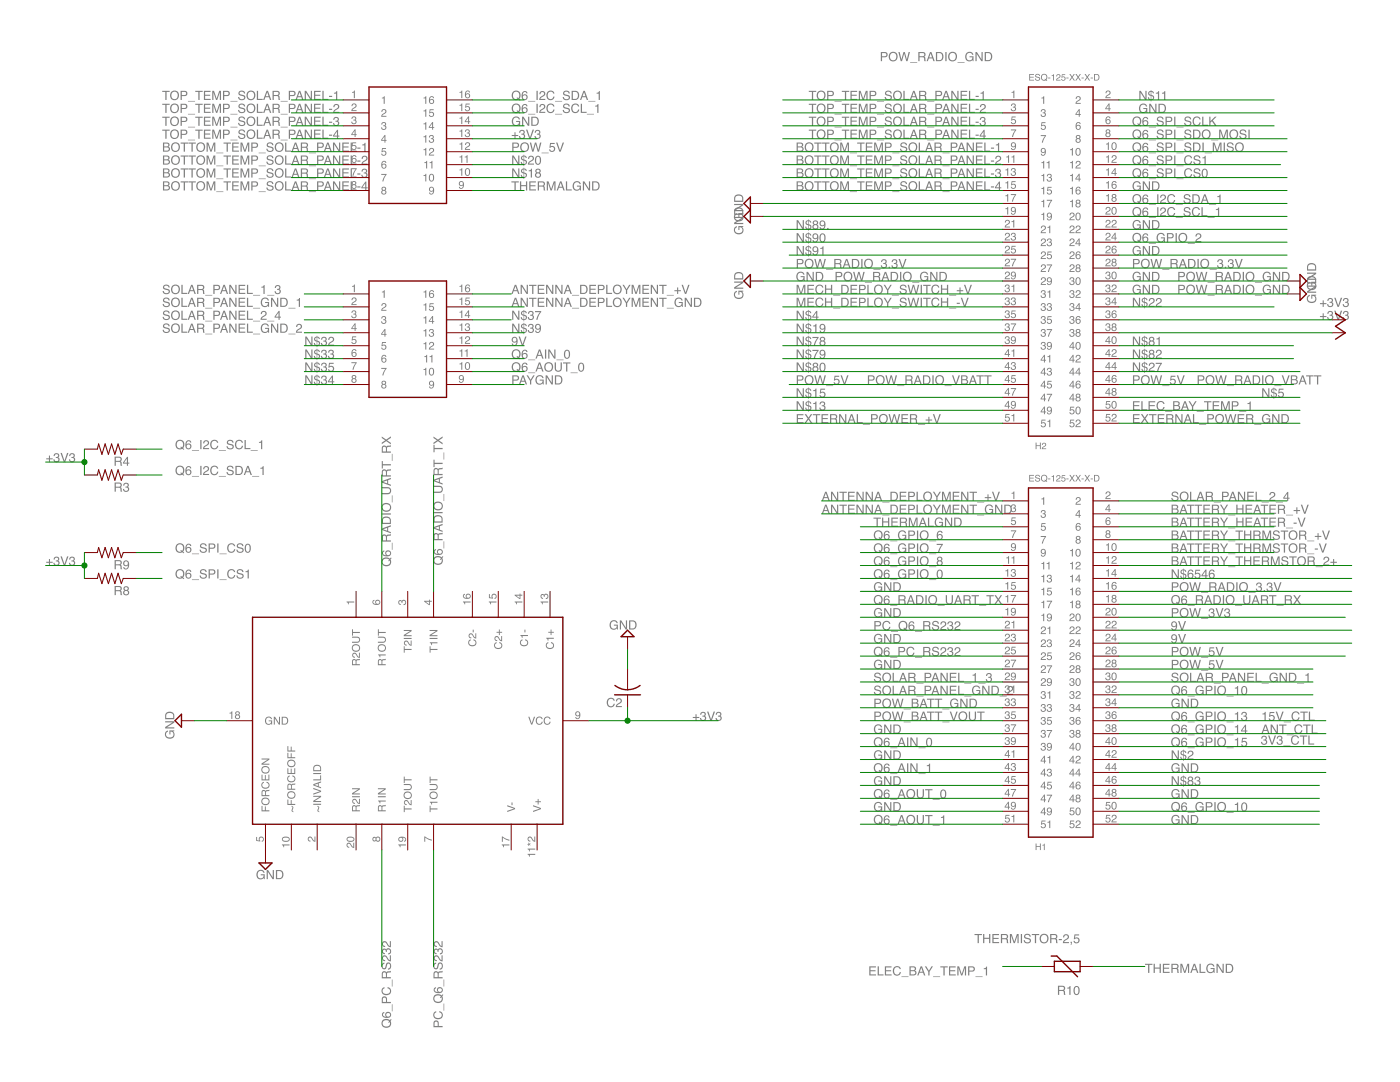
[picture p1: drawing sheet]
<svg xmlns="http://www.w3.org/2000/svg" width="279mm" height="216mm" viewBox="0 0 279 216" stroke-linecap="round" stroke-linejoin="round" font-family="sans-serif">
<g fill="#808080">
<path d="M33.1 145.9l.4-.1v.2a.63 .63 0 0 0-.3 .9 .63 .63 0 0 0 .9 .2 .58 .58 0 0 0 .5-.6 .58 .58 0 0 0-.6-.5v.5h-.2v-.8h1v.2l-.3 .1a.89 .89 0 0 1 .1 1.2 .89 .89 0 0 1-1.2 .1 .88 .88 0 0 1-.3-1.4zM33 143.9h1.8v.3l-1.5 .9h1.5v.3h-1.8v-.3l1.4-1h-1.4zM33.4 142.4l-.2 .2v.7h1.4v-.5a.74 .74 0 0 0-1.2-.4zM33.2 142.2a.99 .99 0 0 1 1.6 .6v.7h-1.8v-1z" fill-rule="evenodd"/>
<path d="M51.4 173.8a.81 .81 0 0 1 1.4 .4h-.2a.63 .63 0 0 0-.9-.3 .63 .63 0 0 0-.3 .8 .58 .58 0 0 0 .7 .6 .58 .58 0 0 0 .5-.6h-.6v-.2h.8v.9h-.1l-.1-.2a.89 .89 0 0 1-1.2 0 .89 .89 0 0 1-.1-1.2zM53.2 173.6h.3l.9 1.5v-1.5h.3v1.8h-.3l-.9-1.4v1.4h-.3zM55.3 173.8v1.4h.5a.71 .71 0 0 0 .5-.7 .71 .71 0 0 0-.6-.7zM55.1 173.6h.7a.92 .92 0 0 1 .8 .9 .92 .92 0 0 1-.8 .9h-.7z" fill-rule="evenodd"/>
<path d="M121.9 124a.81 .81 0 0 1 1.4 .3h-.3a.63 .63 0 0 0-.8-.3 .63 .63 0 0 0-.3 .9 .58 .58 0 0 0 .6 .5 .58 .58 0 0 0 .6-.6h-.6v-.2h.8v1h-.1l-.1-.2a.89 .89 0 0 1-1.2 0 .89 .89 0 0 1-.1-1.2zM123.7 123.8h.3l.9 1.5v-1.5h.2v1.8h-.2l-1-1.5v1.5h-.2zM125.8 124v1.4h.4a.71 .71 0 0 0 .6-.7 .71 .71 0 0 0-.6-.7zM125.5 123.8h.8a.92 .92 0 0 1 .7 .9 .92 .92 0 0 1-.7 .9h-.8z" fill-rule="evenodd"/>
<path d="M205.4 14.8h1v.1h-.8v.4h.7v.2h-.7v.4h.8v.2h-1zM206.7 14.8h.5l.3 .2 .1 .2h-.2a.3 .3 0 0 0-.3-.3 .3 .3 0 0 0-.3 .3 .52 .52 0 0 1 .6 .2 .52 .52 0 0 1 0 .6l-.3 .1a.45 .45 0 0 1-.6-.4h.2a.34 .34 0 0 0 .4 .3 .34 .34 0 0 0 .3-.4 .54 .54 0 0 1-.6-.2 .54 .54 0 0 1-.1-.6zM208 14.8a.69 .69 0 0 1 .9 .2 .69 .69 0 0 1-.1 .9l.2 .2-.1 .1-.2-.2a.69 .69 0 0 1-.9-.2 .69 .69 0 0 1 .2-1zM208.1 15a.53 .53 0 0 0-.2 .7 .53 .53 0 0 0 .7 .2l-.2-.1 .1-.1 .2 .1a.52 .52 0 0 0 .1-.7 .52 .52 0 0 0-.7-.1zM209.2 15.5h.4v.2h-.4zM209.9 15.1l.4-.3v1.3h-.1v-.9h-.3zM210.9 14.9a.44 .44 0 0 1 .7 .2 .44 .44 0 0 1-.4 .6l-.3 .2h.7v.2h-.8l.1-.4a.45 .45 0 0 0 .5-.3 .45 .45 0 0 0-.1-.4h-.2l-.1 .3h-.2zM211.9 14.8h.7v.2h-.6v.3a.44 .44 0 0 1 .6 .2 .44 .44 0 0 1-.3 .6 .44 .44 0 0 1-.5-.3h.1a.28 .28 0 0 0 .5 .1 .28 .28 0 0 0 0-.4 .28 .28 0 0 0-.4 0h-.2zM212.8 15.5h.5v.2h-.5zM213.4 14.8h.2l.4 .5 .3-.5h.2l-.4 .6 .4 .7h-.2l-.3-.6-.4 .6h-.2l.4-.7zM214.6 14.8h.2l.4 .5 .3-.5h.2l-.4 .6 .4 .7h-.2l-.3-.6-.4 .6h-.2l.5-.7zM215.8 15.5h.5v.2h-.5zM216.4 14.8h.3l.3 .5 .3-.5h.2l-.4 .6 .5 .7h-.3l-.3-.6-.4 .6h-.2l.5-.7zM217.7 15.5h.4v.2h-.4zM218.5 14.9v1h.4a.52 .52 0 0 0 .3-.5 .52 .52 0 0 0-.4-.5zM218.3 14.8h.6a.66 .66 0 0 1 .5 .6 .66 .66 0 0 1-.5 .7h-.6z" fill-rule="evenodd"/>
<path d="M205.4 94.8h1v.1h-.8v.4h.7v.2h-.7v.4h.8v.2h-1zM206.7 94.8h.5l.3 .2 .1 .2h-.2a.3 .3 0 0 0-.3-.3 .3 .3 0 0 0-.3 .3 .52 .52 0 0 1 .6 .2 .52 .52 0 0 1 0 .6l-.3 .1a.45 .45 0 0 1-.6-.4h.2a.34 .34 0 0 0 .4 .3 .34 .34 0 0 0 .3-.4 .54 .54 0 0 1-.6-.2 .54 .54 0 0 1-.1-.6zM208 94.8a.69 .69 0 0 1 .9 .2 .69 .69 0 0 1-.1 .9l.2 .2-.1 .1-.2-.2a.69 .69 0 0 1-.9-.2 .69 .69 0 0 1 .2-1zM208.1 95a.53 .53 0 0 0-.2 .7 .53 .53 0 0 0 .7 .2l-.2-.1 .1-.1 .2 .1a.52 .52 0 0 0 .1-.7 .52 .52 0 0 0-.7-.1zM209.2 95.5h.4v.1h-.4zM209.9 95l.4-.2v1.3h-.1v-.9h-.3zM210.9 94.9a.44 .44 0 0 1 .7 .2 .44 .44 0 0 1-.4 .6l-.3 .2h.7v.2h-.8l.1-.4a.45 .45 0 0 0 .5-.3 .45 .45 0 0 0-.1-.4h-.2l-.1 .3h-.2zM211.9 94.8h.7v.2h-.6v.3a.44 .44 0 0 1 .6 .2 .44 .44 0 0 1-.3 .6 .44 .44 0 0 1-.5-.4h.1a.28 .28 0 0 0 .5 .2 .28 .28 0 0 0 0-.5 .28 .28 0 0 0-.4 .1h-.2zM212.8 95.5h.5v.1h-.5zM213.4 94.8h.2l.4 .5 .3-.5h.2l-.4 .6 .4 .7h-.2l-.3-.6-.4 .6h-.2l.4-.7zM214.6 94.8h.2l.4 .5 .3-.5h.2l-.4 .6 .4 .7h-.2l-.3-.6-.4 .6h-.2l.5-.7zM215.8 95.5h.5v.1h-.5zM216.4 94.8h.3l.3 .5 .3-.5h.2l-.4 .6 .5 .7h-.3l-.3-.6-.4 .6h-.2l.5-.7zM217.7 95.5h.4v.1h-.4zM218.5 94.9v1h.4a.52 .52 0 0 0 .3-.5 .52 .52 0 0 0-.4-.5zM218.3 94.8h.6a.66 .66 0 0 1 .5 .6 .66 .66 0 0 1-.5 .7h-.6z" fill-rule="evenodd"/>
<path d="M146.7 42.7l.4-.2v.3a.63 .63 0 0 0-.3 .9 .63 .63 0 0 0 .8 .2 .58 .58 0 0 0 .6-.6 .58 .58 0 0 0-.6-.6v.6h-.2v-.8h.9v.2h-.2a.89 .89 0 0 1 .1 1.3 .89 .89 0 0 1-1.3 .1 .88 .88 0 0 1-.2-1.4zM146.5 40.7h1.8v.3l-1.4 .9h1.4v.2h-1.8v-.3l1.5-.9h-1.5zM146.9 39.2l-.2 .2v.6h1.4v-.4a.74 .74 0 0 0-1.2-.4zM146.8 39a.99 .99 0 0 1 1.5 .6v.7h-1.8v-1z" fill-rule="evenodd"/>
<path d="M146.7 45.3l.4-.2v.3a.63 .63 0 0 0-.3 .8 .63 .63 0 0 0 .8 .3 .58 .58 0 0 0 .6-.6 .58 .58 0 0 0-.6-.6v.6h-.2v-.8h.9v.2h-.2a.89 .89 0 0 1 .1 1.3 .89 .89 0 0 1-1.3 .1 .88 .88 0 0 1-.2-1.4zM146.5 43.3h1.8v.2l-1.4 1h1.4v.2h-1.8v-.3l1.5-.9h-1.5zM146.9 41.8l-.2 .2v.6h1.4v-.4a.74 .74 0 0 0-1.2-.4zM146.8 41.6a.99 .99 0 0 1 1.5 .5v.8h-1.8v-1z" fill-rule="evenodd"/>
<path d="M264 62.5h.2v.6h.5v.2h-.5v.5h-.2v-.5h-.6v-.2h.6zM265.1 62.1a.51 .51 0 0 1 .7 0 .51 .51 0 0 1 0 .8 .59 .59 0 0 1-.1 1 .59 .59 0 0 1-.8-.6h.2a.36 .36 0 0 0 .5 .4 .36 .36 0 0 0 0-.7h-.3l.1-.2a.29 .29 0 0 0 .4-.2 .29 .29 0 0 0-.3-.4l-.3 .2-.1 .2h-.2zM266.3 62h.2l.6 1.5 .5-1.5h.3l-.7 1.8h-.3zM268.2 62.1a.51 .51 0 0 1 .8 0 .51 .51 0 0 1-.1 .8 .59 .59 0 0 1-.1 1 .59 .59 0 0 1-.8-.6h.2a.36 .36 0 0 0 .5 .4 .36 .36 0 0 0 0-.7h-.3l.1-.2a.29 .29 0 0 0 .4-.2 .29 .29 0 0 0-.3-.4l-.3 .2-.1 .2h-.2z" fill-rule="evenodd"/>
<path d="M264 59.9h.2v.6h.5v.2h-.5v.5h-.2v-.5h-.6v-.2h.6zM265.1 59.6a.51 .51 0 0 1 .7-.1 .51 .51 0 0 1 0 .8 .59 .59 0 0 1-.1 1 .59 .59 0 0 1-.8-.6h.2a.36 .36 0 0 0 .5 .4 .36 .36 0 0 0 0-.7h-.3l.1-.2a.29 .29 0 0 0 .4-.2 .29 .29 0 0 0-.3-.3l-.3 .1-.1 .2h-.2zM266.3 59.4h.2l.6 1.6 .5-1.6h.3l-.7 1.8h-.3zM268.2 59.6a.51 .51 0 0 1 .8-.1 .51 .51 0 0 1-.1 .8 .59 .59 0 0 1-.1 1 .59 .59 0 0 1-.8-.6h.2a.36 .36 0 0 0 .5 .4 .36 .36 0 0 0 0-.7h-.3l.1-.2a.29 .29 0 0 0 .4-.2 .29 .29 0 0 0-.3-.3l-.3 .1-.1 .2h-.2z" fill-rule="evenodd"/>
<path d="M146.7 58.2l.4-.2v.3a.63 .63 0 0 0-.3 .8 .63 .63 0 0 0 .8 .3 .58 .58 0 0 0 .6-.6 .58 .58 0 0 0-.6-.6v.6h-.2v-.8h.9v.2h-.2a.89 .89 0 0 1 .1 1.3 .89 .89 0 0 1-1.3 .1 .88 .88 0 0 1-.2-1.4zM146.5 56.2h1.8v.3l-1.4 .9h1.4v.2h-1.8v-.3l1.5-.9h-1.5zM146.9 54.7l-.2 .2v.6h1.4v-.4a.74 .74 0 0 0-1.2-.4zM146.8 54.5a.99 .99 0 0 1 1.5 .5v.8h-1.8v-1z" fill-rule="evenodd"/>
<path d="M261 59l.4-.2v.3a.63 .63 0 0 0-.3 .8 .63 .63 0 0 0 .9 .3 .58 .58 0 0 0 .5-.6 .58 .58 0 0 0-.6-.6v.6h-.2v-.8h1v.2h-.3a.89 .89 0 0 1 .1 1.3 .89 .89 0 0 1-1.2 .1 .88 .88 0 0 1-.3-1.4zM260.8 57h1.9v.3l-1.5 .9h1.5v.2h-1.9v-.3l1.5-.9h-1.5zM261.2 55.5l-.1 .2v.6h1.4v-.4a.74 .74 0 0 0-1.3-.4zM261.1 55.3a.99 .99 0 0 1 1.6 .5v.8h-1.9l.1-1z" fill-rule="evenodd"/>
<path d="M261 56.4l.4-.1v.2a.63 .63 0 0 0-.3 .9 .63 .63 0 0 0 .9 .2 .58 .58 0 0 0 .5-.6 .58 .58 0 0 0-.6-.5v.5h-.2v-.8h1v.2h-.3a.89 .89 0 0 1 .1 1.3 .89 .89 0 0 1-1.2 .1 .88 .88 0 0 1-.3-1.4zM260.8 54.4h1.9v.3l-1.5 .9h1.5v.2h-1.9v-.3l1.5-.9h-1.5zM261.2 52.9l-.1 .2v.6h1.4v-.4a.74 .74 0 0 0-1.3-.4zM261.1 52.7a.99 .99 0 0 1 1.6 .6v.7h-1.9l.1-1z" fill-rule="evenodd"/>
<path d="M194.5 186.4h1.5v.2h-.6v1.6h-.3v-1.6h-.6zM196.2 186.4h.2v.7h1v-.7h.2v1.8h-.2v-.9h-1v.9h-.2zM198 186.4h1.4v.2h-1.1v.5h1v.3h-1v.6h1.1v.2h-1.4zM200 186.6v.6h.6a.31 .31 0 0 0 .3-.3 .31 .31 0 0 0-.3-.3zM199.7 186.4a1.57 1.57 0 0 1 1.4 .1l.1 .5-.3 .3 .2 .2 .2 .7h-.3l-.1-.7-.3-.1h-.6v.8h-.3zM201.5 186.4h.4l.5 1.5 .5-1.5h.4v1.8h-.2v-1.5l-.6 1.5h-.2l-.5-1.5v1.5h-.3zM203.7 186.4h.3v1.8h-.3zM204.5 186.5a.72 .72 0 0 1 1.2 .4h-.2a.42 .42 0 0 0-.5-.4 .42 .42 0 0 0-.4 .5 1.47 1.47 0 0 1 1.2 .7 .74 .74 0 0 1-.8 .5 .74 .74 0 0 1-.7-.6h.2a.48 .48 0 0 0 .5 .4 .48 .48 0 0 0 .5-.4l-.4-.2a.56 .56 0 0 1-.6-.2 .56 .56 0 0 1 0-.7zM205.9 186.4h1.5v.2h-.6v1.6h-.3v-1.6h-.6zM207.5 187.3a.95 .95 0 0 1 1.9 0 .95 .95 0 0 1-1.9 0zM207.9 186.7a.69 .69 0 0 0 0 1.1 .69 .69 0 0 0 1-.2 .68 .68 0 0 0-.1-.9 .68 .68 0 0 0-.9 0zM209.8 186.6v.6h.6a.31 .31 0 0 0 .4-.3 .31 .31 0 0 0-.4-.3zM209.6 186.4a1.57 1.57 0 0 1 1.3 .1l.1 .5-.2 .3 .2 .2 .1 .7h-.3l-.1-.7-.3-.1h-.6v.8h-.2zM211.3 187.4h.6v.2h-.6zM212.4 186.5a.61 .61 0 0 1 .9 .3 .61 .61 0 0 1-.6 .8l-.3 .4h.9v.2h-1.2a1.5 1.5 0 0 1 1-1.1 .36 .36 0 0 0-.4-.5 .36 .36 0 0 0-.3 .4h-.2zM213.7 187.9h.2v.5l-.2 .2 .1-.4h-.1zM214.4 186.4h1v.3h-.8l-.1 .5a.62 .62 0 0 1 .9 .2 .62 .62 0 0 1-.4 .9 .62 .62 0 0 1-.8-.6h.3a.39 .39 0 0 0 .5 .2 .39 .39 0 0 0 .1-.6 .39 .39 0 0 0-.6 .1h-.2z" fill-rule="evenodd"/>
<path d="M175.8 10.4h.8a.53 .53 0 0 1 .5 .5 .53 .53 0 0 1-.5 .5h-.6v.8h-.2zM176 10.6v.6h.5a.32 .32 0 0 0 .4-.3 .32 .32 0 0 0-.4-.3zM177.4 11.3a.94 .94 0 0 1 1.8 0 .94 .94 0 0 1-1.8 0zM177.8 10.7a.69 .69 0 0 0 0 1.1 .69 .69 0 0 0 1-.2 .68 .68 0 0 0-.1-.9 .68 .68 0 0 0-.9 0zM179.3 10.4h.3l.3 1.5 .4-1.5h.3l.4 1.5 .3-1.5h.3l-.5 1.8h-.2l-.5-1.5-.4 1.5h-.2zM181.6 12.4h1.4v.1h-1.4zM183.5 10.6v.6h.6a.31 .31 0 0 0 .4-.3 .31 .31 0 0 0-.4-.3zM183.3 10.4a1.57 1.57 0 0 1 1.3 .1l.1 .5-.2 .3 .2 .2 .1 .7h-.3l-.1-.7-.3-.1h-.6v.8h-.2zM185.7 10.7l-.3 .8h.6zM185.6 10.4h.3l.6 1.8h-.2l-.2-.5h-.7l-.2 .5h-.3zM187 10.6v1.4h.5a.71 .71 0 0 0 .5-.7 .71 .71 0 0 0-.5-.7zM186.8 10.4h.7a.92 .92 0 0 1 .8 .9 .92 .92 0 0 1-.8 .9h-.7zM188.7 10.4h.2v1.8h-.2zM189.2 11.3a.95 .95 0 0 1 1.9 0 .95 .95 0 0 1-1.9 0zM189.6 10.7a.69 .69 0 0 0 0 1.1 .69 .69 0 0 0 1.1-.2 .68 .68 0 0 0-.1-.9 .68 .68 0 0 0-1 0zM191.1 12.4h1.4v.1h-1.4zM192.9 10.6a.81 .81 0 0 1 1.4 .3h-.3a.63 .63 0 0 0-.8-.3 .63 .63 0 0 0-.3 .9 .58 .58 0 0 0 .6 .5 .58 .58 0 0 0 .6-.6h-.6v-.2h.8v1h-.2v-.2a.89 .89 0 0 1-1.3 0 .89 .89 0 0 1-.1-1.2zM194.7 10.4h.3l.9 1.5v-1.5h.2v1.8h-.3l-.9-1.5v1.5h-.2zM196.8 10.6v1.4h.4a.71 .71 0 0 0 .6-.7 .71 .71 0 0 0-.6-.7zM196.5 10.4h.8a.92 .92 0 0 1 .7 .9 .92 .92 0 0 1-.7 .9h-.8z" fill-rule="evenodd"/>
<path d="M251.9 142.4l.7-.4v1.8h-.2v-1.2h-.5zM253.4 142.1h.9v.2h-.7l-.1 .5a.62 .62 0 0 1 .9 .3 .62 .62 0 0 1-.4 .8 .62 .62 0 0 1-.8-.5h.2a.39 .39 0 0 0 .6 .1 .39 .39 0 0 0 .1-.6 .39 .39 0 0 0-.6 .1h-.2zM254.6 142h.3l.5 1.5 .5-1.5h.3l-.7 1.8h-.2zM256.2 144h1.4v.1h-1.4zM258 142.2a.79 .79 0 0 1 .7-.3 .79 .79 0 0 1 .6 .6h-.2a.62 .62 0 0 0-.9-.3 .62 .62 0 0 0-.2 .9 .56 .56 0 0 0 .6 .5 .56 .56 0 0 0 .5-.5h.3a.85 .85 0 0 1-1.1 .7 .85 .85 0 0 1-.5-1.2zM259.5 142h1.5v.2h-.6v1.6h-.3v-1.6h-.6zM261.2 142h.3v1.6h.9v.2h-1.2z" fill-rule="evenodd"/>
<path d="M252.6 144.8l-.3 .8h.5zM252.4 144.6h.3l.7 1.8h-.3l-.2-.6h-.7l-.2 .6h-.3zM253.6 144.6h.3l.9 1.4v-1.4h.2v1.8h-.2l-1-1.5v1.5h-.2zM255.3 144.6h1.4v.2h-.6v1.6h-.2v-1.6h-.6zM256.8 146.6h1.4v.1h-1.4zM258.5 144.8a.79 .79 0 0 1 .8-.3 .79 .79 0 0 1 .6 .6h-.2a.62 .62 0 0 0-.9-.3 .62 .62 0 0 0-.2 .9 .56 .56 0 0 0 .5 .5 .56 .56 0 0 0 .6-.5h.2a.85 .85 0 0 1-1.1 .7 .85 .85 0 0 1-.5-1.2zM260.1 144.6h1.4v.2h-.6v1.6h-.2v-1.6h-.6zM261.8 144.6h.2v1.6h.9v.2h-1.1z" fill-rule="evenodd"/>
<path d="M234 98.2a.72 .72 0 0 1 1.2 .5h-.3a.42 .42 0 0 0-.4-.4 .42 .42 0 0 0-.4 .4 1.47 1.47 0 0 1 1.1 .7 .74 .74 0 0 1-.7 .6 .74 .74 0 0 1-.7-.6h.2a.48 .48 0 0 0 .5 .4 .48 .48 0 0 0 .4-.5l-.3-.1a.56 .56 0 0 1-.7-.3 .56 .56 0 0 1 .1-.7zM235.4 99a.95 .95 0 0 1 1.9 0 .95 .95 0 0 1-1.9 0zM235.9 98.5a.69 .69 0 0 0-.1 1.1 .69 .69 0 0 0 1.1-.2 .68 .68 0 0 0-.1-.9 .68 .68 0 0 0-.9 0zM237.5 98.1h.2v1.6h1v.2h-1.2zM239.6 98.4l-.3 .8h.5zM239.4 98.1h.3l.7 1.8h-.3l-.2-.5h-.7l-.2 .5h-.2zM240.9 98.3v.7h.6a.31 .31 0 0 0 .3-.3 .31 .31 0 0 0-.3-.4zM240.6 98.1a1.57 1.57 0 0 1 1.4 .2l.1 .5-.3 .2 .2 .3 .1 .6h-.3v-.6l-.4-.1h-.5v.7h-.3zM242.2 100.1h1.5v.2h-1.5zM243.9 98.1h.8a.53 .53 0 0 1 .5 .5 .53 .53 0 0 1-.5 .6h-.6v.7h-.2zM244.1 98.3v.7h.5a.32 .32 0 0 0 .4-.4 .32 .32 0 0 0-.4-.3zM246 98.4l-.3 .8h.6zM245.9 98.1h.3l.6 1.8h-.2l-.2-.5h-.7l-.2 .5h-.3zM247.1 98.1h.2l1 1.5v-1.5h.2v1.8h-.3l-.9-1.4v1.4h-.2zM248.9 98.1h1.3v.2h-1v.6h1v.2h-1v.6h1.1v.2h-1.4zM250.6 98.1h.2v1.6h.9v.2h-1.1zM251.8 100.1h1.4v.2h-1.4zM253.5 98.3a.61 .61 0 0 1 1 .3 .61 .61 0 0 1-.6 .8l-.4 .3h1v.2h-1.2a1.5 1.5 0 0 1 .9-1.1 .36 .36 0 0 0-.3-.4 .36 .36 0 0 0-.3 .4h-.3zM254.6 100.1h1.4v.2h-1.4zM256.9 98.5l-.6 .8h.6zM256.9 98.2h.2v1.1h.3v.2h-.3v.4h-.2v-.4h-.8v-.2z" fill-rule="evenodd"/>
<path d="M251.9 146.9a.51 .51 0 0 1 .8 0 .51 .51 0 0 1-.1 .7 .59 .59 0 0 1-.1 1 .59 .59 0 0 1-.8-.6h.2a.36 .36 0 0 0 .5 .4 .36 .36 0 0 0 0-.6h-.3l.1-.2a.29 .29 0 0 0 .4-.2 .29 .29 0 0 0-.3-.4l-.3 .2-.1 .2h-.2zM253.1 146.8h.2l.6 1.5 .5-1.5h.3l-.7 1.8h-.3zM255 146.9a.51 .51 0 0 1 .8 0 .51 .51 0 0 1-.1 .7 .59 .59 0 0 1-.1 1 .59 .59 0 0 1-.8-.6h.2a.36 .36 0 0 0 .5 .4 .36 .36 0 0 0 0-.6h-.2v-.2a.29 .29 0 0 0 .4-.2 .29 .29 0 0 0-.3-.4l-.3 .2-.1 .2h-.2zM256.1 148.8h1.4v.1h-1.4zM257.9 147a.79 .79 0 0 1 .7-.3 .79 .79 0 0 1 .6 .6h-.2a.62 .62 0 0 0-.9-.3 .62 .62 0 0 0-.2 .9 .56 .56 0 0 0 .6 .5 .56 .56 0 0 0 .5-.5h.3a.85 .85 0 0 1-1.1 .7 .85 .85 0 0 1-.5-1.2zM259.4 146.8h1.5v.2h-.6v1.6h-.3v-1.6h-.6zM261.1 146.8h.3v1.6h.9v.2h-1.2z" fill-rule="evenodd"/>
<path d="M166.8 54.3h.8a.53 .53 0 0 1 .5 .5 .53 .53 0 0 1-.5 .5h-.6v.8h-.2zM167 54.5v.6h.5a.32 .32 0 0 0 .4-.3 .32 .32 0 0 0-.4-.3zM168.3 55.2a.95 .95 0 0 1 1.9 0 .95 .95 0 0 1-1.9 0zM168.8 54.6a.69 .69 0 0 0-.1 1.1 .69 .69 0 0 0 1.1-.2 .68 .68 0 0 0-.1-.9 .68 .68 0 0 0-.9 0zM170.3 54.3h.2l.4 1.4 .4-1.4h.2l.5 1.4 .3-1.4h.3l-.5 1.8h-.3l-.4-1.5-.4 1.5h-.3zM172.6 56.3h1.4v.1h-1.4zM174.5 54.5v.6h.6a.31 .31 0 0 0 .3-.3 .31 .31 0 0 0-.3-.3zM174.2 54.3a1.57 1.57 0 0 1 1.4 .1l.1 .5-.3 .3 .2 .2 .2 .7h-.4v-.7l-.4-.1h-.5v.8h-.3zM176.7 54.5l-.3 .8h.6zM176.6 54.3h.3l.6 1.8h-.3l-.1-.6h-.8l-.2 .6h-.2zM178 54.5v1.4h.4a.71 .71 0 0 0 .6-.7 .71 .71 0 0 0-.6-.7zM177.7 54.3h.8a.92 .92 0 0 1 .8 .9 .92 .92 0 0 1-.8 .9h-.8zM179.6 54.3h.3v1.8h-.3zM180.2 55.2a.95 .95 0 0 1 1.9 0 .95 .95 0 0 1-1.9 0zM180.6 54.6a.69 .69 0 0 0 0 1.1 .69 .69 0 0 0 1-.2 .68 .68 0 0 0-.1-.9 .68 .68 0 0 0-.9 0zM182.1 56.3h1.4v.1h-1.4zM183.8 54.5a.81 .81 0 0 1 1.4 .3h-.2a.63 .63 0 0 0-.9-.3 .63 .63 0 0 0-.2 .9 .58 .58 0 0 0 .6 .5 .58 .58 0 0 0 .5-.6h-.5v-.2h.8v1h-.2l-.1-.3a.89 .89 0 0 1-1.2 .1 .89 .89 0 0 1-.1-1.2zM185.6 54.3h.3l1 1.4v-1.4h.2v1.8h-.3l-.9-1.5v1.5h-.3zM187.7 54.5v1.4h.5a.71 .71 0 0 0 .5-.7 .71 .71 0 0 0-.5-.7zM187.5 54.3h.7a.92 .92 0 0 1 .8 .9 .92 .92 0 0 1-.8 .9h-.7z" fill-rule="evenodd"/>
<path d="M173.2 74.9h.8a.53 .53 0 0 1 .6 .5 .53 .53 0 0 1-.6 .5h-.5v.8h-.3zM173.5 75.1v.6h.4a.32 .32 0 0 0 .4-.3 .32 .32 0 0 0-.4-.3zM174.8 75.8a.95 .95 0 0 1 1.9 0 .95 .95 0 0 1-1.9 0zM175.2 75.3a.69 .69 0 0 0 0 1 .69 .69 0 0 0 1-.1 .68 .68 0 0 0-.1-.9 .68 .68 0 0 0-.9 0zM176.7 74.9h.3l.3 1.5 .4-1.5h.3l.4 1.5 .3-1.5h.3l-.5 1.8h-.2l-.4-1.5-.5 1.5h-.2zM179.1 76.9h1.4v.1h-1.4zM180.9 75.1v.6h.6a.31 .31 0 0 0 .4-.3 .31 .31 0 0 0-.4-.3zM180.7 74.9a1.57 1.57 0 0 1 1.3 .2l.1 .4-.2 .3 .2 .2 .1 .7h-.3l-.1-.6-.3-.2h-.6v.8h-.2zM183.2 75.2l-.3 .8h.5zM183 74.9h.3l.7 1.8h-.3l-.2-.5h-.7l-.2 .5h-.3zM184.4 75.1v1.4h.5a.71 .71 0 0 0 .6-.7 .71 .71 0 0 0-.6-.7zM184.2 74.9h.7a.92 .92 0 0 1 .8 .9 .92 .92 0 0 1-.8 .9h-.7zM186.1 74.9h.2v1.8h-.2zM186.6 75.8a.95 .95 0 0 1 1.9 0 .95 .95 0 0 1-1.9 0zM187.1 75.3a.69 .69 0 0 0-.1 1 .69 .69 0 0 0 1.1-.1 .68 .68 0 0 0-.1-.9 .68 .68 0 0 0-.9 0zM188.5 76.9h1.4v.1h-1.4zM190 74.9h.3l.5 1.5 .5-1.5h.3l-.7 1.8h-.2zM192 75.1v.6h.5a.3 .3 0 0 0 .4-.3 .3 .3 0 0 0-.4-.3zM192 75.9v.6l.9-.1 .1-.2-.2-.3zM191.8 74.9h.8a.45 .45 0 0 1 .5 .3 .45 .45 0 0 1-.2 .5 .51 .51 0 0 1 .3 .7 .51 .51 0 0 1-.6 .3h-.8zM194.2 75.2l-.3 .8h.5zM194 74.9h.3l.7 1.8h-.3l-.2-.5h-.7l-.2 .5h-.3zM194.9 74.9h1.4v.2h-.6v1.6h-.2v-1.6h-.6zM196.4 74.9h1.5v.2h-.6v1.6h-.3v-1.6h-.6z" fill-rule="evenodd"/>
<path d="M239 74.9h.8a.53 .53 0 0 1 .6 .5 .53 .53 0 0 1-.6 .5h-.5v.8h-.3zM239.3 75.1v.6h.5a.32 .32 0 0 0 .3-.3 .32 .32 0 0 0-.3-.3zM240.6 75.8a.95 .95 0 0 1 1.9 0 .95 .95 0 0 1-1.9 0zM241 75.3a.69 .69 0 0 0 0 1 .69 .69 0 0 0 1-.1 .68 .68 0 0 0-.1-.9 .68 .68 0 0 0-.9 0zM242.5 74.9h.3l.3 1.5 .4-1.5h.3l.4 1.5 .4-1.5h.2l-.5 1.8h-.2l-.4-1.5-.5 1.5h-.2zM244.9 76.9h1.4v.1h-1.4zM246.7 75.1v.6h.6a.31 .31 0 0 0 .4-.3 .31 .31 0 0 0-.4-.3zM246.5 74.9a1.57 1.57 0 0 1 1.3 .2l.1 .4-.2 .3 .2 .2 .1 .7h-.3l-.1-.6-.3-.2h-.6v.8h-.2zM249 75.2l-.3 .8h.5zM248.8 74.9h.3l.7 1.8h-.3l-.2-.5h-.7l-.2 .5h-.3zM250.3 75.1v1.4h.4a.71 .71 0 0 0 .6-.7 .71 .71 0 0 0-.6-.7zM250 74.9h.7a.92 .92 0 0 1 .8 .9 .92 .92 0 0 1-.8 .9h-.7zM251.9 74.9h.2v1.8h-.2zM252.4 75.8a.95 .95 0 0 1 1.9 0 .95 .95 0 0 1-1.9 0zM252.9 75.3a.69 .69 0 0 0-.1 1 .69 .69 0 0 0 1.1-.1 .68 .68 0 0 0-.1-.9 .68 .68 0 0 0-.9 0zM254.3 76.9h1.4v.1h-1.4zM255.8 74.9h.3l.5 1.5 .5-1.5h.3l-.7 1.8h-.2zM257.9 75.1v.6h.4a.3 .3 0 0 0 .4-.3 .3 .3 0 0 0-.4-.3zM257.9 75.9v.6l.8-.1 .1-.2-.2-.3zM257.6 74.9h.8a.45 .45 0 0 1 .5 .3 .45 .45 0 0 1-.2 .5 .51 .51 0 0 1 .3 .7 .51 .51 0 0 1-.6 .3h-.8zM260 75.2l-.3 .8h.5zM259.8 74.9h.3l.7 1.8h-.3l-.2-.5h-.7l-.2 .5h-.2zM260.7 74.9h1.4v.2h-.6v1.6h-.2v-1.6h-.6zM262.2 74.9h1.5v.2h-.6v1.6h-.3v-1.6h-.6z" fill-rule="evenodd"/>
<path d="M235.1 54.3h.9a.53 .53 0 0 1 .5 .5 .53 .53 0 0 1-.5 .5h-.6v.8h-.3zM235.4 54.5v.6h.5a.32 .32 0 0 0 .4-.3 .32 .32 0 0 0-.4-.3zM236.7 55.2a.95 .95 0 0 1 1.9 0 .95 .95 0 0 1-1.9 0zM237.2 54.6a.69 .69 0 0 0-.1 1.1 .69 .69 0 0 0 1.1-.2 .68 .68 0 0 0-.1-.9 .68 .68 0 0 0-.9 0zM238.6 54.3h.3l.4 1.4 .4-1.4h.2l.4 1.4 .4-1.4h.3l-.5 1.8h-.3l-.4-1.5-.4 1.5h-.3zM241 56.3h1.4v.1h-1.4zM242.9 54.5v.6h.5a.31 .31 0 0 0 .4-.3 .31 .31 0 0 0-.3-.3zM242.6 54.3a1.57 1.57 0 0 1 1.4 .1l.1 .5-.3 .3 .2 .2 .1 .7h-.3v-.7l-.4-.1h-.5v.8h-.3zM245.1 54.5l-.3 .8h.6zM245 54.3h.2l.7 1.8h-.3l-.2-.6h-.7l-.2 .6h-.2zM246.4 54.5v1.4h.4a.71 .71 0 0 0 .6-.7 .71 .71 0 0 0-.6-.7zM246.1 54.3h.8a.92 .92 0 0 1 .7 .9 .92 .92 0 0 1-.7 .9h-.8zM248 54.3h.3v1.8h-.3zM248.6 55.2a.94 .94 0 0 1 1.8 0 .94 .94 0 0 1-1.8 0zM249 54.6a.69 .69 0 0 0 0 1.1 .69 .69 0 0 0 1-.2 .68 .68 0 0 0-.1-.9 .68 .68 0 0 0-.9 0zM250.4 56.3h1.5v.1h-1.5zM252.2 54.5a.81 .81 0 0 1 1.4 .3h-.2a.63 .63 0 0 0-.9-.3 .63 .63 0 0 0-.2 .9 .58 .58 0 0 0 .6 .5 .58 .58 0 0 0 .5-.6h-.6v-.2h.8v1h-.1l-.1-.3a.89 .89 0 0 1-1.2 .1 .89 .89 0 0 1-.1-1.2zM254 54.3h.3l.9 1.4v-1.4h.3v1.8h-.3l-.9-1.5v1.5h-.3zM256.1 54.5v1.4h.5a.71 .71 0 0 0 .5-.7 .71 .71 0 0 0-.5-.7zM255.9 54.3h.7a.92 .92 0 0 1 .8 .9 .92 .92 0 0 1-.8 .9h-.7z" fill-rule="evenodd"/>
<path d="M235.1 56.8h.9a.53 .53 0 0 1 .5 .6 .53 .53 0 0 1-.5 .5h-.6v.8h-.3zM235.4 57v.7h.5a.32 .32 0 0 0 .4-.3 .32 .32 0 0 0-.4-.4zM236.7 57.8a.95 .95 0 0 1 1.9 0 .95 .95 0 0 1-1.9 0zM237.2 57.2a.69 .69 0 0 0-.1 1.1 .69 .69 0 0 0 1.1-.2 .68 .68 0 0 0-.1-.9 .68 .68 0 0 0-.9 0zM238.6 56.8h.3l.4 1.5 .4-1.5h.2l.4 1.5 .4-1.5h.3l-.5 1.9h-.3l-.4-1.6-.4 1.6h-.3zM241 58.8h1.4v.2h-1.4zM242.9 57v.7h.5a.31 .31 0 0 0 .4-.3 .31 .31 0 0 0-.3-.4zM242.6 56.8a1.57 1.57 0 0 1 1.4 .2l.1 .5-.3 .3 .2 .2 .1 .7h-.3v-.7l-.4-.1h-.5v.8h-.3zM245.1 57.1l-.3 .8h.6zM245 56.8h.2l.7 1.9h-.3l-.2-.6h-.7l-.2 .6h-.2zM246.4 57v1.4h.4a.71 .71 0 0 0 .6-.7 .71 .71 0 0 0-.6-.7zM246.1 56.8h.8a.92 .92 0 0 1 .7 .9 .92 .92 0 0 1-.7 1h-.8zM248 56.8h.3v1.9h-.3zM248.6 57.8a.94 .94 0 0 1 1.8 0 .94 .94 0 0 1-1.8 0zM249 57.2a.69 .69 0 0 0 0 1.1 .69 .69 0 0 0 1-.2 .68 .68 0 0 0-.1-.9 .68 .68 0 0 0-.9 0zM250.4 58.8h1.5v.2h-1.5zM252.2 57a.81 .81 0 0 1 1.4 .4h-.2a.63 .63 0 0 0-.9-.3 .63 .63 0 0 0-.2 .9 .58 .58 0 0 0 .6 .5 .58 .58 0 0 0 .5-.6h-.6v-.2h.8v1h-.1l-.1-.3a.89 .89 0 0 1-1.2 .1 .89 .89 0 0 1-.1-1.3zM254 56.8h.3l.9 1.5v-1.5h.3v1.9h-.3l-.9-1.5v1.5h-.3zM256.1 57v1.4h.5a.71 .71 0 0 0 .5-.7 .71 .71 0 0 0-.5-.7zM255.9 56.8h.7a.92 .92 0 0 1 .8 .9 .92 .92 0 0 1-.8 1h-.7z" fill-rule="evenodd"/>
<path d="M85.7 160.8h.2v.5h1.4v.2h-1.4v.5h-.2zM85.8 160h1.5v.2h-1.1v.3h-.1zM85.7 158.7a.81 .81 0 0 1 1.6 0 .81 .81 0 0 1-1.6 0zM85.9 158.7a.6 .6 0 0 0 1.2 0 .6 .6 0 0 0-1.2 0zM85.7 156.4h.9a.62 .62 0 0 1 .7 .6 .62 .62 0 0 1-.7 .7h-.9v-.3h1a.4 .4 0 0 0 .5-.4 .4 .4 0 0 0-.5-.4h-1zM85.7 155h.2v.5h1.4v.2h-1.4v.5h-.2z" fill-rule="evenodd"/>
<path d="M84.7 166.9l1.5 .6v.2l-1.3-.6v.9h-.2z" fill-rule="evenodd"/>
<path d="M80.6 160.8h.2v.5h1.3v.2h-1.3v.5h-.2zM80.8 159.8a.89 .89 0 0 1 1.1 .6l.1 .1v-.9h.1v1.1l-.4-.2a.6 .6 0 0 0-.8-.6l-.1 .4 .4 .2v.1h-.4l-.2-.3zM80.6 158.7a.81 .81 0 0 1 1.6 0 .81 .81 0 0 1-1.6 0zM80.7 158.7a.6 .6 0 0 0 1.2 0 .6 .6 0 0 0-1.2 0zM80.6 156.4h.9a.62 .62 0 0 1 .7 .6 .62 .62 0 0 1-.7 .7h-.9v-.3h.9a.4 .4 0 0 0 .5-.4 .4 .4 0 0 0-.5-.4h-.9zM80.6 155h.2v.5h1.3v.2h-1.3v.5h-.2z" fill-rule="evenodd"/>
<path d="M79.5 168.5h1.5v.2h-1.1v.4h-.1zM79.6 167.1a.84 .84 0 0 1 .9-.1 .84 .84 0 0 1 .5 .7l-.4 .3v-.2a.3 .3 0 0 0 .3-.4 .3 .3 0 0 0-.4-.2l-.2-.1a.51 .51 0 0 1 0 .8 .51 .51 0 0 1-.7-.1 .51 .51 0 0 1 0-.7zM79.7 167.5a.32 .32 0 0 0 .6 0 .32 .32 0 0 0-.6 0z" fill-rule="evenodd"/>
<path d="M75.7 160.9l-.1 .8h.5v-.7zM75.6 160.8l.4-.1 .2 .2 .2-.2 .6-.1v.3h-.6l-.1 .3v.5h.7v.2h-1.6zM75.5 159.7h1.5v.2h-1.1v.4h-.1zM75.4 158.9h1.6v.2h-1.6zM75.4 157.3h1.6v.2l-1.3 .8h1.3v.2h-1.6v-.2l1.3-.8h-1.3z" fill-rule="evenodd"/>
<path d="M74.5 167.5a.26 .26 0 0 0 .5 0 .26 .26 0 0 0-.5 0zM75.1 167.4a.31 .31 0 0 0 .6 0 .31 .31 0 0 0-.6 0zM74.4 167.1l.3-.1 .3 .2a.47 .47 0 0 1 .7-.1 .47 .47 0 0 1 0 .7 .47 .47 0 0 1-.7-.1 .44 .44 0 0 1-.6 .1 .44 .44 0 0 1 0-.7z" fill-rule="evenodd"/>
<path d="M70.6 160.9l-.2 .8h.6l-.1-.7zM70.4 160.8l.4-.1 .3 .2 .1-.2 .6-.1v.3h-.5l-.1 .3v.5h.6v.2h-1.5zM70.4 159.5a.89 .89 0 0 1 1.1 .7h.1v-.8h.2v1l-.5-.1a.6 .6 0 0 0-.8-.6v.4l.3 .1v.2l-.3-.1-.2-.2zM70.3 158.9h1.5v.2h-1.5zM70.3 157.3h1.5v.2l-1.2 .8h1.2v.2h-1.5v-.2l1.2-.8h-1.2z" fill-rule="evenodd"/>
<path d="M69.3 168.3a.89 .89 0 0 1 1.1 .6l.1 .1v-.8h.2v1l-.5-.2a.6 .6 0 0 0-.8-.6v.4l.3 .2v.2l-.3-.1-.2-.3zM69.3 167.1a.93 .93 0 0 1 1.4 .4 .85 .85 0 0 1-.8 .5 .85 .85 0 0 1-.7-.5zM69.4 167.3a.62 .62 0 0 0 .4 .5 .62 .62 0 0 0 .7-.2l.1-.1a.79 .79 0 0 0-1.2-.2z" fill-rule="evenodd"/>
<path d="M85.7 129h.2v.5h1.4v.2h-1.4v.5h-.2zM85.8 128.2h1.5v.2h-1.1v.3h-.1zM85.7 127.3h1.6v.2h-1.6zM85.7 125.7h1.6v.2l-1.3 .8h1.3v.2h-1.6v-.2l1.3-.8h-1.3z" fill-rule="evenodd"/>
<path d="M84.9 120.1l.7 .5v-.5zM84.6 119.9h1v-.2h.2v.2h.4v.2h-.4v.6h-.2l-1-.7z" fill-rule="evenodd"/>
<path d="M80.6 129h.2v.5h1.3v.2h-1.3v.5h-.2zM80.8 127.9a.89 .89 0 0 1 1.1 .7h.1v-.8h.1v1.1l-.4-.2a.6 .6 0 0 0-.8-.6l-.1 .4 .4 .1v.2h-.4l-.2-.3zM80.6 127.3h1.5v.2h-1.5zM80.6 125.7h1.5v.2l-1.2 .8h1.2v.2h-1.5v-.2l1.2-.8h-1.2z" fill-rule="evenodd"/>
<path d="M79.6 119.9l.3-.2 .3 .2a.5 .5 0 0 1 .9 .1 .5 .5 0 0 1-.6 .7v-.2a.31 .31 0 0 0 .4-.4 .31 .31 0 0 0-.6 0v.2h-.2a.25 .25 0 0 0-.2-.4 .25 .25 0 0 0-.2 .3l.1 .3h.2v.2l-.5-.3z" fill-rule="evenodd"/>
<path d="M75.7 131.7l-.1 .8h.5v-.7zM75.6 131.6l.4-.1 .2 .2 .2-.2 .6-.1v.3l-.6 .1-.1 .2v.5h.7v.2h-1.6zM75.5 130.6h1.5v.2h-1.1v.3h-.1zM75.4 129.3a.81 .81 0 0 1 1.6 0 .81 .81 0 0 1-1.6 0zM75.6 129.3a.6 .6 0 0 0 1.2 0 .6 .6 0 0 0-1.2 0zM75.4 127h.9a.62 .62 0 0 1 .7 .7 .62 .62 0 0 1-.7 .6h-.9v-.2h1a.4 .4 0 0 0 .4-.4 .4 .4 0 0 0-.4-.4h-1zM75.4 125.6h.2v.5h1.4v.2h-1.4v.5h-.2z" fill-rule="evenodd"/>
<path d="M74.5 119.8l.2-.1v.2a.32 .32 0 0 0-.2 .4 .32 .32 0 0 0 .4 .2h.2a.52 .52 0 0 1 .1-.8 .52 .52 0 0 1 .8 .4 .52 .52 0 0 1-.6 .6 .7 .7 0 0 1-.8-.1 .7 .7 0 0 1-.1-.8zM75 120.2a.35 .35 0 0 0 .7 0 .35 .35 0 0 0-.7 0z" fill-rule="evenodd"/>
<path d="M70.6 131.7l-.2 .8h.6l-.1-.7zM70.4 131.6l.4-.1 .3 .2 .1-.2 .6-.1v.3l-.5 .1-.2 .2v.5h.7v.2h-1.5zM70.4 130.4a.89 .89 0 0 1 1.1 .6l.1 .1v-.9h.2v1.1l-.5-.2a.6 .6 0 0 0-.8-.6v.4l.3 .2v.2l-.3-.1-.2-.3zM70.2 129.3a.85 .85 0 0 1 1.7 0 .85 .85 0 0 1-1.7 0zM70.4 129.3a.6 .6 0 0 0 1.2 0 .6 .6 0 0 0-1.2 0zM70.3 127h.8a.62 .62 0 0 1 .8 .7 .62 .62 0 0 1-.8 .6h-.8v-.2h.9a.4 .4 0 0 0 .5-.4 .4 .4 0 0 0-.5-.4h-.9zM70.3 125.6h.1v.5h1.4v.2h-1.4v.5h-.1z" fill-rule="evenodd"/>
<path d="M69.2 120h1.5v.2h-1.1v.4h-.1z" fill-rule="evenodd"/>
<path d="M109.1 128.3l.3-.2v.2a.53 .53 0 0 0-.2 .8 .53 .53 0 0 0 .7 .2 .48 .48 0 0 0 .5-.5 .48 .48 0 0 0-.4-.5v-.2a.75 .75 0 0 1 .5 1.1 .75 .75 0 0 1-1.2 .2l-.3-.4zM109 127.3h1.5v.2h-1v.3h-.2zM109.4 126.1h.5v-.5h.2v.5h.4v.2h-.4v.4h-.2v-.4h-.5z" fill-rule="evenodd"/>
<path d="M107.9 120h1.5v.2h-1.1v.4h-.1zM108 118.7l.3-.2 .3 .2a.5 .5 0 0 1 .8 .1 .5 .5 0 0 1-.5 .7v-.2a.31 .31 0 0 0 .4-.4 .31 .31 0 0 0-.6 0v.2h-.2a.25 .25 0 0 0-.2-.4 .25 .25 0 0 0-.3 .3l.2 .3h.2v.2l-.5-.3z" fill-rule="evenodd"/>
<path d="M103.9 127.8l.4-.2v.2a.53 .53 0 0 0-.3 .7 .53 .53 0 0 0 .8 .2 .48 .48 0 0 0 .4-.4 .48 .48 0 0 0-.4-.5v-.2a.75 .75 0 0 1 .5 1 .75 .75 0 0 1-1.1 .3l-.4-.5zM103.9 126.7h1.5v.2h-1.1v.4h-.2zM104.7 125.6h.2v.6h-.2z" fill-rule="evenodd"/>
<path d="M102.7 120h1.5v.2h-1v.4h-.2zM103 118.9l.7 .5v-.5zM102.7 118.7h1v-.3h.2v.3h.3v.2h-.3v.6h-.2l-1-.7z" fill-rule="evenodd"/>
<path d="M98.8 128.3l.3-.2v.2a.53 .53 0 0 0-.2 .8 .53 .53 0 0 0 .7 .2 .48 .48 0 0 0 .5-.5 .48 .48 0 0 0-.5-.5v-.2a.75 .75 0 0 1 .6 1.1 .75 .75 0 0 1-1.2 .2l-.4-.4zM98.8 127a.89 .89 0 0 1 1.1 .7l.1 .1v-.9h.2v1.1l-.5-.2a.6 .6 0 0 0-.8-.6v.4l.3 .1v.2h-.3l-.2-.3zM99.1 126.1h.5v-.5h.1v.5h.5v.2h-.5v.4h-.1v-.4h-.5z" fill-rule="evenodd"/>
<path d="M97.6 120h1.5v.2h-1.1v.4h-.2zM97.6 118.5h.2v.7l.4 .1a.53 .53 0 0 1 .2-.8 .53 .53 0 0 1 .7 .4 .53 .53 0 0 1-.4 .6v-.2a.33 .33 0 0 0 .1-.5 .33 .33 0 0 0-.5 0 .33 .33 0 0 0 .1 .5v.2l-.8-.2z" fill-rule="evenodd"/>
<path d="M93.6 127.8l.4-.2v.2a.53 .53 0 0 0-.3 .7 .53 .53 0 0 0 .8 .2 .48 .48 0 0 0 .4-.4 .48 .48 0 0 0-.4-.5v-.2a.75 .75 0 0 1 .5 1 .75 .75 0 0 1-1.2 .3l-.3-.5zM93.7 126.5a.89 .89 0 0 1 1.1 .7h.1v-.8h.1v1l-.4-.2a.6 .6 0 0 0-.8-.5l-.1 .3 .4 .2v.2l-.4-.1-.2-.2zM94.3 125.6h.2v.6h-.2z" fill-rule="evenodd"/>
<path d="M92.4 120h1.5v.2h-1.1v.4h-.1zM92.5 118.6l.3-.1v.2a.32 .32 0 0 0-.2 .4 .32 .32 0 0 0 .4 .2h.1a.52 .52 0 0 1 .2-.8 .52 .52 0 0 1 .7 .4 .52 .52 0 0 1-.5 .6 .7 .7 0 0 1-.8-.1 .7 .7 0 0 1-.2-.8zM93.1 119a.35 .35 0 0 0 .7 0 .35 .35 0 0 0-.7 0z" fill-rule="evenodd"/>
<path d="M63.3 160.8a.48 .48 0 0 1 .4 .3 .48 .48 0 0 1-.1 .5l.1 .5-.3-.3 .1-.7zM62.5 160.4h1.6v.2h-1.6zM62.5 158.8h1.6v.2l-1.3 .8h1.3v.2h-1.6v-.2l1.3-.8h-1.3zM62.5 157.2l1.6 .6v.2l-1.6 .6v-.3l1.3-.4-1.3-.5zM62.7 156.6l.7 .3v-.5zM62.5 156.5l1.6-.6v.2l-.5 .2v.6l.5 .2v.2l-1.6-.6zM62.5 155.5h1.4v-.8h.2v1h-1.6zM62.5 154.2h1.6v.3h-1.6zM62.9 152.9l-.2 .8h1.2v-.4a.63 .63 0 0 0-1-.4zM62.7 152.8a.85 .85 0 0 1 1.4 .5v.6h-1.6v-.8z" fill-rule="evenodd"/>
<path d="M61.6 167a.89 .89 0 0 1 1.1 .7l.1 .1v-.9h.1v1.1l-.4-.2a.6 .6 0 0 0-.8-.6l-.1 .4 .4 .1v.2h-.4l-.2-.3z" fill-rule="evenodd"/>
<path d="M58.1 160.8a.48 .48 0 0 1 .4 .3 .48 .48 0 0 1-.1 .5l.2 .5-.4-.3 .2-.7zM57.4 159.5h.1v.9h.5v-.8h.2v.8h.7v.2h-1.5zM57.3 158.6a.85 .85 0 0 1 1.7 0 .85 .85 0 0 1-1.7 0zM57.5 158.6a.6 .6 0 0 0 1.2 0 .6 .6 0 0 0-1.2 0zM57.7 156.6l-.2 .8h.6l-.1-.7zM57.5 156.5l.4-.1 .3 .2 .1-.2 .6-.1v.3h-.5l-.2 .3v.5h.7v.2h-1.5zM57.5 154.9l.3-.2v.2a.53 .53 0 0 0-.2 .8 .53 .53 0 0 0 .7 .2 .48 .48 0 0 0 .5-.5 .48 .48 0 0 0-.5-.5v-.2a.75 .75 0 0 1 .6 1.1 .75 .75 0 0 1-1.2 .2l-.4-.4zM57.4 153.3h.1v.9h.5v-.8h.2v.8h.5v-.9h.2v1.1h-1.5zM57.3 152.3a.85 .85 0 0 1 1.7 0 .85 .85 0 0 1-1.7 0zM57.5 152.3a.6 .6 0 0 0 1.2 0 .6 .6 0 0 0-1.2 0zM57.4 150.2h.1v.9h.5v-.8h.2v.8h.7v.2h-1.5zM57.4 148.9h.1v.9h.5v-.8h.2v.8h.7v.2h-1.5z" fill-rule="evenodd"/>
<path d="M56.3 168.5h1.5v.2h-1.1v.4h-.1zM56.4 167.1a.93 .93 0 0 1 1.4 .4 .85 .85 0 0 1-.8 .5 .85 .85 0 0 1-.7-.5zM56.5 167.3a.62 .62 0 0 0 .4 .5 .62 .62 0 0 0 .7-.2l.1-.1a.79 .79 0 0 0-1.2-.2z" fill-rule="evenodd"/>
<path d="M52.2 160.8h.2v.9h.5v-.8h.1v.8h.8v.2h-1.6zM52.2 159.9a.81 .81 0 0 1 1.6 0 .81 .81 0 0 1-1.6 0zM52.3 159.9a.65 .65 0 0 0 1.3 0 .65 .65 0 0 0-1.3 0zM52.5 157.9l-.1 .8h.5v-.8zM52.3 157.7l.4-.1 .3 .2 .2-.1 .6-.1v.2l-.6 .1-.1 .3v.5h.7v.2h-1.6zM52.3 156.2l.4-.2v.2a.53 .53 0 0 0-.3 .8 .53 .53 0 0 0 .8 .2 .48 .48 0 0 0 .4-.5 .48 .48 0 0 0-.4-.5v-.2a.75 .75 0 0 1 .5 1.1 .75 .75 0 0 1-1.1 .2l-.4-.4zM52.2 154.6h.2v.9h.5v-.8h.1v.8h.6v-.9h.2v1.1h-1.6zM52.2 153.6a.81 .81 0 0 1 1.6 0 .81 .81 0 0 1-1.6 0zM52.3 153.6a.65 .65 0 0 0 1.3 0 .65 .65 0 0 0-1.3 0zM52.2 151.4h1.6v.2l-1.3 .8h1.3v.2h-1.6v-.3l1.3-.7h-1.3z" fill-rule="evenodd"/>
<path d="M51.1 167h.2v.7h.4a.53 .53 0 0 1 .3-.7 .53 .53 0 0 1 .7 .3 .53 .53 0 0 1-.5 .7v-.2a.33 .33 0 0 0 .2-.5 .33 .33 0 0 0-.5-.1 .33 .33 0 0 0 .1 .5l-.1 .2-.8-.1z" fill-rule="evenodd"/>
<path d="M106.4 160.7l1.6 .5v.3l-1.6 .5v-.2l1.3-.5-1.3-.4zM106.8 159.9h.5v-.5h.2v.5h.5v.2h-.5v.4h-.2v-.4h-.5z" fill-rule="evenodd"/>
<path d="M105.3 170.4h1.5v.2h-1.1v.3h-.1zM105.3 169.3h1.5v.2h-1.1v.4h-.1zM105.4 168.2l.1-.1 .1 .3 .2-.2 .1 .1-.2 .2 .2 .1-.1 .1-.2-.1-.1 .2h-.1l.1-.3h-.2v-.1h.2zM105.4 167a.89 .89 0 0 1 1.1 .7l.1 .1v-.9h.2v1.1l-.5-.2a.6 .6 0 0 0-.8-.6v.4l.3 .1v.2h-.3l-.2-.3z" fill-rule="evenodd"/>
<path d="M101.2 160.7l1.6 .5v.3l-1.6 .5v-.2l1.4-.5-1.4-.4zM102.1 160.1h.2v.6h-.2z" fill-rule="evenodd"/>
<path d="M100.1 168.5h1.6v.2h-1.1v.4h-.2zM100.2 166.9l1.5 .6v.3l-1.3-.7v.9h-.2z" fill-rule="evenodd"/>
<path d="M53.1 143.2a.69 .69 0 0 1 1.2 .3h-.2a.59 .59 0 0 0-1 .1 .59 .59 0 0 0 .5 .8l.4-.1 .1-.4h-.5v-.1h.7v.8l-.2-.2a.76 .76 0 0 1-1 0 .76 .76 0 0 1-.1-1zM54.6 143h.3l.8 1.3v-1.3h.2v1.6h-.3l-.8-1.3v1.3h-.2zM56.4 143.2v1.2h.4a.61 .61 0 0 0 .5-.6 .61 .61 0 0 0-.5-.6zM56.2 143h.7a.79 .79 0 0 1 .6 .8 .79 .79 0 0 1-.6 .8h-.7z" fill-rule="evenodd"/>
<path d="M45.8 142.2l.6-.3v1.6h-.2v-1.1h-.4zM47.1 142.3a.26 .26 0 0 0 .5 0 .26 .26 0 0 0-.5 0zM47.1 143a.31 .31 0 0 0 .6 0 .31 .31 0 0 0-.6 0zM47.1 142a.44 .44 0 0 1 .6 0 .44 .44 0 0 1 0 .6 .47 .47 0 0 1 .1 .7 .47 .47 0 0 1-.7 0 .47 .47 0 0 1 0-.7l-.2-.3z" fill-rule="evenodd"/>
<path d="M105.4 143h.3l.4 1.4 .5-1.4h.2l-.6 1.6h-.2zM107.1 143.2a.68 .68 0 0 1 .7-.2 .68 .68 0 0 1 .5 .5h-.2a.53 .53 0 0 0-.7-.3 .53 .53 0 0 0-.2 .8 .48 .48 0 0 0 .4 .4 .48 .48 0 0 0 .5-.4h.2a.75 .75 0 0 1-1.1 .5 .75 .75 0 0 1-.2-1.1zM108.7 143.2a.68 .68 0 0 1 .7-.2 .68 .68 0 0 1 .5 .5h-.2a.53 .53 0 0 0-.8-.3 .53 .53 0 0 0-.2 .8 .48 .48 0 0 0 .5 .4 .48 .48 0 0 0 .5-.4h.2a.75 .75 0 0 1-1.1 .5 .75 .75 0 0 1-.2-1.1z" fill-rule="evenodd"/>
<path d="M114.9 142.1a.67 .67 0 0 1 .9 .2 .67 .67 0 0 1-.1 .8 .47 .47 0 0 1-.4 .4 .47 .47 0 0 1-.5-.4h.2a.3 .3 0 0 0 .4 .2 .3 .3 0 0 0 .2-.3v-.2a.49 .49 0 0 1-.7 0 .49 .49 0 0 1 0-.7zM115 142.4a.32 .32 0 0 0 .6 0 .32 .32 0 0 0-.6 0z" fill-rule="evenodd"/>
<path d="M23.1 117.1v.7h.6a.31 .31 0 0 0 .4-.3 .31 .31 0 0 0-.4-.4zM22.9 116.9a1.57 1.57 0 0 1 1.3 .2l.1 .5-.2 .3 .2 .2 .1 .6h-.3l-.1-.6-.3-.1h-.6v.7h-.2zM24.9 117.5a.3 .3 0 0 0 .6 0 .3 .3 0 0 0-.6 0zM24.8 118.3a.36 .36 0 0 0 .7 0 .36 .36 0 0 0-.7 0zM24.8 117.1a.5 .5 0 0 1 .7-.1 .5 .5 0 0 1 0 .8 .55 .55 0 0 1 .1 .8 .55 .55 0 0 1-.8 0 .55 .55 0 0 1 .1-.8l-.3-.3z" fill-rule="evenodd"/>
<path d="M23.1 112v.6h.6a.31 .31 0 0 0 .4-.3 .31 .31 0 0 0-.4-.3zM22.9 111.8a1.57 1.57 0 0 1 1.3 .1l.1 .5-.2 .3 .2 .2 .1 .7h-.3l-.1-.7-.3-.1h-.6v.8h-.2zM24.7 112a.69 .69 0 0 1 .9 0 .69 .69 0 0 1 .2 .8 .6 .6 0 0 1-.5 .8 .6 .6 0 0 1-.7-.4h.2a.35 .35 0 0 0 .4 .2 .35 .35 0 0 0 .3-.4v-.2a.57 .57 0 0 1-.8 0 .57 .57 0 0 1 0-.8zM24.8 112.4a.4 .4 0 0 0 .8 0 .4 .4 0 0 0-.8 0z" fill-rule="evenodd"/>
<path d="M121.3 139.5a.79 .79 0 0 1 .8-.3 .79 .79 0 0 1 .6 .6h-.3a.62 .62 0 0 0-.8-.3 .62 .62 0 0 0-.2 .9 .56 .56 0 0 0 .5 .5 .56 .56 0 0 0 .6-.5h.2a.85 .85 0 0 1-1.1 .7 .85 .85 0 0 1-.5-1.2zM123.1 139.4a.61 .61 0 0 1 1 .3 .61 .61 0 0 1-.6 .8l-.4 .4h1v.2h-1.2a1.5 1.5 0 0 1 .9-1.1 .36 .36 0 0 0-.3-.5 .36 .36 0 0 0-.3 .5h-.3z" fill-rule="evenodd"/>
<path d="M206.7 88.3h.2v.6h.6v-.6h.2v1.3h-.2v-.6h-.6v.6h-.2zM208.1 88.4a.44 .44 0 0 1 .7 .2 .44 .44 0 0 1-.5 .6l-.2 .3h.7v.1h-.9l.2-.4a.45 .45 0 0 0 .4-.2 .45 .45 0 0 0 0-.5h-.3l-.1 .3h-.2z" fill-rule="evenodd"/>
<path d="M207.8 19.5l.6-.3v1.5h-.2v-1.1h-.4z" fill-rule="evenodd"/>
<path d="M201.9 18.4l.5-.3v1.5h-.2v-1.1h-.3z" fill-rule="evenodd"/>
<path d="M214.9 19.3a.53 .53 0 0 1 .8 .2 .53 .53 0 0 1-.6 .7l-.2 .3h.8v.2h-1.1l.2-.5a.6 .6 0 0 0 .6-.8h-.4l-.1 .3h-.2z" fill-rule="evenodd"/>
<path d="M220.8 18.2a.53 .53 0 0 1 .8 .2 .53 .53 0 0 1-.5 .7l-.3 .3h.8v.2h-1l.2-.5a.6 .6 0 0 0 .6-.8h-.4l-.2 .3h-.2z" fill-rule="evenodd"/>
<path d="M207.9 21.9a.44 .44 0 0 1 .6-.1 .44 .44 0 0 1 0 .7 .5 .5 0 0 1-.1 .9 .5 .5 0 0 1-.7-.6h.2a.31 .31 0 0 0 .4 .4 .31 .31 0 0 0 0-.6h-.2v-.2a.25 .25 0 0 0 .4-.2 .25 .25 0 0 0-.3-.3l-.3 .2v.2h-.2z" fill-rule="evenodd"/>
<path d="M201.9 20.7a.44 .44 0 0 1 .7 0 .44 .44 0 0 1-.1 .7 .5 .5 0 0 1-.1 .8 .5 .5 0 0 1-.7-.5h.2a.31 .31 0 0 0 .5 .3 .31 .31 0 0 0 0-.5h-.3l.1-.2a.25 .25 0 0 0 .3-.2 .25 .25 0 0 0-.2-.3l-.3 .1-.1 .2h-.1z" fill-rule="evenodd"/>
<path d="M215.3 22.1l-.5 .7h.5zM215.3 21.8h.2v1h.2v.1h-.2v.4h-.2v-.4h-.7z" fill-rule="evenodd"/>
<path d="M221.2 20.9l-.4 .7h.4zM221.3 20.6h.1v1h.3v.2h-.3v.4h-.2v-.4h-.6z" fill-rule="evenodd"/>
<path d="M207.9 24.4h.8v.2h-.7l-.1 .4a.53 .53 0 0 1 .8 .2 .53 .53 0 0 1-.4 .8 .53 .53 0 0 1-.6-.5h.2a.33 .33 0 0 0 .5 .2 .33 .33 0 0 0 0-.6 .33 .33 0 0 0-.5 .1h-.2z" fill-rule="evenodd"/>
<path d="M201.9 23.2h.8v.2h-.6l-.1 .5a.53 .53 0 0 1 .7 .2 .53 .53 0 0 1-.3 .7 .53 .53 0 0 1-.7-.4h.2a.33 .33 0 0 0 .5 .1 .33 .33 0 0 0 .1-.5 .33 .33 0 0 0-.5 .1h-.2z" fill-rule="evenodd"/>
<path d="M214.8 24.5a.46 .46 0 0 1 .5-.2 .46 .46 0 0 1 .4 .5h-.2a.32 .32 0 0 0-.4-.3 .32 .32 0 0 0-.2 .4l-.1 .2a.52 .52 0 0 1 .9 .2 .52 .52 0 0 1-.4 .7 .52 .52 0 0 1-.6-.6zM214.9 25.4a.33 .33 0 0 0 .6 0 .33 .33 0 0 0-.6 0z" fill-rule="evenodd"/>
<path d="M220.8 23.4a.46 .46 0 0 1 .5-.2 .46 .46 0 0 1 .3 .4h-.2a.32 .32 0 0 0-.4-.2 .32 .32 0 0 0-.2 .4v.2a.52 .52 0 0 1 .8 .1 .52 .52 0 0 1-.4 .8 .52 .52 0 0 1-.6-.6zM220.8 24.3a.35 .35 0 0 0 .7 0 .35 .35 0 0 0-.7 0z" fill-rule="evenodd"/>
<path d="M207.7 27h1.1l-.7 1.5h-.2l.1-.3 .5-1h-.8z" fill-rule="evenodd"/>
<path d="M201.7 25.8h1.1l-.6 1.5h-.2v-.3l.6-1h-.9z" fill-rule="evenodd"/>
<path d="M214.9 27.3a.26 .26 0 0 0 .5 0 .26 .26 0 0 0-.5 0zM214.8 28a.35 .35 0 0 0 .7 0 .35 .35 0 0 0-.7 0zM214.8 27.1a.44 .44 0 0 1 .7-.1 .44 .44 0 0 1-.1 .6 .47 .47 0 0 1 .1 .7 .47 .47 0 0 1-.7 0 .47 .47 0 0 1 .1-.7l-.2-.3z" fill-rule="evenodd"/>
<path d="M220.8 26.2a.3 .3 0 0 0 .6 0 .3 .3 0 0 0-.6 0zM220.8 26.9a.31 .31 0 0 0 .6 0 .31 .31 0 0 0-.6 0zM220.8 25.9a.44 .44 0 0 1 .6-.1 .44 .44 0 0 1 0 .7 .47 .47 0 0 1 .1 .7 .47 .47 0 0 1-.7 0 .47 .47 0 0 1 .1-.7l-.3-.3z" fill-rule="evenodd"/>
<path d="M207.8 29.7a.67 .67 0 0 1 .9 .1 .67 .67 0 0 1-.1 .9 .47 .47 0 0 1-.4 .4 .47 .47 0 0 1-.5-.4h.2a.3 .3 0 0 0 .4 .2 .3 .3 0 0 0 .2-.3v-.3a.49 .49 0 0 1-.7 .1 .49 .49 0 0 1 0-.7zM207.9 30a.32 .32 0 0 0 .6 0 .32 .32 0 0 0-.6 0z" fill-rule="evenodd"/>
<path d="M201.9 28.5a.67 .67 0 0 1 .8 .2 .67 .67 0 0 1 0 .9 .47 .47 0 0 1-.5 .3 .47 .47 0 0 1-.4-.4h.2a.3 .3 0 0 0 .3 .3 .3 .3 0 0 0 .2-.4l.1-.2a.49 .49 0 0 1-.7 .1 .49 .49 0 0 1 0-.8zM201.9 28.9a.35 .35 0 0 0 .7 0 .35 .35 0 0 0-.7 0z" fill-rule="evenodd"/>
<path d="M213.6 29.8l.5-.3v1.5h-.2v-1h-.3zM214.8 29.7a.6 .6 0 0 1 .8 0 .6 .6 0 0 1 .1 .8 .55 .55 0 0 1-.7 .6 .55 .55 0 0 1-.4-.8zM215 29.7a.84 .84 0 0 0 .1 1.2 .72 .72 0 0 0 .1-1.2z" fill-rule="evenodd"/>
<path d="M220.7 28.7l.6-.3v1.5h-.2v-1.1h-.4zM222 28.5a.6 .6 0 0 1 .8 .1 .6 .6 0 0 1 0 .7 .55 .55 0 0 1-.6 .6 .55 .55 0 0 1-.4-.7zM222.2 28.6a.84 .84 0 0 0 .1 1.2 .72 .72 0 0 0 0-1.2z" fill-rule="evenodd"/>
<path d="M207.8 32.4l.6-.3v1.5h-.2v-1.1h-.4zM208.9 32.4l.5-.3v1.5h-.2v-1.1h-.3z" fill-rule="evenodd"/>
<path d="M200.8 31.3l.6-.3v1.5h-.2v-1.1h-.4zM201.9 31.3l.5-.3v1.5h-.2v-1.1h-.3z" fill-rule="evenodd"/>
<path d="M213.6 32.4l.5-.3v1.5h-.2v-1.1h-.3zM214.8 32.2a.53 .53 0 0 1 .9 .2 .53 .53 0 0 1-.6 .7l-.3 .3h.9v.2h-1.1l.2-.5a.6 .6 0 0 0 .6-.8h-.4l-.1 .3h-.2z" fill-rule="evenodd"/>
<path d="M220.7 31.3l.6-.3v1.5h-.2v-1.1h-.4zM222 31.1a.53 .53 0 0 1 .9 .2 .53 .53 0 0 1-.6 .7l-.3 .3h.9v.2h-1.1l.2-.5a.6 .6 0 0 0 .6-.8h-.4l-.2 .3h-.2z" fill-rule="evenodd"/>
<path d="M207.8 35l.6-.3v1.5h-.2v-1.1h-.4zM209.1 34.8a.44 .44 0 0 1 .7-.1 .44 .44 0 0 1-.1 .7 .5 .5 0 0 1-.1 .9 .5 .5 0 0 1-.7-.6h.2a.31 .31 0 0 0 .4 .4 .31 .31 0 0 0 0-.6h-.2l.1-.2a.25 .25 0 0 0 .3-.2 .25 .25 0 0 0-.3-.2l-.2 .1-.1 .2h-.2z" fill-rule="evenodd"/>
<path d="M200.6 33.8l.6-.2v1.5h-.2v-1.1h-.4zM201.9 33.6a.44 .44 0 0 1 .7 0 .44 .44 0 0 1-.1 .7 .5 .5 0 0 1-.1 .8 .5 .5 0 0 1-.7-.5h.2a.31 .31 0 0 0 .4 .3 .31 .31 0 0 0 .1-.5h-.3l.1-.2a.25 .25 0 0 0 .3-.2 .25 .25 0 0 0-.3-.3l-.2 .1-.1 .2h-.2z" fill-rule="evenodd"/>
<path d="M213.6 35l.5-.3v1.5h-.2v-1.1h-.3zM215.3 35l-.5 .7h.5zM215.3 34.7h.2v1h.2v.1h-.2v.4h-.2v-.4h-.7z" fill-rule="evenodd"/>
<path d="M220.7 33.8l.6-.2v1.5h-.2v-1.1h-.4zM222.5 33.8l-.5 .7h.5zM222.5 33.5h.2v1h.2v.2h-.2v.4h-.2v-.4h-.7z" fill-rule="evenodd"/>
<path d="M207.8 37.6l.6-.3v1.5h-.2v-1.1h-.4zM209.1 37.3h.8v.2h-.7v.4a.53 .53 0 0 1 .7 .2 .53 .53 0 0 1-.3 .8 .53 .53 0 0 1-.7-.5h.2a.33 .33 0 0 0 .5 .2 .33 .33 0 0 0 0-.6 .33 .33 0 0 0-.5 .1h-.1z" fill-rule="evenodd"/>
<path d="M200.6 36.4l.6-.3v1.5h-.2v-1h-.4zM201.9 36.1h.8v.2h-.7v.5a.53 .53 0 0 1 .7 .2 .53 .53 0 0 1-.3 .7 .53 .53 0 0 1-.7-.4h.2a.33 .33 0 0 0 .5 .1 .33 .33 0 0 0 .1-.5 .33 .33 0 0 0-.6 .1h-.1z" fill-rule="evenodd"/>
<path d="M213.6 37.6l.5-.3v1.5h-.2v-1.1h-.3zM214.8 37.4a.46 .46 0 0 1 .5-.2 .46 .46 0 0 1 .3 .5h-.1a.32 .32 0 0 0-.4-.3 .32 .32 0 0 0-.2 .4l-.1 .2a.52 .52 0 0 1 .8 .2 .52 .52 0 0 1-.3 .7 .52 .52 0 0 1-.6-.6zM214.9 38.3a.33 .33 0 0 0 .6 0 .33 .33 0 0 0-.6 0z" fill-rule="evenodd"/>
<path d="M220.7 36.4l.6-.3v1.5h-.2v-1h-.4zM222 36.3a.46 .46 0 0 1 .5-.2 .46 .46 0 0 1 .3 .4h-.2a.32 .32 0 0 0-.3-.2 .32 .32 0 0 0-.3 .4v.2a.52 .52 0 0 1 .8 .1 .52 .52 0 0 1-.4 .8 .52 .52 0 0 1-.6-.6zM222 37.2a.35 .35 0 0 0 .7 0 .35 .35 0 0 0-.7 0z" fill-rule="evenodd"/>
<path d="M207.8 40.1l.6-.3v1.6h-.2v-1.1h-.4zM208.9 39.9h1.1l-.7 1.5h-.2l.1-.3 .6-1h-.9z" fill-rule="evenodd"/>
<path d="M200.6 39l.6-.3v1.5h-.2v-1.1h-.4zM201.7 38.7h1.1l-.6 1.5h-.3l.1-.3 .6-1h-.9z" fill-rule="evenodd"/>
<path d="M213.6 40.1l.5-.3v1.6h-.2v-1.1h-.3zM214.9 40.3a.26 .26 0 0 0 .5 0 .26 .26 0 0 0-.5 0zM214.8 40.9a.35 .35 0 0 0 .7 0 .35 .35 0 0 0-.7 0zM214.8 40a.44 .44 0 0 1 .7-.1 .44 .44 0 0 1-.1 .6 .47 .47 0 0 1 .1 .7 .47 .47 0 0 1-.7 0 .47 .47 0 0 1 .1-.7l-.2-.3z" fill-rule="evenodd"/>
<path d="M220.7 39l.6-.3v1.5h-.2v-1.1h-.4zM222.1 39.1a.26 .26 0 0 0 .5 0 .26 .26 0 0 0-.5 0zM222 39.8a.31 .31 0 0 0 .6 0 .31 .31 0 0 0-.6 0zM222 38.8a.44 .44 0 0 1 .7-.1 .44 .44 0 0 1-.1 .7 .47 .47 0 0 1 .1 .7 .47 .47 0 0 1-.7 0 .47 .47 0 0 1 .1-.7l-.2-.3z" fill-rule="evenodd"/>
<path d="M207.8 42.7l.6-.3v1.5h-.2v-1h-.4zM209 42.6a.67 .67 0 0 1 .9 .2 .67 .67 0 0 1 0 .8 .47 .47 0 0 1-.5 .4 .47 .47 0 0 1-.5-.4h.2a.3 .3 0 0 0 .4 .2 .3 .3 0 0 0 .2-.3v-.3a.49 .49 0 0 1-.7 .1 .49 .49 0 0 1 0-.7zM209.1 42.9a.35 .35 0 0 0 .7 0 .35 .35 0 0 0-.7 0z" fill-rule="evenodd"/>
<path d="M200.6 41.6l.6-.3v1.5h-.2v-1.1h-.4zM201.9 41.4a.67 .67 0 0 1 .8 .2 .67 .67 0 0 1 0 .9 .47 .47 0 0 1-.5 .4 .47 .47 0 0 1-.5-.5h.2a.3 .3 0 0 0 .4 .3 .3 .3 0 0 0 .2-.4l.1-.2a.49 .49 0 0 1-.8 .1 .49 .49 0 0 1 .1-.8zM201.9 41.8a.35 .35 0 0 0 .7 0 .35 .35 0 0 0-.7 0z" fill-rule="evenodd"/>
<path d="M213.6 42.5a.53 .53 0 0 1 .9 .3 .53 .53 0 0 1-.6 .6l-.3 .4h.9v.1h-1.1l.2-.4a.6 .6 0 0 0 .6-.8l-.4-.1-.2 .4h-.2zM214.8 42.6a.6 .6 0 0 1 .8 0 .6 .6 0 0 1 .1 .8 .55 .55 0 0 1-.7 .6 .55 .55 0 0 1-.4-.8zM215 42.6a.84 .84 0 0 0 .1 1.2 .72 .72 0 0 0 .1-1.2z" fill-rule="evenodd"/>
<path d="M220.8 41.4a.53 .53 0 0 1 .8 .2 .53 .53 0 0 1-.5 .7l-.3 .3h.8v.2h-1l.2-.5a.6 .6 0 0 0 .6-.8h-.4l-.2 .3h-.2zM222 41.4a.6 .6 0 0 1 .8 .1 .6 .6 0 0 1 0 .7 .55 .55 0 0 1-.6 .6 .55 .55 0 0 1-.4-.7zM222.2 41.5a.84 .84 0 0 0 .1 1.2 .72 .72 0 0 0 0-1.2z" fill-rule="evenodd"/>
<path d="M207.9 45.1a.53 .53 0 0 1 .8 .2 .53 .53 0 0 1-.5 .7l-.3 .3h.8v.2h-1l.2-.5a.6 .6 0 0 0 .6-.7l-.4-.1-.2 .3h-.2zM209 45.3l.6-.3v1.5h-.2v-1.1h-.4z" fill-rule="evenodd"/>
<path d="M200.7 44a.53 .53 0 0 1 .9 .2 .53 .53 0 0 1-.6 .7l-.3 .3h.9v.2h-1.1l.2-.5a.6 .6 0 0 0 .6-.8h-.4l-.2 .3h-.2zM201.9 44.2l.5-.3v1.5h-.2v-1.1h-.3z" fill-rule="evenodd"/>
<path d="M213.6 45.1a.53 .53 0 0 1 .9 .2 .53 .53 0 0 1-.6 .7l-.3 .3h.9v.2h-1.1l.2-.5a.6 .6 0 0 0 .6-.8h-.4l-.2 .3h-.2zM214.8 45.1a.53 .53 0 0 1 .9 .2 .53 .53 0 0 1-.6 .7l-.3 .3h.9v.2h-1.1l.2-.5a.6 .6 0 0 0 .6-.8h-.4l-.1 .3h-.2z" fill-rule="evenodd"/>
<path d="M220.8 44a.53 .53 0 0 1 .8 .2 .53 .53 0 0 1-.5 .7l-.3 .3h.8v.2h-1l.2-.5a.6 .6 0 0 0 .6-.8h-.4l-.2 .3h-.2zM222 44a.53 .53 0 0 1 .9 .2 .53 .53 0 0 1-.6 .7l-.3 .3h.9v.2h-1.1l.2-.5a.6 .6 0 0 0 .6-.8h-.4l-.2 .3h-.2z" fill-rule="evenodd"/>
<path d="M207.9 47.7a.53 .53 0 0 1 .8 .2 .53 .53 0 0 1-.5 .7l-.3 .3h.8v.2h-1l.2-.5a.6 .6 0 0 0 .6-.8h-.4l-.2 .3h-.2zM209.1 47.7a.44 .44 0 0 1 .7-.1 .44 .44 0 0 1-.1 .7 .5 .5 0 0 1-.1 .9 .5 .5 0 0 1-.7-.6h.2a.31 .31 0 0 0 .4 .4 .31 .31 0 0 0 0-.6h-.2l.1-.2a.25 .25 0 0 0 .3-.2 .25 .25 0 0 0-.3-.2l-.2 .1-.1 .2h-.2z" fill-rule="evenodd"/>
<path d="M200.7 46.5a.53 .53 0 0 1 .9 .3 .53 .53 0 0 1-.6 .7l-.3 .3h.9v.2h-1.1l.2-.5a.6 .6 0 0 0 .6-.8h-.4l-.2 .3h-.2zM201.9 46.5a.44 .44 0 0 1 .7 0 .44 .44 0 0 1-.1 .7 .5 .5 0 0 1-.1 .8 .5 .5 0 0 1-.7-.5h.2a.31 .31 0 0 0 .4 .3 .31 .31 0 0 0 .1-.5h-.3l.1-.2a.25 .25 0 0 0 .3-.2 .25 .25 0 0 0-.3-.3l-.2 .1-.1 .2h-.2z" fill-rule="evenodd"/>
<path d="M213.6 47.7a.53 .53 0 0 1 .9 .2 .53 .53 0 0 1-.6 .7l-.3 .3h.9v.2h-1.1l.2-.5a.6 .6 0 0 0 .6-.8h-.4l-.2 .3h-.2zM215.3 47.9l-.5 .7h.5zM215.3 47.6h.2v1h.2v.1h-.2v.4h-.2v-.4h-.7z" fill-rule="evenodd"/>
<path d="M220.8 46.5a.53 .53 0 0 1 .8 .3 .53 .53 0 0 1-.5 .7l-.3 .3h.8v.2h-1l.2-.5a.6 .6 0 0 0 .6-.8h-.4l-.2 .3h-.2zM222.5 46.7l-.5 .7h.5zM222.5 46.4h.2v1h.2v.2h-.2v.4h-.2v-.4h-.7z" fill-rule="evenodd"/>
<path d="M207.9 50.3a.53 .53 0 0 1 .8 .2 .53 .53 0 0 1-.5 .7l-.3 .3h.8v.2h-1l.2-.5a.6 .6 0 0 0 .6-.8h-.4l-.2 .3h-.2zM209.1 50.2h.8v.2h-.7v.4a.53 .53 0 0 1 .7 .2 .53 .53 0 0 1-.3 .8 .53 .53 0 0 1-.7-.5h.2a.33 .33 0 0 0 .5 .2 .33 .33 0 0 0 0-.6 .33 .33 0 0 0-.5 .1h-.1z" fill-rule="evenodd"/>
<path d="M200.7 49.1a.53 .53 0 0 1 .9 .3 .53 .53 0 0 1-.6 .7l-.3 .3h.9v.2h-1.1l.2-.5a.6 .6 0 0 0 .6-.8l-.4-.1-.2 .4h-.2zM201.9 49.1h.8v.1h-.7v.5a.53 .53 0 0 1 .7 .2 .53 .53 0 0 1-.3 .7 .53 .53 0 0 1-.7-.4h.2a.33 .33 0 0 0 .5 .1 .33 .33 0 0 0 .1-.5 .33 .33 0 0 0-.6 .1h-.1z" fill-rule="evenodd"/>
<path d="M213.6 50.3a.53 .53 0 0 1 .9 .2 .53 .53 0 0 1-.6 .7l-.3 .3h.9v.2h-1.1l.2-.5a.6 .6 0 0 0 .6-.8h-.4l-.2 .3h-.2zM214.8 50.3a.46 .46 0 0 1 .5-.2 .46 .46 0 0 1 .3 .5h-.1a.32 .32 0 0 0-.4-.3 .32 .32 0 0 0-.2 .4l-.1 .2a.52 .52 0 0 1 .8 .2 .52 .52 0 0 1-.3 .7 .52 .52 0 0 1-.6-.6zM214.9 51.2a.33 .33 0 0 0 .6 0 .33 .33 0 0 0-.6 0z" fill-rule="evenodd"/>
<path d="M220.8 49.1a.53 .53 0 0 1 .8 .3 .53 .53 0 0 1-.5 .7l-.3 .3h.8v.2h-1l.2-.5a.6 .6 0 0 0 .6-.8l-.4-.1-.2 .4h-.2zM222 49.2a.46 .46 0 0 1 .5-.2 .46 .46 0 0 1 .3 .4h-.2a.32 .32 0 0 0-.3-.2 .32 .32 0 0 0-.3 .4v.2a.52 .52 0 0 1 .8 .1 .52 .52 0 0 1-.4 .8 .52 .52 0 0 1-.6-.6zM222 50.1a.35 .35 0 0 0 .7 0 .35 .35 0 0 0-.7 0z" fill-rule="evenodd"/>
<path d="M207.9 52.8a.53 .53 0 0 1 .8 .3 .53 .53 0 0 1-.5 .7l-.3 .3h.8v.2h-1l.2-.5a.6 .6 0 0 0 .6-.8h-.4l-.2 .3h-.2zM208.9 52.8h1.1l-.7 1.5h-.2l.1-.3 .6-1h-.9z" fill-rule="evenodd"/>
<path d="M200.7 51.7a.53 .53 0 0 1 .9 .3 .53 .53 0 0 1-.6 .6l-.3 .4h.9v.1h-1.1l.2-.4a.6 .6 0 0 0 .6-.8l-.4-.1-.2 .3h-.2zM201.7 51.6h1.1l-.6 1.5h-.3l.1-.3 .6-1h-.9z" fill-rule="evenodd"/>
<path d="M213.6 52.8a.53 .53 0 0 1 .9 .3 .53 .53 0 0 1-.6 .7l-.3 .3h.9v.2h-1.1l.2-.5a.6 .6 0 0 0 .6-.8l-.4-.1-.2 .4h-.2zM214.9 53.2a.26 .26 0 0 0 .5 0 .26 .26 0 0 0-.5 0zM214.8 53.9a.35 .35 0 0 0 .7 0 .35 .35 0 0 0-.7 0zM214.8 52.9a.44 .44 0 0 1 .7-.1 .44 .44 0 0 1-.1 .7 .47 .47 0 0 1 .1 .6 .47 .47 0 0 1-.7 .1 .47 .47 0 0 1 .1-.7l-.2-.3z" fill-rule="evenodd"/>
<path d="M220.8 51.7a.53 .53 0 0 1 .8 .3 .53 .53 0 0 1-.5 .6l-.3 .4h.8v.1h-1l.2-.4a.6 .6 0 0 0 .6-.8l-.4-.1-.2 .3h-.2zM222.1 52a.26 .26 0 0 0 .5 0 .26 .26 0 0 0-.5 0zM222 52.7a.31 .31 0 0 0 .6 0 .31 .31 0 0 0-.6 0zM222 51.7a.44 .44 0 0 1 .7-.1 .44 .44 0 0 1-.1 .7 .47 .47 0 0 1 .1 .7 .47 .47 0 0 1-.7 0 .47 .47 0 0 1 .1-.7l-.2-.3z" fill-rule="evenodd"/>
<path d="M207.9 55.4a.53 .53 0 0 1 .8 .3 .53 .53 0 0 1-.5 .7l-.3 .3h.8v.1h-1l.2-.4a.6 .6 0 0 0 .6-.8l-.4-.1-.2 .4h-.2zM209 55.5a.67 .67 0 0 1 .9 .2 .67 .67 0 0 1 0 .8 .47 .47 0 0 1-.5 .4 .47 .47 0 0 1-.5-.4h.2a.3 .3 0 0 0 .4 .2 .3 .3 0 0 0 .2-.3v-.2a.49 .49 0 0 1-.7 0 .49 .49 0 0 1 0-.7zM209.1 55.8a.35 .35 0 0 0 .7 0 .35 .35 0 0 0-.7 0z" fill-rule="evenodd"/>
<path d="M200.7 54.3a.53 .53 0 0 1 .9 .2 .53 .53 0 0 1-.6 .7l-.3 .3h.9v.2h-1.1l.2-.5a.6 .6 0 0 0 .6-.8h-.4l-.2 .3h-.2zM201.9 54.3a.67 .67 0 0 1 .8 .2 .67 .67 0 0 1 0 .9 .47 .47 0 0 1-.5 .4 .47 .47 0 0 1-.5-.5h.2a.3 .3 0 0 0 .4 .3 .3 .3 0 0 0 .2-.4l.1-.2a.49 .49 0 0 1-.8 .1 .49 .49 0 0 1 .1-.8zM201.9 54.7a.35 .35 0 0 0 .7 0 .35 .35 0 0 0-.7 0z" fill-rule="evenodd"/>
<path d="M213.6 55.4a.44 .44 0 0 1 .7 0 .44 .44 0 0 1-.1 .6 .5 .5 0 0 1-.1 .9 .5 .5 0 0 1-.7-.5h.2a.31 .31 0 0 0 .4 .3 .31 .31 0 0 0 0-.5l-.2-.1 .1-.1a.25 .25 0 0 0 .3-.2 .25 .25 0 0 0-.3-.3l-.2 .1-.1 .2h-.2zM214.8 55.5a.6 .6 0 0 1 .8 0 .6 .6 0 0 1 .1 .8 .55 .55 0 0 1-.7 .6 .55 .55 0 0 1-.4-.8zM215 55.5a.84 .84 0 0 0 .1 1.2 .72 .72 0 0 0 .1-1.2z" fill-rule="evenodd"/>
<path d="M220.8 54.3a.44 .44 0 0 1 .6-.1 .44 .44 0 0 1 0 .7 .5 .5 0 0 1-.1 .9 .5 .5 0 0 1-.7-.6h.2a.31 .31 0 0 0 .4 .4 .31 .31 0 0 0 0-.6h-.2v-.2a.25 .25 0 0 0 .4-.2 .25 .25 0 0 0-.3-.2l-.2 .1-.1 .2h-.2zM222 54.3a.6 .6 0 0 1 .8 .1 .6 .6 0 0 1 0 .7 .55 .55 0 0 1-.6 .6 .55 .55 0 0 1-.4-.7zM222.2 54.4a.84 .84 0 0 0 .1 1.2 .72 .72 0 0 0 0-1.2z" fill-rule="evenodd"/>
<path d="M207.9 58a.44 .44 0 0 1 .6 0 .44 .44 0 0 1 0 .6 .5 .5 0 0 1-.1 .9 .5 .5 0 0 1-.7-.5h.2a.31 .31 0 0 0 .4 .3 .31 .31 0 0 0 0-.6h-.2v-.1a.25 .25 0 0 0 .4-.2 .25 .25 0 0 0-.3-.3l-.3 .1v.2h-.2zM209 58.2l.6-.3v1.5h-.2v-1.1h-.4z" fill-rule="evenodd"/>
<path d="M200.7 56.9a.44 .44 0 0 1 .7-.1 .44 .44 0 0 1-.1 .7 .5 .5 0 0 1-.1 .8 .5 .5 0 0 1-.7-.5h.2a.31 .31 0 0 0 .4 .4 .31 .31 0 0 0 0-.6h-.2l.1-.2a.25 .25 0 0 0 .3-.2 .25 .25 0 0 0-.3-.3l-.2 .2-.1 .2h-.2zM201.9 57.1l.5-.3v1.5h-.2v-1.1h-.3z" fill-rule="evenodd"/>
<path d="M213.6 58a.44 .44 0 0 1 .7 0 .44 .44 0 0 1-.1 .6 .5 .5 0 0 1-.1 .9 .5 .5 0 0 1-.7-.5h.2a.31 .31 0 0 0 .4 .3 .31 .31 0 0 0 0-.6h-.2l.1-.1a.25 .25 0 0 0 .3-.2 .25 .25 0 0 0-.3-.3l-.2 .1-.1 .2h-.2zM214.8 58a.53 .53 0 0 1 .9 .2 .53 .53 0 0 1-.6 .7l-.3 .3h.9v.2h-1.1l.2-.5a.6 .6 0 0 0 .6-.8h-.4l-.1 .3h-.2z" fill-rule="evenodd"/>
<path d="M220.8 56.9a.44 .44 0 0 1 .6-.1 .44 .44 0 0 1 0 .7 .5 .5 0 0 1-.1 .8 .5 .5 0 0 1-.7-.5h.2a.31 .31 0 0 0 .4 .4 .31 .31 0 0 0 0-.6h-.2v-.2a.25 .25 0 0 0 .4-.2 .25 .25 0 0 0-.3-.3l-.2 .2-.1 .2h-.2zM222 56.9a.53 .53 0 0 1 .9 .2 .53 .53 0 0 1-.6 .7l-.3 .3h.9v.2h-1.1l.2-.5a.6 .6 0 0 0 .6-.8h-.4l-.2 .3h-.2z" fill-rule="evenodd"/>
<path d="M207.9 60.6a.44 .44 0 0 1 .6-.1 .44 .44 0 0 1 0 .7 .5 .5 0 0 1-.1 .9 .5 .5 0 0 1-.7-.6h.2a.31 .31 0 0 0 .4 .4 .31 .31 0 0 0 0-.6h-.2v-.2a.25 .25 0 0 0 .4-.2 .25 .25 0 0 0-.3-.2l-.3 .1v.2h-.2zM209.1 60.6a.44 .44 0 0 1 .7-.1 .44 .44 0 0 1-.1 .7 .5 .5 0 0 1-.1 .9 .5 .5 0 0 1-.7-.6h.2a.31 .31 0 0 0 .4 .4 .31 .31 0 0 0 0-.6h-.2l.1-.2a.25 .25 0 0 0 .3-.2 .25 .25 0 0 0-.3-.2l-.2 .1-.1 .2h-.2z" fill-rule="evenodd"/>
<path d="M200.7 59.4a.44 .44 0 0 1 .7 0 .44 .44 0 0 1-.1 .7 .5 .5 0 0 1-.1 .8 .5 .5 0 0 1-.7-.5h.2a.31 .31 0 0 0 .4 .3 .31 .31 0 0 0 0-.5h-.2l.1-.2a.25 .25 0 0 0 .3-.2 .25 .25 0 0 0-.3-.3l-.2 .1-.1 .2h-.2zM201.9 59.4a.44 .44 0 0 1 .7 0 .44 .44 0 0 1-.1 .7 .5 .5 0 0 1-.1 .8 .5 .5 0 0 1-.7-.5h.2a.31 .31 0 0 0 .4 .3 .31 .31 0 0 0 .1-.5h-.3l.1-.2a.25 .25 0 0 0 .3-.2 .25 .25 0 0 0-.3-.3l-.2 .1-.1 .2h-.2z" fill-rule="evenodd"/>
<path d="M213.6 60.6a.44 .44 0 0 1 .7-.1 .44 .44 0 0 1-.1 .7 .5 .5 0 0 1-.1 .9 .5 .5 0 0 1-.7-.6h.2a.31 .31 0 0 0 .4 .4 .31 .31 0 0 0 0-.6h-.2l.1-.2a.25 .25 0 0 0 .3-.2 .25 .25 0 0 0-.3-.2l-.2 .1-.1 .2h-.2zM215.3 60.8l-.5 .7h.5zM215.3 60.5h.2v1h.2v.1h-.2v.4h-.2v-.4h-.7z" fill-rule="evenodd"/>
<path d="M220.8 59.4a.44 .44 0 0 1 .6 0 .44 .44 0 0 1 0 .7 .5 .5 0 0 1-.1 .8 .5 .5 0 0 1-.7-.5h.2a.31 .31 0 0 0 .4 .3 .31 .31 0 0 0 0-.5h-.2v-.2a.25 .25 0 0 0 .4-.2 .25 .25 0 0 0-.3-.3l-.2 .1-.1 .2h-.2zM222.5 59.6l-.5 .7h.5zM222.5 59.3h.2v1h.2v.2h-.2v.4h-.2v-.4h-.7z" fill-rule="evenodd"/>
<path d="M207.9 63.2a.44 .44 0 0 1 .6-.1 .44 .44 0 0 1 0 .7 .5 .5 0 0 1-.1 .8 .5 .5 0 0 1-.7-.5h.2a.31 .31 0 0 0 .4 .3 .31 .31 0 0 0 0-.5h-.2v-.2a.25 .25 0 0 0 .4-.2 .25 .25 0 0 0-.3-.3l-.3 .2v.2h-.2zM209.1 63.1h.8v.2h-.7v.4a.53 .53 0 0 1 .7 .2 .53 .53 0 0 1-.3 .8 .53 .53 0 0 1-.7-.5h.2a.33 .33 0 0 0 .5 .2 .33 .33 0 0 0 0-.6 .33 .33 0 0 0-.5 .1h-.1z" fill-rule="evenodd"/>
<path d="M200.7 62a.44 .44 0 0 1 .7 0 .44 .44 0 0 1-.1 .6 .5 .5 0 0 1-.1 .9 .5 .5 0 0 1-.7-.5h.2a.31 .31 0 0 0 .4 .3 .31 .31 0 0 0 0-.5h-.2l.1-.2a.25 .25 0 0 0 .3-.2 .25 .25 0 0 0-.3-.3l-.2 .1-.1 .2h-.2zM201.9 62h.8v.1h-.7v.5a.53 .53 0 0 1 .7 .2 .53 .53 0 0 1-.3 .7 .53 .53 0 0 1-.7-.4h.2a.33 .33 0 0 0 .5 .1 .33 .33 0 0 0 .1-.5 .33 .33 0 0 0-.6 .1h-.1z" fill-rule="evenodd"/>
<path d="M213.6 63.2a.44 .44 0 0 1 .7-.1 .44 .44 0 0 1-.1 .7 .5 .5 0 0 1-.1 .8 .5 .5 0 0 1-.7-.5h.2a.31 .31 0 0 0 .4 .3 .31 .31 0 0 0 0-.5h-.2l.1-.2a.25 .25 0 0 0 .3-.2 .25 .25 0 0 0-.3-.3l-.2 .2-.1 .2h-.2zM214.8 63.2a.46 .46 0 0 1 .5-.1 .46 .46 0 0 1 .3 .4h-.1a.32 .32 0 0 0-.4-.3 .32 .32 0 0 0-.2 .4l-.1 .2a.52 .52 0 0 1 .8 .2 .52 .52 0 0 1-.3 .7 .52 .52 0 0 1-.6-.6zM214.9 64.1a.33 .33 0 0 0 .6 0 .33 .33 0 0 0-.6 0z" fill-rule="evenodd"/>
<path d="M220.8 62a.44 .44 0 0 1 .6 0 .44 .44 0 0 1 0 .6 .5 .5 0 0 1-.1 .9 .5 .5 0 0 1-.7-.5h.2a.31 .31 0 0 0 .4 .3 .31 .31 0 0 0 0-.5h-.2v-.2a.25 .25 0 0 0 .4-.2 .25 .25 0 0 0-.3-.3l-.2 .1-.1 .2h-.2zM222 62.1a.46 .46 0 0 1 .5-.2 .46 .46 0 0 1 .3 .4h-.2a.32 .32 0 0 0-.3-.2 .32 .32 0 0 0-.3 .4v.2a.52 .52 0 0 1 .8 .1 .52 .52 0 0 1-.4 .8 .52 .52 0 0 1-.6-.6zM222 63a.35 .35 0 0 0 .7 0 .35 .35 0 0 0-.7 0z" fill-rule="evenodd"/>
<path d="M207.9 65.7a.44 .44 0 0 1 .6 0 .44 .44 0 0 1 0 .7 .5 .5 0 0 1-.1 .8 .5 .5 0 0 1-.7-.5h.2a.31 .31 0 0 0 .4 .3 .31 .31 0 0 0 0-.5h-.2v-.2a.25 .25 0 0 0 .4-.2 .25 .25 0 0 0-.3-.3l-.3 .1v.2h-.2zM208.9 65.7h1.1l-.7 1.5h-.2l.1-.3 .6-1h-.9z" fill-rule="evenodd"/>
<path d="M200.7 64.6a.44 .44 0 0 1 .7 0 .44 .44 0 0 1-.1 .6 .5 .5 0 0 1-.1 .9 .5 .5 0 0 1-.7-.5h.2a.31 .31 0 0 0 .4 .3 .31 .31 0 0 0 0-.6h-.2l.1-.1a.25 .25 0 0 0 .3-.2 .25 .25 0 0 0-.3-.3l-.2 .1-.1 .2h-.2zM201.7 64.5h1.1l-.6 1.5h-.3l.1-.3 .6-1h-.9z" fill-rule="evenodd"/>
<path d="M213.6 65.7a.44 .44 0 0 1 .7 0 .44 .44 0 0 1-.1 .7 .5 .5 0 0 1-.1 .8 .5 .5 0 0 1-.7-.5h.2a.31 .31 0 0 0 .4 .3 .31 .31 0 0 0 0-.5h-.2l.1-.2a.25 .25 0 0 0 .3-.2 .25 .25 0 0 0-.3-.3l-.2 .1-.1 .2h-.2zM214.9 66.1a.26 .26 0 0 0 .5 0 .26 .26 0 0 0-.5 0zM214.8 66.8a.35 .35 0 0 0 .7 0 .35 .35 0 0 0-.7 0zM214.8 65.8a.44 .44 0 0 1 .7-.1 .44 .44 0 0 1-.1 .7 .47 .47 0 0 1 .1 .7 .47 .47 0 0 1-.7 0 .47 .47 0 0 1 .1-.7l-.2-.3z" fill-rule="evenodd"/>
<path d="M220.8 64.6a.44 .44 0 0 1 .6 0 .44 .44 0 0 1 0 .6 .5 .5 0 0 1-.1 .9 .5 .5 0 0 1-.7-.5h.2a.31 .31 0 0 0 .4 .3 .31 .31 0 0 0 0-.6h-.2v-.1a.25 .25 0 0 0 .4-.2 .25 .25 0 0 0-.3-.3l-.2 .1-.1 .2h-.2zM222.1 64.9a.26 .26 0 0 0 .5 0 .26 .26 0 0 0-.5 0zM222 65.6a.31 .31 0 0 0 .6 0 .31 .31 0 0 0-.6 0zM222 64.6a.44 .44 0 0 1 .7-.1 .44 .44 0 0 1-.1 .7 .47 .47 0 0 1 .1 .7 .47 .47 0 0 1-.7 0 .47 .47 0 0 1 .1-.7l-.2-.3z" fill-rule="evenodd"/>
<path d="M207.9 68.3a.44 .44 0 0 1 .6 0 .44 .44 0 0 1 0 .6 .5 .5 0 0 1-.1 .9 .5 .5 0 0 1-.7-.5h.2a.31 .31 0 0 0 .4 .3 .31 .31 0 0 0 0-.5l-.2-.1v-.1a.25 .25 0 0 0 .4-.2 .25 .25 0 0 0-.3-.3l-.3 .1v.2h-.2zM209 68.4a.67 .67 0 0 1 .9 .2 .67 .67 0 0 1 0 .8 .47 .47 0 0 1-.5 .4 .47 .47 0 0 1-.5-.4h.2a.3 .3 0 0 0 .4 .2 .3 .3 0 0 0 .2-.3v-.2a.49 .49 0 0 1-.7 0 .49 .49 0 0 1 0-.7zM209.1 68.7a.35 .35 0 0 0 .7 0 .35 .35 0 0 0-.7 0z" fill-rule="evenodd"/>
<path d="M200.7 67.2a.44 .44 0 0 1 .7-.1 .44 .44 0 0 1-.1 .7 .5 .5 0 0 1-.1 .9 .5 .5 0 0 1-.7-.6h.2a.31 .31 0 0 0 .4 .4 .31 .31 0 0 0 0-.6h-.2l.1-.2a.25 .25 0 0 0 .3-.1 .25 .25 0 0 0-.3-.3l-.2 .1-.1 .2h-.2zM201.9 67.2a.67 .67 0 0 1 .8 .2 .67 .67 0 0 1 0 .9 .47 .47 0 0 1-.5 .4 .47 .47 0 0 1-.5-.5h.2a.3 .3 0 0 0 .4 .3 .3 .3 0 0 0 .2-.4l.1-.2a.49 .49 0 0 1-.8 .1 .49 .49 0 0 1 .1-.8zM201.9 67.6a.35 .35 0 0 0 .7 0 .35 .35 0 0 0-.7 0z" fill-rule="evenodd"/>
<path d="M214.1 68.5l-.5 .7h.5zM214.1 68.2h.2v1h.2v.2h-.2v.3h-.2v-.3h-.7zM214.8 68.4a.6 .6 0 0 1 .8 0 .6 .6 0 0 1 .1 .8 .55 .55 0 0 1-.7 .6 .55 .55 0 0 1-.4-.8zM215 68.4a.84 .84 0 0 0 .1 1.2 .72 .72 0 0 0 .1-1.2z" fill-rule="evenodd"/>
<path d="M221.2 67.4l-.4 .7h.4zM221.3 67.1h.1v1h.3v.1h-.3v.4h-.2v-.4h-.6zM222 67.2a.6 .6 0 0 1 .8 .1 .6 .6 0 0 1 0 .7 .55 .55 0 0 1-.6 .7 .55 .55 0 0 1-.4-.8zM222.2 67.3a.84 .84 0 0 0 .1 1.2 .72 .72 0 0 0 0-1.2z" fill-rule="evenodd"/>
<path d="M208.3 71.1l-.4 .7h.4zM208.4 70.8h.1v1h.3v.2h-.3v.3h-.2v-.3h-.6zM209 71.1l.6-.3v1.5h-.2v-1h-.4z" fill-rule="evenodd"/>
<path d="M201.2 70l-.5 .7h.5zM201.2 69.7h.2v1h.2v.1h-.2v.4h-.2v-.4h-.7zM201.9 70l.5-.3v1.5h-.2v-1.1h-.3z" fill-rule="evenodd"/>
<path d="M214.1 71.1l-.5 .7h.5zM214.1 70.8h.2v1h.2v.2h-.2v.3h-.2v-.3h-.7zM214.8 70.9a.53 .53 0 0 1 .9 .2 .53 .53 0 0 1-.6 .7l-.3 .3h.9v.2h-1.1l.2-.5a.6 .6 0 0 0 .6-.7l-.4-.1-.1 .3h-.2z" fill-rule="evenodd"/>
<path d="M221.2 70l-.4 .7h.4zM221.3 69.7h.1v1h.3v.1h-.3v.4h-.2v-.4h-.6zM222 69.8a.53 .53 0 0 1 .9 .2 .53 .53 0 0 1-.6 .7l-.3 .3h.9v.2h-1.1l.2-.5a.6 .6 0 0 0 .6-.8h-.4l-.2 .3h-.2z" fill-rule="evenodd"/>
<path d="M208.3 73.7l-.4 .7h.4zM208.4 73.4h.1v1h.3v.1h-.3v.4h-.2v-.4h-.6zM209.1 73.5a.44 .44 0 0 1 .7-.1 .44 .44 0 0 1-.1 .7 .5 .5 0 0 1-.1 .9 .5 .5 0 0 1-.7-.6h.2a.31 .31 0 0 0 .4 .4 .31 .31 0 0 0 0-.6h-.2l.1-.2a.25 .25 0 0 0 .3-.2 .25 .25 0 0 0-.3-.2l-.2 .1-.1 .2h-.2z" fill-rule="evenodd"/>
<path d="M201.2 72.5l-.5 .7h.5zM201.2 72.2h.2v1h.2v.2h-.2v.4h-.2v-.4h-.7zM201.9 72.3a.44 .44 0 0 1 .7 0 .44 .44 0 0 1-.1 .7 .5 .5 0 0 1-.1 .8 .5 .5 0 0 1-.7-.5h.2a.31 .31 0 0 0 .4 .3 .31 .31 0 0 0 .1-.5h-.3l.1-.2a.25 .25 0 0 0 .3-.2 .25 .25 0 0 0-.3-.3l-.2 .2-.1 .2h-.2z" fill-rule="evenodd"/>
<path d="M214.1 73.7l-.5 .7h.5zM214.1 73.4h.2v1h.2v.1h-.2v.4h-.2v-.4h-.7zM215.3 73.7l-.5 .7h.5zM215.3 73.4h.2v1h.2v.1h-.2v.4h-.2v-.4h-.7z" fill-rule="evenodd"/>
<path d="M221.2 72.5l-.4 .7h.4zM221.3 72.2h.1v1h.3v.2h-.3v.4h-.2v-.4h-.6zM222.5 72.5l-.5 .7h.5zM222.5 72.2h.2v1h.2v.2h-.2v.4h-.2v-.4h-.7z" fill-rule="evenodd"/>
<path d="M208.3 76.3l-.4 .7h.4zM208.4 76h.1v1h.3v.1h-.3v.4h-.2v-.4h-.6zM209.1 76h.8v.2h-.7v.4a.53 .53 0 0 1 .7 .2 .53 .53 0 0 1-.3 .8 .53 .53 0 0 1-.7-.5h.2a.33 .33 0 0 0 .5 .2 .33 .33 0 0 0 0-.6 .33 .33 0 0 0-.5 .1h-.1z" fill-rule="evenodd"/>
<path d="M201.2 75.1l-.5 .7h.5zM201.2 74.8h.2v1h.2v.2h-.2v.4h-.2v-.4h-.7zM201.9 74.9h.8v.1h-.7v.5a.53 .53 0 0 1 .7 .2 .53 .53 0 0 1-.3 .7 .53 .53 0 0 1-.7-.4h.2a.33 .33 0 0 0 .5 .1 .33 .33 0 0 0 .1-.5 .33 .33 0 0 0-.6 .1h-.1z" fill-rule="evenodd"/>
<path d="M214.1 76.3l-.5 .6h.5zM214.1 76h.2v.9h.2v.2h-.2v.4h-.2v-.4h-.7zM214.8 76.1a.46 .46 0 0 1 .5-.1 .46 .46 0 0 1 .3 .4h-.1a.32 .32 0 0 0-.4-.3 .32 .32 0 0 0-.2 .4l-.1 .2a.52 .52 0 0 1 .8 .2 .52 .52 0 0 1-.3 .7 .52 .52 0 0 1-.6-.5zM214.9 77a.33 .33 0 0 0 .6 0 .33 .33 0 0 0-.6 0z" fill-rule="evenodd"/>
<path d="M221.2 75.1l-.4 .7h.4zM221.3 74.8h.1v1h.3v.2h-.3v.4h-.2v-.4h-.6zM222 75a.46 .46 0 0 1 .5-.2 .46 .46 0 0 1 .3 .4h-.2a.32 .32 0 0 0-.3-.2 .32 .32 0 0 0-.3 .4v.2a.52 .52 0 0 1 .8 .1 .52 .52 0 0 1-.4 .8 .52 .52 0 0 1-.6-.6zM222 75.9a.35 .35 0 0 0 .7 0 .35 .35 0 0 0-.7 0z" fill-rule="evenodd"/>
<path d="M208.3 78.8l-.4 .7h.4zM208.4 78.5h.1v1h.3v.2h-.3v.4h-.2v-.4h-.6zM208.9 78.6h1.1l-.7 1.5h-.2l.1-.3 .6-1h-.9z" fill-rule="evenodd"/>
<path d="M201.2 77.7l-.5 .7h.5zM201.2 77.4h.2v1h.2v.2h-.2v.3h-.2v-.3h-.7zM201.7 77.4h1.1l-.6 1.5h-.3l.1-.3 .6-1h-.9z" fill-rule="evenodd"/>
<path d="M214.1 78.8l-.5 .7h.5zM214.1 78.5h.2v1h.2v.2h-.2v.4h-.2v-.4h-.7zM214.9 79a.26 .26 0 0 0 .5 0 .26 .26 0 0 0-.5 0zM214.8 79.7a.35 .35 0 0 0 .7 0 .35 .35 0 0 0-.7 0zM214.8 78.7a.44 .44 0 0 1 .7-.1 .44 .44 0 0 1-.1 .7 .47 .47 0 0 1 .1 .7 .47 .47 0 0 1-.7 0 .47 .47 0 0 1 .1-.7l-.2-.3z" fill-rule="evenodd"/>
<path d="M221.2 77.7l-.4 .7h.4zM221.3 77.4h.1v1h.3v.2h-.3v.3h-.2v-.3h-.6zM222.1 77.8a.26 .26 0 0 0 .5 0 .26 .26 0 0 0-.5 0zM222 78.5a.31 .31 0 0 0 .6 0 .31 .31 0 0 0-.6 0zM222 77.5a.44 .44 0 0 1 .7 0 .44 .44 0 0 1-.1 .6 .47 .47 0 0 1 .1 .7 .47 .47 0 0 1-.7 0 .47 .47 0 0 1 .1-.7l-.2-.3z" fill-rule="evenodd"/>
<path d="M208.3 81.4l-.4 .7h.4zM208.4 81.1h.1v1h.3v.2h-.3v.4h-.2v-.4h-.6zM209 81.3a.67 .67 0 0 1 .9 .2 .67 .67 0 0 1 0 .8 .47 .47 0 0 1-.5 .4 .47 .47 0 0 1-.5-.4h.2a.3 .3 0 0 0 .4 .2 .3 .3 0 0 0 .2-.3v-.2a.49 .49 0 0 1-.7 0 .49 .49 0 0 1 0-.7zM209.1 81.6a.35 .35 0 0 0 .7 0 .35 .35 0 0 0-.7 0z" fill-rule="evenodd"/>
<path d="M201.2 80.3l-.5 .7h.5zM201.2 80h.2v1h.2v.1h-.2v.4h-.2v-.4h-.7zM201.9 80.1a.67 .67 0 0 1 .8 .2 .67 .67 0 0 1 0 .9 .47 .47 0 0 1-.5 .4 .47 .47 0 0 1-.5-.4h.2a.3 .3 0 0 0 .4 .2 .3 .3 0 0 0 .2-.4l.1-.2a.49 .49 0 0 1-.8 .1 .49 .49 0 0 1 .1-.8zM201.9 80.5a.35 .35 0 0 0 .7 0 .35 .35 0 0 0-.7 0z" fill-rule="evenodd"/>
<path d="M213.6 81.2h.8v.1h-.7v.5a.53 .53 0 0 1 .7 .2 .53 .53 0 0 1-.3 .7 .53 .53 0 0 1-.7-.4h.2a.33 .33 0 0 0 .5 .1 .33 .33 0 0 0 .1-.5 .33 .33 0 0 0-.6 .1h-.1zM214.8 81.3a.6 .6 0 0 1 .8 0 .6 .6 0 0 1 .1 .8 .55 .55 0 0 1-.7 .6 .55 .55 0 0 1-.4-.8zM215 81.3a.84 .84 0 0 0 .1 1.2 .72 .72 0 0 0 .1-1.2z" fill-rule="evenodd"/>
<path d="M220.8 80h.8v.2h-.7l-.1 .4a.53 .53 0 0 1 .8 .3 .53 .53 0 0 1-.3 .7 .53 .53 0 0 1-.7-.5h.2a.33 .33 0 0 0 .5 .2 .33 .33 0 0 0 0-.5 .33 .33 0 0 0-.5 0h-.1zM222 80.1a.6 .6 0 0 1 .8 .1 .6 .6 0 0 1 0 .7 .55 .55 0 0 1-.6 .7 .55 .55 0 0 1-.4-.8zM222.2 80.2a.84 .84 0 0 0 .1 1.2 .72 .72 0 0 0 0-1.2z" fill-rule="evenodd"/>
<path d="M207.9 83.7h.8v.2h-.7l-.1 .4a.53 .53 0 0 1 .8 .3 .53 .53 0 0 1-.4 .7 .53 .53 0 0 1-.6-.5h.2a.33 .33 0 0 0 .5 .2 .33 .33 0 0 0 0-.5 .33 .33 0 0 0-.5 .1h-.2zM209 84l.6-.3v1.5h-.2v-1h-.4z" fill-rule="evenodd"/>
<path d="M200.7 82.6h.8v.2h-.7v.4a.53 .53 0 0 1 .7 .3 .53 .53 0 0 1-.3 .7 .53 .53 0 0 1-.7-.5h.2a.33 .33 0 0 0 .5 .2 .33 .33 0 0 0 0-.5 .33 .33 0 0 0-.5 0h-.1zM201.9 82.9l.5-.3v1.5h-.2v-1.1h-.3z" fill-rule="evenodd"/>
<path d="M213.6 83.7h.8v.2h-.7v.4a.53 .53 0 0 1 .7 .3 .53 .53 0 0 1-.3 .7 .53 .53 0 0 1-.7-.5h.2a.33 .33 0 0 0 .5 .2 .33 .33 0 0 0 .1-.5 .33 .33 0 0 0-.6 .1h-.1zM214.8 83.8a.53 .53 0 0 1 .9 .3 .53 .53 0 0 1-.6 .6l-.3 .4h.9v.1h-1.1l.2-.5a.6 .6 0 0 0 .6-.7l-.4-.1-.1 .3h-.2z" fill-rule="evenodd"/>
<path d="M220.8 82.6h.8v.2h-.7l-.1 .4a.53 .53 0 0 1 .8 .3 .53 .53 0 0 1-.3 .7 .53 .53 0 0 1-.7-.5h.2a.33 .33 0 0 0 .5 .2 .33 .33 0 0 0 0-.5 .33 .33 0 0 0-.5 0h-.1zM222 82.7a.53 .53 0 0 1 .9 .2 .53 .53 0 0 1-.6 .7l-.3 .3h.9v.2h-1.1l.2-.5a.6 .6 0 0 0 .6-.8h-.4l-.2 .3h-.2z" fill-rule="evenodd"/>
<path d="M206.7 168.3h.2v.6h.6v-.6h.2v1.3h-.2v-.6h-.6v.6h-.2zM208 168.6l.5-.2v1.2h-.2v-.9h-.3z" fill-rule="evenodd"/>
<path d="M207.8 99.5l.6-.3v1.5h-.2v-1.1h-.4z" fill-rule="evenodd"/>
<path d="M201.9 98.4l.5-.3v1.5h-.2v-1.1h-.3z" fill-rule="evenodd"/>
<path d="M214.9 99.3a.53 .53 0 0 1 .8 .2 .53 .53 0 0 1-.6 .7l-.2 .3h.8v.2h-1.1l.2-.5a.6 .6 0 0 0 .6-.8h-.4l-.1 .3h-.2z" fill-rule="evenodd"/>
<path d="M220.8 98.2a.53 .53 0 0 1 .8 .2 .53 .53 0 0 1-.5 .7l-.3 .3h.8v.2h-1l.2-.5a.6 .6 0 0 0 .6-.8h-.4l-.2 .3h-.2z" fill-rule="evenodd"/>
<path d="M207.9 101.9a.44 .44 0 0 1 .6-.1 .44 .44 0 0 1 0 .7 .5 .5 0 0 1-.1 .8 .5 .5 0 0 1-.7-.5h.2a.31 .31 0 0 0 .4 .4 .31 .31 0 0 0 0-.6h-.2v-.2a.25 .25 0 0 0 .4-.2 .25 .25 0 0 0-.3-.3l-.3 .2v.2h-.2z" fill-rule="evenodd"/>
<path d="M201.9 100.7a.44 .44 0 0 1 .7 0 .44 .44 0 0 1-.1 .7 .5 .5 0 0 1-.1 .8 .5 .5 0 0 1-.7-.5h.2a.31 .31 0 0 0 .5 .3 .31 .31 0 0 0 0-.5h-.3l.1-.2a.25 .25 0 0 0 .3-.2 .25 .25 0 0 0-.2-.3l-.3 .1-.1 .2h-.1z" fill-rule="evenodd"/>
<path d="M215.3 102.1l-.5 .7h.5zM215.3 101.8h.2v1h.2v.1h-.2v.4h-.2v-.4h-.7z" fill-rule="evenodd"/>
<path d="M221.2 100.9l-.4 .7h.4zM221.3 100.6h.1v1h.3v.2h-.3v.4h-.2v-.4h-.6z" fill-rule="evenodd"/>
<path d="M207.9 104.4h.8v.2h-.7l-.1 .4a.53 .53 0 0 1 .8 .2 .53 .53 0 0 1-.4 .8 .53 .53 0 0 1-.6-.5h.2a.33 .33 0 0 0 .5 .2 .33 .33 0 0 0 0-.6 .33 .33 0 0 0-.5 .1h-.2z" fill-rule="evenodd"/>
<path d="M201.9 103.2h.8v.2h-.6l-.1 .5a.53 .53 0 0 1 .7 .2 .53 .53 0 0 1-.3 .7 .53 .53 0 0 1-.7-.4h.2a.33 .33 0 0 0 .5 .1 .33 .33 0 0 0 .1-.5 .33 .33 0 0 0-.5 .1h-.2z" fill-rule="evenodd"/>
<path d="M214.8 104.5a.46 .46 0 0 1 .5-.2 .46 .46 0 0 1 .4 .5h-.2a.32 .32 0 0 0-.4-.3 .32 .32 0 0 0-.2 .4l-.1 .2a.52 .52 0 0 1 .9 .2 .52 .52 0 0 1-.4 .7 .52 .52 0 0 1-.6-.6zM214.9 105.4a.33 .33 0 0 0 .6 0 .33 .33 0 0 0-.6 0z" fill-rule="evenodd"/>
<path d="M220.8 103.4a.46 .46 0 0 1 .5-.2 .46 .46 0 0 1 .3 .4h-.2a.32 .32 0 0 0-.4-.2 .32 .32 0 0 0-.2 .4v.2a.52 .52 0 0 1 .8 .1 .52 .52 0 0 1-.4 .8 .52 .52 0 0 1-.6-.6zM220.8 104.3a.35 .35 0 0 0 .7 0 .35 .35 0 0 0-.7 0z" fill-rule="evenodd"/>
<path d="M207.7 107h1.1l-.7 1.5h-.2l.1-.3 .5-1h-.8z" fill-rule="evenodd"/>
<path d="M201.7 105.8h1.1l-.6 1.5h-.2v-.3l.6-1h-.9z" fill-rule="evenodd"/>
<path d="M214.9 107.3a.26 .26 0 0 0 .5 0 .26 .26 0 0 0-.5 0zM214.8 108a.35 .35 0 0 0 .7 0 .35 .35 0 0 0-.7 0zM214.8 107.1a.44 .44 0 0 1 .7-.1 .44 .44 0 0 1-.1 .6 .47 .47 0 0 1 .1 .7 .47 .47 0 0 1-.7 0 .47 .47 0 0 1 .1-.7l-.2-.3z" fill-rule="evenodd"/>
<path d="M220.8 106.2a.3 .3 0 0 0 .6 0 .3 .3 0 0 0-.6 0zM220.8 106.9a.31 .31 0 0 0 .6 0 .31 .31 0 0 0-.6 0zM220.8 105.9a.44 .44 0 0 1 .6-.1 .44 .44 0 0 1 0 .7 .47 .47 0 0 1 .1 .7 .47 .47 0 0 1-.7 0 .47 .47 0 0 1 .1-.7l-.3-.3z" fill-rule="evenodd"/>
<path d="M207.8 109.7a.67 .67 0 0 1 .9 .1 .67 .67 0 0 1-.1 .9 .47 .47 0 0 1-.4 .4 .47 .47 0 0 1-.5-.4h.2a.3 .3 0 0 0 .4 .2 .3 .3 0 0 0 .2-.3v-.3a.49 .49 0 0 1-.7 .1 .49 .49 0 0 1 0-.7zM207.9 110a.32 .32 0 0 0 .6 0 .32 .32 0 0 0-.6 0z" fill-rule="evenodd"/>
<path d="M201.9 108.5a.67 .67 0 0 1 .8 .2 .67 .67 0 0 1 0 .9 .47 .47 0 0 1-.5 .3 .47 .47 0 0 1-.4-.4h.2a.3 .3 0 0 0 .3 .3 .3 .3 0 0 0 .2-.4l.1-.2a.49 .49 0 0 1-.7 .1 .49 .49 0 0 1 0-.8zM201.9 108.9a.35 .35 0 0 0 .7 0 .35 .35 0 0 0-.7 0z" fill-rule="evenodd"/>
<path d="M213.6 109.8l.5-.3v1.5h-.2v-1h-.3zM214.8 109.7a.6 .6 0 0 1 .8 0 .6 .6 0 0 1 .1 .8 .55 .55 0 0 1-.7 .6 .55 .55 0 0 1-.4-.8zM215 109.7a.84 .84 0 0 0 .1 1.2 .72 .72 0 0 0 .1-1.2z" fill-rule="evenodd"/>
<path d="M220.7 108.7l.6-.3v1.5h-.2v-1.1h-.4zM222 108.5a.6 .6 0 0 1 .8 .1 .6 .6 0 0 1 0 .7 .55 .55 0 0 1-.6 .6 .55 .55 0 0 1-.4-.7zM222.2 108.6a.84 .84 0 0 0 .1 1.2 .72 .72 0 0 0 0-1.2z" fill-rule="evenodd"/>
<path d="M207.8 112.4l.6-.3v1.5h-.2v-1.1h-.4zM208.9 112.4l.5-.3v1.5h-.2v-1.1h-.3z" fill-rule="evenodd"/>
<path d="M200.8 111.3l.6-.3v1.5h-.2v-1.1h-.4zM201.9 111.3l.5-.3v1.5h-.2v-1.1h-.3z" fill-rule="evenodd"/>
<path d="M213.6 112.4l.5-.3v1.5h-.2v-1.1h-.3zM214.8 112.2a.53 .53 0 0 1 .9 .2 .53 .53 0 0 1-.6 .7l-.3 .3h.9v.2h-1.1l.2-.5a.6 .6 0 0 0 .6-.8h-.4l-.1 .3h-.2z" fill-rule="evenodd"/>
<path d="M220.7 111.3l.6-.3v1.5h-.2v-1.1h-.4zM222 111.1a.53 .53 0 0 1 .9 .2 .53 .53 0 0 1-.6 .7l-.3 .3h.9v.2h-1.1l.2-.5a.6 .6 0 0 0 .6-.8h-.4l-.2 .3h-.2z" fill-rule="evenodd"/>
<path d="M207.8 115l.6-.3v1.5h-.2v-1.1h-.4zM209.1 114.8a.44 .44 0 0 1 .7-.1 .44 .44 0 0 1-.1 .7 .5 .5 0 0 1-.1 .9 .5 .5 0 0 1-.7-.6h.2a.31 .31 0 0 0 .4 .4 .31 .31 0 0 0 0-.6h-.2l.1-.2a.25 .25 0 0 0 .3-.2 .25 .25 0 0 0-.3-.3l-.2 .2-.1 .2h-.2z" fill-rule="evenodd"/>
<path d="M200.6 113.8l.6-.3v1.6h-.2v-1.1h-.4zM201.9 113.6a.44 .44 0 0 1 .7 0 .44 .44 0 0 1-.1 .7 .5 .5 0 0 1-.1 .8 .5 .5 0 0 1-.7-.5h.2a.31 .31 0 0 0 .4 .3 .31 .31 0 0 0 .1-.5h-.3l.1-.2a.25 .25 0 0 0 .3-.2 .25 .25 0 0 0-.3-.3l-.2 .1-.1 .2h-.2z" fill-rule="evenodd"/>
<path d="M213.6 115l.5-.3v1.5h-.2v-1.1h-.3zM215.3 115l-.5 .7h.5zM215.3 114.7h.2v1h.2v.1h-.2v.4h-.2v-.4h-.7z" fill-rule="evenodd"/>
<path d="M220.7 113.8l.6-.3v1.6h-.2v-1.1h-.4zM222.5 113.8l-.5 .7h.5zM222.5 113.5h.2v1h.2v.2h-.2v.4h-.2v-.4h-.7z" fill-rule="evenodd"/>
<path d="M207.8 117.6l.6-.3v1.5h-.2v-1.1h-.4zM209.1 117.3h.8v.2h-.7v.4a.53 .53 0 0 1 .7 .2 .53 .53 0 0 1-.3 .8 .53 .53 0 0 1-.7-.5h.2a.33 .33 0 0 0 .5 .2 .33 .33 0 0 0 0-.6 .33 .33 0 0 0-.5 .1h-.1z" fill-rule="evenodd"/>
<path d="M200.6 116.4l.6-.3v1.5h-.2v-1h-.4zM201.9 116.1h.8v.2h-.7v.5a.53 .53 0 0 1 .7 .2 .53 .53 0 0 1-.3 .7 .53 .53 0 0 1-.7-.4h.2a.33 .33 0 0 0 .5 .1 .33 .33 0 0 0 .1-.5 .33 .33 0 0 0-.6 .1h-.1z" fill-rule="evenodd"/>
<path d="M213.6 117.6l.5-.3v1.5h-.2v-1.1h-.3zM214.8 117.4a.46 .46 0 0 1 .5-.2 .46 .46 0 0 1 .3 .5h-.1a.32 .32 0 0 0-.4-.3 .32 .32 0 0 0-.2 .4l-.1 .2a.52 .52 0 0 1 .8 .2 .52 .52 0 0 1-.3 .7 .52 .52 0 0 1-.6-.6zM214.9 118.3a.33 .33 0 0 0 .6 0 .33 .33 0 0 0-.6 0z" fill-rule="evenodd"/>
<path d="M220.7 116.4l.6-.3v1.5h-.2v-1h-.4zM222 116.3a.46 .46 0 0 1 .5-.2 .46 .46 0 0 1 .3 .4h-.2a.32 .32 0 0 0-.3-.2 .32 .32 0 0 0-.3 .4v.2a.52 .52 0 0 1 .8 .1 .52 .52 0 0 1-.4 .8 .52 .52 0 0 1-.6-.6zM222 117.2a.35 .35 0 0 0 .7 0 .35 .35 0 0 0-.7 0z" fill-rule="evenodd"/>
<path d="M207.8 120.1l.6-.3v1.6h-.2v-1.1h-.4zM208.9 119.9h1.1l-.7 1.5h-.2l.1-.3 .6-1h-.9z" fill-rule="evenodd"/>
<path d="M200.6 119l.6-.3v1.5h-.2v-1.1h-.4zM201.7 118.7h1.1l-.6 1.5h-.3l.1-.3 .6-1h-.9z" fill-rule="evenodd"/>
<path d="M213.6 120.1l.5-.3v1.6h-.2v-1.1h-.3zM214.9 120.2a.26 .26 0 0 0 .5 0 .26 .26 0 0 0-.5 0zM214.8 120.9a.35 .35 0 0 0 .7 0 .35 .35 0 0 0-.7 0zM214.8 120a.44 .44 0 0 1 .7-.1 .44 .44 0 0 1-.1 .6 .47 .47 0 0 1 .1 .7 .47 .47 0 0 1-.7 0 .47 .47 0 0 1 .1-.7l-.2-.3z" fill-rule="evenodd"/>
<path d="M220.7 119l.6-.3v1.5h-.2v-1.1h-.4zM222.1 119.1a.26 .26 0 0 0 .5 0 .26 .26 0 0 0-.5 0zM222 119.8a.31 .31 0 0 0 .6 0 .31 .31 0 0 0-.6 0zM222 118.8a.44 .44 0 0 1 .7-.1 .44 .44 0 0 1-.1 .7 .47 .47 0 0 1 .1 .7 .47 .47 0 0 1-.7 0 .47 .47 0 0 1 .1-.7l-.2-.3z" fill-rule="evenodd"/>
<path d="M207.8 122.7l.6-.3v1.5h-.2v-1h-.4zM209 122.6a.67 .67 0 0 1 .9 .1 .67 .67 0 0 1 0 .9 .47 .47 0 0 1-.5 .4 .47 .47 0 0 1-.5-.4h.2a.3 .3 0 0 0 .4 .2 .3 .3 0 0 0 .2-.3v-.3a.49 .49 0 0 1-.7 .1 .49 .49 0 0 1 0-.7zM209.1 122.9a.35 .35 0 0 0 .7 0 .35 .35 0 0 0-.7 0z" fill-rule="evenodd"/>
<path d="M200.6 121.6l.6-.3v1.5h-.2v-1.1h-.4zM201.9 121.4a.67 .67 0 0 1 .8 .2 .67 .67 0 0 1 0 .9 .47 .47 0 0 1-.5 .3 .47 .47 0 0 1-.5-.4h.2a.3 .3 0 0 0 .4 .3 .3 .3 0 0 0 .2-.4l.1-.2a.49 .49 0 0 1-.8 .1 .49 .49 0 0 1 .1-.8zM201.9 121.8a.35 .35 0 0 0 .7 0 .35 .35 0 0 0-.7 0z" fill-rule="evenodd"/>
<path d="M213.6 122.5a.53 .53 0 0 1 .9 .3 .53 .53 0 0 1-.6 .6l-.3 .4h.9v.1h-1.1l.2-.4a.6 .6 0 0 0 .6-.8l-.4-.1-.2 .4h-.2zM214.8 122.6a.6 .6 0 0 1 .8 0 .6 .6 0 0 1 .1 .8 .55 .55 0 0 1-.7 .6 .55 .55 0 0 1-.4-.8zM215 122.6a.84 .84 0 0 0 .1 1.2 .72 .72 0 0 0 .1-1.2z" fill-rule="evenodd"/>
<path d="M220.8 121.4a.53 .53 0 0 1 .8 .2 .53 .53 0 0 1-.5 .7l-.3 .3h.8v.2h-1l.2-.5a.6 .6 0 0 0 .6-.8h-.4l-.2 .3h-.2zM222 121.4a.6 .6 0 0 1 .8 .1 .6 .6 0 0 1 0 .7 .55 .55 0 0 1-.6 .6 .55 .55 0 0 1-.4-.7zM222.2 121.5a.84 .84 0 0 0 .1 1.2 .72 .72 0 0 0 0-1.2z" fill-rule="evenodd"/>
<path d="M207.9 125.1a.53 .53 0 0 1 .8 .2 .53 .53 0 0 1-.5 .7l-.3 .3h.8v.2h-1l.2-.5a.6 .6 0 0 0 .6-.8h-.4l-.2 .3h-.2zM209 125.3l.6-.3v1.5h-.2v-1.1h-.4z" fill-rule="evenodd"/>
<path d="M200.7 124a.53 .53 0 0 1 .9 .2 .53 .53 0 0 1-.6 .7l-.3 .3h.9v.2h-1.1l.2-.5a.6 .6 0 0 0 .6-.8h-.4l-.2 .3h-.2zM201.9 124.2l.5-.3v1.5h-.2v-1.1h-.3z" fill-rule="evenodd"/>
<path d="M213.6 125.1a.53 .53 0 0 1 .9 .2 .53 .53 0 0 1-.6 .7l-.3 .3h.9v.2h-1.1l.2-.5a.6 .6 0 0 0 .6-.8h-.4l-.2 .3h-.2zM214.8 125.1a.53 .53 0 0 1 .9 .2 .53 .53 0 0 1-.6 .7l-.3 .3h.9v.2h-1.1l.2-.5a.6 .6 0 0 0 .6-.8h-.4l-.1 .3h-.2z" fill-rule="evenodd"/>
<path d="M220.8 124a.53 .53 0 0 1 .8 .2 .53 .53 0 0 1-.5 .7l-.3 .3h.8v.2h-1l.2-.5a.6 .6 0 0 0 .6-.8h-.4l-.2 .3h-.2zM222 124a.53 .53 0 0 1 .9 .2 .53 .53 0 0 1-.6 .7l-.3 .3h.9v.2h-1.1l.2-.5a.6 .6 0 0 0 .6-.8h-.4l-.2 .3h-.2z" fill-rule="evenodd"/>
<path d="M207.9 127.7a.53 .53 0 0 1 .8 .2 .53 .53 0 0 1-.5 .7l-.3 .3h.8v.2h-1l.2-.5a.6 .6 0 0 0 .6-.8h-.4l-.2 .3h-.2zM209.1 127.7a.44 .44 0 0 1 .7-.1 .44 .44 0 0 1-.1 .7 .5 .5 0 0 1-.1 .9 .5 .5 0 0 1-.7-.6h.2a.31 .31 0 0 0 .4 .4 .31 .31 0 0 0 0-.6h-.2l.1-.2a.25 .25 0 0 0 .3-.2 .25 .25 0 0 0-.3-.2l-.2 .1-.1 .2h-.2z" fill-rule="evenodd"/>
<path d="M200.7 126.5a.53 .53 0 0 1 .9 .3 .53 .53 0 0 1-.6 .7l-.3 .3h.9v.2h-1.1l.2-.5a.6 .6 0 0 0 .6-.8h-.4l-.2 .3h-.2zM201.9 126.5a.44 .44 0 0 1 .7 0 .44 .44 0 0 1-.1 .7 .5 .5 0 0 1-.1 .8 .5 .5 0 0 1-.7-.5h.2a.31 .31 0 0 0 .4 .3 .31 .31 0 0 0 .1-.5h-.3l.1-.2a.25 .25 0 0 0 .3-.2 .25 .25 0 0 0-.3-.3l-.2 .1-.1 .2h-.2z" fill-rule="evenodd"/>
<path d="M213.6 127.7a.53 .53 0 0 1 .9 .2 .53 .53 0 0 1-.6 .7l-.3 .3h.9v.2h-1.1l.2-.5a.6 .6 0 0 0 .6-.8h-.4l-.2 .3h-.2zM215.3 127.9l-.5 .7h.5zM215.3 127.6h.2v1h.2v.1h-.2v.4h-.2v-.4h-.7z" fill-rule="evenodd"/>
<path d="M220.8 126.5a.53 .53 0 0 1 .8 .3 .53 .53 0 0 1-.5 .7l-.3 .3h.8v.2h-1l.2-.5a.6 .6 0 0 0 .6-.8h-.4l-.2 .3h-.2zM222.5 126.7l-.5 .7h.5zM222.5 126.4h.2v1h.2v.2h-.2v.4h-.2v-.4h-.7z" fill-rule="evenodd"/>
<path d="M207.9 130.3a.53 .53 0 0 1 .8 .2 .53 .53 0 0 1-.5 .7l-.3 .3h.8v.2h-1l.2-.5a.6 .6 0 0 0 .6-.8h-.4l-.2 .3h-.2zM209.1 130.2h.8v.2h-.7v.4a.53 .53 0 0 1 .7 .2 .53 .53 0 0 1-.3 .8 .53 .53 0 0 1-.7-.5h.2a.33 .33 0 0 0 .5 .2 .33 .33 0 0 0 0-.6 .33 .33 0 0 0-.5 .1h-.1z" fill-rule="evenodd"/>
<path d="M200.7 129.1a.53 .53 0 0 1 .9 .3 .53 .53 0 0 1-.6 .7l-.3 .3h.9v.1h-1.1l.2-.4a.6 .6 0 0 0 .6-.8l-.4-.1-.2 .4h-.2zM201.9 129.1h.8v.1h-.7v.5a.53 .53 0 0 1 .7 .2 .53 .53 0 0 1-.3 .7 .53 .53 0 0 1-.7-.4h.2a.33 .33 0 0 0 .5 .1 .33 .33 0 0 0 .1-.5 .33 .33 0 0 0-.6 .1h-.1z" fill-rule="evenodd"/>
<path d="M213.6 130.3a.53 .53 0 0 1 .9 .2 .53 .53 0 0 1-.6 .7l-.3 .3h.9v.2h-1.1l.2-.5a.6 .6 0 0 0 .6-.8h-.4l-.2 .3h-.2zM214.8 130.3a.46 .46 0 0 1 .5-.2 .46 .46 0 0 1 .3 .5h-.1a.32 .32 0 0 0-.4-.3 .32 .32 0 0 0-.2 .4l-.1 .2a.52 .52 0 0 1 .8 .2 .52 .52 0 0 1-.3 .7 .52 .52 0 0 1-.6-.6zM214.9 131.2a.33 .33 0 0 0 .6 0 .33 .33 0 0 0-.6 0z" fill-rule="evenodd"/>
<path d="M220.8 129.1a.53 .53 0 0 1 .8 .3 .53 .53 0 0 1-.5 .7l-.3 .3h.8v.1h-1l.2-.4a.6 .6 0 0 0 .6-.8l-.4-.1-.2 .4h-.2zM222 129.2a.46 .46 0 0 1 .5-.2 .46 .46 0 0 1 .3 .4h-.2a.32 .32 0 0 0-.3-.2 .32 .32 0 0 0-.3 .4v.2a.52 .52 0 0 1 .8 .1 .52 .52 0 0 1-.4 .8 .52 .52 0 0 1-.6-.6zM222 130.1a.35 .35 0 0 0 .7 0 .35 .35 0 0 0-.7 0z" fill-rule="evenodd"/>
<path d="M207.9 132.8a.53 .53 0 0 1 .8 .3 .53 .53 0 0 1-.5 .7l-.3 .3h.8v.2h-1l.2-.5a.6 .6 0 0 0 .6-.8l-.4-.1-.2 .4h-.2zM208.9 132.8h1.1l-.7 1.5h-.2l.1-.3 .6-1h-.9z" fill-rule="evenodd"/>
<path d="M200.7 131.7a.53 .53 0 0 1 .9 .2 .53 .53 0 0 1-.6 .7l-.3 .3h.9v.2h-1.1l.2-.5a.6 .6 0 0 0 .6-.7l-.4-.1-.2 .3h-.2zM201.7 131.6h1.1l-.6 1.5h-.3l.1-.3 .6-1h-.9z" fill-rule="evenodd"/>
<path d="M213.6 132.8a.53 .53 0 0 1 .9 .3 .53 .53 0 0 1-.6 .7l-.3 .3h.9v.2h-1.1l.2-.5a.6 .6 0 0 0 .6-.8l-.4-.1-.2 .4h-.2zM214.9 133.2a.26 .26 0 0 0 .5 0 .26 .26 0 0 0-.5 0zM214.8 133.8a.35 .35 0 0 0 .7 0 .35 .35 0 0 0-.7 0zM214.8 132.9a.44 .44 0 0 1 .7-.1 .44 .44 0 0 1-.1 .6 .47 .47 0 0 1 .1 .7 .47 .47 0 0 1-.7 0 .47 .47 0 0 1 .1-.7l-.2-.3z" fill-rule="evenodd"/>
<path d="M220.8 131.7a.53 .53 0 0 1 .8 .2 .53 .53 0 0 1-.5 .7l-.3 .3h.8v.2h-1l.2-.5a.6 .6 0 0 0 .6-.7l-.4-.1-.2 .3h-.2zM222.1 132a.26 .26 0 0 0 .5 0 .26 .26 0 0 0-.5 0zM222 132.7a.31 .31 0 0 0 .6 0 .31 .31 0 0 0-.6 0zM222 131.7a.44 .44 0 0 1 .7-.1 .44 .44 0 0 1-.1 .7 .47 .47 0 0 1 .1 .7 .47 .47 0 0 1-.7 0 .47 .47 0 0 1 .1-.7l-.2-.3z" fill-rule="evenodd"/>
<path d="M207.9 135.4a.53 .53 0 0 1 .8 .3 .53 .53 0 0 1-.5 .6l-.3 .4h.8v.1h-1l.2-.4a.6 .6 0 0 0 .6-.8l-.4-.1-.2 .4h-.2zM209 135.5a.67 .67 0 0 1 .9 .2 .67 .67 0 0 1 0 .8 .47 .47 0 0 1-.5 .4 .47 .47 0 0 1-.5-.4h.2a.3 .3 0 0 0 .4 .2 .3 .3 0 0 0 .2-.3v-.3a.49 .49 0 0 1-.7 .1 .49 .49 0 0 1 0-.7zM209.1 135.8a.35 .35 0 0 0 .7 0 .35 .35 0 0 0-.7 0z" fill-rule="evenodd"/>
<path d="M200.7 134.3a.53 .53 0 0 1 .9 .2 .53 .53 0 0 1-.6 .7l-.3 .3h.9v.2h-1.1l.2-.5a.6 .6 0 0 0 .6-.8h-.4l-.2 .3h-.2zM201.9 134.3a.67 .67 0 0 1 .8 .2 .67 .67 0 0 1 0 .9 .47 .47 0 0 1-.5 .4 .47 .47 0 0 1-.5-.5h.2a.3 .3 0 0 0 .4 .3 .3 .3 0 0 0 .2-.4l.1-.2a.49 .49 0 0 1-.8 .1 .49 .49 0 0 1 .1-.8zM201.9 134.7a.35 .35 0 0 0 .7 0 .35 .35 0 0 0-.7 0z" fill-rule="evenodd"/>
<path d="M213.6 135.4a.44 .44 0 0 1 .7 0 .44 .44 0 0 1-.1 .6 .5 .5 0 0 1-.1 .9 .5 .5 0 0 1-.7-.5h.2a.31 .31 0 0 0 .4 .3 .31 .31 0 0 0 0-.5l-.2-.1 .1-.1a.25 .25 0 0 0 .3-.2 .25 .25 0 0 0-.3-.3l-.2 .1-.1 .2h-.2zM214.8 135.5a.6 .6 0 0 1 .8 0 .6 .6 0 0 1 .1 .8 .55 .55 0 0 1-.7 .6 .55 .55 0 0 1-.4-.8zM215 135.5a.84 .84 0 0 0 .1 1.2 .72 .72 0 0 0 .1-1.2z" fill-rule="evenodd"/>
<path d="M220.8 134.3a.44 .44 0 0 1 .6-.1 .44 .44 0 0 1 0 .7 .5 .5 0 0 1-.1 .9 .5 .5 0 0 1-.7-.6h.2a.31 .31 0 0 0 .4 .4 .31 .31 0 0 0 0-.6h-.2v-.2a.25 .25 0 0 0 .4-.2 .25 .25 0 0 0-.3-.2l-.2 .1-.1 .2h-.2zM222 134.3a.6 .6 0 0 1 .8 .1 .6 .6 0 0 1 0 .7 .55 .55 0 0 1-.6 .6 .55 .55 0 0 1-.4-.7zM222.2 134.4a.84 .84 0 0 0 .1 1.2 .72 .72 0 0 0 0-1.2z" fill-rule="evenodd"/>
<path d="M207.9 138a.44 .44 0 0 1 .6 0 .44 .44 0 0 1 0 .6 .5 .5 0 0 1-.1 .9 .5 .5 0 0 1-.7-.5h.2a.31 .31 0 0 0 .4 .3 .31 .31 0 0 0 0-.6h-.2v-.1a.25 .25 0 0 0 .4-.2 .25 .25 0 0 0-.3-.3l-.3 .1v.2h-.2zM209 138.2l.6-.3v1.5h-.2v-1.1h-.4z" fill-rule="evenodd"/>
<path d="M200.7 136.9a.44 .44 0 0 1 .7-.1 .44 .44 0 0 1-.1 .7 .5 .5 0 0 1-.1 .8 .5 .5 0 0 1-.7-.5h.2a.31 .31 0 0 0 .4 .3 .31 .31 0 0 0 0-.5h-.2l.1-.2a.25 .25 0 0 0 .3-.2 .25 .25 0 0 0-.3-.3l-.2 .2-.1 .2h-.2zM201.9 137.1l.5-.3v1.5h-.2v-1.1h-.3z" fill-rule="evenodd"/>
<path d="M213.6 138a.44 .44 0 0 1 .7-.1 .44 .44 0 0 1-.1 .7 .5 .5 0 0 1-.1 .9 .5 .5 0 0 1-.7-.5h.2a.31 .31 0 0 0 .4 .3 .31 .31 0 0 0 0-.6h-.2l.1-.1a.25 .25 0 0 0 .3-.2 .25 .25 0 0 0-.3-.3l-.2 .1-.1 .2h-.2zM214.8 138a.53 .53 0 0 1 .9 .2 .53 .53 0 0 1-.6 .7l-.3 .3h.9v.2h-1.1l.2-.5a.6 .6 0 0 0 .6-.8h-.4l-.1 .3h-.2z" fill-rule="evenodd"/>
<path d="M220.8 136.9a.44 .44 0 0 1 .6-.1 .44 .44 0 0 1 0 .7 .5 .5 0 0 1-.1 .8 .5 .5 0 0 1-.7-.5h.2a.31 .31 0 0 0 .4 .3 .31 .31 0 0 0 0-.5h-.2v-.2a.25 .25 0 0 0 .4-.2 .25 .25 0 0 0-.3-.3l-.2 .2-.1 .2h-.2zM222 136.9a.53 .53 0 0 1 .9 .2 .53 .53 0 0 1-.6 .7l-.3 .3h.9v.2h-1.1l.2-.5a.6 .6 0 0 0 .6-.8h-.4l-.2 .3h-.2z" fill-rule="evenodd"/>
<path d="M207.9 140.6a.44 .44 0 0 1 .6-.1 .44 .44 0 0 1 0 .7 .5 .5 0 0 1-.1 .9 .5 .5 0 0 1-.7-.6h.2a.31 .31 0 0 0 .4 .4 .31 .31 0 0 0 0-.6h-.2v-.2a.25 .25 0 0 0 .4-.2 .25 .25 0 0 0-.3-.2l-.3 .1v.2h-.2zM209.1 140.6a.44 .44 0 0 1 .7-.1 .44 .44 0 0 1-.1 .7 .5 .5 0 0 1-.1 .9 .5 .5 0 0 1-.7-.6h.2a.31 .31 0 0 0 .4 .4 .31 .31 0 0 0 0-.6h-.2l.1-.2a.25 .25 0 0 0 .3-.2 .25 .25 0 0 0-.3-.2l-.2 .1-.1 .2h-.2z" fill-rule="evenodd"/>
<path d="M200.7 139.4a.44 .44 0 0 1 .7 0 .44 .44 0 0 1-.1 .7 .5 .5 0 0 1-.1 .8 .5 .5 0 0 1-.7-.5h.2a.31 .31 0 0 0 .4 .3 .31 .31 0 0 0 0-.5h-.2l.1-.2a.25 .25 0 0 0 .3-.2 .25 .25 0 0 0-.3-.3l-.2 .1-.1 .2h-.2zM201.9 139.4a.44 .44 0 0 1 .7 0 .44 .44 0 0 1-.1 .7 .5 .5 0 0 1-.1 .8 .5 .5 0 0 1-.7-.5h.2a.31 .31 0 0 0 .4 .3 .31 .31 0 0 0 .1-.5h-.3l.1-.2a.25 .25 0 0 0 .3-.2 .25 .25 0 0 0-.3-.3l-.2 .1-.1 .2h-.2z" fill-rule="evenodd"/>
<path d="M213.6 140.6a.44 .44 0 0 1 .7-.1 .44 .44 0 0 1-.1 .7 .5 .5 0 0 1-.1 .9 .5 .5 0 0 1-.7-.6h.2a.31 .31 0 0 0 .4 .4 .31 .31 0 0 0 0-.6h-.2l.1-.2a.25 .25 0 0 0 .3-.2 .25 .25 0 0 0-.3-.2l-.2 .1-.1 .2h-.2zM215.3 140.8l-.5 .7h.5zM215.3 140.5h.2v1h.2v.1h-.2v.4h-.2v-.4h-.7z" fill-rule="evenodd"/>
<path d="M220.8 139.4a.44 .44 0 0 1 .6 0 .44 .44 0 0 1 0 .7 .5 .5 0 0 1-.1 .8 .5 .5 0 0 1-.7-.5h.2a.31 .31 0 0 0 .4 .3 .31 .31 0 0 0 0-.5h-.2v-.2a.25 .25 0 0 0 .4-.2 .25 .25 0 0 0-.3-.3l-.2 .1-.1 .2h-.2zM222.5 139.6l-.5 .7h.5zM222.5 139.3h.2v1h.2v.2h-.2v.4h-.2v-.4h-.7z" fill-rule="evenodd"/>
<path d="M207.9 143.2a.44 .44 0 0 1 .6-.1 .44 .44 0 0 1 0 .7 .5 .5 0 0 1-.1 .8 .5 .5 0 0 1-.7-.5h.2a.31 .31 0 0 0 .4 .3 .31 .31 0 0 0 0-.5h-.2v-.2a.25 .25 0 0 0 .4-.2 .25 .25 0 0 0-.3-.3l-.3 .2v.2h-.2zM209.1 143.1h.8v.2h-.7v.4a.53 .53 0 0 1 .7 .2 .53 .53 0 0 1-.3 .8 .53 .53 0 0 1-.7-.5h.2a.33 .33 0 0 0 .5 .2 .33 .33 0 0 0 0-.6 .33 .33 0 0 0-.5 .1h-.1z" fill-rule="evenodd"/>
<path d="M200.7 142a.44 .44 0 0 1 .7 0 .44 .44 0 0 1-.1 .6 .5 .5 0 0 1-.1 .9 .5 .5 0 0 1-.7-.5h.2a.31 .31 0 0 0 .4 .3 .31 .31 0 0 0 0-.5l-.2-.1 .1-.1a.25 .25 0 0 0 .3-.2 .25 .25 0 0 0-.3-.3l-.2 .1-.1 .2h-.2zM201.9 142h.8v.1h-.7v.5a.53 .53 0 0 1 .7 .2 .53 .53 0 0 1-.3 .7 .53 .53 0 0 1-.7-.4h.2a.33 .33 0 0 0 .5 .1 .33 .33 0 0 0 .1-.5 .33 .33 0 0 0-.6 .1h-.1z" fill-rule="evenodd"/>
<path d="M213.6 143.2a.44 .44 0 0 1 .7-.1 .44 .44 0 0 1-.1 .7 .5 .5 0 0 1-.1 .8 .5 .5 0 0 1-.7-.5h.2a.31 .31 0 0 0 .4 .3 .31 .31 0 0 0 0-.5h-.2l.1-.2a.25 .25 0 0 0 .3-.2 .25 .25 0 0 0-.3-.3l-.2 .2-.1 .2h-.2zM214.8 143.2a.46 .46 0 0 1 .5-.2 .46 .46 0 0 1 .3 .5h-.1a.32 .32 0 0 0-.4-.3 .32 .32 0 0 0-.2 .4l-.1 .2a.52 .52 0 0 1 .8 .2 .52 .52 0 0 1-.3 .7 .52 .52 0 0 1-.6-.6zM214.9 144.1a.33 .33 0 0 0 .6 0 .33 .33 0 0 0-.6 0z" fill-rule="evenodd"/>
<path d="M220.8 142a.44 .44 0 0 1 .6 0 .44 .44 0 0 1 0 .6 .5 .5 0 0 1-.1 .9 .5 .5 0 0 1-.7-.5h.2a.31 .31 0 0 0 .4 .3 .31 .31 0 0 0 0-.5l-.2-.1v-.1a.25 .25 0 0 0 .4-.2 .25 .25 0 0 0-.3-.3l-.2 .1-.1 .2h-.2zM222 142.1a.46 .46 0 0 1 .5-.2 .46 .46 0 0 1 .3 .4h-.2a.32 .32 0 0 0-.3-.2 .32 .32 0 0 0-.3 .4v.2a.52 .52 0 0 1 .8 .1 .52 .52 0 0 1-.4 .8 .52 .52 0 0 1-.6-.6zM222 143a.35 .35 0 0 0 .7 0 .35 .35 0 0 0-.7 0z" fill-rule="evenodd"/>
<path d="M207.9 145.7a.44 .44 0 0 1 .6 0 .44 .44 0 0 1 0 .7 .5 .5 0 0 1-.1 .8 .5 .5 0 0 1-.7-.5h.2a.31 .31 0 0 0 .4 .3 .31 .31 0 0 0 0-.5h-.2v-.2a.25 .25 0 0 0 .4-.2 .25 .25 0 0 0-.3-.3l-.3 .1v.2h-.2zM208.9 145.7h1.1l-.7 1.5h-.2l.1-.3 .6-1h-.9z" fill-rule="evenodd"/>
<path d="M200.7 144.6a.44 .44 0 0 1 .7 0 .44 .44 0 0 1-.1 .6 .5 .5 0 0 1-.1 .9 .5 .5 0 0 1-.7-.5h.2a.31 .31 0 0 0 .4 .3 .31 .31 0 0 0 0-.6h-.2l.1-.1a.25 .25 0 0 0 .3-.2 .25 .25 0 0 0-.3-.3l-.2 .1-.1 .2h-.2zM201.7 144.5h1.1l-.6 1.5h-.3l.1-.3 .6-1h-.9z" fill-rule="evenodd"/>
<path d="M213.6 145.7a.44 .44 0 0 1 .7 0 .44 .44 0 0 1-.1 .7 .5 .5 0 0 1-.1 .8 .5 .5 0 0 1-.7-.5h.2a.31 .31 0 0 0 .4 .3 .31 .31 0 0 0 0-.5h-.2l.1-.2a.25 .25 0 0 0 .3-.2 .25 .25 0 0 0-.3-.3l-.2 .1-.1 .2h-.2zM214.9 146.1a.26 .26 0 0 0 .5 0 .26 .26 0 0 0-.5 0zM214.8 146.8a.35 .35 0 0 0 .7 0 .35 .35 0 0 0-.7 0zM214.8 145.8a.44 .44 0 0 1 .7-.1 .44 .44 0 0 1-.1 .7 .47 .47 0 0 1 .1 .6 .47 .47 0 0 1-.7 .1 .47 .47 0 0 1 .1-.7l-.2-.3z" fill-rule="evenodd"/>
<path d="M220.8 144.6a.44 .44 0 0 1 .6 0 .44 .44 0 0 1 0 .6 .5 .5 0 0 1-.1 .9 .5 .5 0 0 1-.7-.5h.2a.31 .31 0 0 0 .4 .3 .31 .31 0 0 0 0-.6h-.2v-.1a.25 .25 0 0 0 .4-.2 .25 .25 0 0 0-.3-.3l-.2 .1-.1 .2h-.2zM222.1 144.9a.26 .26 0 0 0 .5 0 .26 .26 0 0 0-.5 0zM222 145.6a.31 .31 0 0 0 .6 0 .31 .31 0 0 0-.6 0zM222 144.6a.44 .44 0 0 1 .7-.1 .44 .44 0 0 1-.1 .7 .47 .47 0 0 1 .1 .7 .47 .47 0 0 1-.7 0 .47 .47 0 0 1 .1-.7l-.2-.3z" fill-rule="evenodd"/>
<path d="M207.9 148.3a.44 .44 0 0 1 .6 0 .44 .44 0 0 1 0 .6 .5 .5 0 0 1-.1 .9 .5 .5 0 0 1-.7-.5h.2a.31 .31 0 0 0 .4 .3 .31 .31 0 0 0 0-.5l-.2-.1v-.1a.25 .25 0 0 0 .4-.2 .25 .25 0 0 0-.3-.3l-.3 .1v.2h-.2zM209 148.4a.67 .67 0 0 1 .9 .2 .67 .67 0 0 1 0 .8 .47 .47 0 0 1-.5 .4 .47 .47 0 0 1-.5-.4h.2a.3 .3 0 0 0 .4 .2 .3 .3 0 0 0 .2-.3v-.2a.49 .49 0 0 1-.7 0 .49 .49 0 0 1 0-.7zM209.1 148.7a.35 .35 0 0 0 .7 0 .35 .35 0 0 0-.7 0z" fill-rule="evenodd"/>
<path d="M200.7 147.2a.44 .44 0 0 1 .7-.1 .44 .44 0 0 1-.1 .7 .5 .5 0 0 1-.1 .9 .5 .5 0 0 1-.7-.6h.2a.31 .31 0 0 0 .4 .4 .31 .31 0 0 0 0-.6h-.2l.1-.2a.25 .25 0 0 0 .3-.2 .25 .25 0 0 0-.3-.2l-.2 .1-.1 .2h-.2zM201.9 147.2a.67 .67 0 0 1 .8 .2 .67 .67 0 0 1 0 .9 .47 .47 0 0 1-.5 .4 .47 .47 0 0 1-.5-.5h.2a.3 .3 0 0 0 .4 .3 .3 .3 0 0 0 .2-.4l.1-.2a.49 .49 0 0 1-.8 .1 .49 .49 0 0 1 .1-.8zM201.9 147.6a.35 .35 0 0 0 .7 0 .35 .35 0 0 0-.7 0z" fill-rule="evenodd"/>
<path d="M214.1 148.5l-.5 .7h.5zM214.1 148.2h.2v1h.2v.2h-.2v.3h-.2v-.3h-.7zM214.8 148.4a.6 .6 0 0 1 .8 0 .6 .6 0 0 1 .1 .8 .55 .55 0 0 1-.7 .6 .55 .55 0 0 1-.4-.8zM215 148.4a.84 .84 0 0 0 .1 1.2 .72 .72 0 0 0 .1-1.2z" fill-rule="evenodd"/>
<path d="M221.2 147.4l-.4 .7h.4zM221.3 147.1h.1v1h.3v.1h-.3v.4h-.2v-.4h-.6zM222 147.2a.6 .6 0 0 1 .8 .1 .6 .6 0 0 1 0 .7 .55 .55 0 0 1-.6 .6 .55 .55 0 0 1-.4-.7zM222.2 147.3a.84 .84 0 0 0 .1 1.2 .72 .72 0 0 0 0-1.2z" fill-rule="evenodd"/>
<path d="M208.3 151.1l-.4 .7h.4zM208.4 150.8h.1v1h.3v.2h-.3v.3h-.2v-.3h-.6zM209 151.1l.6-.3v1.5h-.2v-1.1h-.4z" fill-rule="evenodd"/>
<path d="M201.2 150l-.5 .7h.5zM201.2 149.7h.2v1h.2v.1h-.2v.4h-.2v-.4h-.7zM201.9 150l.5-.3v1.5h-.2v-1.1h-.3z" fill-rule="evenodd"/>
<path d="M214.1 151.1l-.5 .7h.5zM214.1 150.8h.2v1h.2v.2h-.2v.3h-.2v-.3h-.7zM214.8 150.9a.53 .53 0 0 1 .9 .2 .53 .53 0 0 1-.6 .7l-.3 .3h.9v.2h-1.1l.2-.5a.6 .6 0 0 0 .6-.7l-.4-.1-.1 .3h-.2z" fill-rule="evenodd"/>
<path d="M221.2 150l-.4 .7h.4zM221.3 149.7h.1v1h.3v.1h-.3v.4h-.2v-.4h-.6zM222 149.8a.53 .53 0 0 1 .9 .2 .53 .53 0 0 1-.6 .7l-.3 .3h.9v.2h-1.1l.2-.5a.6 .6 0 0 0 .6-.8h-.4l-.2 .3h-.2z" fill-rule="evenodd"/>
<path d="M208.3 153.7l-.4 .7h.4zM208.4 153.4h.1v1h.3v.1h-.3v.4h-.2v-.4h-.6zM209.1 153.5a.44 .44 0 0 1 .7-.1 .44 .44 0 0 1-.1 .7 .5 .5 0 0 1-.1 .9 .5 .5 0 0 1-.7-.6h.2a.31 .31 0 0 0 .4 .4 .31 .31 0 0 0 0-.6h-.2l.1-.2a.25 .25 0 0 0 .3-.2 .25 .25 0 0 0-.3-.2l-.2 .1-.1 .2h-.2z" fill-rule="evenodd"/>
<path d="M201.2 152.5l-.5 .7h.5zM201.2 152.2h.2v1h.2v.2h-.2v.4h-.2v-.4h-.7zM201.9 152.3a.44 .44 0 0 1 .7 0 .44 .44 0 0 1-.1 .7 .5 .5 0 0 1-.1 .8 .5 .5 0 0 1-.7-.5h.2a.31 .31 0 0 0 .4 .3 .31 .31 0 0 0 .1-.5h-.3l.1-.2a.25 .25 0 0 0 .3-.2 .25 .25 0 0 0-.3-.3l-.2 .2-.1 .2h-.2z" fill-rule="evenodd"/>
<path d="M214.1 153.7l-.5 .7h.5zM214.1 153.4h.2v1h.2v.1h-.2v.4h-.2v-.4h-.7zM215.3 153.7l-.5 .7h.5zM215.3 153.4h.2v1h.2v.1h-.2v.4h-.2v-.4h-.7z" fill-rule="evenodd"/>
<path d="M221.2 152.5l-.4 .7h.4zM221.3 152.2h.1v1h.3v.2h-.3v.4h-.2v-.4h-.6zM222.5 152.5l-.5 .7h.5zM222.5 152.2h.2v1h.2v.2h-.2v.4h-.2v-.4h-.7z" fill-rule="evenodd"/>
<path d="M208.3 156.3l-.4 .7h.4zM208.4 156h.1v1h.3v.1h-.3v.4h-.2v-.4h-.6zM209.1 156h.8v.2h-.7v.4a.53 .53 0 0 1 .7 .2 .53 .53 0 0 1-.3 .8 .53 .53 0 0 1-.7-.5h.2a.33 .33 0 0 0 .5 .2 .33 .33 0 0 0 0-.6 .33 .33 0 0 0-.5 .1h-.1z" fill-rule="evenodd"/>
<path d="M201.2 155.1l-.5 .7h.5zM201.2 154.8h.2v1h.2v.2h-.2v.4h-.2v-.4h-.7zM201.9 154.9h.8v.1h-.7v.5a.53 .53 0 0 1 .7 .2 .53 .53 0 0 1-.3 .7 .53 .53 0 0 1-.7-.4h.2a.33 .33 0 0 0 .5 .1 .33 .33 0 0 0 .1-.5 .33 .33 0 0 0-.6 .1h-.1z" fill-rule="evenodd"/>
<path d="M214.1 156.3l-.5 .6h.5zM214.1 156h.2v.9h.2v.2h-.2v.4h-.2v-.4h-.7zM214.8 156.1a.46 .46 0 0 1 .5-.1 .46 .46 0 0 1 .3 .4h-.1a.32 .32 0 0 0-.4-.3 .32 .32 0 0 0-.2 .4l-.1 .2a.52 .52 0 0 1 .8 .2 .52 .52 0 0 1-.3 .7 .52 .52 0 0 1-.6-.6zM214.9 157a.33 .33 0 0 0 .6 0 .33 .33 0 0 0-.6 0z" fill-rule="evenodd"/>
<path d="M221.2 155.1l-.4 .7h.4zM221.3 154.8h.1v1h.3v.2h-.3v.4h-.2v-.4h-.6zM222 155a.46 .46 0 0 1 .5-.2 .46 .46 0 0 1 .3 .4h-.2a.32 .32 0 0 0-.3-.2 .32 .32 0 0 0-.3 .4v.2a.52 .52 0 0 1 .8 .1 .52 .52 0 0 1-.4 .8 .52 .52 0 0 1-.6-.6zM222 155.9a.35 .35 0 0 0 .7 0 .35 .35 0 0 0-.7 0z" fill-rule="evenodd"/>
<path d="M208.3 158.8l-.4 .7h.4zM208.4 158.5h.1v1h.3v.2h-.3v.4h-.2v-.4h-.6zM208.9 158.6h1.1l-.7 1.5h-.2l.1-.3 .6-1h-.9z" fill-rule="evenodd"/>
<path d="M201.2 157.7l-.5 .7h.5zM201.2 157.4h.2v1h.2v.2h-.2v.3h-.2v-.3h-.7zM201.7 157.4h1.1l-.6 1.5h-.3l.1-.3 .6-1h-.9z" fill-rule="evenodd"/>
<path d="M214.1 158.8l-.5 .7h.5zM214.1 158.5h.2v1h.2v.2h-.2v.4h-.2v-.4h-.7zM214.9 159a.26 .26 0 0 0 .5 0 .26 .26 0 0 0-.5 0zM214.8 159.7a.35 .35 0 0 0 .7 0 .35 .35 0 0 0-.7 0zM214.8 158.7a.44 .44 0 0 1 .7-.1 .44 .44 0 0 1-.1 .7 .47 .47 0 0 1 .1 .7 .47 .47 0 0 1-.7 0 .47 .47 0 0 1 .1-.7l-.2-.3z" fill-rule="evenodd"/>
<path d="M221.2 157.7l-.4 .7h.4zM221.3 157.4h.1v1h.3v.2h-.3v.3h-.2v-.3h-.6zM222.1 157.8a.26 .26 0 0 0 .5 0 .26 .26 0 0 0-.5 0zM222 158.5a.31 .31 0 0 0 .6 0 .31 .31 0 0 0-.6 0zM222 157.5a.44 .44 0 0 1 .7-.1 .44 .44 0 0 1-.1 .7 .47 .47 0 0 1 .1 .7 .47 .47 0 0 1-.7 0 .47 .47 0 0 1 .1-.7l-.2-.3z" fill-rule="evenodd"/>
<path d="M208.3 161.4l-.4 .7h.4zM208.4 161.1h.1v1h.3v.2h-.3v.4h-.2v-.4h-.6zM209 161.3a.67 .67 0 0 1 .9 .2 .67 .67 0 0 1 0 .8 .47 .47 0 0 1-.5 .4 .47 .47 0 0 1-.5-.4h.2a.3 .3 0 0 0 .4 .2 .3 .3 0 0 0 .2-.3v-.2a.49 .49 0 0 1-.7 0 .49 .49 0 0 1 0-.7zM209.1 161.6a.35 .35 0 0 0 .7 0 .35 .35 0 0 0-.7 0z" fill-rule="evenodd"/>
<path d="M201.2 160.3l-.5 .7h.5zM201.2 160h.2v1h.2v.1h-.2v.4h-.2v-.4h-.7zM201.9 160.1a.67 .67 0 0 1 .8 .2 .67 .67 0 0 1 0 .9 .47 .47 0 0 1-.5 .4 .47 .47 0 0 1-.5-.5h.2a.3 .3 0 0 0 .4 .3 .3 .3 0 0 0 .2-.4l.1-.2a.49 .49 0 0 1-.8 .1 .49 .49 0 0 1 .1-.8zM201.9 160.5a.35 .35 0 0 0 .7 0 .35 .35 0 0 0-.7 0z" fill-rule="evenodd"/>
<path d="M213.6 161.1h.8v.2h-.7v.5a.53 .53 0 0 1 .7 .2 .53 .53 0 0 1-.3 .7 .53 .53 0 0 1-.7-.4h.2a.33 .33 0 0 0 .5 .1 .33 .33 0 0 0 .1-.5 .33 .33 0 0 0-.6 .1h-.1zM214.8 161.3a.6 .6 0 0 1 .8 0 .6 .6 0 0 1 .1 .8 .55 .55 0 0 1-.7 .6 .55 .55 0 0 1-.4-.8zM215 161.3a.84 .84 0 0 0 .1 1.2 .72 .72 0 0 0 .1-1.2z" fill-rule="evenodd"/>
<path d="M220.8 160h.8v.2h-.7l-.1 .4a.53 .53 0 0 1 .8 .3 .53 .53 0 0 1-.3 .7 .53 .53 0 0 1-.7-.5h.2a.33 .33 0 0 0 .5 .2 .33 .33 0 0 0 0-.5 .33 .33 0 0 0-.5 0h-.1zM222 160.1a.6 .6 0 0 1 .8 .1 .6 .6 0 0 1 0 .7 .55 .55 0 0 1-.6 .7 .55 .55 0 0 1-.4-.8zM222.2 160.2a.84 .84 0 0 0 .1 1.2 .72 .72 0 0 0 0-1.2z" fill-rule="evenodd"/>
<path d="M207.9 163.7h.8v.2h-.7l-.1 .4a.53 .53 0 0 1 .8 .3 .53 .53 0 0 1-.4 .7 .53 .53 0 0 1-.6-.5h.2a.33 .33 0 0 0 .5 .2 .33 .33 0 0 0 0-.5 .33 .33 0 0 0-.5 .1h-.2zM209 164l.6-.3v1.5h-.2v-1h-.4z" fill-rule="evenodd"/>
<path d="M200.7 162.6h.8v.2h-.7v.4a.53 .53 0 0 1 .7 .3 .53 .53 0 0 1-.3 .7 .53 .53 0 0 1-.7-.5h.2a.33 .33 0 0 0 .5 .2 .33 .33 0 0 0 0-.6 .33 .33 0 0 0-.5 .1h-.1zM201.9 162.9l.5-.3v1.5h-.2v-1.1h-.3z" fill-rule="evenodd"/>
<path d="M213.6 163.7h.8v.2h-.7v.4a.53 .53 0 0 1 .7 .3 .53 .53 0 0 1-.3 .7 .53 .53 0 0 1-.7-.5h.2a.33 .33 0 0 0 .5 .2 .33 .33 0 0 0 .1-.5 .33 .33 0 0 0-.6 .1h-.1zM214.8 163.8a.53 .53 0 0 1 .9 .2 .53 .53 0 0 1-.6 .7l-.3 .3h.9v.2h-1.1l.2-.5a.6 .6 0 0 0 .6-.7l-.4-.1-.1 .3h-.2z" fill-rule="evenodd"/>
<path d="M220.8 162.6h.8v.2h-.7l-.1 .4a.53 .53 0 0 1 .8 .3 .53 .53 0 0 1-.3 .7 .53 .53 0 0 1-.7-.5h.2a.33 .33 0 0 0 .5 .2 .33 .33 0 0 0 0-.6 .33 .33 0 0 0-.5 .1h-.1zM222 162.7a.53 .53 0 0 1 .9 .2 .53 .53 0 0 1-.6 .7l-.3 .3h.9v.2h-1.1l.2-.5a.6 .6 0 0 0 .6-.8h-.4l-.2 .3h-.2z" fill-rule="evenodd"/>
<path d="M23.1 96.5v.6h.6a.31 .31 0 0 0 .4-.3 .31 .31 0 0 0-.4-.3zM22.9 96.3a1.57 1.57 0 0 1 1.3 .1l.1 .5-.2 .3 .2 .2 .1 .7h-.3l-.1-.7-.3-.1h-.6v.8h-.2zM24.8 96.4a.51 .51 0 0 1 .7 0 .51 .51 0 0 1 0 .8 .59 .59 0 0 1-.1 1 .59 .59 0 0 1-.9-.6h.3a.36 .36 0 0 0 .5 .3 .36 .36 0 0 0 0-.6h-.3l.1-.2a.29 .29 0 0 0 .4-.2 .29 .29 0 0 0-.3-.4l-.3 .2-.1 .2h-.2z" fill-rule="evenodd"/>
<path d="M23.1 91.3v.7h.6a.31 .31 0 0 0 .4-.3 .31 .31 0 0 0-.4-.4zM22.9 91.1a1.57 1.57 0 0 1 1.3 .2l.1 .5-.2 .2 .2 .3 .1 .6h-.3l-.1-.6-.3-.1h-.6v.7h-.2zM25.3 91.5l-.5 .8h.5zM25.4 91.2h.1v1.1h.3v.2h-.3v.4h-.2v-.4h-.8v-.2z" fill-rule="evenodd"/>
<path d="M76.2 58.2l.6-.3v1.5h-.2v-1.1h-.4z" fill-rule="evenodd"/>
<path d="M70.3 57.1l.5-.3v1.5h-.2v-1.1h-.3z" fill-rule="evenodd"/>
<path d="M76.3 60.6a.53 .53 0 0 1 .8 .2 .53 .53 0 0 1-.5 .7l-.3 .3h.8v.2h-1l.2-.5a.6 .6 0 0 0 .5-.8h-.3l-.2 .3h-.2z" fill-rule="evenodd"/>
<path d="M70.3 59.4a.53 .53 0 0 1 .9 .3 .53 .53 0 0 1-.6 .7l-.3 .3h.9v.2h-1.1l.2-.5a.6 .6 0 0 0 .6-.8h-.4l-.2 .3h-.1z" fill-rule="evenodd"/>
<path d="M76.3 63.2a.44 .44 0 0 1 .6-.1 .44 .44 0 0 1 0 .7 .5 .5 0 0 1-.1 .8 .5 .5 0 0 1-.7-.5h.2a.31 .31 0 0 0 .4 .3 .31 .31 0 0 0 0-.5h-.2v-.2a.25 .25 0 0 0 .4-.2 .25 .25 0 0 0-.3-.3l-.3 .2v.2h-.2z" fill-rule="evenodd"/>
<path d="M70.3 62a.44 .44 0 0 1 .7 0 .44 .44 0 0 1-.1 .6 .5 .5 0 0 1-.1 .9 .5 .5 0 0 1-.7-.5h.2a.31 .31 0 0 0 .4 .3 .31 .31 0 0 0 0-.5h-.2l.1-.2a.25 .25 0 0 0 .3-.2 .25 .25 0 0 0-.3-.3l-.2 .1-.1 .2h-.2z" fill-rule="evenodd"/>
<path d="M76.7 65.9l-.5 .7h.5zM76.8 65.6h.1v1h.2v.2h-.2v.4h-.2v-.4h-.6z" fill-rule="evenodd"/>
<path d="M70.8 64.8l-.5 .7h.5zM70.8 64.5h.2v1h.2v.2h-.2v.3h-.2v-.3h-.7z" fill-rule="evenodd"/>
<path d="M76.2 68.3h.8v.1h-.6l-.1 .5a.53 .53 0 0 1 .8 .2 .53 .53 0 0 1-.4 .7 .53 .53 0 0 1-.6-.4h.2a.33 .33 0 0 0 .5 .1 .33 .33 0 0 0 0-.5 .33 .33 0 0 0-.5 .1h-.2z" fill-rule="evenodd"/>
<path d="M70.3 67.1h.8v.2h-.7v.4a.53 .53 0 0 1 .7 .3 .53 .53 0 0 1-.3 .7 .53 .53 0 0 1-.7-.5h.2a.33 .33 0 0 0 .5 .2 .33 .33 0 0 0 .1-.5 .33 .33 0 0 0-.6 0h-.1z" fill-rule="evenodd"/>
<path d="M76.3 71a.46 .46 0 0 1 .5-.2 .46 .46 0 0 1 .3 .4h-.2a.32 .32 0 0 0-.4-.2 .32 .32 0 0 0-.2 .4v.1a.52 .52 0 0 1 .8 .2 .52 .52 0 0 1-.4 .7 .52 .52 0 0 1-.6-.5zM76.3 71.9a.35 .35 0 0 0 .7 0 .35 .35 0 0 0-.7 0z" fill-rule="evenodd"/>
<path d="M70.3 69.8a.46 .46 0 0 1 .5-.1 .46 .46 0 0 1 .3 .4h-.1a.32 .32 0 0 0-.4-.3 .32 .32 0 0 0-.3 .4v.2a.52 .52 0 0 1 .8 .2 .52 .52 0 0 1-.3 .7 .52 .52 0 0 1-.7-.5zM70.4 70.7a.33 .33 0 0 0 .6 0 .33 .33 0 0 0-.6 0z" fill-rule="evenodd"/>
<path d="M76.1 73.4h1l-.6 1.5h-.2l.1-.3 .5-1h-.8z" fill-rule="evenodd"/>
<path d="M70.1 72.3h1.1l-.6 1.5h-.3l.1-.3 .6-1h-.9z" fill-rule="evenodd"/>
<path d="M76.3 76.4a.26 .26 0 0 0 .5 0 .26 .26 0 0 0-.5 0zM76.3 77.1a.31 .31 0 0 0 .6 0 .31 .31 0 0 0-.6 0zM76.3 76.1a.44 .44 0 0 1 .6-.1 .44 .44 0 0 1 0 .7 .47 .47 0 0 1 .1 .7 .47 .47 0 0 1-.7 0 .47 .47 0 0 1 0-.7l-.2-.3z" fill-rule="evenodd"/>
<path d="M70.4 75.2a.26 .26 0 0 0 .5 0 .26 .26 0 0 0-.5 0zM70.3 75.9a.35 .35 0 0 0 .7 0 .35 .35 0 0 0-.7 0zM70.3 75a.44 .44 0 0 1 .7-.1 .44 .44 0 0 1-.1 .6 .47 .47 0 0 1 .1 .7 .47 .47 0 0 1-.7 0 .47 .47 0 0 1 .1-.7l-.2-.3z" fill-rule="evenodd"/>
<path d="M85.7 76.1a.67 .67 0 0 1 .9 .2 .67 .67 0 0 1 0 .9 .47 .47 0 0 1-.5 .3 .47 .47 0 0 1-.5-.4h.2a.3 .3 0 0 0 .4 .3 .3 .3 0 0 0 .2-.4v-.2a.49 .49 0 0 1-.7 0 .49 .49 0 0 1 0-.7zM85.8 76.5a.35 .35 0 0 0 .7 0 .35 .35 0 0 0-.7 0z" fill-rule="evenodd"/>
<path d="M91.7 75a.67 .67 0 0 1 .9 .2 .67 .67 0 0 1-.1 .8 .47 .47 0 0 1-.5 .4 .47 .47 0 0 1-.4-.4h.2a.3 .3 0 0 0 .3 .2 .3 .3 0 0 0 .3-.3v-.2a.49 .49 0 0 1-.7 0 .49 .49 0 0 1 0-.7zM91.8 75.3a.32 .32 0 0 0 .6 0 .32 .32 0 0 0-.6 0z" fill-rule="evenodd"/>
<path d="M84.5 73.7l.6-.3v1.5h-.2v-1.1h-.4zM85.8 73.5a.6 .6 0 0 1 .7 .1 .6 .6 0 0 1 .1 .7 .55 .55 0 0 1-.6 .6 .55 .55 0 0 1-.4-.7zM86 73.6a.84 .84 0 0 0 .1 1.2 .72 .72 0 0 0 0-1.2z" fill-rule="evenodd"/>
<path d="M91.7 72.6l.6-.3v1.5h-.2v-1.1h-.4zM92.9 72.4a.6 .6 0 0 1 .8 0 .6 .6 0 0 1 .1 .8 .55 .55 0 0 1-.6 .6 .55 .55 0 0 1-.4-.8zM93.2 72.5a.84 .84 0 0 0 .1 1.1 .72 .72 0 0 0 0-1.2z" fill-rule="evenodd"/>
<path d="M84.7 71.1l.5-.3v1.5h-.2v-1.1h-.3zM85.7 71.1l.6-.3v1.5h-.2v-1.1h-.4z" fill-rule="evenodd"/>
<path d="M91.7 70l.6-.3v1.5h-.2v-1.1h-.4zM92.7 70l.6-.3v1.5h-.2v-1.1h-.4z" fill-rule="evenodd"/>
<path d="M84.5 68.5l.6-.3v1.5h-.2v-1h-.4zM85.8 68.3a.53 .53 0 0 1 .8 .3 .53 .53 0 0 1-.5 .7l-.3 .3h.8v.1h-1l.2-.4a.6 .6 0 0 0 .5-.8l-.3-.1-.2 .4h-.2z" fill-rule="evenodd"/>
<path d="M91.7 67.4l.6-.3v1.5h-.2v-1.1h-.4zM93 67.2a.53 .53 0 0 1 .8 .2 .53 .53 0 0 1-.5 .7l-.3 .3h.8v.2h-1l.2-.5a.6 .6 0 0 0 .5-.8h-.3l-.2 .3h-.2z" fill-rule="evenodd"/>
<path d="M84.5 65.9l.6-.3v1.6h-.2v-1.1h-.4zM85.8 65.7a.44 .44 0 0 1 .6 0 .44 .44 0 0 1 0 .7 .5 .5 0 0 1-.1 .8 .5 .5 0 0 1-.7-.5h.2a.31 .31 0 0 0 .4 .3 .31 .31 0 0 0 0-.5h-.2v-.2a.25 .25 0 0 0 .4-.2 .25 .25 0 0 0-.3-.3l-.3 .1v.2h-.2z" fill-rule="evenodd"/>
<path d="M91.7 64.8l.6-.3v1.5h-.2v-1h-.4zM93 64.6a.44 .44 0 0 1 .6 0 .44 .44 0 0 1 0 .6 .5 .5 0 0 1-.2 .9 .5 .5 0 0 1-.6-.5h.2a.31 .31 0 0 0 .4 .3 .31 .31 0 0 0 0-.6h-.2v-.1a.25 .25 0 0 0 .4-.2 .25 .25 0 0 0-.3-.3l-.3 .1v.2h-.2z" fill-rule="evenodd"/>
<path d="M84.5 63.4l.6-.3v1.5h-.2v-1.1h-.4zM86.2 63.4l-.4 .6h.4zM86.3 63.1h.1v.9h.3v.2h-.3v.4h-.2v-.4h-.6z" fill-rule="evenodd"/>
<path d="M91.7 62.2l.6-.3v1.6h-.2v-1.1h-.4zM93.4 62.2l-.5 .7h.5zM93.5 61.9h.1v1h.2v.2h-.2v.4h-.2v-.4h-.6z" fill-rule="evenodd"/>
<path d="M84.5 60.8l.6-.3v1.5h-.2v-1.1h-.4zM85.8 60.5h.8v.2h-.7l-.1 .4a.53 .53 0 0 1 .8 .3 .53 .53 0 0 1-.4 .7 .53 .53 0 0 1-.6-.5h.2a.33 .33 0 0 0 .5 .2 .33 .33 0 0 0 0-.5 .33 .33 0 0 0-.5 0h-.2z" fill-rule="evenodd"/>
<path d="M91.7 59.6l.6-.2v1.5h-.2v-1.1h-.4zM92.9 59.4h.8v.2h-.6l-.1 .4a.53 .53 0 0 1 .8 .2 .53 .53 0 0 1-.4 .7 .53 .53 0 0 1-.6-.4h.2a.33 .33 0 0 0 .5 .1 .33 .33 0 0 0 0-.5 .33 .33 0 0 0-.5 .1h-.2z" fill-rule="evenodd"/>
<path d="M84.5 58.2l.6-.3v1.5h-.2v-1.1h-.4zM85.8 58.1a.46 .46 0 0 1 .5-.2 .46 .46 0 0 1 .3 .4h-.2a.32 .32 0 0 0-.4-.2 .32 .32 0 0 0-.2 .4v.1a.52 .52 0 0 1 .8 .2 .52 .52 0 0 1-.4 .7 .52 .52 0 0 1-.6-.5zM85.8 58.9a.35 .35 0 0 0 .7 0 .35 .35 0 0 0-.7 0z" fill-rule="evenodd"/>
<path d="M91.7 57.1l.6-.3v1.5h-.2v-1.1h-.4zM93 56.9a.46 .46 0 0 1 .5-.1 .46 .46 0 0 1 .3 .4h-.2a.32 .32 0 0 0-.4-.3 .32 .32 0 0 0-.2 .4v.2a.52 .52 0 0 1 .8 .2 .52 .52 0 0 1-.4 .7 .52 .52 0 0 1-.6-.5zM93 57.8a.35 .35 0 0 0 .7 0 .35 .35 0 0 0-.7 0z" fill-rule="evenodd"/>
<path d="M76.2 19.5l.6-.3v1.5h-.2v-1.1h-.4z" fill-rule="evenodd"/>
<path d="M70.3 18.4l.5-.3v1.5h-.2v-1.1h-.3z" fill-rule="evenodd"/>
<path d="M76.3 21.9a.53 .53 0 0 1 .8 .2 .53 .53 0 0 1-.5 .7l-.3 .3h.8v.2h-1l.2-.5a.6 .6 0 0 0 .5-.8h-.3l-.2 .3h-.2z" fill-rule="evenodd"/>
<path d="M70.3 20.7a.53 .53 0 0 1 .9 .3 .53 .53 0 0 1-.6 .7l-.3 .3h.9v.2h-1.1l.2-.5a.6 .6 0 0 0 .6-.8l-.4-.1-.2 .4h-.1z" fill-rule="evenodd"/>
<path d="M76.3 24.4a.44 .44 0 0 1 .6 0 .44 .44 0 0 1 0 .7 .5 .5 0 0 1-.1 .8 .5 .5 0 0 1-.7-.5h.2a.31 .31 0 0 0 .4 .3 .31 .31 0 0 0 0-.5h-.2v-.2a.25 .25 0 0 0 .4-.2 .25 .25 0 0 0-.3-.3l-.3 .2v.2h-.2z" fill-rule="evenodd"/>
<path d="M70.3 23.3a.44 .44 0 0 1 .7 0 .44 .44 0 0 1-.1 .6 .5 .5 0 0 1-.1 .9 .5 .5 0 0 1-.7-.5h.2a.31 .31 0 0 0 .4 .3 .31 .31 0 0 0 0-.5l-.2-.1 .1-.1a.25 .25 0 0 0 .3-.2 .25 .25 0 0 0-.3-.3l-.2 .1-.1 .2h-.2z" fill-rule="evenodd"/>
<path d="M76.7 27.2l-.5 .7h.5zM76.8 26.9h.1v1h.2v.2h-.2v.4h-.2v-.4h-.6z" fill-rule="evenodd"/>
<path d="M70.8 26.1l-.5 .7h.5zM70.8 25.8h.2v1h.2v.2h-.2v.3h-.2v-.3h-.7z" fill-rule="evenodd"/>
<path d="M76.2 29.5h.8v.2h-.6l-.1 .5a.53 .53 0 0 1 .8 .2 .53 .53 0 0 1-.4 .7 .53 .53 0 0 1-.6-.4h.2a.33 .33 0 0 0 .5 .1 .33 .33 0 0 0 0-.5 .33 .33 0 0 0-.5 .1h-.2z" fill-rule="evenodd"/>
<path d="M70.3 28.4h.8v.2h-.7v.4a.53 .53 0 0 1 .7 .3 .53 .53 0 0 1-.3 .7 .53 .53 0 0 1-.7-.5h.2a.33 .33 0 0 0 .5 .2 .33 .33 0 0 0 .1-.5 .33 .33 0 0 0-.6 0h-.1z" fill-rule="evenodd"/>
<path d="M76.3 32.3a.46 .46 0 0 1 .5-.2 .46 .46 0 0 1 .3 .4h-.2a.32 .32 0 0 0-.4-.2 .32 .32 0 0 0-.2 .4v.1a.52 .52 0 0 1 .8 .2 .52 .52 0 0 1-.4 .7 .52 .52 0 0 1-.6-.5zM76.3 33.1a.35 .35 0 0 0 .7 0 .35 .35 0 0 0-.7 0z" fill-rule="evenodd"/>
<path d="M70.3 31.1a.46 .46 0 0 1 .5-.1 .46 .46 0 0 1 .3 .4h-.1a.32 .32 0 0 0-.4-.3 .32 .32 0 0 0-.3 .4v.2a.52 .52 0 0 1 .8 .2 .52 .52 0 0 1-.3 .7 .52 .52 0 0 1-.7-.6zM70.4 32a.33 .33 0 0 0 .6 0 .33 .33 0 0 0-.6 0z" fill-rule="evenodd"/>
<path d="M76.1 34.7h1l-.6 1.5h-.2l.1-.3 .5-1h-.8z" fill-rule="evenodd"/>
<path d="M70.1 33.6h1.1l-.6 1.5h-.3l.1-.3 .6-1h-.9z" fill-rule="evenodd"/>
<path d="M76.3 37.7a.26 .26 0 0 0 .5 0 .26 .26 0 0 0-.5 0zM76.3 38.4a.31 .31 0 0 0 .6 0 .31 .31 0 0 0-.6 0zM76.3 37.4a.44 .44 0 0 1 .6-.1 .44 .44 0 0 1 0 .7 .47 .47 0 0 1 .1 .7 .47 .47 0 0 1-.7 0 .47 .47 0 0 1 0-.7l-.2-.3z" fill-rule="evenodd"/>
<path d="M70.4 36.5a.26 .26 0 0 0 .5 0 .26 .26 0 0 0-.5 0zM70.3 37.2a.35 .35 0 0 0 .7 0 .35 .35 0 0 0-.7 0zM70.3 36.2a.44 .44 0 0 1 .7 0 .44 .44 0 0 1-.1 .6 .47 .47 0 0 1 .1 .7 .47 .47 0 0 1-.7 0 .47 .47 0 0 1 .1-.7l-.2-.3z" fill-rule="evenodd"/>
<path d="M85.7 37.4a.67 .67 0 0 1 .9 .2 .67 .67 0 0 1 0 .9 .47 .47 0 0 1-.5 .3 .47 .47 0 0 1-.5-.4h.2a.3 .3 0 0 0 .4 .3 .3 .3 0 0 0 .2-.4v-.2a.49 .49 0 0 1-.7 0 .49 .49 0 0 1 0-.7zM85.8 37.8a.35 .35 0 0 0 .7 0 .35 .35 0 0 0-.7 0z" fill-rule="evenodd"/>
<path d="M91.7 36.3a.67 .67 0 0 1 .9 .2 .67 .67 0 0 1-.1 .8 .47 .47 0 0 1-.5 .4 .47 .47 0 0 1-.4-.4h.2a.3 .3 0 0 0 .3 .2 .3 .3 0 0 0 .3-.3v-.2a.49 .49 0 0 1-.7 0 .49 .49 0 0 1 0-.7zM91.8 36.6a.32 .32 0 0 0 .6 0 .32 .32 0 0 0-.6 0z" fill-rule="evenodd"/>
<path d="M84.5 35l.6-.3v1.5h-.2v-1.1h-.4zM85.8 34.8a.6 .6 0 0 1 .7 .1 .6 .6 0 0 1 .1 .7 .55 .55 0 0 1-.6 .6 .55 .55 0 0 1-.4-.7zM86 34.9a.84 .84 0 0 0 .1 1.2 .72 .72 0 0 0 0-1.3z" fill-rule="evenodd"/>
<path d="M91.7 33.8l.6-.2v1.5h-.2v-1.1h-.4zM92.9 33.7a.6 .6 0 0 1 .8 0 .6 .6 0 0 1 .1 .8 .55 .55 0 0 1-.6 .6 .55 .55 0 0 1-.4-.8zM93.2 33.8a.84 .84 0 0 0 .1 1.1 .72 .72 0 0 0 0-1.2z" fill-rule="evenodd"/>
<path d="M84.7 32.4l.5-.3v1.5h-.2v-1.1h-.3zM85.7 32.4l.6-.3v1.5h-.2v-1.1h-.4z" fill-rule="evenodd"/>
<path d="M91.7 31.3l.6-.3v1.5h-.2v-1.1h-.4zM92.7 31.3l.6-.3v1.5h-.2v-1.1h-.4z" fill-rule="evenodd"/>
<path d="M84.5 29.8l.6-.3v1.5h-.2v-1h-.4zM85.8 29.6a.53 .53 0 0 1 .8 .3 .53 .53 0 0 1-.5 .6l-.3 .4h.8v.1h-1l.2-.4a.6 .6 0 0 0 .5-.8l-.3-.1-.2 .4h-.2z" fill-rule="evenodd"/>
<path d="M91.7 28.7l.6-.3v1.5h-.2v-1.1h-.4zM93 28.5a.53 .53 0 0 1 .8 .2 .53 .53 0 0 1-.5 .7l-.3 .3h.8v.2h-1l.2-.5a.6 .6 0 0 0 .5-.8h-.3l-.2 .3h-.2z" fill-rule="evenodd"/>
<path d="M84.5 27.2l.6-.3v1.6h-.2v-1.1h-.4zM85.8 27a.44 .44 0 0 1 .6 0 .44 .44 0 0 1 0 .6 .5 .5 0 0 1-.1 .9 .5 .5 0 0 1-.7-.5h.2a.31 .31 0 0 0 .4 .3 .31 .31 0 0 0 0-.5h-.2v-.2a.25 .25 0 0 0 .4-.2 .25 .25 0 0 0-.3-.3l-.3 .1v.2h-.2z" fill-rule="evenodd"/>
<path d="M91.7 26.1l.6-.3v1.5h-.2v-1.1h-.4zM93 25.9a.44 .44 0 0 1 .6 0 .44 .44 0 0 1 0 .6 .5 .5 0 0 1-.2 .9 .5 .5 0 0 1-.6-.5h.2a.31 .31 0 0 0 .4 .3 .31 .31 0 0 0 0-.6h-.2v-.1a.25 .25 0 0 0 .4-.2 .25 .25 0 0 0-.3-.3l-.3 .1v.2h-.2z" fill-rule="evenodd"/>
<path d="M84.5 24.7l.6-.3v1.5h-.2v-1.1h-.4zM86.2 24.6l-.4 .7h.4zM86.3 24.3h.1v1h.3v.2h-.3v.4h-.2v-.4h-.6z" fill-rule="evenodd"/>
<path d="M91.7 23.5l.6-.3v1.5h-.2v-1h-.4zM93.4 23.5l-.5 .7h.5zM93.5 23.2h.1v1h.2v.2h-.2v.3h-.2v-.3h-.6z" fill-rule="evenodd"/>
<path d="M84.5 22.1l.6-.3v1.5h-.2v-1.1h-.4zM85.8 21.8h.8v.2h-.7l-.1 .4a.53 .53 0 0 1 .8 .3 .53 .53 0 0 1-.4 .7 .53 .53 0 0 1-.6-.5h.2a.33 .33 0 0 0 .5 .2 .33 .33 0 0 0 0-.6 .33 .33 0 0 0-.5 .1h-.2z" fill-rule="evenodd"/>
<path d="M91.7 20.9l.6-.3v1.6h-.2v-1.1h-.4zM92.9 20.7h.8v.2h-.6l-.1 .4a.53 .53 0 0 1 .8 .2 .53 .53 0 0 1-.4 .7 .53 .53 0 0 1-.6-.4h.2a.33 .33 0 0 0 .5 .1 .33 .33 0 0 0 0-.5 .33 .33 0 0 0-.5 .1h-.2z" fill-rule="evenodd"/>
<path d="M84.5 19.5l.6-.3v1.5h-.2v-1.1h-.4zM85.8 19.4a.46 .46 0 0 1 .5-.2 .46 .46 0 0 1 .3 .4h-.2a.32 .32 0 0 0-.4-.2 .32 .32 0 0 0-.2 .4v.1a.52 .52 0 0 1 .8 .2 .52 .52 0 0 1-.4 .7 .52 .52 0 0 1-.6-.5zM85.8 20.2a.35 .35 0 0 0 .7 0 .35 .35 0 0 0-.7 0z" fill-rule="evenodd"/>
<path d="M91.7 18.4l.6-.3v1.5h-.2v-1.1h-.4zM93 18.2a.46 .46 0 0 1 .5-.2 .46 .46 0 0 1 .3 .5h-.2a.32 .32 0 0 0-.4-.3 .32 .32 0 0 0-.2 .4v.2a.52 .52 0 0 1 .8 .2 .52 .52 0 0 1-.4 .7 .52 .52 0 0 1-.6-.6zM93 19.1a.35 .35 0 0 0 .7 0 .35 .35 0 0 0-.7 0z" fill-rule="evenodd"/>
<path d="M211.4 196.9v.6h.6a.31 .31 0 0 0 .3-.3 .31 .31 0 0 0-.3-.3zM211.1 196.7a1.57 1.57 0 0 1 1.4 .2l.1 .4-.3 .3 .2 .2 .1 .7h-.3v-.6l-.4-.2h-.5v.8h-.3zM213 197.1l.6-.4v1.8h-.2v-1.2h-.4zM214.4 196.9a.64 .64 0 0 1 .8 0 .64 .64 0 0 1 .3 .7 .66 .66 0 0 1-.6 1 .66 .66 0 0 1-.7-.9zM214.7 197a.93 .93 0 0 0 .1 1.4 .86 .86 0 0 0 .1-1.5z" fill-rule="evenodd"/>
<path d="M159 77.5h.3l.9 1.5v-1.5h.2v1.8h-.2l-1-1.5v1.5h-.2zM161.4 78.5v.7a.33 .33 0 0 0 .3-.4 .33 .33 0 0 0-.3-.3zM161 77.8v.3l.3 .2v-.6zM160.9 77.6l.4-.1v-.2l.1 .2a.49 .49 0 0 1 .5 .5h-.2l-.3-.3v.6a.53 .53 0 0 1 .5 .5 .53 .53 0 0 1-.5 .6v.2h-.1v-.2l-.4-.2-.2-.3v-.1h.2l.1 .2 .3 .2v-.7a.49 .49 0 0 1-.5-.3 .49 .49 0 0 1 .1-.6zM162.3 77.9l.6-.4v1.8h-.2v-1.3h-.4zM163.7 77.6h1v.2h-.8l-.1 .5a.62 .62 0 0 1 .9 .2 .62 .62 0 0 1-.4 .9 .62 .62 0 0 1-.8-.6h.3a.39 .39 0 0 0 .5 .2 .39 .39 0 0 0 .1-.6 .39 .39 0 0 0-.6 .1h-.2z" fill-rule="evenodd"/>
<path d="M159 64.6h.3l.9 1.5v-1.5h.2v1.8h-.2l-1-1.5v1.5h-.2zM161.4 65.6v.7a.33 .33 0 0 0 .3-.4 .33 .33 0 0 0-.3-.3zM161 64.9v.3l.3 .2v-.6zM160.9 64.7l.4-.1v-.2l.1 .2a.49 .49 0 0 1 .5 .5h-.2l-.3-.3v.6a.53 .53 0 0 1 .5 .5 .53 .53 0 0 1-.5 .5v.3h-.1v-.3l-.4-.1-.2-.3v-.1h.2l.1 .2 .3 .2v-.7a.49 .49 0 0 1-.5-.3 .49 .49 0 0 1 .1-.6zM162.3 65l.6-.4v1.8h-.2v-1.3h-.4zM163.7 64.8a.69 .69 0 0 1 .9 0 .69 .69 0 0 1 .1 .9 .6 .6 0 0 1-.4 .7 .6 .6 0 0 1-.7-.4h.2a.35 .35 0 0 0 .4 .3 .35 .35 0 0 0 .3-.5v-.2a.57 .57 0 0 1-.8 0 .57 .57 0 0 1 0-.8zM163.8 65.2a.38 .38 0 0 0 .7 0 .38 .38 0 0 0-.7 0z" fill-rule="evenodd"/>
<path d="M226.1 59.4h.3l.9 1.5v-1.5h.2v1.8h-.2l-1-1.4v1.4h-.2zM228.5 60.5v.6a.33 .33 0 0 0 .3-.3 .33 .33 0 0 0-.3-.3zM228.1 59.7v.3l.3 .2v-.6zM228 59.6l.4-.2v-.1l.1 .1a.49 .49 0 0 1 .5 .5h-.2l-.3-.3v.6a.53 .53 0 0 1 .5 .6 .53 .53 0 0 1-.5 .5v.2h-.1v-.2l-.4-.1-.2-.3v-.2h.2l.1 .2 .3 .2v-.7a.49 .49 0 0 1-.5-.3 .49 .49 0 0 1 .1-.5zM229.5 59.6a.61 .61 0 0 1 .9 .3 .61 .61 0 0 1-.6 .8l-.3 .3h.9v.2h-1.2a1.5 1.5 0 0 1 1-1.1 .36 .36 0 0 0-.3-.5 .36 .36 0 0 0-.4 .5h-.2zM230.9 59.6a.61 .61 0 0 1 .9 .3 .61 .61 0 0 1-.6 .8l-.3 .3h1v.2h-1.3a1.5 1.5 0 0 1 1-1.1 .36 .36 0 0 0-.3-.5 .36 .36 0 0 0-.4 .5h-.2z" fill-rule="evenodd"/>
<path d="M159 46.5h.3l.9 1.5v-1.5h.2v1.8h-.2l-1-1.4v1.4h-.2zM161.4 47.6v.6a.33 .33 0 0 0 .3-.3 .33 .33 0 0 0-.3-.3zM161 46.8v.3l.3 .2v-.6zM160.9 46.7l.4-.2v-.1l.1 .1a.49 .49 0 0 1 .5 .5h-.2l-.3-.3v.6a.53 .53 0 0 1 .5 .6 .53 .53 0 0 1-.5 .5v.2h-.1v-.2l-.4-.1-.2-.3v-.2h.2l.1 .2 .3 .2v-.7a.49 .49 0 0 1-.5-.3 .49 .49 0 0 1 .1-.5zM162.3 46.7a.69 .69 0 0 1 .9 0 .69 .69 0 0 1 .1 .9 .6 .6 0 0 1-.4 .7 .6 .6 0 0 1-.7-.4h.2a.35 .35 0 0 0 .4 .3 .35 .35 0 0 0 .3-.4v-.3a.57 .57 0 0 1-.8 .1 .57 .57 0 0 1 0-.9zM162.4 47.1a.38 .38 0 0 0 .7 0 .38 .38 0 0 0-.7 0zM163.7 46.7a.64 .64 0 0 1 .8 0 .64 .64 0 0 1 .3 .7 .66 .66 0 0 1-.6 1 .66 .66 0 0 1-.7-.9zM164 46.8a.93 .93 0 0 0 .1 1.4 .86 .86 0 0 0 .1-1.4z" fill-rule="evenodd"/>
<path d="M226.1 72.3h.3l.9 1.5v-1.5h.2v1.8h-.2l-1-1.4v1.4h-.2zM228.5 73.4v.6a.33 .33 0 0 0 .3-.3 .33 .33 0 0 0-.3-.3zM228.1 72.6v.3l.3 .2v-.6zM228 72.5l.4-.2v-.1l.1 .1a.49 .49 0 0 1 .5 .5h-.2l-.3-.3v.6a.53 .53 0 0 1 .5 .6 .53 .53 0 0 1-.5 .5v.2h-.1v-.2l-.4-.1-.2-.3v-.2h.2l.1 .2 .3 .2v-.7a.49 .49 0 0 1-.5-.3 .49 .49 0 0 1 .1-.5zM229.5 72.5a.61 .61 0 0 1 .9 .3 .61 .61 0 0 1-.6 .8l-.3 .3h.9v.2h-1.2a1.5 1.5 0 0 1 1-1.1 .36 .36 0 0 0-.3-.5 .36 .36 0 0 0-.4 .5h-.2zM230.6 72.4h1.3l-.8 1.7h-.2l.1-.5 .6-1h-1z" fill-rule="evenodd"/>
<path d="M174.6 149.9a.81 .81 0 0 1 1.4 .4h-.2a.63 .63 0 0 0-.9-.3 .63 .63 0 0 0-.2 .9 .58 .58 0 0 0 .6 .5 .58 .58 0 0 0 .5-.6h-.5v-.2h.8v1h-.2l-.1-.3a.89 .89 0 0 1-1.2 .1 .89 .89 0 0 1-.1-1.3zM176.4 149.7h.3l1 1.5v-1.5h.2v1.9h-.3l-.9-1.5v1.5h-.3zM178.5 149.9v1.4h.5a.71 .71 0 0 0 .5-.7 .71 .71 0 0 0-.5-.7zM178.3 149.7h.7a.92 .92 0 0 1 .8 .9 .92 .92 0 0 1-.8 1h-.7z" fill-rule="evenodd"/>
<path d="M174.6 155.1a.81 .81 0 0 1 1.4 .3h-.2a.63 .63 0 0 0-.9-.3 .63 .63 0 0 0-.2 .9 .58 .58 0 0 0 .6 .6 .58 .58 0 0 0 .5-.7h-.5v-.2h.8v1h-.2l-.1-.2a.89 .89 0 0 1-1.2 0 .89 .89 0 0 1-.1-1.2zM176.4 154.9h.3l1 1.5v-1.5h.2v1.8h-.3l-.9-1.5v1.5h-.3zM178.5 155.1v1.4h.5a.71 .71 0 0 0 .5-.7 .71 .71 0 0 0-.5-.7zM178.3 154.9h.7a.92 .92 0 0 1 .8 .9 .92 .92 0 0 1-.8 .9h-.7z" fill-rule="evenodd"/>
<path d="M174.6 160.3a.81 .81 0 0 1 1.4 .3h-.2a.63 .63 0 0 0-.9-.3 .63 .63 0 0 0-.2 .9 .58 .58 0 0 0 .6 .5 .58 .58 0 0 0 .5-.6h-.5v-.2h.8v1h-.2l-.1-.3a.89 .89 0 0 1-1.2 .1 .89 .89 0 0 1-.1-1.2zM176.4 160.1h.3l1 1.4v-1.4h.2v1.8h-.3l-.9-1.5v1.5h-.3zM178.5 160.3v1.4h.5a.71 .71 0 0 0 .5-.7 .71 .71 0 0 0-.5-.7zM178.3 160.1h.7a.92 .92 0 0 1 .8 .9 .92 .92 0 0 1-.8 .9h-.7z" fill-rule="evenodd"/>
<path d="M234 157.7a.81 .81 0 0 1 1.4 .3h-.3a.63 .63 0 0 0-.8-.3 .63 .63 0 0 0-.3 .9 .58 .58 0 0 0 .6 .5 .58 .58 0 0 0 .6-.6h-.6v-.2h.8v1h-.1l-.1-.2a.89 .89 0 0 1-1.2 0 .89 .89 0 0 1-.1-1.2zM235.8 157.5h.3l.9 1.5v-1.5h.2v1.8h-.2l-1-1.5v1.5h-.2zM237.9 157.7v1.4h.4a.71 .71 0 0 0 .6-.7 .71 .71 0 0 0-.6-.7zM237.6 157.5h.8a.92 .92 0 0 1 .8 .9 .92 .92 0 0 1-.8 .9h-.8z" fill-rule="evenodd"/>
<path d="M234 152.5a.81 .81 0 0 1 1.4 .4h-.3a.63 .63 0 0 0-.8-.3 .63 .63 0 0 0-.3 .8 .58 .58 0 0 0 .6 .6 .58 .58 0 0 0 .6-.6h-.6v-.2h.8v.9h-.1l-.1-.2a.89 .89 0 0 1-1.2 .1 .89 .89 0 0 1-.1-1.3zM235.8 152.3h.3l.9 1.5v-1.5h.2v1.8h-.2l-1-1.4v1.4h-.2zM237.9 152.5v1.4h.4a.71 .71 0 0 0 .6-.7 .71 .71 0 0 0-.6-.7zM237.6 152.3h.8a.92 .92 0 0 1 .8 .9 .92 .92 0 0 1-.8 .9h-.8z" fill-rule="evenodd"/>
<path d="M234 162.8a.81 .81 0 0 1 1.4 .4h-.3a.63 .63 0 0 0-.8-.3 .63 .63 0 0 0-.3 .9 .58 .58 0 0 0 .6 .5 .58 .58 0 0 0 .6-.6h-.6v-.2h.8v1h-.1l-.1-.3a.89 .89 0 0 1-1.2 .1 .89 .89 0 0 1-.1-1.3zM235.8 162.6h.3l.9 1.5v-1.5h.2v1.9h-.2l-1-1.5v1.5h-.2zM237.9 162.8v1.4h.4a.71 .71 0 0 0 .6-.7 .71 .71 0 0 0-.6-.7zM237.6 162.6h.8a.92 .92 0 0 1 .8 .9 .92 .92 0 0 1-.8 1h-.8z" fill-rule="evenodd"/>
<path d="M174.6 131.9a.81 .81 0 0 1 1.4 .3h-.2a.63 .63 0 0 0-.9-.3 .63 .63 0 0 0-.2 .9 .58 .58 0 0 0 .6 .5 .58 .58 0 0 0 .5-.6h-.5v-.2h.8v1h-.2l-.1-.2a.89 .89 0 0 1-1.2 0 .89 .89 0 0 1-.1-1.2zM176.4 131.7h.3l1 1.4v-1.4h.2v1.8h-.3l-.9-1.5v1.5h-.3zM178.5 131.9v1.4h.5a.71 .71 0 0 0 .5-.7 .71 .71 0 0 0-.5-.7zM178.3 131.7h.7a.92 .92 0 0 1 .8 .9 .92 .92 0 0 1-.8 .9h-.7z" fill-rule="evenodd"/>
<path d="M174.6 126.7a.81 .81 0 0 1 1.4 .4h-.2a.63 .63 0 0 0-.9-.3 .63 .63 0 0 0-.2 .8 .58 .58 0 0 0 .6 .6 .58 .58 0 0 0 .5-.6h-.5v-.2h.8v.9h-.2l-.1-.2a.89 .89 0 0 1-1.2 0 .89 .89 0 0 1-.1-1.2zM176.4 126.5h.3l1 1.5v-1.5h.2v1.8h-.3l-.9-1.4v1.4h-.3zM178.5 126.7v1.4h.5a.71 .71 0 0 0 .5-.7 .71 .71 0 0 0-.5-.7zM178.3 126.5h.7a.92 .92 0 0 1 .8 .9 .92 .92 0 0 1-.8 .9h-.7z" fill-rule="evenodd"/>
<path d="M174.6 121.6a.81 .81 0 0 1 1.4 .3h-.2a.63 .63 0 0 0-.9-.3 .63 .63 0 0 0-.2 .9 .58 .58 0 0 0 .6 .5 .58 .58 0 0 0 .5-.6h-.5v-.2h.8v1h-.2l-.1-.3a.89 .89 0 0 1-1.2 .1 .89 .89 0 0 1-.1-1.2zM176.4 121.3h.3l1 1.5v-1.5h.2v1.9h-.3l-.9-1.5v1.5h-.3zM178.5 121.6v1.4h.5a.71 .71 0 0 0 .5-.7 .71 .71 0 0 0-.5-.7zM178.3 121.3h.7a.92 .92 0 0 1 .8 1 .92 .92 0 0 1-.8 .9h-.7z" fill-rule="evenodd"/>
<path d="M174.6 116.4a.81 .81 0 0 1 1.4 .3h-.2a.63 .63 0 0 0-.9-.3 .63 .63 0 0 0-.2 .9 .58 .58 0 0 0 .6 .5 .58 .58 0 0 0 .5-.6h-.5v-.2h.8v1h-.2l-.1-.2a.89 .89 0 0 1-1.2 0 .89 .89 0 0 1-.1-1.2zM176.4 116.2h.3l1 1.5v-1.5h.2v1.8h-.3l-.9-1.5v1.5h-.3zM178.5 116.4v1.4h.5a.71 .71 0 0 0 .5-.7 .71 .71 0 0 0-.5-.7zM178.3 116.2h.7a.92 .92 0 0 1 .8 .9 .92 .92 0 0 1-.8 .9h-.7z" fill-rule="evenodd"/>
<path d="M234 139.6a.81 .81 0 0 1 1.4 .4h-.3a.63 .63 0 0 0-.8-.3 .63 .63 0 0 0-.3 .8 .58 .58 0 0 0 .6 .6 .58 .58 0 0 0 .6-.6h-.6v-.2h.8v.9h-.1l-.1-.2a.89 .89 0 0 1-1.2 .1 .89 .89 0 0 1-.1-1.3zM235.8 139.4h.3l.9 1.5v-1.5h.2v1.8h-.2l-1-1.4v1.4h-.2zM237.9 139.6v1.4h.4a.71 .71 0 0 0 .6-.7 .71 .71 0 0 0-.6-.7zM237.6 139.4h.8a.92 .92 0 0 1 .8 .9 .92 .92 0 0 1-.8 .9h-.8z" fill-rule="evenodd"/>
<path d="M226.3 36.4a.81 .81 0 0 1 1.4 .3h-.3a.63 .63 0 0 0-.9-.3 .63 .63 0 0 0-.2 .9 .58 .58 0 0 0 .6 .5 .58 .58 0 0 0 .6-.6h-.6v-.2h.8v1h-.2v-.2a.89 .89 0 0 1-1.3 0 .89 .89 0 0 1-.1-1.2zM228.1 36.2h.3l.9 1.5v-1.5h.2v1.8h-.3l-.9-1.5v1.5h-.2zM230.2 36.4v1.4h.4a.71 .71 0 0 0 .6-.7 .71 .71 0 0 0-.6-.7zM229.9 36.2h.7a.92 .92 0 0 1 .8 .9 .92 .92 0 0 1-.8 .9h-.7z" fill-rule="evenodd"/>
<path d="M226.3 44.1a.81 .81 0 0 1 1.4 .4h-.3a.63 .63 0 0 0-.9-.3 .63 .63 0 0 0-.2 .9 .58 .58 0 0 0 .6 .5 .58 .58 0 0 0 .6-.6h-.6v-.2h.8v1h-.2v-.3a.89 .89 0 0 1-1.3 .1 .89 .89 0 0 1-.1-1.3zM228.1 43.9h.3l.9 1.5v-1.5h.2v1.9h-.3l-.9-1.5v1.5h-.2zM230.2 44.1v1.4h.4a.71 .71 0 0 0 .6-.7 .71 .71 0 0 0-.6-.7zM229.9 43.9h.7a.92 .92 0 0 1 .8 .9 .92 .92 0 0 1-.8 1h-.7z" fill-rule="evenodd"/>
<path d="M226.3 49.3a.81 .81 0 0 1 1.4 .3h-.3a.63 .63 0 0 0-.9-.3 .63 .63 0 0 0-.2 .9 .58 .58 0 0 0 .6 .5 .58 .58 0 0 0 .6-.6h-.6v-.2h.8v1h-.2v-.2a.89 .89 0 0 1-1.3 0 .89 .89 0 0 1-.1-1.2zM228.1 49.1h.3l.9 1.5v-1.5h.2v1.8h-.3l-.9-1.5v1.5h-.2zM230.2 49.3v1.4h.4a.71 .71 0 0 0 .6-.7 .71 .71 0 0 0-.6-.7zM229.9 49.1h.7a.92 .92 0 0 1 .8 .9 .92 .92 0 0 1-.8 .9h-.7z" fill-rule="evenodd"/>
<path d="M227.6 20.9a.81 .81 0 0 1 1.3 .4h-.2a.63 .63 0 0 0-.9-.3 .63 .63 0 0 0-.2 .8 .58 .58 0 0 0 .6 .6 .58 .58 0 0 0 .5-.6h-.5v-.2h.8v.9h-.2v-.2a.89 .89 0 0 1-1.3 0 .89 .89 0 0 1-.1-1.2zM229.4 20.7h.2l1 1.5v-1.5h.2v1.8h-.3l-.9-1.4v1.4h-.2zM231.4 20.9v1.4h.5a.71 .71 0 0 0 .6-.7 .71 .71 0 0 0-.6-.7zM231.2 20.7h.7a.92 .92 0 0 1 .8 .9 .92 .92 0 0 1-.8 .9h-.7z" fill-rule="evenodd"/>
<path d="M174.6 144.8a.81 .81 0 0 1 1.4 .3h-.2a.63 .63 0 0 0-.9-.3 .63 .63 0 0 0-.2 .9 .58 .58 0 0 0 .6 .5 .58 .58 0 0 0 .5-.6h-.5v-.2h.8v1h-.2l-.1-.2a.89 .89 0 0 1-1.2 0 .89 .89 0 0 1-.1-1.2zM176.4 144.6h.3l1 1.4v-1.4h.2v1.8h-.3l-.9-1.5v1.5h-.3zM178.5 144.8v1.4h.5a.71 .71 0 0 0 .5-.7 .71 .71 0 0 0-.5-.7zM178.3 144.6h.7a.92 .92 0 0 1 .8 .9 .92 .92 0 0 1-.8 .9h-.7z" fill-rule="evenodd"/>
<path d="M102.4 23.5a.81 .81 0 0 1 1.4 .3h-.3a.63 .63 0 0 0-.8-.3 .63 .63 0 0 0-.3 .9 .58 .58 0 0 0 .6 .5 .58 .58 0 0 0 .6-.6h-.6v-.2h.8v1h-.2v-.2a.89 .89 0 0 1-1.2 0 .89 .89 0 0 1-.1-1.2zM104.2 23.3h.3l.9 1.5v-1.5h.2v1.8h-.2l-1-1.5v1.5h-.2zM106.3 23.5v1.4h.4a.71 .71 0 0 0 .6-.7 .71 .71 0 0 0-.6-.7zM106 23.3h.8a.92 .92 0 0 1 .7 .9 .92 .92 0 0 1-.7 .9h-.8z" fill-rule="evenodd"/>
<path d="M159.2 54.5a.81 .81 0 0 1 1.4 .3h-.3a.63 .63 0 0 0-.9-.3 .63 .63 0 0 0-.2 .9 .58 .58 0 0 0 .6 .5 .58 .58 0 0 0 .6-.6h-.6v-.2h.8v1h-.2v-.3a.89 .89 0 0 1-1.3 .1 .89 .89 0 0 1-.1-1.2zM161 54.3h.3l.9 1.4v-1.4h.2v1.8h-.3l-.9-1.5v1.5h-.2zM163.1 54.5v1.4h.4a.71 .71 0 0 0 .6-.7 .71 .71 0 0 0-.6-.7zM162.8 54.3h.7a.92 .92 0 0 1 .8 .9 .92 .92 0 0 1-.8 .9h-.7z" fill-rule="evenodd"/>
<path d="M226.3 57a.81 .81 0 0 1 1.4 .4h-.3a.63 .63 0 0 0-.9-.3 .63 .63 0 0 0-.2 .9 .58 .58 0 0 0 .6 .5 .58 .58 0 0 0 .6-.6h-.6v-.2h.8v1h-.2v-.3a.89 .89 0 0 1-1.3 .1 .89 .89 0 0 1-.1-1.3zM228.1 56.8h.3l.9 1.5v-1.5h.2v1.9h-.3l-.9-1.5v1.5h-.2zM230.2 57v1.4h.4a.71 .71 0 0 0 .6-.7 .71 .71 0 0 0-.6-.7zM229.9 56.8h.7a.92 .92 0 0 1 .8 .9 .92 .92 0 0 1-.8 1h-.7z" fill-rule="evenodd"/>
<path d="M226.3 54.5a.81 .81 0 0 1 1.4 .3h-.3a.63 .63 0 0 0-.9-.3 .63 .63 0 0 0-.2 .9 .58 .58 0 0 0 .6 .5 .58 .58 0 0 0 .6-.6h-.6v-.2h.8v1h-.2v-.3a.89 .89 0 0 1-1.3 .1 .89 .89 0 0 1-.1-1.2zM228.1 54.3h.3l.9 1.4v-1.4h.2v1.8h-.3l-.9-1.5v1.5h-.2zM230.2 54.5v1.4h.4a.71 .71 0 0 0 .6-.7 .71 .71 0 0 0-.6-.7zM229.9 54.3h.7a.92 .92 0 0 1 .8 .9 .92 .92 0 0 1-.8 .9h-.7z" fill-rule="evenodd"/>
<path d="M159.2 28.7v.5h.5a.3 .3 0 0 0 .4-.3 .3 .3 0 0 0-.4-.2zM159.2 29.4v.7l.9-.2v-.2l-.1-.2zM159 28.4h.8a.45 .45 0 0 1 .5 .3 .45 .45 0 0 1-.2 .6 .51 .51 0 0 1 .3 .6 .51 .51 0 0 1-.6 .4h-.8zM160.6 29.4a.95 .95 0 0 1 1.9 0 .95 .95 0 0 1-1.9 0zM161 28.8a.69 .69 0 0 0 0 1.1 .69 .69 0 0 0 1-.2 .68 .68 0 0 0-.1-.9 .68 .68 0 0 0-.9 0zM162.5 28.4h1.5v.3h-.6v1.6h-.3v-1.6h-.6zM164.1 28.4h1.4v.3h-.6v1.6h-.2v-1.6h-.6zM165.6 29.4a.95 .95 0 0 1 1.9 0 .95 .95 0 0 1-1.9 0zM166.1 28.8a.69 .69 0 0 0-.1 1.1 .69 .69 0 0 0 1.1-.2 .68 .68 0 0 0-.1-.9 .68 .68 0 0 0-.9 0zM167.7 28.4h.3l.6 1.6 .5-1.6h.3v1.9h-.2v-1.6l-.5 1.6h-.3l-.5-1.6v1.6h-.2zM169.6 30.5h1.4v.1h-1.4zM171.1 28.4h1.4v.3h-.6v1.6h-.2v-1.6h-.6zM172.8 28.4h1.3v.3h-1.1v.5h1v.2h-1v.7h1.1v.2h-1.3zM174.5 28.4h.3l.5 1.6 .6-1.6h.3v1.9h-.2v-1.6l-.5 1.6h-.3l-.5-1.6v1.6h-.2zM176.6 28.4h.8a.53 .53 0 0 1 .6 .6 .53 .53 0 0 1-.6 .5h-.5v.8h-.3zM176.9 28.7v.6h.4a.32 .32 0 0 0 .4-.3 .32 .32 0 0 0-.4-.3zM178.1 30.5h1.4v.1h-1.4zM179.8 28.6a.72 .72 0 0 1 1.2 .4h-.2a.42 .42 0 0 0-.5-.4 .42 .42 0 0 0-.4 .4 1.47 1.47 0 0 1 1.2 .8 .74 .74 0 0 1-.8 .5 .74 .74 0 0 1-.7-.6h.2a.48 .48 0 0 0 .5 .4 .48 .48 0 0 0 .5-.4l-.4-.2a.56 .56 0 0 1-.6-.2 .56 .56 0 0 1 0-.7zM181.3 29.4a.95 .95 0 0 1 1.9 0 .95 .95 0 0 1-1.9 0zM181.7 28.8a.69 .69 0 0 0 0 1.1 .69 .69 0 0 0 1-.2 .68 .68 0 0 0-.1-.9 .68 .68 0 0 0-.9 0zM183.4 28.4h.2v1.7h.9v.2h-1.1zM185.4 28.7l-.3 .8h.6zM185.3 28.4h.3l.6 1.9h-.2l-.2-.6h-.7l-.2 .6h-.3zM186.7 28.7v.6h.6a.31 .31 0 0 0 .4-.3 .31 .31 0 0 0-.4-.3zM186.5 28.4a1.57 1.57 0 0 1 1.3 .2l.1 .5-.2 .3 .2 .2 .1 .7h-.3l-.1-.7-.3-.1h-.6v.8h-.2zM188.1 30.5h1.4v.1h-1.4zM189.7 28.4h.9a.53 .53 0 0 1 .5 .6 .53 .53 0 0 1-.5 .5h-.6v.8h-.3zM190 28.7v.6h.5a.32 .32 0 0 0 .3-.3 .32 .32 0 0 0-.3-.3zM191.9 28.7l-.3 .8h.6zM191.7 28.4h.3l.7 1.9h-.3l-.2-.6h-.7l-.2 .6h-.2zM192.9 28.4h.3l.9 1.5v-1.5h.3v1.9h-.3l-1-1.5v1.5h-.2zM194.8 28.4h1.3v.3h-1.1v.5h1v.2h-1v.7h1.1v.2h-1.3zM196.4 28.4h.3v1.7h.9v.2h-1.2zM197.8 29.4h.6v.3h-.6zM198.7 28.8l.7-.3v1.8h-.2v-1.3h-.5z" fill-rule="evenodd"/>
<path d="M32.8 28.7v.5h.4a.3 .3 0 0 0 .4-.3 .3 .3 0 0 0-.4-.2zM32.8 29.4v.7l.8-.2 .1-.2-.2-.2zM32.5 28.4h.8a.45 .45 0 0 1 .5 .3 .45 .45 0 0 1-.2 .6 .51 .51 0 0 1 .3 .6 .51 .51 0 0 1-.6 .4h-.8zM34.1 29.4a.95 .95 0 0 1 1.9 0 .95 .95 0 0 1-1.9 0zM34.6 28.8a.69 .69 0 0 0-.1 1.1 .69 .69 0 0 0 1.1-.2 .68 .68 0 0 0-.1-.9 .68 .68 0 0 0-.9 0zM36 28.4h1.5v.3h-.6v1.6h-.2v-1.6h-.7zM37.6 28.4h1.5v.3h-.6v1.6h-.3v-1.6h-.6zM39.2 29.4a.94 .94 0 0 1 1.8 0 .94 .94 0 0 1-1.8 0zM39.6 28.8a.69 .69 0 0 0 0 1.1 .69 .69 0 0 0 1-.2 .68 .68 0 0 0-.1-.9 .68 .68 0 0 0-.9 0zM41.2 28.4h.4l.5 1.6 .5-1.6h.4v1.9h-.3v-1.6l-.5 1.6h-.2l-.5-1.6v1.6h-.3zM43.2 30.5h1.4v.1h-1.4zM44.6 28.4h1.5v.3h-.6v1.6h-.3v-1.6h-.6zM46.3 28.4h1.4v.3h-1.1v.5h1v.2h-1v.7h1.1v.2h-1.4zM48 28.4h.4l.5 1.6 .5-1.6h.3v1.9h-.2v-1.6l-.5 1.6h-.2l-.6-1.6v1.6h-.2zM50.1 28.4h.9a.53 .53 0 0 1 .5 .6 .53 .53 0 0 1-.5 .5h-.6v.8h-.3zM50.4 28.7v.6h.5a.32 .32 0 0 0 .4-.3 .32 .32 0 0 0-.4-.3zM51.6 30.5h1.4v.1h-1.4zM53.4 28.6a.72 .72 0 0 1 1.2 .4h-.3a.42 .42 0 0 0-.4-.4 .42 .42 0 0 0-.4 .4 1.47 1.47 0 0 1 1.1 .8 .74 .74 0 0 1-.7 .5 .74 .74 0 0 1-.7-.6h.2a.48 .48 0 0 0 .5 .4 .48 .48 0 0 0 .4-.4l-.3-.2a.56 .56 0 0 1-.7-.2 .56 .56 0 0 1 .1-.7zM54.8 29.4a.95 .95 0 0 1 1.9 0 .95 .95 0 0 1-1.9 0zM55.3 28.8a.69 .69 0 0 0-.1 1.1 .69 .69 0 0 0 1.1-.2 .68 .68 0 0 0-.1-.9 .68 .68 0 0 0-.9 0zM56.9 28.4h.2v1.7h1v.2h-1.2zM59 28.7l-.3 .8h.5zM58.8 28.4h.3l.7 1.9h-.3l-.2-.6h-.7l-.2 .6h-.2zM60.3 28.7v.6h.6a.31 .31 0 0 0 .3-.3 .31 .31 0 0 0-.3-.3zM60 28.4a1.57 1.57 0 0 1 1.4 .2l.1 .5-.3 .3 .2 .2 .1 .7h-.3v-.7l-.4-.1h-.5v.8h-.3zM61.6 30.5h1.5v.1h-1.5zM63.3 28.4h.8a.53 .53 0 0 1 .5 .6 .53 .53 0 0 1-.5 .5h-.6v.8h-.2zM63.5 28.7v.6h.5a.32 .32 0 0 0 .4-.3 .32 .32 0 0 0-.4-.3zM65.4 28.7l-.3 .8h.6zM65.3 28.4h.3l.6 1.9h-.2l-.2-.6h-.7l-.2 .6h-.3zM66.5 28.4h.2l1 1.5v-1.5h.2v1.9h-.3l-.9-1.5v1.5h-.2zM68.3 28.4h1.3v.3h-1v.5h1v.2h-1v.7h1.1v.2h-1.4zM70 28.4h.2v1.7h1v.2h-1.2zM71.3 29.4h.6v.3h-.6zM72.3 28.8l.6-.3v1.8h-.2v-1.3h-.4z" fill-rule="evenodd"/>
<path d="M159.2 31.2v.6h.5a.3 .3 0 0 0 .4-.3 .3 .3 0 0 0-.4-.3zM159.2 32v.6l.9-.1v-.2l-.1-.3zM159 31h.8a.45 .45 0 0 1 .5 .3 .45 .45 0 0 1-.2 .6 .51 .51 0 0 1 .3 .6 .51 .51 0 0 1-.6 .3h-.8zM160.6 32a.95 .95 0 0 1 1.9 0 .95 .95 0 0 1-1.9 0zM161 31.4a.69 .69 0 0 0 0 1.1 .69 .69 0 0 0 1-.2 .68 .68 0 0 0-.1-.9 .68 .68 0 0 0-.9 0zM162.5 31h1.5v.2h-.6v1.6h-.3v-1.6h-.6zM164.1 31h1.4v.2h-.6v1.6h-.2v-1.6h-.6zM165.6 32a.95 .95 0 0 1 1.9 0 .95 .95 0 0 1-1.9 0zM166.1 31.4a.69 .69 0 0 0-.1 1.1 .69 .69 0 0 0 1.1-.2 .68 .68 0 0 0-.1-.9 .68 .68 0 0 0-.9 0zM167.7 31h.3l.6 1.6 .5-1.6h.3v1.8h-.2v-1.5l-.5 1.5h-.3l-.5-1.5v1.5h-.2zM169.6 33h1.4v.2h-1.4zM171.1 31h1.4v.2h-.6v1.6h-.2v-1.6h-.6zM172.8 31h1.3v.3h-1.1v.5h1v.2h-1v.6h1.1v.2h-1.3zM174.5 31h.3l.5 1.6 .6-1.6h.3v1.8h-.2v-1.5l-.5 1.5h-.3l-.5-1.5v1.5h-.2zM176.6 31h.8a.53 .53 0 0 1 .6 .6 .53 .53 0 0 1-.6 .5h-.5v.7h-.3zM176.9 31.2v.7h.4a.32 .32 0 0 0 .4-.3 .32 .32 0 0 0-.4-.4zM178.1 33h1.4v.2h-1.4zM179.8 31.1a.72 .72 0 0 1 1.2 .5h-.2a.42 .42 0 0 0-.5-.4 .42 .42 0 0 0-.4 .4 1.47 1.47 0 0 1 1.2 .7 .74 .74 0 0 1-.8 .6 .74 .74 0 0 1-.7-.6h.2a.48 .48 0 0 0 .5 .4 .48 .48 0 0 0 .5-.4l-.4-.2a.56 .56 0 0 1-.6-.3 .56 .56 0 0 1 0-.7zM181.3 32a.95 .95 0 0 1 1.9 0 .95 .95 0 0 1-1.9 0zM181.7 31.4a.69 .69 0 0 0 0 1.1 .69 .69 0 0 0 1-.2 .68 .68 0 0 0-.1-.9 .68 .68 0 0 0-.9 0zM183.4 31h.2v1.6h.9v.2h-1.1zM185.4 31.3l-.3 .8h.6zM185.3 31h.3l.6 1.8h-.2l-.2-.5h-.7l-.2 .5h-.3zM186.7 31.2v.7h.6a.31 .31 0 0 0 .4-.3 .31 .31 0 0 0-.4-.4zM186.5 31a1.57 1.57 0 0 1 1.3 .2l.1 .5-.2 .3 .2 .2 .1 .6h-.3l-.1-.6-.3-.1h-.6v.7h-.2zM188.1 33h1.4v.2h-1.4zM189.7 31h.9a.53 .53 0 0 1 .5 .6 .53 .53 0 0 1-.5 .5h-.6v.7h-.3zM190 31.2v.7h.5a.32 .32 0 0 0 .3-.3 .32 .32 0 0 0-.3-.4zM191.9 31.3l-.3 .8h.6zM191.7 31h.3l.7 1.8h-.3l-.2-.5h-.7l-.2 .5h-.2zM192.9 31h.3l.9 1.5v-1.5h.3v1.8h-.3l-1-1.4v1.4h-.2zM194.8 31h1.3v.3h-1.1v.5h1v.2h-1v.6h1.1v.2h-1.3zM196.4 31h.3v1.6h.9v.2h-1.2zM197.8 32h.6v.3h-.6zM198.8 31.2a.61 .61 0 0 1 1 .3 .61 .61 0 0 1-.6 .8l-.4 .3h1v.2h-1.2a1.5 1.5 0 0 1 .9-1.1 .36 .36 0 0 0-.3-.4 .36 .36 0 0 0-.3 .4h-.3z" fill-rule="evenodd"/>
<path d="M32.8 31.2v.6h.4a.3 .3 0 0 0 .4-.3 .3 .3 0 0 0-.4-.3zM32.8 32v.6l.8-.1 .1-.2-.2-.3zM32.5 31h.8a.45 .45 0 0 1 .5 .3 .45 .45 0 0 1-.2 .6 .51 .51 0 0 1 .3 .6 .51 .51 0 0 1-.6 .3h-.8zM34.1 32a.95 .95 0 0 1 1.9 0 .95 .95 0 0 1-1.9 0zM34.6 31.4a.69 .69 0 0 0-.1 1.1 .69 .69 0 0 0 1.1-.2 .68 .68 0 0 0-.1-.9 .68 .68 0 0 0-.9 0zM36 31h1.5v.2h-.6v1.6h-.2v-1.6h-.7zM37.6 31h1.5v.2h-.6v1.6h-.3v-1.6h-.6zM39.2 32a.94 .94 0 0 1 1.8 0 .94 .94 0 0 1-1.8 0zM39.6 31.4a.69 .69 0 0 0 0 1.1 .69 .69 0 0 0 1-.2 .68 .68 0 0 0-.1-.9 .68 .68 0 0 0-.9 0zM41.2 31h.4l.5 1.6 .5-1.6h.4v1.8h-.3v-1.5l-.5 1.5h-.2l-.5-1.5v1.5h-.3zM43.2 33h1.4v.2h-1.4zM44.6 31h1.5v.2h-.6v1.6h-.3v-1.6h-.6zM46.3 31h1.4v.3h-1.1v.5h1v.2h-1v.6h1.1v.2h-1.4zM48 31h.4l.5 1.6 .5-1.6h.3v1.8h-.2v-1.5l-.5 1.5h-.2l-.6-1.5v1.5h-.2zM50.1 31h.9a.53 .53 0 0 1 .5 .6 .53 .53 0 0 1-.5 .5h-.6v.7h-.3zM50.4 31.2v.7h.5a.32 .32 0 0 0 .4-.3 .32 .32 0 0 0-.4-.4zM51.6 33h1.4v.2h-1.4zM53.4 31.1a.72 .72 0 0 1 1.2 .5h-.3a.42 .42 0 0 0-.4-.4 .42 .42 0 0 0-.4 .4 1.47 1.47 0 0 1 1.1 .7 .74 .74 0 0 1-.7 .6 .74 .74 0 0 1-.7-.6h.2a.48 .48 0 0 0 .5 .4 .48 .48 0 0 0 .4-.4l-.3-.2a.56 .56 0 0 1-.7-.3 .56 .56 0 0 1 .1-.7zM54.8 32a.95 .95 0 0 1 1.9 0 .95 .95 0 0 1-1.9 0zM55.3 31.4a.69 .69 0 0 0-.1 1.1 .69 .69 0 0 0 1.1-.2 .68 .68 0 0 0-.1-.9 .68 .68 0 0 0-.9 0zM56.9 31h.2v1.6h1v.2h-1.2zM59 31.3l-.3 .8h.5zM58.8 31h.3l.7 1.8h-.3l-.2-.5h-.7l-.2 .5h-.2zM60.3 31.2v.7h.6a.31 .31 0 0 0 .3-.3 .31 .31 0 0 0-.3-.4zM60 31a1.57 1.57 0 0 1 1.4 .2l.1 .5-.3 .3 .2 .2 .1 .6h-.3v-.6l-.4-.1h-.5v.7h-.3zM61.6 33h1.5v.2h-1.5zM63.3 31h.8a.53 .53 0 0 1 .5 .6 .53 .53 0 0 1-.5 .5h-.6v.7h-.2zM63.5 31.2v.7h.5a.32 .32 0 0 0 .4-.3 .32 .32 0 0 0-.4-.4zM65.4 31.3l-.3 .8h.6zM65.3 31h.3l.6 1.8h-.2l-.2-.5h-.7l-.2 .5h-.3zM66.5 31h.2l1 1.5v-1.5h.2v1.8h-.3l-.9-1.4v1.4h-.2zM68.3 31h1.3v.3h-1v.5h1v.2h-1v.6h1.1v.2h-1.4zM70 31h.2v1.6h1v.2h-1.2zM71.3 32h.6v.3h-.6zM72.4 31.2a.61 .61 0 0 1 .9 .3 .61 .61 0 0 1-.6 .8l-.3 .3h.9v.2h-1.2a1.5 1.5 0 0 1 1-1.1 .36 .36 0 0 0-.3-.4 .36 .36 0 0 0-.4 .4h-.2z" fill-rule="evenodd"/>
<path d="M159.2 36.4v.6h.5a.3 .3 0 0 0 .4-.3 .3 .3 0 0 0-.4-.3zM159.2 37.2v.6l.9-.1v-.2l-.1-.3zM159 36.2h.8a.45 .45 0 0 1 .5 .3 .45 .45 0 0 1-.2 .5 .51 .51 0 0 1 .3 .7 .51 .51 0 0 1-.6 .3h-.8zM160.6 37.1a.95 .95 0 0 1 1.9 0 .95 .95 0 0 1-1.9 0zM161 36.6a.69 .69 0 0 0 0 1 .69 .69 0 0 0 1-.2 .68 .68 0 0 0-.1-.9 .68 .68 0 0 0-.9 .1zM162.5 36.2h1.5v.2h-.6v1.6h-.3v-1.6h-.6zM164.1 36.2h1.4v.2h-.6v1.6h-.2v-1.6h-.6zM165.6 37.1a.95 .95 0 0 1 1.9 0 .95 .95 0 0 1-1.9 0zM166.1 36.6a.69 .69 0 0 0-.1 1 .69 .69 0 0 0 1.1-.2 .68 .68 0 0 0-.1-.9 .68 .68 0 0 0-.9 .1zM167.7 36.2h.3l.6 1.5 .5-1.5h.3v1.8h-.2v-1.5l-.5 1.5h-.3l-.5-1.5v1.5h-.2zM169.6 38.2h1.4v.1h-1.4zM171.1 36.2h1.4v.2h-.6v1.6h-.2v-1.6h-.6zM172.8 36.2h1.3v.2h-1.1v.6h1v.2h-1v.6h1.1v.2h-1.3zM174.5 36.2h.3l.5 1.5 .6-1.5h.3v1.8h-.2v-1.5l-.5 1.5h-.3l-.5-1.5v1.5h-.2zM176.6 36.2h.8a.53 .53 0 0 1 .6 .5 .53 .53 0 0 1-.6 .5h-.5v.8h-.3zM176.9 36.4v.6h.4a.32 .32 0 0 0 .4-.3 .32 .32 0 0 0-.4-.3zM178.1 38.2h1.4v.1h-1.4zM179.8 36.3a.72 .72 0 0 1 1.2 .4h-.2a.42 .42 0 0 0-.5-.3 .42 .42 0 0 0-.4 .4 1.47 1.47 0 0 1 1.2 .7 .74 .74 0 0 1-.8 .6 .74 .74 0 0 1-.7-.7h.2a.48 .48 0 0 0 .5 .5 .48 .48 0 0 0 .5-.5l-.4-.2a.56 .56 0 0 1-.6-.2 .56 .56 0 0 1 0-.7zM181.3 37.1a.95 .95 0 0 1 1.9 0 .95 .95 0 0 1-1.9 0zM181.7 36.6a.69 .69 0 0 0 0 1 .69 .69 0 0 0 1-.2 .68 .68 0 0 0-.1-.9 .68 .68 0 0 0-.9 .1zM183.4 36.2h.2v1.6h.9v.2h-1.1zM185.4 36.5l-.3 .8h.6zM185.3 36.2h.3l.6 1.8h-.2l-.2-.5h-.7l-.2 .5h-.3zM186.7 36.4v.6h.6a.31 .31 0 0 0 .4-.3 .31 .31 0 0 0-.4-.3zM186.5 36.2a1.57 1.57 0 0 1 1.3 .1l.1 .5-.2 .3 .2 .2 .1 .7h-.3l-.1-.6-.3-.2h-.6v.8h-.2zM188.1 38.2h1.4v.1h-1.4zM189.7 36.2h.9a.53 .53 0 0 1 .5 .5 .53 .53 0 0 1-.5 .5h-.6v.8h-.3zM190 36.4v.6h.5a.32 .32 0 0 0 .3-.3 .32 .32 0 0 0-.3-.3zM191.9 36.5l-.3 .8h.6zM191.7 36.2h.3l.7 1.8h-.3l-.2-.5h-.7l-.2 .5h-.2zM192.9 36.2h.3l.9 1.5v-1.5h.3v1.8h-.3l-1-1.5v1.5h-.2zM194.8 36.2h1.3v.2h-1.1v.6h1v.2h-1v.6h1.1v.2h-1.3zM196.4 36.2h.3v1.6h.9v.2h-1.2zM197.8 37.2h.6v.2h-.6zM199.3 36.6l-.5 .8h.5zM199.4 36.2h.2v1.2h.2v.2h-.2v.4h-.3v-.4h-.7v-.2z" fill-rule="evenodd"/>
<path d="M32.8 36.4v.6h.4a.3 .3 0 0 0 .4-.3 .3 .3 0 0 0-.4-.3zM32.8 37.2v.6l.8-.1 .1-.2-.2-.3zM32.5 36.2h.8a.45 .45 0 0 1 .5 .3 .45 .45 0 0 1-.2 .5 .51 .51 0 0 1 .3 .7 .51 .51 0 0 1-.6 .3h-.8zM34.1 37.1a.95 .95 0 0 1 1.9 0 .95 .95 0 0 1-1.9 0zM34.6 36.6a.69 .69 0 0 0-.1 1 .69 .69 0 0 0 1.1-.2 .68 .68 0 0 0-.1-.9 .68 .68 0 0 0-.9 .1zM36 36.2h1.5v.2h-.6v1.6h-.2v-1.6h-.7zM37.6 36.2h1.5v.2h-.6v1.6h-.3v-1.6h-.6zM39.2 37.1a.94 .94 0 0 1 1.8 0 .94 .94 0 0 1-1.8 0zM39.6 36.6a.69 .69 0 0 0 0 1 .69 .69 0 0 0 1-.2 .68 .68 0 0 0-.1-.9 .68 .68 0 0 0-.9 .1zM41.2 36.2h.4l.5 1.5 .5-1.5h.4v1.8h-.3v-1.5l-.5 1.5h-.2l-.5-1.5v1.5h-.3zM43.2 38.2h1.4v.1h-1.4zM44.6 36.2h1.5v.2h-.6v1.6h-.3v-1.6h-.6zM46.3 36.2h1.4v.2h-1.1v.6h1v.2h-1v.6h1.1v.2h-1.4zM48 36.2h.4l.5 1.5 .5-1.5h.3v1.8h-.2v-1.5l-.5 1.5h-.2l-.6-1.5v1.5h-.2zM50.1 36.2h.9a.53 .53 0 0 1 .5 .5 .53 .53 0 0 1-.5 .5h-.6v.8h-.3zM50.4 36.4v.6h.5a.32 .32 0 0 0 .4-.3 .32 .32 0 0 0-.4-.3zM51.6 38.2h1.4v.1h-1.4zM53.4 36.3a.72 .72 0 0 1 1.2 .4h-.3a.42 .42 0 0 0-.4-.3 .42 .42 0 0 0-.4 .4 1.47 1.47 0 0 1 1.1 .7 .74 .74 0 0 1-.7 .6 .74 .74 0 0 1-.7-.7h.2a.48 .48 0 0 0 .5 .5 .48 .48 0 0 0 .4-.5l-.3-.2a.56 .56 0 0 1-.7-.2 .56 .56 0 0 1 .1-.7zM54.8 37.1a.95 .95 0 0 1 1.9 0 .95 .95 0 0 1-1.9 0zM55.3 36.6a.69 .69 0 0 0-.1 1 .69 .69 0 0 0 1.1-.2 .68 .68 0 0 0-.1-.9 .68 .68 0 0 0-.9 .1zM56.9 36.2h.2v1.6h1v.2h-1.2zM59 36.5l-.3 .8h.5zM58.8 36.2h.3l.7 1.8h-.3l-.2-.5h-.7l-.2 .5h-.2zM60.3 36.4v.6h.6a.31 .31 0 0 0 .3-.3 .31 .31 0 0 0-.3-.3zM60 36.2a1.57 1.57 0 0 1 1.4 .1l.1 .5-.3 .3 .2 .2 .1 .7h-.3v-.6l-.4-.2h-.5v.8h-.3zM61.6 38.2h1.5v.1h-1.5zM63.3 36.2h.8a.53 .53 0 0 1 .5 .5 .53 .53 0 0 1-.5 .5h-.6v.8h-.2zM63.5 36.4v.6h.5a.32 .32 0 0 0 .4-.3 .32 .32 0 0 0-.4-.3zM65.4 36.5l-.3 .8h.6zM65.3 36.2h.3l.6 1.8h-.2l-.2-.5h-.7l-.2 .5h-.3zM66.5 36.2h.2l1 1.5v-1.5h.2v1.8h-.3l-.9-1.5v1.5h-.2zM68.3 36.2h1.3v.2h-1v.6h1v.2h-1v.6h1.1v.2h-1.4zM70 36.2h.2v1.6h1v.2h-1.2zM71.3 37.2h.6v.2h-.6zM72.9 36.6l-.6 .8h.6zM72.9 36.2h.2v1.2h.3v.2h-.3v.4h-.2v-.4h-.8v-.2z" fill-rule="evenodd"/>
<path d="M226.1 80.1h1.3v.2h-1v.5h1v.2h-1v.7h1.1v.2h-1.4zM227.8 80.1h.2v1.6h.9v.2h-1.1zM229.2 80.1h1.3v.2h-1v.5h1v.2h-1v.7h1.1v.2h-1.4zM231 80.3a.79 .79 0 0 1 .8-.3 .79 .79 0 0 1 .6 .6h-.2a.62 .62 0 0 0-.9-.3 .62 .62 0 0 0-.2 .9 .56 .56 0 0 0 .5 .5 .56 .56 0 0 0 .6-.5h.2a.85 .85 0 0 1-1.1 .7 .85 .85 0 0 1-.5-1.2zM232.5 82.1h1.4v.1h-1.4zM234.4 80.3v.5h.4a.3 .3 0 0 0 .4-.3 .3 .3 0 0 0-.4-.2zM234.4 81v.7l.8-.2 .1-.2-.2-.2zM234.1 80.1h.8a.45 .45 0 0 1 .5 .3 .45 .45 0 0 1-.2 .5 .51 .51 0 0 1 .3 .6 .51 .51 0 0 1-.6 .4h-.8zM236.5 80.3l-.3 .8h.6zM236.4 80.1h.2l.7 1.8h-.3l-.2-.6h-.7l-.2 .6h-.2zM237.2 80.1h.3l.5 .8 .5-.8h.3l-.7 1v.8h-.2v-.8zM238.8 82.1h1.4v.1h-1.4zM240.3 80.1h1.5v.2h-.6v1.6h-.3v-1.6h-.6zM242 80.1h1.3v.2h-1v.5h1v.2h-1v.7h1.1v.2h-1.4zM243.7 80.1h.3l.6 1.5 .5-1.5h.3v1.8h-.2v-1.6l-.5 1.6h-.3l-.5-1.6v1.6h-.2zM245.8 80.1h.8a.53 .53 0 0 1 .6 .5 .53 .53 0 0 1-.6 .5h-.5v.8h-.3zM246.1 80.3v.6h.5a.32 .32 0 0 0 .3-.3 .32 .32 0 0 0-.3-.3zM247.3 82.1h1.4v.1h-1.4zM249 80.5l.6-.4v1.8h-.2v-1.3h-.4z" fill-rule="evenodd"/>
<path d="M173.5 192.8h1.3v.2h-1.1v.6h1v.2h-1v.6h1.1v.2h-1.3zM175.2 192.8h.2v1.6h.9v.2h-1.1zM176.6 192.8h1.3v.2h-1.1v.6h1v.2h-1v.6h1.1v.2h-1.3zM178.4 193.1a.79 .79 0 0 1 .8-.3 .79 .79 0 0 1 .6 .6h-.3a.62 .62 0 0 0-.8-.3 .62 .62 0 0 0-.3 .9 .56 .56 0 0 0 .6 .5 .56 .56 0 0 0 .6-.5h.2a.85 .85 0 0 1-1.1 .7 .85 .85 0 0 1-.5-1.2zM179.9 194.8h1.4v.2h-1.4zM181.7 193v.6h.5a.3 .3 0 0 0 .4-.3 .3 .3 0 0 0-.4-.3zM181.7 193.8v.6l.9-.1 .1-.2-.2-.3zM181.5 192.8h.8a.45 .45 0 0 1 .5 .3 .45 .45 0 0 1-.2 .6 .51 .51 0 0 1 .3 .6 .51 .51 0 0 1-.6 .3h-.8zM183.9 193.1l-.3 .8h.5zM183.7 192.8h.3l.7 1.8h-.3l-.2-.5h-.7l-.2 .5h-.3zM184.6 192.8h.3l.5 .9 .5-.9h.3l-.7 1.1v.7h-.2v-.7zM186.2 194.8h1.4v.2h-1.4zM187.7 192.8h1.4v.2h-.6v1.6h-.2v-1.6h-.6zM189.4 192.8h1.3v.2h-1.1v.6h1v.2h-1v.6h1.1v.2h-1.3zM191.1 192.8h.3l.5 1.6 .6-1.6h.3v1.8h-.2v-1.5l-.5 1.5h-.3l-.5-1.5v1.5h-.2zM193.2 192.8h.8a.53 .53 0 0 1 .6 .5 .53 .53 0 0 1-.6 .6h-.6v.7h-.2zM193.4 193v.7h.5a.32 .32 0 0 0 .4-.4 .32 .32 0 0 0-.4-.3zM194.7 194.8h1.4v.2h-1.4zM196.3 193.2l.7-.3v1.7h-.2v-1.2h-.5z" fill-rule="evenodd"/>
<path d="M174.5 142h.8a.53 .53 0 0 1 .6 .5 .53 .53 0 0 1-.6 .5h-.6v.8h-.2zM174.7 142.2v.6h.5a.32 .32 0 0 0 .4-.3 .32 .32 0 0 0-.4-.3zM176.1 142.9a.94 .94 0 0 1 1.8 0 .94 .94 0 0 1-1.8 0zM176.5 142.4a.69 .69 0 0 0 0 1 .69 .69 0 0 0 1-.2 .68 .68 0 0 0-.1-.9 .68 .68 0 0 0-.9 .1zM178 142h.3l.3 1.5 .4-1.5h.3l.4 1.5 .3-1.5h.3l-.5 1.8h-.2l-.4-1.5-.5 1.5h-.2zM180.3 144h1.5v.1h-1.5zM182.2 142.2v.6h.4a.3 .3 0 0 0 .4-.3 .3 .3 0 0 0-.4-.3zM182.2 143v.6l.8-.1 .1-.2-.2-.3zM181.9 142h.8a.45 .45 0 0 1 .5 .3 .45 .45 0 0 1-.2 .5 .51 .51 0 0 1 .3 .7 .51 .51 0 0 1-.6 .3h-.8zM184.3 142.3l-.3 .8h.6zM184.2 142h.3l.6 1.8h-.3l-.1-.5h-.8l-.2 .5h-.2zM185 142h1.5v.2h-.6v1.6h-.3v-1.6h-.6zM186.6 142h1.4v.2h-.6v1.6h-.2v-1.6h-.6zM188.1 144h1.4v.1h-1.4zM189.5 142h.3l.5 1.5 .6-1.5h.2l-.6 1.8h-.3zM191.3 142.9a.94 .94 0 0 1 1.8 0 .94 .94 0 0 1-1.8 0zM191.7 142.4a.69 .69 0 0 0 0 1 .69 .69 0 0 0 1-.2 .68 .68 0 0 0-.1-.9 .68 .68 0 0 0-.9 .1zM193.4 142h.2v1.1a.47 .47 0 0 0 .5 .5 .47 .47 0 0 0 .4-.5v-1.1h.3v1a.73 .73 0 0 1-.7 .9 .73 .73 0 0 1-.7-.9zM195 142h1.5v.2h-.6v1.6h-.3v-1.6h-.6z" fill-rule="evenodd"/>
<path d="M174.5 139.4h.8a.53 .53 0 0 1 .6 .5 .53 .53 0 0 1-.6 .6h-.6v.7h-.2zM174.7 139.6v.7h.5a.32 .32 0 0 0 .4-.4 .32 .32 0 0 0-.4-.3zM176.1 140.3a.94 .94 0 0 1 1.8 0 .94 .94 0 0 1-1.8 0zM176.5 139.8a.69 .69 0 0 0 0 1 .69 .69 0 0 0 1-.1 .68 .68 0 0 0-.1-.9 .68 .68 0 0 0-.9 0zM178 139.4h.3l.3 1.5 .4-1.5h.3l.4 1.5 .3-1.5h.3l-.5 1.8h-.2l-.4-1.5-.5 1.5h-.2zM180.3 141.4h1.5v.2h-1.5zM182.2 139.6v.6h.4a.3 .3 0 0 0 .4-.3 .3 .3 0 0 0-.4-.3zM182.2 140.4v.6l.8-.1 .1-.2-.2-.3zM181.9 139.4h.8a.45 .45 0 0 1 .5 .3 .45 .45 0 0 1-.2 .6 .51 .51 0 0 1 .3 .6 .51 .51 0 0 1-.6 .3h-.8zM184.3 139.7l-.3 .8h.6zM184.2 139.4h.3l.6 1.8h-.3l-.1-.5h-.8l-.2 .5h-.2zM185 139.4h1.5v.2h-.6v1.6h-.3v-1.6h-.6zM186.6 139.4h1.4v.2h-.6v1.6h-.2v-1.6h-.6zM188.1 141.4h1.4v.2h-1.4zM189.8 139.6a.81 .81 0 0 1 1.4 .4h-.2a.63 .63 0 0 0-.9-.3 .63 .63 0 0 0-.2 .8 .58 .58 0 0 0 .6 .6 .58 .58 0 0 0 .5-.6h-.5v-.2h.8v.9h-.2l-.1-.2a.89 .89 0 0 1-1.2 .1 .89 .89 0 0 1-.1-1.3zM191.6 139.4h.3l1 1.5v-1.5h.2v1.8h-.3l-.9-1.4v1.4h-.3zM193.7 139.6v1.4h.5a.71 .71 0 0 0 .5-.7 .71 .71 0 0 0-.5-.7zM193.5 139.4h.7a.92 .92 0 0 1 .8 .9 .92 .92 0 0 1-.8 .9h-.7z" fill-rule="evenodd"/>
<path d="M226.4 26a.96 .96 0 0 1 1.2 .2 .96 .96 0 0 1-.1 1.3l.3 .2-.2 .1-.3-.2a.96 .96 0 0 1-1.2-.3 .96 .96 0 0 1 .3-1.3zM226.4 26.2a.74 .74 0 0 0-.1 1 .74 .74 0 0 0 .9 .3l-.2-.2 .1-.1 .2 .1a.72 .72 0 0 0 .1-1 .72 .72 0 0 0-1-.1zM228.2 26.1l.6-.2 .3 .3v.2h-.2a.37 .37 0 0 0-.4-.3 .37 .37 0 0 0-.3 .5v.2a.59 .59 0 0 1 .9 .2 .59 .59 0 0 1-.4 .8 .59 .59 0 0 1-.7-.6v-.7zM228.2 27.1a.4 .4 0 0 0 .8 0 .4 .4 0 0 0-.8 0zM229.3 27.9h1.4v.1h-1.4zM231 26a.72 .72 0 0 1 1.2 .4h-.2a.42 .42 0 0 0-.5-.4 .42 .42 0 0 0-.4 .5 1.47 1.47 0 0 1 1.2 .7 .74 .74 0 0 1-.8 .5 .74 .74 0 0 1-.7-.6h.2a.48 .48 0 0 0 .5 .4 .48 .48 0 0 0 .5-.4l-.4-.2a.56 .56 0 0 1-.6-.2 .56 .56 0 0 1 0-.7zM232.6 25.9h.8a.53 .53 0 0 1 .6 .5 .53 .53 0 0 1-.6 .5h-.5v.8h-.3zM232.9 26.1v.6h.4a.32 .32 0 0 0 .4-.3 .32 .32 0 0 0-.4-.3zM234.3 25.9h.3v1.8h-.3zM234.8 27.9h1.4v.1h-1.4zM236.6 26a.72 .72 0 0 1 1.1 .4h-.2a.42 .42 0 0 0-.5-.4 .42 .42 0 0 0-.4 .5 1.47 1.47 0 0 1 1.2 .7 .74 .74 0 0 1-.8 .5 .74 .74 0 0 1-.7-.6h.3a.48 .48 0 0 0 .4 .4 .48 .48 0 0 0 .5-.4l-.4-.2a.56 .56 0 0 1-.6-.2 .56 .56 0 0 1 .1-.7zM238.3 26.1v1.4h.5a.71 .71 0 0 0 .6-.7 .71 .71 0 0 0-.6-.7zM238.1 25.9h.7a.92 .92 0 0 1 .8 .9 .92 .92 0 0 1-.8 .9h-.7zM239.8 26.8a.95 .95 0 0 1 1.9 0 .95 .95 0 0 1-1.9 0zM240.3 26.2a.69 .69 0 0 0-.1 1.1 .69 .69 0 0 0 1.1-.2 .68 .68 0 0 0-.1-.9 .68 .68 0 0 0-.9 0zM241.7 27.9h1.4v.1h-1.4zM243.3 25.9h.4l.5 1.5 .5-1.5h.3v1.8h-.2v-1.5l-.5 1.5h-.2l-.6-1.5v1.5h-.2zM245.3 26.8a.95 .95 0 0 1 1.9 0 .95 .95 0 0 1-1.9 0zM245.8 26.2a.69 .69 0 0 0-.1 1.1 .69 .69 0 0 0 1.1-.2 .68 .68 0 0 0-.1-.9 .68 .68 0 0 0-.9 0zM247.6 26a.72 .72 0 0 1 1.1 .4h-.2a.42 .42 0 0 0-.5-.4 .42 .42 0 0 0-.3 .5 1.47 1.47 0 0 1 1.1 .7 .74 .74 0 0 1-.8 .5 .74 .74 0 0 1-.7-.6h.3a.48 .48 0 0 0 .4 .4 .48 .48 0 0 0 .5-.4l-.3-.2a.56 .56 0 0 1-.7-.2 .56 .56 0 0 1 .1-.7zM249.1 25.9h.3v1.8h-.3z" fill-rule="evenodd"/>
<path d="M226.4 31.1a.96 .96 0 0 1 1.2 .3 .96 .96 0 0 1-.1 1.2l.3 .2-.2 .2-.3-.2a.96 .96 0 0 1-1.2-.4 .96 .96 0 0 1 .3-1.3zM226.4 31.4a.74 .74 0 0 0-.1 .9 .74 .74 0 0 0 .9 .3l-.2-.1 .1-.2 .2 .2a.72 .72 0 0 0 .1-1 .72 .72 0 0 0-1-.1zM228.2 31.3l.6-.2 .3 .3v.1h-.2a.37 .37 0 0 0-.4-.2 .37 .37 0 0 0-.3 .4v.2a.59 .59 0 0 1 .9 .2 .59 .59 0 0 1-.4 .9 .59 .59 0 0 1-.7-.7v-.6zM228.2 32.3a.4 .4 0 0 0 .8 0 .4 .4 0 0 0-.8 0zM229.3 33h1.4v.2h-1.4zM231 31.1a.72 .72 0 0 1 1.2 .5h-.2a.42 .42 0 0 0-.5-.4 .42 .42 0 0 0-.4 .4 1.47 1.47 0 0 1 1.2 .7 .74 .74 0 0 1-.8 .6 .74 .74 0 0 1-.7-.6h.2a.48 .48 0 0 0 .5 .4 .48 .48 0 0 0 .5-.4l-.4-.2a.56 .56 0 0 1-.6-.3 .56 .56 0 0 1 0-.7zM232.6 31h.8a.53 .53 0 0 1 .6 .6 .53 .53 0 0 1-.6 .5h-.5v.7h-.3zM232.9 31.2v.7h.4a.32 .32 0 0 0 .4-.3 .32 .32 0 0 0-.4-.4zM234.3 31h.3v1.8h-.3zM234.8 33h1.4v.2h-1.4zM236.5 31.3a.79 .79 0 0 1 .8-.3 .79 .79 0 0 1 .6 .6h-.2a.62 .62 0 0 0-.9-.3 .62 .62 0 0 0-.2 .9 .56 .56 0 0 0 .5 .5 .56 .56 0 0 0 .6-.5h.2a.85 .85 0 0 1-1.1 .7 .85 .85 0 0 1-.5-1.2zM238.4 31.1a.72 .72 0 0 1 1.2 .5h-.3a.42 .42 0 0 0-.4-.4 .42 .42 0 0 0-.4 .4 1.47 1.47 0 0 1 1.1 .7 .74 .74 0 0 1-.8 .6 .74 .74 0 0 1-.6-.6h.2a.48 .48 0 0 0 .5 .4 .48 .48 0 0 0 .4-.4l-.3-.2a.56 .56 0 0 1-.7-.3 .56 .56 0 0 1 .1-.7zM240 31.4l.6-.3v1.7h-.2v-1.2h-.4z" fill-rule="evenodd"/>
<path d="M35.4 113.7a.96 .96 0 0 1 1.2 .2 .96 .96 0 0 1-.1 1.3l.3 .2-.1 .2-.3-.2a.96 .96 0 0 1-1.3-.4 .96 .96 0 0 1 .3-1.3zM35.4 114a.74 .74 0 0 0-.1 .9 .74 .74 0 0 0 .9 .3l-.2-.1 .1-.2 .2 .2a.72 .72 0 0 0 .1-1 .72 .72 0 0 0-1-.1zM37.2 113.8l.6-.1 .3 .3 .1 .1h-.3a.37 .37 0 0 0-.4-.3 .37 .37 0 0 0-.3 .5v.2a.59 .59 0 0 1 .9 .2 .59 .59 0 0 1-.4 .8 .59 .59 0 0 1-.7-.6v-.6zM37.2 114.9a.4 .4 0 0 0 .8 0 .4 .4 0 0 0-.8 0zM38.3 115.6h1.4v.1h-1.4zM40.1 113.7a.72 .72 0 0 1 1.1 .4h-.2a.42 .42 0 0 0-.4-.3 .42 .42 0 0 0-.4 .4 1.47 1.47 0 0 1 1.1 .7 .74 .74 0 0 1-.8 .6 .74 .74 0 0 1-.7-.7h.3a.48 .48 0 0 0 .5 .5 .48 .48 0 0 0 .4-.5l-.3-.2a.56 .56 0 0 1-.7-.2 .56 .56 0 0 1 .1-.7zM41.6 113.6h.9a.53 .53 0 0 1 .5 .5 .53 .53 0 0 1-.5 .6h-.6v.7h-.3zM41.9 113.8v.6h.5a.32 .32 0 0 0 .3-.3 .32 .32 0 0 0-.3-.3zM43.4 113.6h.2v1.8h-.2zM43.8 115.6h1.4v.1h-1.4zM45.6 113.8a.79 .79 0 0 1 .7-.2 .79 .79 0 0 1 .6 .6h-.2a.62 .62 0 0 0-.9-.3 .62 .62 0 0 0-.2 .8 .56 .56 0 0 0 .6 .6 .56 .56 0 0 0 .5-.5h.3a.85 .85 0 0 1-1.1 .6 .85 .85 0 0 1-.5-1.2zM47.4 113.7a.72 .72 0 0 1 1.2 .4h-.3a.42 .42 0 0 0-.4-.3 .42 .42 0 0 0-.4 .4 1.47 1.47 0 0 1 1.1 .7 .74 .74 0 0 1-.7 .6 .74 .74 0 0 1-.7-.7h.2a.48 .48 0 0 0 .5 .5 .48 .48 0 0 0 .5-.5l-.4-.2a.56 .56 0 0 1-.7-.2 .56 .56 0 0 1 .1-.7zM49 114l.7-.3v1.7h-.3v-1.2h-.4z" fill-rule="evenodd"/>
<path d="M174.7 108.5a.96 .96 0 0 1 1.3 .3 .96 .96 0 0 1-.1 1.3l.2 .2-.1 .1-.3-.2a.96 .96 0 0 1-1.3-.4 .96 .96 0 0 1 .3-1.3zM174.8 108.8a.74 .74 0 0 0-.1 .9 .74 .74 0 0 0 .8 .3l-.2-.1 .2-.2 .2 .2a.72 .72 0 0 0 .1-1 .72 .72 0 0 0-1-.1zM176.6 108.7l.6-.2 .3 .3v.2h-.2a.37 .37 0 0 0-.4-.3 .37 .37 0 0 0-.3 .4v.2a.59 .59 0 0 1 .9 .2 .59 .59 0 0 1-.4 .9 .59 .59 0 0 1-.7-.6v-.7zM176.6 109.7a.4 .4 0 0 0 .8 0 .4 .4 0 0 0-.8 0zM177.7 110.5h1.4v.1h-1.4zM179.4 108.7a.81 .81 0 0 1 1.4 .3h-.2a.63 .63 0 0 0-.9-.3 .63 .63 0 0 0-.2 .9 .58 .58 0 0 0 .6 .5 .58 .58 0 0 0 .5-.6h-.5v-.2h.8v1h-.2l-.1-.3a.89 .89 0 0 1-1.2 .1 .89 .89 0 0 1-.1-1.2zM181.3 108.4h.8a.53 .53 0 0 1 .5 .6 .53 .53 0 0 1-.5 .5h-.6v.8h-.2zM181.5 108.7v.6h.5a.32 .32 0 0 0 .4-.3 .32 .32 0 0 0-.4-.3zM183 108.4h.2v1.9h-.2zM183.5 109.4a.95 .95 0 0 1 1.9 0 .95 .95 0 0 1-1.9 0zM184 108.8a.69 .69 0 0 0 0 1.1 .69 .69 0 0 0 1-.2 .68 .68 0 0 0-.1-.9 .68 .68 0 0 0-.9 0zM185.4 110.5h1.4v.1h-1.4zM186.9 108.5h1.3l-.8 1.8h-.2l.1-.5 .6-1.1h-1z" fill-rule="evenodd"/>
<path d="M161.4 20.7h1.5v.2h-.6v1.6h-.3v-1.6h-.6zM163 21.6a.95 .95 0 0 1 1.9 0 .95 .95 0 0 1-1.9 0zM163.4 21.1a.69 .69 0 0 0 0 1 .69 .69 0 0 0 1-.1 .68 .68 0 0 0-.1-.9 .68 .68 0 0 0-.9 0zM165.1 20.7h.8a.53 .53 0 0 1 .5 .5 .53 .53 0 0 1-.5 .6h-.6v.7h-.2zM165.3 20.9v.6h.5a.32 .32 0 0 0 .4-.3 .32 .32 0 0 0-.4-.3zM166.6 22.7h1.4v.1h-1.4zM168 20.7h1.5v.2h-.6v1.6h-.3v-1.6h-.6zM169.7 20.7h1.4v.2h-1.1v.6h1v.2h-1v.6h1.1v.2h-1.4zM171.4 20.7h.3l.6 1.5 .5-1.5h.3v1.8h-.2v-1.5l-.5 1.5h-.3l-.5-1.5v1.5h-.2zM173.5 20.7h.9a.53 .53 0 0 1 .5 .5 .53 .53 0 0 1-.5 .6h-.6v.7h-.3zM173.8 20.9v.6h.5a.32 .32 0 0 0 .4-.3 .32 .32 0 0 0-.4-.3zM175 22.7h1.4v.1h-1.4zM176.8 20.8a.72 .72 0 0 1 1.2 .4h-.3a.42 .42 0 0 0-.4-.3 .42 .42 0 0 0-.4 .4 1.47 1.47 0 0 1 1.1 .7 .74 .74 0 0 1-.8 .6 .74 .74 0 0 1-.6-.7h.2a.48 .48 0 0 0 .5 .5 .48 .48 0 0 0 .4-.5l-.3-.2a.56 .56 0 0 1-.7-.2 .56 .56 0 0 1 .1-.7zM178.2 21.6a.95 .95 0 0 1 1.9 0 .95 .95 0 0 1-1.9 0zM178.7 21.1a.69 .69 0 0 0-.1 1 .69 .69 0 0 0 1.1-.1 .68 .68 0 0 0-.1-.9 .68 .68 0 0 0-.9 0zM180.3 20.7h.2v1.6h1v.2h-1.2zM182.4 21l-.3 .8h.5zM182.2 20.7h.3l.7 1.8h-.3l-.2-.5h-.7l-.2 .5h-.2zM183.7 20.9v.6h.5a.31 .31 0 0 0 .4-.3 .31 .31 0 0 0-.3-.3zM183.4 20.7a1.57 1.57 0 0 1 1.4 .2l.1 .4-.3 .3 .2 .2 .1 .7h-.3v-.6l-.4-.2h-.5v.8h-.3zM185 22.7h1.5v.1h-1.5zM186.7 20.7h.8a.53 .53 0 0 1 .5 .5 .53 .53 0 0 1-.5 .6h-.6v.7h-.2zM186.9 20.9v.6h.5a.32 .32 0 0 0 .4-.3 .32 .32 0 0 0-.4-.3zM188.8 21l-.3 .8h.6zM188.7 20.7h.3l.6 1.8h-.2l-.2-.5h-.8l-.1 .5h-.3zM189.8 20.7h.3l1 1.5v-1.5h.2v1.8h-.3l-.9-1.4v1.4h-.3zM191.7 20.7h1.3v.2h-1.1v.6h1.1v.2h-1.1v.6h1.2v.2h-1.4zM193.4 20.7h.2v1.6h.9v.2h-1.1zM194.7 21.7h.6v.2h-.6zM195.8 20.9a.61 .61 0 0 1 .9 .3 .61 .61 0 0 1-.6 .7l-.3 .4h.9v.2h-1.2a1.5 1.5 0 0 1 1-1.1 .36 .36 0 0 0-.3-.5 .36 .36 0 0 0-.4 .5h-.2z" fill-rule="evenodd"/>
<path d="M32.4 20.7h1.5v.2h-.7v1.6h-.2v-1.6h-.6zM33.9 21.6a.95 .95 0 0 1 1.9 0 .95 .95 0 0 1-1.9 0zM34.4 21.1a.69 .69 0 0 0-.1 1 .69 .69 0 0 0 1.1-.1 .68 .68 0 0 0-.1-.9 .68 .68 0 0 0-.9 0zM36 20.7h.9a.53 .53 0 0 1 .5 .5 .53 .53 0 0 1-.5 .6h-.6v.7h-.3zM36.3 20.9v.6h.5a.32 .32 0 0 0 .3-.3 .32 .32 0 0 0-.3-.3zM37.5 22.7h1.4v.1h-1.4zM39 20.7h1.4v.2h-.6v1.6h-.2v-1.6h-.6zM40.7 20.7h1.3v.2h-1.1v.6h1v.2h-1v.6h1.1v.2h-1.3zM42.4 20.7h.3l.5 1.5 .6-1.5h.3v1.8h-.2v-1.5l-.5 1.5h-.3l-.5-1.5v1.5h-.2zM44.5 20.7h.8a.53 .53 0 0 1 .6 .5 .53 .53 0 0 1-.6 .6h-.5v.7h-.3zM44.8 20.9v.6h.4a.32 .32 0 0 0 .4-.3 .32 .32 0 0 0-.4-.3zM46 22.7h1.4v.1h-1.4zM47.7 20.8a.72 .72 0 0 1 1.2 .4h-.2a.42 .42 0 0 0-.5-.3 .42 .42 0 0 0-.4 .4 1.47 1.47 0 0 1 1.2 .7 .74 .74 0 0 1-.8 .6 .74 .74 0 0 1-.7-.7h.2a.48 .48 0 0 0 .5 .5 .48 .48 0 0 0 .5-.5l-.4-.2a.56 .56 0 0 1-.6-.2 .56 .56 0 0 1 0-.7zM49.2 21.6a.95 .95 0 0 1 1.9 0 .95 .95 0 0 1-1.9 0zM49.6 21.1a.69 .69 0 0 0 0 1 .69 .69 0 0 0 1-.1 .68 .68 0 0 0-.1-.9 .68 .68 0 0 0-.9 0zM51.3 20.7h.2v1.6h.9v.2h-1.1zM53.3 21l-.3 .8h.6zM53.2 20.7h.3l.6 1.8h-.2l-.2-.5h-.7l-.2 .5h-.3zM54.6 20.9v.6h.6a.31 .31 0 0 0 .4-.3 .31 .31 0 0 0-.4-.3zM54.4 20.7a1.57 1.57 0 0 1 1.3 .2l.1 .4-.2 .3 .2 .2 .1 .7h-.3l-.1-.6-.3-.2h-.6v.8h-.2zM56 22.7h1.4v.1h-1.4zM57.6 20.7h.9a.53 .53 0 0 1 .5 .5 .53 .53 0 0 1-.5 .6h-.6v.7h-.3zM57.9 20.9v.6h.5a.32 .32 0 0 0 .3-.3 .32 .32 0 0 0-.3-.3zM59.8 21l-.3 .8h.6zM59.6 20.7h.3l.7 1.8h-.3l-.2-.5h-.7l-.2 .5h-.2zM60.8 20.7h.3l.9 1.5v-1.5h.3v1.8h-.3l-1-1.4v1.4h-.2zM62.7 20.7h1.3v.2h-1.1v.6h1v.2h-1v.6h1.1v.2h-1.3zM64.3 20.7h.3v1.6h.9v.2h-1.2zM65.7 21.7h.6v.2h-.6zM66.7 20.9a.61 .61 0 0 1 1 .3 .61 .61 0 0 1-.6 .7l-.4 .4h1v.2h-1.2a1.5 1.5 0 0 1 .9-1.1 .36 .36 0 0 0-.3-.5 .36 .36 0 0 0-.3 .5h-.3z" fill-rule="evenodd"/>
<path d="M161.4 25.9h1.5v.2h-.6v1.6h-.3v-1.6h-.6zM163 26.8a.95 .95 0 0 1 1.9 0 .95 .95 0 0 1-1.9 0zM163.4 26.2a.69 .69 0 0 0 0 1.1 .69 .69 0 0 0 1-.2 .68 .68 0 0 0-.1-.9 .68 .68 0 0 0-.9 0zM165.1 25.9h.8a.53 .53 0 0 1 .5 .5 .53 .53 0 0 1-.5 .5h-.6v.8h-.2zM165.3 26.1v.6h.5a.32 .32 0 0 0 .4-.3 .32 .32 0 0 0-.4-.3zM166.6 27.9h1.4v.1h-1.4zM168 25.9h1.5v.2h-.6v1.6h-.3v-1.6h-.6zM169.7 25.9h1.4v.2h-1.1v.5h1v.3h-1v.6h1.1v.2h-1.4zM171.4 25.9h.3l.6 1.5 .5-1.5h.3v1.8h-.2v-1.5l-.5 1.5h-.3l-.5-1.5v1.5h-.2zM173.5 25.9h.9a.53 .53 0 0 1 .5 .5 .53 .53 0 0 1-.5 .5h-.6v.8h-.3zM173.8 26.1v.6h.5a.32 .32 0 0 0 .4-.3 .32 .32 0 0 0-.4-.3zM175 27.9h1.4v.1h-1.4zM176.8 26a.72 .72 0 0 1 1.2 .4h-.3a.42 .42 0 0 0-.4-.4 .42 .42 0 0 0-.4 .5 1.47 1.47 0 0 1 1.1 .7 .74 .74 0 0 1-.8 .5 .74 .74 0 0 1-.6-.6h.2a.48 .48 0 0 0 .5 .4 .48 .48 0 0 0 .4-.4l-.3-.2a.56 .56 0 0 1-.7-.2 .56 .56 0 0 1 .1-.7zM178.2 26.8a.95 .95 0 0 1 1.9 0 .95 .95 0 0 1-1.9 0zM178.7 26.2a.69 .69 0 0 0-.1 1.1 .69 .69 0 0 0 1.1-.2 .68 .68 0 0 0-.1-.9 .68 .68 0 0 0-.9 0zM180.3 25.9h.2v1.6h1v.2h-1.2zM182.4 26.1l-.3 .8h.5zM182.2 25.9h.3l.7 1.8h-.3l-.2-.6h-.7l-.2 .6h-.2zM183.7 26.1v.6h.5a.31 .31 0 0 0 .4-.3 .31 .31 0 0 0-.3-.3zM183.4 25.9a1.57 1.57 0 0 1 1.4 .1l.1 .5-.3 .3 .2 .2 .1 .7h-.3v-.7l-.4-.1h-.5v.8h-.3zM185 27.9h1.5v.1h-1.5zM186.7 25.9h.8a.53 .53 0 0 1 .5 .5 .53 .53 0 0 1-.5 .5h-.6v.8h-.2zM186.9 26.1v.6h.5a.32 .32 0 0 0 .4-.3 .32 .32 0 0 0-.4-.3zM188.8 26.1l-.3 .8h.6zM188.7 25.9h.3l.6 1.8h-.2l-.2-.6h-.8l-.1 .6h-.3zM189.8 25.9h.3l1 1.4v-1.4h.2v1.8h-.3l-.9-1.5v1.5h-.3zM191.7 25.9h1.3v.2h-1.1v.5h1.1v.3h-1.1v.6h1.2v.2h-1.4zM193.4 25.9h.2v1.6h.9v.2h-1.1zM194.7 26.9h.6v.2h-.6zM196.3 26.3l-.6 .8h.6zM196.3 25.9h.2v1.2h.3v.2h-.3v.4h-.2v-.4h-.8v-.3z" fill-rule="evenodd"/>
<path d="M32.4 25.9h1.5v.2h-.7v1.6h-.2v-1.6h-.6zM33.9 26.8a.95 .95 0 0 1 1.9 0 .95 .95 0 0 1-1.9 0zM34.4 26.2a.69 .69 0 0 0-.1 1.1 .69 .69 0 0 0 1.1-.2 .68 .68 0 0 0-.1-.9 .68 .68 0 0 0-.9 0zM36 25.9h.9a.53 .53 0 0 1 .5 .5 .53 .53 0 0 1-.5 .5h-.6v.8h-.3zM36.3 26.1v.6h.5a.32 .32 0 0 0 .3-.3 .32 .32 0 0 0-.3-.3zM37.5 27.9h1.4v.1h-1.4zM39 25.9h1.4v.2h-.6v1.6h-.2v-1.6h-.6zM40.7 25.9h1.3v.2h-1.1v.5h1v.3h-1v.6h1.1v.2h-1.3zM42.4 25.9h.3l.5 1.5 .6-1.5h.3v1.8h-.2v-1.5l-.5 1.5h-.3l-.5-1.5v1.5h-.2zM44.5 25.9h.8a.53 .53 0 0 1 .6 .5 .53 .53 0 0 1-.6 .5h-.5v.8h-.3zM44.8 26.1v.6h.4a.32 .32 0 0 0 .4-.3 .32 .32 0 0 0-.4-.3zM46 27.9h1.4v.1h-1.4zM47.7 26a.72 .72 0 0 1 1.2 .4h-.2a.42 .42 0 0 0-.5-.4 .42 .42 0 0 0-.4 .5 1.47 1.47 0 0 1 1.2 .7 .74 .74 0 0 1-.8 .5 .74 .74 0 0 1-.7-.6h.2a.48 .48 0 0 0 .5 .4 .48 .48 0 0 0 .5-.4l-.4-.2a.56 .56 0 0 1-.6-.2 .56 .56 0 0 1 0-.7zM49.2 26.8a.95 .95 0 0 1 1.9 0 .95 .95 0 0 1-1.9 0zM49.6 26.2a.69 .69 0 0 0 0 1.1 .69 .69 0 0 0 1-.2 .68 .68 0 0 0-.1-.9 .68 .68 0 0 0-.9 0zM51.3 25.9h.2v1.6h.9v.2h-1.1zM53.3 26.1l-.3 .8h.6zM53.2 25.9h.3l.6 1.8h-.2l-.2-.6h-.7l-.2 .6h-.3zM54.6 26.1v.6h.6a.31 .31 0 0 0 .4-.3 .31 .31 0 0 0-.4-.3zM54.4 25.9a1.57 1.57 0 0 1 1.3 .1l.1 .5-.2 .3 .2 .2 .1 .7h-.3l-.1-.7-.3-.1h-.6v.8h-.2zM56 27.9h1.4v.1h-1.4zM57.6 25.9h.9a.53 .53 0 0 1 .5 .5 .53 .53 0 0 1-.5 .5h-.6v.8h-.3zM57.9 26.1v.6h.5a.32 .32 0 0 0 .3-.3 .32 .32 0 0 0-.3-.3zM59.8 26.1l-.3 .8h.6zM59.6 25.9h.3l.7 1.8h-.3l-.2-.6h-.7l-.2 .6h-.2zM60.8 25.9h.3l.9 1.4v-1.4h.3v1.8h-.3l-1-1.5v1.5h-.2zM62.7 25.9h1.3v.2h-1.1v.5h1v.3h-1v.6h1.1v.2h-1.3zM64.3 25.9h.3v1.6h.9v.2h-1.2zM65.7 26.9h.6v.2h-.6zM67.2 26.3l-.5 .8h.5zM67.3 25.9h.2v1.2h.2v.2h-.2v.4h-.3v-.4h-.7v-.3z" fill-rule="evenodd"/>
<path d="M161.4 23.3h1.5v.2h-.6v1.6h-.3v-1.6h-.6zM163 24.2a.95 .95 0 0 1 1.9 0 .95 .95 0 0 1-1.9 0zM163.4 23.6a.69 .69 0 0 0 0 1.1 .69 .69 0 0 0 1-.2 .68 .68 0 0 0-.1-.9 .68 .68 0 0 0-.9 0zM165.1 23.3h.8a.53 .53 0 0 1 .5 .5 .53 .53 0 0 1-.5 .5h-.6v.8h-.2zM165.3 23.5v.6h.5a.32 .32 0 0 0 .4-.3 .32 .32 0 0 0-.4-.3zM166.6 25.3h1.4v.1h-1.4zM168 23.3h1.5v.2h-.6v1.6h-.3v-1.6h-.6zM169.7 23.3h1.4v.2h-1.1v.6h1v.2h-1v.6h1.1v.2h-1.4zM171.4 23.3h.3l.6 1.5 .5-1.5h.3v1.8h-.2v-1.5l-.5 1.5h-.3l-.5-1.5v1.5h-.2zM173.5 23.3h.9a.53 .53 0 0 1 .5 .5 .53 .53 0 0 1-.5 .5h-.6v.8h-.3zM173.8 23.5v.6h.5a.32 .32 0 0 0 .4-.3 .32 .32 0 0 0-.4-.3zM175 25.3h1.4v.1h-1.4zM176.8 23.4a.72 .72 0 0 1 1.2 .4h-.3a.42 .42 0 0 0-.4-.3 .42 .42 0 0 0-.4 .4 1.47 1.47 0 0 1 1.1 .7 .74 .74 0 0 1-.8 .6 .74 .74 0 0 1-.6-.7h.2a.48 .48 0 0 0 .5 .5 .48 .48 0 0 0 .4-.5l-.3-.2a.56 .56 0 0 1-.7-.2 .56 .56 0 0 1 .1-.7zM178.2 24.2a.95 .95 0 0 1 1.9 0 .95 .95 0 0 1-1.9 0zM178.7 23.6a.69 .69 0 0 0-.1 1.1 .69 .69 0 0 0 1.1-.2 .68 .68 0 0 0-.1-.9 .68 .68 0 0 0-.9 0zM180.3 23.3h.2v1.6h1v.2h-1.2zM182.4 23.6l-.3 .8h.5zM182.2 23.3h.3l.7 1.8h-.3l-.2-.5h-.7l-.2 .5h-.2zM183.7 23.5v.6h.5a.31 .31 0 0 0 .4-.3 .31 .31 0 0 0-.3-.3zM183.4 23.3a1.57 1.57 0 0 1 1.4 .1l.1 .5-.3 .3 .2 .2 .1 .7h-.3v-.7l-.4-.1h-.5v.8h-.3zM185 25.3h1.5v.1h-1.5zM186.7 23.3h.8a.53 .53 0 0 1 .5 .5 .53 .53 0 0 1-.5 .5h-.6v.8h-.2zM186.9 23.5v.6h.5a.32 .32 0 0 0 .4-.3 .32 .32 0 0 0-.4-.3zM188.8 23.6l-.3 .8h.6zM188.7 23.3h.3l.6 1.8h-.2l-.2-.5h-.8l-.1 .5h-.3zM189.8 23.3h.3l1 1.5v-1.5h.2v1.8h-.3l-.9-1.5v1.5h-.3zM191.7 23.3h1.3v.2h-1.1v.6h1.1v.2h-1.1v.6h1.2v.2h-1.4zM193.4 23.3h.2v1.6h.9v.2h-1.1zM194.7 24.3h.6v.2h-.6zM195.7 23.4a.51 .51 0 0 1 .8 0 .51 .51 0 0 1-.1 .8 .59 .59 0 0 1-.1 1 .59 .59 0 0 1-.8-.6h.2a.36 .36 0 0 0 .5 .3 .36 .36 0 0 0 .1-.6h-.3v-.2a.29 .29 0 0 0 .4-.2 .29 .29 0 0 0-.3-.4l-.3 .2v.2h-.3z" fill-rule="evenodd"/>
<path d="M32.4 23.3h1.5v.2h-.7v1.6h-.2v-1.6h-.6zM33.9 24.2a.95 .95 0 0 1 1.9 0 .95 .95 0 0 1-1.9 0zM34.4 23.6a.69 .69 0 0 0-.1 1.1 .69 .69 0 0 0 1.1-.2 .68 .68 0 0 0-.1-.9 .68 .68 0 0 0-.9 0zM36 23.3h.9a.53 .53 0 0 1 .5 .5 .53 .53 0 0 1-.5 .5h-.6v.8h-.3zM36.3 23.5v.6h.5a.32 .32 0 0 0 .3-.3 .32 .32 0 0 0-.3-.3zM37.5 25.3h1.4v.1h-1.4zM39 23.3h1.4v.2h-.6v1.6h-.2v-1.6h-.6zM40.7 23.3h1.3v.2h-1.1v.6h1v.2h-1v.6h1.1v.2h-1.3zM42.4 23.3h.3l.5 1.5 .6-1.5h.3v1.8h-.2v-1.5l-.5 1.5h-.3l-.5-1.5v1.5h-.2zM44.5 23.3h.8a.53 .53 0 0 1 .6 .5 .53 .53 0 0 1-.6 .5h-.5v.8h-.3zM44.8 23.5v.6h.4a.32 .32 0 0 0 .4-.3 .32 .32 0 0 0-.4-.3zM46 25.3h1.4v.1h-1.4zM47.7 23.4a.72 .72 0 0 1 1.2 .4h-.2a.42 .42 0 0 0-.5-.3 .42 .42 0 0 0-.4 .4 1.47 1.47 0 0 1 1.2 .7 .74 .74 0 0 1-.8 .6 .74 .74 0 0 1-.7-.7h.2a.48 .48 0 0 0 .5 .5 .48 .48 0 0 0 .5-.5l-.4-.2a.56 .56 0 0 1-.6-.2 .56 .56 0 0 1 0-.7zM49.2 24.2a.95 .95 0 0 1 1.9 0 .95 .95 0 0 1-1.9 0zM49.6 23.6a.69 .69 0 0 0 0 1.1 .69 .69 0 0 0 1-.2 .68 .68 0 0 0-.1-.9 .68 .68 0 0 0-.9 0zM51.3 23.3h.2v1.6h.9v.2h-1.1zM53.3 23.6l-.3 .8h.6zM53.2 23.3h.3l.6 1.8h-.2l-.2-.5h-.7l-.2 .5h-.3zM54.6 23.5v.6h.6a.31 .31 0 0 0 .4-.3 .31 .31 0 0 0-.4-.3zM54.4 23.3a1.57 1.57 0 0 1 1.3 .1l.1 .5-.2 .3 .2 .2 .1 .7h-.3l-.1-.7-.3-.1h-.6v.8h-.2zM56 25.3h1.4v.1h-1.4zM57.6 23.3h.9a.53 .53 0 0 1 .5 .5 .53 .53 0 0 1-.5 .5h-.6v.8h-.3zM57.9 23.5v.6h.5a.32 .32 0 0 0 .3-.3 .32 .32 0 0 0-.3-.3zM59.8 23.6l-.3 .8h.6zM59.6 23.3h.3l.7 1.8h-.3l-.2-.5h-.7l-.2 .5h-.2zM60.8 23.3h.3l.9 1.5v-1.5h.3v1.8h-.3l-1-1.5v1.5h-.2zM62.7 23.3h1.3v.2h-1.1v.6h1v.2h-1v.6h1.1v.2h-1.3zM64.3 23.3h.3v1.6h.9v.2h-1.2zM65.7 24.3h.6v.2h-.6zM66.7 23.4a.51 .51 0 0 1 .8 0 .51 .51 0 0 1-.1 .8 .59 .59 0 0 1-.1 1 .59 .59 0 0 1-.8-.6h.2a.36 .36 0 0 0 .5 .3 .36 .36 0 0 0 0-.6h-.2v-.2a.29 .29 0 0 0 .4-.2 .29 .29 0 0 0-.3-.4l-.3 .2-.1 .2h-.2z" fill-rule="evenodd"/>
<path d="M161.4 18.1h1.5v.2h-.6v1.6h-.3v-1.6h-.6zM163 19.1a.95 .95 0 0 1 1.9 0 .95 .95 0 0 1-1.9 0zM163.4 18.5a.69 .69 0 0 0 0 1.1 .69 .69 0 0 0 1-.2 .68 .68 0 0 0-.1-.9 .68 .68 0 0 0-.9 0zM165.1 18.1h.8a.53 .53 0 0 1 .5 .6 .53 .53 0 0 1-.5 .5h-.6v.7h-.2zM165.3 18.3v.7h.5a.32 .32 0 0 0 .4-.3 .32 .32 0 0 0-.4-.4zM166.6 20.1h1.4v.2h-1.4zM168 18.1h1.5v.2h-.6v1.6h-.3v-1.6h-.6zM169.7 18.1h1.4v.2h-1.1v.6h1v.2h-1v.6h1.1v.2h-1.4zM171.4 18.1h.3l.6 1.6 .5-1.6h.3v1.8h-.2v-1.5l-.5 1.5h-.3l-.5-1.5v1.5h-.2zM173.5 18.1h.9a.53 .53 0 0 1 .5 .6 .53 .53 0 0 1-.5 .5h-.6v.7h-.3zM173.8 18.3v.7h.5a.32 .32 0 0 0 .4-.3 .32 .32 0 0 0-.4-.4zM175 20.1h1.4v.2h-1.4zM176.8 18.2a.72 .72 0 0 1 1.2 .5h-.3a.42 .42 0 0 0-.4-.4 .42 .42 0 0 0-.4 .4 1.47 1.47 0 0 1 1.1 .7 .74 .74 0 0 1-.8 .6 .74 .74 0 0 1-.6-.6h.2a.48 .48 0 0 0 .5 .4 .48 .48 0 0 0 .4-.5l-.3-.1a.56 .56 0 0 1-.7-.3 .56 .56 0 0 1 .1-.7zM178.2 19.1a.95 .95 0 0 1 1.9 0 .95 .95 0 0 1-1.9 0zM178.7 18.5a.69 .69 0 0 0-.1 1.1 .69 .69 0 0 0 1.1-.2 .68 .68 0 0 0-.1-.9 .68 .68 0 0 0-.9 0zM180.3 18.1h.2v1.6h1v.2h-1.2zM182.4 18.4l-.3 .8h.5zM182.2 18.1h.3l.7 1.8h-.3l-.2-.5h-.7l-.2 .5h-.2zM183.7 18.3v.7h.5a.31 .31 0 0 0 .4-.3 .31 .31 0 0 0-.3-.4zM183.4 18.1a1.57 1.57 0 0 1 1.4 .2l.1 .5-.3 .3 .2 .2 .1 .6h-.3v-.6l-.4-.1h-.5v.7h-.3zM185 20.1h1.5v.2h-1.5zM186.7 18.1h.8a.53 .53 0 0 1 .5 .6 .53 .53 0 0 1-.5 .5h-.6v.7h-.2zM186.9 18.3v.7h.5a.32 .32 0 0 0 .4-.3 .32 .32 0 0 0-.4-.4zM188.8 18.4l-.3 .8h.6zM188.7 18.1h.3l.6 1.8h-.2l-.2-.5h-.8l-.1 .5h-.3zM189.8 18.1h.3l1 1.5v-1.5h.2v1.8h-.3l-.9-1.4v1.4h-.3zM191.7 18.1h1.3v.2h-1.1v.6h1.1v.2h-1.1v.6h1.2v.2h-1.4zM193.4 18.1h.2v1.6h.9v.2h-1.1zM194.7 19.1h.6v.3h-.6zM195.7 18.5l.6-.3v1.7h-.2v-1.2h-.4z" fill-rule="evenodd"/>
<path d="M32.4 18.1h1.5v.2h-.7v1.6h-.2v-1.6h-.6zM33.9 19.1a.95 .95 0 0 1 1.9 0 .95 .95 0 0 1-1.9 0zM34.4 18.5a.69 .69 0 0 0-.1 1.1 .69 .69 0 0 0 1.1-.2 .68 .68 0 0 0-.1-.9 .68 .68 0 0 0-.9 0zM36 18.1h.9a.53 .53 0 0 1 .5 .6 .53 .53 0 0 1-.5 .5h-.6v.7h-.3zM36.3 18.3v.7h.5a.32 .32 0 0 0 .3-.3 .32 .32 0 0 0-.3-.4zM37.5 20.1h1.4v.2h-1.4zM39 18.1h1.4v.2h-.6v1.6h-.2v-1.6h-.6zM40.7 18.1h1.3v.2h-1.1v.6h1v.2h-1v.6h1.1v.2h-1.3zM42.4 18.1h.3l.5 1.6 .6-1.6h.3v1.8h-.2v-1.5l-.5 1.5h-.3l-.5-1.5v1.5h-.2zM44.5 18.1h.8a.53 .53 0 0 1 .6 .6 .53 .53 0 0 1-.6 .5h-.5v.7h-.3zM44.8 18.3v.7h.4a.32 .32 0 0 0 .4-.3 .32 .32 0 0 0-.4-.4zM46 20.1h1.4v.2h-1.4zM47.7 18.2a.72 .72 0 0 1 1.2 .5h-.2a.42 .42 0 0 0-.5-.4 .42 .42 0 0 0-.4 .4 1.47 1.47 0 0 1 1.2 .7 .74 .74 0 0 1-.8 .6 .74 .74 0 0 1-.7-.6h.2a.48 .48 0 0 0 .5 .4 .48 .48 0 0 0 .5-.5l-.4-.1a.56 .56 0 0 1-.6-.3 .56 .56 0 0 1 0-.7zM49.2 19.1a.95 .95 0 0 1 1.9 0 .95 .95 0 0 1-1.9 0zM49.6 18.5a.69 .69 0 0 0 0 1.1 .69 .69 0 0 0 1-.2 .68 .68 0 0 0-.1-.9 .68 .68 0 0 0-.9 0zM51.3 18.1h.2v1.6h.9v.2h-1.1zM53.3 18.4l-.3 .8h.6zM53.2 18.1h.3l.6 1.8h-.2l-.2-.5h-.7l-.2 .5h-.3zM54.6 18.3v.7h.6a.31 .31 0 0 0 .4-.3 .31 .31 0 0 0-.4-.4zM54.4 18.1a1.57 1.57 0 0 1 1.3 .2l.1 .5-.2 .3 .2 .2 .1 .6h-.3l-.1-.6-.3-.1h-.6v.7h-.2zM56 20.1h1.4v.2h-1.4zM57.6 18.1h.9a.53 .53 0 0 1 .5 .6 .53 .53 0 0 1-.5 .5h-.6v.7h-.3zM57.9 18.3v.7h.5a.32 .32 0 0 0 .3-.3 .32 .32 0 0 0-.3-.4zM59.8 18.4l-.3 .8h.6zM59.6 18.1h.3l.7 1.8h-.3l-.2-.5h-.7l-.2 .5h-.2zM60.8 18.1h.3l.9 1.5v-1.5h.3v1.8h-.3l-1-1.4v1.4h-.2zM62.7 18.1h1.3v.2h-1.1v.6h1v.2h-1v.6h1.1v.2h-1.3zM64.3 18.1h.3v1.6h.9v.2h-1.2zM65.7 19.1h.6v.3h-.6zM66.6 18.5l.7-.3v1.7h-.2v-1.2h-.5z" fill-rule="evenodd"/>
<path d="M226.4 33.7a.96 .96 0 0 1 1.2 .2 .96 .96 0 0 1-.1 1.3l.3 .2-.2 .2-.3-.2a.96 .96 0 0 1-1.2-.4 .96 .96 0 0 1 .3-1.3zM226.4 34a.74 .74 0 0 0-.1 .9 .74 .74 0 0 0 .9 .3l-.2-.1 .1-.2 .2 .2a.72 .72 0 0 0 .1-1 .72 .72 0 0 0-1-.1zM228.2 33.8l.6-.1 .3 .3v.1h-.2a.37 .37 0 0 0-.4-.2 .37 .37 0 0 0-.3 .4v.2a.59 .59 0 0 1 .9 .2 .59 .59 0 0 1-.4 .8 .59 .59 0 0 1-.7-.6v-.6zM228.2 34.9a.4 .4 0 0 0 .8 0 .4 .4 0 0 0-.8 0zM229.3 35.6h1.4v.1h-1.4zM231 33.7a.72 .72 0 0 1 1.2 .4h-.2a.42 .42 0 0 0-.5-.3 .42 .42 0 0 0-.4 .4 1.47 1.47 0 0 1 1.2 .7 .74 .74 0 0 1-.8 .6 .74 .74 0 0 1-.7-.7h.2a.48 .48 0 0 0 .5 .5 .48 .48 0 0 0 .5-.5l-.4-.2a.56 .56 0 0 1-.6-.2 .56 .56 0 0 1 0-.7zM232.6 33.6h.8a.53 .53 0 0 1 .6 .5 .53 .53 0 0 1-.6 .6h-.5v.7h-.3zM232.9 33.8v.7h.4a.32 .32 0 0 0 .4-.4 .32 .32 0 0 0-.4-.3zM234.3 33.6h.3v1.8h-.3zM234.8 35.6h1.4v.1h-1.4zM236.5 33.8a.79 .79 0 0 1 .8-.2 .79 .79 0 0 1 .6 .6h-.2a.62 .62 0 0 0-.9-.3 .62 .62 0 0 0-.2 .8 .56 .56 0 0 0 .5 .6 .56 .56 0 0 0 .6-.5h.2a.85 .85 0 0 1-1.1 .6 .85 .85 0 0 1-.5-1.2zM238.4 33.7a.72 .72 0 0 1 1.2 .4h-.3a.42 .42 0 0 0-.4-.3 .42 .42 0 0 0-.4 .4 1.47 1.47 0 0 1 1.1 .7 .74 .74 0 0 1-.8 .6 .74 .74 0 0 1-.6-.7h.2a.48 .48 0 0 0 .5 .5 .48 .48 0 0 0 .4-.5l-.3-.2a.56 .56 0 0 1-.7-.2 .56 .56 0 0 1 .1-.7zM240 33.8a.64 .64 0 0 1 .8 0 .64 .64 0 0 1 .2 .7 .66 .66 0 0 1-.6 1 .66 .66 0 0 1-.6-.9zM240.3 33.9a.93 .93 0 0 0 .1 1.4 .86 .86 0 0 0 0-1.4z" fill-rule="evenodd"/>
<path d="M35.4 108.5a.96 .96 0 0 1 1.2 .3 .96 .96 0 0 1-.1 1.3l.3 .2-.1 .1-.3-.2a.96 .96 0 0 1-1.3-.4 .96 .96 0 0 1 .3-1.3zM35.4 108.8a.74 .74 0 0 0-.1 .9 .74 .74 0 0 0 .9 .3l-.2-.1 .1-.2 .2 .2a.72 .72 0 0 0 .1-1 .72 .72 0 0 0-1-.1zM37.2 108.7l.6-.2 .3 .3 .1 .2h-.3a.37 .37 0 0 0-.4-.3 .37 .37 0 0 0-.3 .4v.2a.59 .59 0 0 1 .9 .2 .59 .59 0 0 1-.4 .9 .59 .59 0 0 1-.7-.6v-.7zM37.2 109.7a.4 .4 0 0 0 .8 0 .4 .4 0 0 0-.8 0zM38.3 110.5h1.4v.1h-1.4zM40.1 108.6a.72 .72 0 0 1 1.1 .4h-.2a.42 .42 0 0 0-.4-.4 .42 .42 0 0 0-.4 .4 1.47 1.47 0 0 1 1.1 .8 .74 .74 0 0 1-.8 .5 .74 .74 0 0 1-.7-.6h.3a.48 .48 0 0 0 .5 .4 .48 .48 0 0 0 .4-.4l-.3-.2a.56 .56 0 0 1-.7-.2 .56 .56 0 0 1 .1-.7zM41.6 108.4h.9a.53 .53 0 0 1 .5 .6 .53 .53 0 0 1-.5 .5h-.6v.8h-.3zM41.9 108.7v.6h.5a.32 .32 0 0 0 .3-.3 .32 .32 0 0 0-.3-.3zM43.4 108.4h.2v1.9h-.2zM43.8 110.5h1.4v.1h-1.4zM45.6 108.7a.79 .79 0 0 1 .7-.3 .79 .79 0 0 1 .6 .6h-.2a.62 .62 0 0 0-.9-.3 .62 .62 0 0 0-.2 .9 .56 .56 0 0 0 .6 .5 .56 .56 0 0 0 .5-.5h.3a.85 .85 0 0 1-1.1 .7 .85 .85 0 0 1-.5-1.2zM47.4 108.6a.72 .72 0 0 1 1.2 .4h-.3a.42 .42 0 0 0-.4-.4 .42 .42 0 0 0-.4 .4 1.47 1.47 0 0 1 1.1 .8 .74 .74 0 0 1-.7 .5 .74 .74 0 0 1-.7-.6h.2a.48 .48 0 0 0 .5 .4 .48 .48 0 0 0 .5-.4l-.4-.2a.56 .56 0 0 1-.7-.2 .56 .56 0 0 1 .1-.7zM49 108.7a.64 .64 0 0 1 .8-.1 .64 .64 0 0 1 .3 .8 .66 .66 0 0 1-.6 .9 .66 .66 0 0 1-.7-.9zM49.3 108.7a.93 .93 0 0 0 .1 1.4 .86 .86 0 0 0 .1-1.4z" fill-rule="evenodd"/>
<path d="M159.2 33.8v.6h.5a.3 .3 0 0 0 .4-.3 .3 .3 0 0 0-.4-.3zM159.2 34.6v.6l.9-.1v-.2l-.1-.3zM159 33.6h.8a.45 .45 0 0 1 .5 .3 .45 .45 0 0 1-.2 .5 .51 .51 0 0 1 .3 .7 .51 .51 0 0 1-.6 .3h-.8zM160.6 34.5a.95 .95 0 0 1 1.9 0 .95 .95 0 0 1-1.9 0zM161 34a.69 .69 0 0 0 0 1 .69 .69 0 0 0 1-.1 .68 .68 0 0 0-.1-.9 .68 .68 0 0 0-.9 0zM162.5 33.6h1.5v.2h-.6v1.6h-.3v-1.6h-.6zM164.1 33.6h1.4v.2h-.6v1.6h-.2v-1.6h-.6zM165.6 34.5a.95 .95 0 0 1 1.9 0 .95 .95 0 0 1-1.9 0zM166.1 34a.69 .69 0 0 0-.1 1 .69 .69 0 0 0 1.1-.1 .68 .68 0 0 0-.1-.9 .68 .68 0 0 0-.9 0zM167.7 33.6h.3l.6 1.5 .5-1.5h.3v1.8h-.2v-1.5l-.5 1.5h-.3l-.5-1.5v1.5h-.2zM169.6 35.6h1.4v.1h-1.4zM171.1 33.6h1.4v.2h-.6v1.6h-.2v-1.6h-.6zM172.8 33.6h1.3v.2h-1.1v.6h1v.2h-1v.6h1.1v.2h-1.3zM174.5 33.6h.3l.5 1.5 .6-1.5h.3v1.8h-.2v-1.5l-.5 1.5h-.3l-.5-1.5v1.5h-.2zM176.6 33.6h.8a.53 .53 0 0 1 .6 .5 .53 .53 0 0 1-.6 .6h-.5v.7h-.3zM176.9 33.8v.7h.4a.32 .32 0 0 0 .4-.4 .32 .32 0 0 0-.4-.3zM178.1 35.6h1.4v.1h-1.4zM179.8 33.7a.72 .72 0 0 1 1.2 .4h-.2a.42 .42 0 0 0-.5-.3 .42 .42 0 0 0-.4 .4 1.47 1.47 0 0 1 1.2 .7 .74 .74 0 0 1-.8 .6 .74 .74 0 0 1-.7-.7h.2a.48 .48 0 0 0 .5 .5 .48 .48 0 0 0 .5-.5l-.4-.2a.56 .56 0 0 1-.6-.2 .56 .56 0 0 1 0-.7zM181.3 34.5a.95 .95 0 0 1 1.9 0 .95 .95 0 0 1-1.9 0zM181.7 34a.69 .69 0 0 0 0 1 .69 .69 0 0 0 1-.1 .68 .68 0 0 0-.1-.9 .68 .68 0 0 0-.9 0zM183.4 33.6h.2v1.6h.9v.2h-1.1zM185.4 33.9l-.3 .8h.6zM185.3 33.6h.3l.6 1.8h-.2l-.2-.5h-.7l-.2 .5h-.3zM186.7 33.8v.6h.6a.31 .31 0 0 0 .4-.3 .31 .31 0 0 0-.4-.3zM186.5 33.6a1.57 1.57 0 0 1 1.3 .2l.1 .4-.2 .3 .2 .2 .1 .7h-.3l-.1-.6-.3-.2h-.6v.8h-.2zM188.1 35.6h1.4v.1h-1.4zM189.7 33.6h.9a.53 .53 0 0 1 .5 .5 .53 .53 0 0 1-.5 .6h-.6v.7h-.3zM190 33.8v.7h.5a.32 .32 0 0 0 .3-.4 .32 .32 0 0 0-.3-.3zM191.9 33.9l-.3 .8h.6zM191.7 33.6h.3l.7 1.8h-.3l-.2-.5h-.7l-.2 .5h-.2zM192.9 33.6h.3l.9 1.5v-1.5h.3v1.8h-.3l-1-1.4v1.4h-.2zM194.8 33.6h1.3v.2h-1.1v.6h1v.2h-1v.6h1.1v.2h-1.3zM196.4 33.6h.3v1.6h.9v.2h-1.2zM197.8 34.6h.6v.2h-.6zM198.8 33.8a.51 .51 0 0 1 .8-.1 .51 .51 0 0 1-.1 .8 .59 .59 0 0 1-.1 1 .59 .59 0 0 1-.8-.6h.2a.36 .36 0 0 0 .5 .4 .36 .36 0 0 0 0-.7h-.3l.1-.2a.29 .29 0 0 0 .4-.2 .29 .29 0 0 0-.3-.3l-.3 .1-.1 .2h-.2z" fill-rule="evenodd"/>
<path d="M32.8 33.8v.6h.4a.3 .3 0 0 0 .4-.3 .3 .3 0 0 0-.4-.3zM32.8 34.6v.6l.8-.1 .1-.2-.2-.3zM32.5 33.6h.8a.45 .45 0 0 1 .5 .3 .45 .45 0 0 1-.2 .5 .51 .51 0 0 1 .3 .7 .51 .51 0 0 1-.6 .3h-.8zM34.1 34.5a.95 .95 0 0 1 1.9 0 .95 .95 0 0 1-1.9 0zM34.6 34a.69 .69 0 0 0-.1 1 .69 .69 0 0 0 1.1-.1 .68 .68 0 0 0-.1-.9 .68 .68 0 0 0-.9 0zM36 33.6h1.5v.2h-.6v1.6h-.2v-1.6h-.7zM37.6 33.6h1.5v.2h-.6v1.6h-.3v-1.6h-.6zM39.2 34.5a.94 .94 0 0 1 1.8 0 .94 .94 0 0 1-1.8 0zM39.6 34a.69 .69 0 0 0 0 1 .69 .69 0 0 0 1-.1 .68 .68 0 0 0-.1-.9 .68 .68 0 0 0-.9 0zM41.2 33.6h.4l.5 1.5 .5-1.5h.4v1.8h-.3v-1.5l-.5 1.5h-.2l-.5-1.5v1.5h-.3zM43.2 35.6h1.4v.1h-1.4zM44.6 33.6h1.5v.2h-.6v1.6h-.3v-1.6h-.6zM46.3 33.6h1.4v.2h-1.1v.6h1v.2h-1v.6h1.1v.2h-1.4zM48 33.6h.4l.5 1.5 .5-1.5h.3v1.8h-.2v-1.5l-.5 1.5h-.2l-.6-1.5v1.5h-.2zM50.1 33.6h.9a.53 .53 0 0 1 .5 .5 .53 .53 0 0 1-.5 .6h-.6v.7h-.3zM50.4 33.8v.7h.5a.32 .32 0 0 0 .4-.4 .32 .32 0 0 0-.4-.3zM51.6 35.6h1.4v.1h-1.4zM53.4 33.7a.72 .72 0 0 1 1.2 .4h-.3a.42 .42 0 0 0-.4-.3 .42 .42 0 0 0-.4 .4 1.47 1.47 0 0 1 1.1 .7 .74 .74 0 0 1-.7 .6 .74 .74 0 0 1-.7-.7h.2a.48 .48 0 0 0 .5 .5 .48 .48 0 0 0 .4-.5l-.3-.2a.56 .56 0 0 1-.7-.2 .56 .56 0 0 1 .1-.7zM54.8 34.5a.95 .95 0 0 1 1.9 0 .95 .95 0 0 1-1.9 0zM55.3 34a.69 .69 0 0 0-.1 1 .69 .69 0 0 0 1.1-.1 .68 .68 0 0 0-.1-.9 .68 .68 0 0 0-.9 0zM56.9 33.6h.2v1.6h1v.2h-1.2zM59 33.9l-.3 .8h.5zM58.8 33.6h.3l.7 1.8h-.3l-.2-.5h-.7l-.2 .5h-.2zM60.3 33.8v.6h.6a.31 .31 0 0 0 .3-.3 .31 .31 0 0 0-.3-.3zM60 33.6a1.57 1.57 0 0 1 1.4 .2l.1 .4-.3 .3 .2 .2 .1 .7h-.3v-.6l-.4-.2h-.5v.8h-.3zM61.6 35.6h1.5v.1h-1.5zM63.3 33.6h.8a.53 .53 0 0 1 .5 .5 .53 .53 0 0 1-.5 .6h-.6v.7h-.2zM63.5 33.8v.7h.5a.32 .32 0 0 0 .4-.4 .32 .32 0 0 0-.4-.3zM65.4 33.9l-.3 .8h.6zM65.3 33.6h.3l.6 1.8h-.2l-.2-.5h-.7l-.2 .5h-.3zM66.5 33.6h.2l1 1.5v-1.5h.2v1.8h-.3l-.9-1.4v1.4h-.2zM68.3 33.6h1.3v.2h-1v.6h1v.2h-1v.6h1.1v.2h-1.4zM70 33.6h.2v1.6h1v.2h-1.2zM71.3 34.6h.6v.2h-.6zM72.3 33.8a.51 .51 0 0 1 .8-.1 .51 .51 0 0 1 0 .8 .59 .59 0 0 1-.2 1 .59 .59 0 0 1-.8-.6h.2a.36 .36 0 0 0 .6 .4 .36 .36 0 0 0 0-.7h-.3v-.2a.29 .29 0 0 0 .4-.2 .29 .29 0 0 0-.3-.3l-.3 .1v.2h-.2z" fill-rule="evenodd"/>
<path d="M138.8 142.5h.2v.6h.6v.2h-.6v.5h-.2v-.5h-.5v-.2h.5zM139.9 142.1a.51 .51 0 0 1 .8 0 .51 .51 0 0 1-.1 .8 .59 .59 0 0 1-.1 1 .59 .59 0 0 1-.8-.6h.2a.36 .36 0 0 0 .5 .3 .36 .36 0 0 0 0-.6h-.2v-.2a.29 .29 0 0 0 .4-.2 .29 .29 0 0 0-.3-.4l-.3 .2v.2h-.3zM141.1 142h.3l.5 1.5 .5-1.5h.3l-.7 1.8h-.2zM143 142.1a.51 .51 0 0 1 .8 0 .51 .51 0 0 1-.1 .8 .59 .59 0 0 1-.1 1 .59 .59 0 0 1-.8-.6h.2a.36 .36 0 0 0 .5 .3 .36 .36 0 0 0 .1-.6h-.3v-.2a.29 .29 0 0 0 .4-.2 .29 .29 0 0 0-.3-.4l-.3 .2v.2h-.3z" fill-rule="evenodd"/>
<path d="M9.8 111.6h.2v.5h.5v.2h-.5v.5h-.2v-.5h-.6v-.2h.6zM10.9 111.2a.51 .51 0 0 1 .7 0 .51 .51 0 0 1 0 .7 .59 .59 0 0 1-.1 1 .59 .59 0 0 1-.8-.6h.2a.36 .36 0 0 0 .5 .4 .36 .36 0 0 0 0-.7h-.3l.1-.2a.29 .29 0 0 0 .4-.2 .29 .29 0 0 0-.3-.3l-.3 .1-.1 .3h-.2zM12.1 111h.2l.6 1.6 .5-1.6h.3l-.7 1.8h-.3zM14 111.2a.51 .51 0 0 1 .8 0 .51 .51 0 0 1-.1 .7 .59 .59 0 0 1-.1 1 .59 .59 0 0 1-.8-.6h.2a.36 .36 0 0 0 .5 .4 .36 .36 0 0 0 0-.7h-.3l.1-.2a.29 .29 0 0 0 .4-.2 .29 .29 0 0 0-.3-.3l-.3 .1-.1 .3h-.2z" fill-rule="evenodd"/>
<path d="M9.8 90.9h.2v.6h.5v.2h-.5v.5h-.2v-.5h-.6v-.2h.6zM10.9 90.5a.51 .51 0 0 1 .7 0 .51 .51 0 0 1 0 .8 .59 .59 0 0 1-.1 1 .59 .59 0 0 1-.8-.6h.2a.36 .36 0 0 0 .5 .3 .36 .36 0 0 0 0-.6h-.3l.1-.2a.29 .29 0 0 0 .4-.2 .29 .29 0 0 0-.3-.4l-.3 .2-.1 .2h-.2zM12.1 90.4h.2l.6 1.5 .5-1.5h.3l-.7 1.8h-.3zM14 90.5a.51 .51 0 0 1 .8 0 .51 .51 0 0 1-.1 .8 .59 .59 0 0 1-.1 1 .59 .59 0 0 1-.8-.6h.2a.36 .36 0 0 0 .5 .3 .36 .36 0 0 0 0-.6h-.3l.1-.2a.29 .29 0 0 0 .4-.2 .29 .29 0 0 0-.3-.4l-.3 .2-.1 .2h-.2z" fill-rule="evenodd"/>
<path d="M102.7 26.4h.2v.5h.5v.2h-.5v.6h-.2v-.6h-.6v-.2h.6zM103.8 26a.51 .51 0 0 1 .8 0 .51 .51 0 0 1-.1 .7 .59 .59 0 0 1-.1 1 .59 .59 0 0 1-.8-.6h.2a.36 .36 0 0 0 .5 .4 .36 .36 0 0 0 0-.6h-.3l.1-.2a.29 .29 0 0 0 .4-.2 .29 .29 0 0 0-.3-.4l-.3 .2-.1 .2h-.2zM105 25.9h.3l.5 1.5 .5-1.5h.3l-.7 1.8h-.3zM106.9 26a.51 .51 0 0 1 .8 0 .51 .51 0 0 1-.1 .7 .59 .59 0 0 1-.1 1 .59 .59 0 0 1-.8-.6h.2a.36 .36 0 0 0 .5 .4 .36 .36 0 0 0 0-.6h-.2v-.2a.29 .29 0 0 0 .4-.2 .29 .29 0 0 0-.3-.4l-.3 .2-.1 .2h-.2z" fill-rule="evenodd"/>
<path d="M233.9 131.7h.8a.53 .53 0 0 1 .5 .5 .53 .53 0 0 1-.5 .5h-.6v.8h-.2zM234.1 131.9v.6h.5a.32 .32 0 0 0 .4-.3 .32 .32 0 0 0-.4-.3zM235.4 132.6a.95 .95 0 0 1 1.9 0 .95 .95 0 0 1-1.9 0zM235.9 132a.69 .69 0 0 0-.1 1.1 .69 .69 0 0 0 1.1-.2 .68 .68 0 0 0-.1-.9 .68 .68 0 0 0-.9 0zM237.4 131.7h.2l.4 1.5 .4-1.5h.2l.5 1.5 .3-1.5h.3l-.5 1.8h-.3l-.4-1.5-.4 1.5h-.3zM239.7 133.7h1.4v.1h-1.4zM241.4 131.7h.9v.3h-.7l-.1 .5a.62 .62 0 0 1 .9 .2 .62 .62 0 0 1-.4 .9 .62 .62 0 0 1-.8-.6h.2a.39 .39 0 0 0 .6 .2 .39 .39 0 0 0 .1-.6 .39 .39 0 0 0-.6 .1h-.2zM242.6 131.7h.3l.5 1.5 .5-1.5h.3l-.7 1.8h-.2z" fill-rule="evenodd"/>
<path d="M233.9 129.1h.8a.53 .53 0 0 1 .5 .5 .53 .53 0 0 1-.5 .5h-.6v.8h-.2zM234.1 129.3v.6h.5a.32 .32 0 0 0 .4-.3 .32 .32 0 0 0-.4-.3zM235.4 130a.95 .95 0 0 1 1.9 0 .95 .95 0 0 1-1.9 0zM235.9 129.5a.69 .69 0 0 0-.1 1 .69 .69 0 0 0 1.1-.2 .68 .68 0 0 0-.1-.9 .68 .68 0 0 0-.9 .1zM237.4 129.1h.2l.4 1.5 .4-1.5h.2l.5 1.5 .3-1.5h.3l-.5 1.8h-.3l-.4-1.5-.4 1.5h-.3zM239.7 131.1h1.4v.1h-1.4zM241.4 129.2h.9v.2h-.7l-.1 .5a.62 .62 0 0 1 .9 .3 .62 .62 0 0 1-.4 .8 .62 .62 0 0 1-.8-.5h.2a.39 .39 0 0 0 .6 .1 .39 .39 0 0 0 .1-.6 .39 .39 0 0 0-.6 .1h-.2zM242.6 129.1h.3l.5 1.5 .5-1.5h.3l-.7 1.8h-.2z" fill-rule="evenodd"/>
<path d="M102.2 28.4h.9a.53 .53 0 0 1 .5 .6 .53 .53 0 0 1-.5 .5h-.6v.8h-.3zM102.5 28.7v.6h.5a.32 .32 0 0 0 .3-.3 .32 .32 0 0 0-.3-.3zM103.8 29.4a.95 .95 0 0 1 1.9 0 .95 .95 0 0 1-1.9 0zM104.2 28.8a.69 .69 0 0 0 0 1.1 .69 .69 0 0 0 1.1-.2 .68 .68 0 0 0-.1-.9 .68 .68 0 0 0-1 0zM105.7 28.4h.3l.3 1.5 .5-1.5h.2l.4 1.5 .4-1.5h.2l-.4 1.9h-.3l-.4-1.5-.4 1.5h-.3zM108.1 30.5h1.4v.1h-1.4zM109.8 28.5h.9v.2h-.8v.5a.62 .62 0 0 1 .9 .3 .62 .62 0 0 1-.5 .9 .62 .62 0 0 1-.7-.6h.2a.39 .39 0 0 0 .6 .2 .39 .39 0 0 0 0-.6 .39 .39 0 0 0-.6 .1h-.2zM111 28.4h.2l.6 1.6 .5-1.6h.3l-.7 1.9h-.3z" fill-rule="evenodd"/>
<path d="M159 74.9h.8a.53 .53 0 0 1 .6 .5 .53 .53 0 0 1-.6 .5h-.5v.8h-.3zM159.3 75.1v.6h.4a.32 .32 0 0 0 .4-.3 .32 .32 0 0 0-.4-.3zM160.6 75.8a.95 .95 0 0 1 1.9 0 .95 .95 0 0 1-1.9 0zM161 75.3a.69 .69 0 0 0 0 1 .69 .69 0 0 0 1-.1 .68 .68 0 0 0-.1-.9 .68 .68 0 0 0-.9 0zM162.5 74.9h.3l.3 1.5 .4-1.5h.3l.4 1.5 .4-1.5h.2l-.5 1.8h-.2l-.4-1.5-.5 1.5h-.2zM164.9 76.9h1.4v.1h-1.4zM166.6 75h.9v.2h-.8l-.1 .5a.62 .62 0 0 1 .9 .3 .62 .62 0 0 1-.4 .8 .62 .62 0 0 1-.7-.5h.2a.39 .39 0 0 0 .6 .2 .39 .39 0 0 0 0-.7 .39 .39 0 0 0-.6 .1h-.2zM167.7 74.9h.3l.5 1.5 .6-1.5h.2l-.6 1.8h-.3z" fill-rule="evenodd"/>
<path d="M226.1 74.9h.8a.53 .53 0 0 1 .6 .5 .53 .53 0 0 1-.6 .5h-.5v.8h-.3zM226.4 75.1v.6h.4a.32 .32 0 0 0 .4-.3 .32 .32 0 0 0-.4-.3zM227.7 75.8a.95 .95 0 0 1 1.9 0 .95 .95 0 0 1-1.9 0zM228.1 75.3a.69 .69 0 0 0 0 1 .69 .69 0 0 0 1-.1 .68 .68 0 0 0-.1-.9 .68 .68 0 0 0-.9 0zM229.6 74.9h.3l.3 1.5 .4-1.5h.3l.4 1.5 .4-1.5h.2l-.5 1.8h-.2l-.4-1.5-.5 1.5h-.2zM232 76.9h1.4v.1h-1.4zM233.7 75h.9v.2h-.8l-.1 .5a.62 .62 0 0 1 .9 .3 .62 .62 0 0 1-.4 .8 .62 .62 0 0 1-.7-.5h.2a.39 .39 0 0 0 .6 .2 .39 .39 0 0 0 0-.7 .39 .39 0 0 0-.6 .1h-.2zM234.8 74.9h.3l.5 1.5 .6-1.5h.2l-.6 1.8h-.3z" fill-rule="evenodd"/>
<path d="M159 43.9h.3l.9 1.5v-1.5h.2v1.9h-.2l-1-1.5v1.5h-.2zM161.4 45v.6a.33 .33 0 0 0 .3-.3 .33 .33 0 0 0-.3-.3zM161 44.2v.3l.3 .2v-.6zM160.9 44.1l.4-.2v-.1l.1 .1a.49 .49 0 0 1 .5 .5h-.2l-.3-.3v.6a.53 .53 0 0 1 .5 .6 .53 .53 0 0 1-.5 .5v.2h-.1v-.2l-.4-.1-.2-.3v-.2h.2l.1 .3 .3 .1v-.7a.49 .49 0 0 1-.5-.2 .49 .49 0 0 1 .1-.6zM162.4 44.5a.3 .3 0 0 0 .6 0 .3 .3 0 0 0-.6 0zM162.4 45.3a.36 .36 0 0 0 .7 0 .36 .36 0 0 0-.7 0zM162.3 44.1a.5 .5 0 0 1 .8-.1 .5 .5 0 0 1 0 .8 .55 .55 0 0 1 .1 .8 .55 .55 0 0 1-.9 0 .55 .55 0 0 1 .1-.8l-.2-.3zM163.7 44.2a.69 .69 0 0 1 .9 0 .69 .69 0 0 1 .1 .8 .6 .6 0 0 1-.4 .8 .6 .6 0 0 1-.7-.5h.2a.35 .35 0 0 0 .4 .3 .35 .35 0 0 0 .3-.4v-.3a.57 .57 0 0 1-.8 .1 .57 .57 0 0 1 0-.8zM163.8 44.6a.38 .38 0 0 0 .7 0 .38 .38 0 0 0-.7 0zM165.1 45.5h.2v.3h-.2z" fill-rule="evenodd"/>
<path d="M226.4 23.4a.96 .96 0 0 1 1.2 .2 .96 .96 0 0 1-.1 1.3l.3 .2-.2 .2-.3-.3a.96 .96 0 0 1-1.2-.3 .96 .96 0 0 1 .3-1.3zM226.4 23.6a.74 .74 0 0 0-.1 1 .74 .74 0 0 0 .9 .3l-.2-.2 .1-.1 .2 .2a.72 .72 0 0 0 .1-1 .72 .72 0 0 0-1-.2zM228.2 23.5l.6-.2 .3 .3v.2h-.2a.37 .37 0 0 0-.4-.3 .37 .37 0 0 0-.3 .5v.2a.59 .59 0 0 1 .9 .2 .59 .59 0 0 1-.4 .8 .59 .59 0 0 1-.7-.6v-.7zM228.2 24.6a.4 .4 0 0 0 .8 0 .4 .4 0 0 0-.8 0zM229.3 25.3h1.4v.1h-1.4zM231 23.4a.72 .72 0 0 1 1.2 .4h-.2a.42 .42 0 0 0-.5-.3 .42 .42 0 0 0-.4 .4 1.47 1.47 0 0 1 1.2 .7 .74 .74 0 0 1-.8 .6 .74 .74 0 0 1-.7-.7h.2a.48 .48 0 0 0 .5 .5 .48 .48 0 0 0 .5-.5l-.4-.2a.56 .56 0 0 1-.6-.2 .56 .56 0 0 1 0-.7zM232.6 23.3h.8a.53 .53 0 0 1 .6 .5 .53 .53 0 0 1-.6 .5h-.5v.8h-.3zM232.9 23.5v.6h.4a.32 .32 0 0 0 .4-.3 .32 .32 0 0 0-.4-.3zM234.3 23.3h.3v1.8h-.3zM234.8 25.3h1.4v.1h-1.4zM236.6 23.4a.72 .72 0 0 1 1.1 .4h-.2a.42 .42 0 0 0-.5-.3 .42 .42 0 0 0-.4 .4 1.47 1.47 0 0 1 1.2 .7 .74 .74 0 0 1-.8 .6 .74 .74 0 0 1-.7-.7h.3a.48 .48 0 0 0 .4 .5 .48 .48 0 0 0 .5-.5l-.4-.2a.56 .56 0 0 1-.6-.2 .56 .56 0 0 1 .1-.7zM238.2 23.5a.79 .79 0 0 1 .8-.3 .79 .79 0 0 1 .6 .6h-.2a.62 .62 0 0 0-.9-.3 .62 .62 0 0 0-.2 .9 .56 .56 0 0 0 .5 .5 .56 .56 0 0 0 .6-.5h.2a.85 .85 0 0 1-1.1 .7 .85 .85 0 0 1-.5-1.2zM239.9 23.3h.3v1.6h.9v.2h-1.2zM241.3 23.3h.3v.9l.9-.9h.3l-.8 .7 .8 1.1h-.3l-.6-.9-.3 .3v.6h-.3z" fill-rule="evenodd"/>
<path d="M226.4 28.5a.96 .96 0 0 1 1.2 .3 .96 .96 0 0 1-.1 1.3l.3 .2-.2 .1-.3-.2a.96 .96 0 0 1-1.2-.3 .96 .96 0 0 1 .3-1.4zM226.4 28.8a.74 .74 0 0 0-.1 .9 .74 .74 0 0 0 .9 .3l-.2-.1 .1-.2 .2 .2a.72 .72 0 0 0 .1-1 .72 .72 0 0 0-1-.1zM228.2 28.7l.6-.2 .3 .3v.2h-.2a.37 .37 0 0 0-.4-.3 .37 .37 0 0 0-.3 .5v.1a.59 .59 0 0 1 .9 .3 .59 .59 0 0 1-.4 .8 .59 .59 0 0 1-.7-.6v-.7zM228.2 29.7a.4 .4 0 0 0 .8 0 .4 .4 0 0 0-.8 0zM229.3 30.5h1.4v.1h-1.4zM231 28.6a.72 .72 0 0 1 1.2 .4h-.2a.42 .42 0 0 0-.5-.4 .42 .42 0 0 0-.4 .4 1.47 1.47 0 0 1 1.2 .8 .74 .74 0 0 1-.8 .5 .74 .74 0 0 1-.7-.6h.2a.48 .48 0 0 0 .5 .4 .48 .48 0 0 0 .5-.4l-.4-.2a.56 .56 0 0 1-.6-.2 .56 .56 0 0 1 0-.7zM232.6 28.4h.8a.53 .53 0 0 1 .6 .6 .53 .53 0 0 1-.6 .5h-.5v.8h-.3zM232.9 28.7v.6h.4a.32 .32 0 0 0 .4-.3 .32 .32 0 0 0-.4-.3zM234.3 28.4h.3v1.9h-.3zM234.8 30.5h1.4v.1h-1.4zM236.6 28.6a.72 .72 0 0 1 1.1 .4h-.2a.42 .42 0 0 0-.5-.4 .42 .42 0 0 0-.4 .4 1.47 1.47 0 0 1 1.2 .8 .74 .74 0 0 1-.8 .5 .74 .74 0 0 1-.7-.6h.3a.48 .48 0 0 0 .4 .4 .48 .48 0 0 0 .5-.4l-.4-.2a.56 .56 0 0 1-.6-.2 .56 .56 0 0 1 .1-.7zM238.3 28.7v1.4h.5a.71 .71 0 0 0 .6-.7 .71 .71 0 0 0-.6-.7zM238.1 28.4h.7a.92 .92 0 0 1 .8 1 .92 .92 0 0 1-.8 .9h-.7zM240 28.4h.2v1.9h-.2zM240.4 30.5h1.4v.1h-1.4zM242 28.4h.4l.5 1.6 .5-1.6h.4v1.9h-.3v-1.6l-.5 1.6h-.2l-.5-1.6v1.6h-.3zM244.2 28.4h.3v1.9h-.3zM245 28.6a.72 .72 0 0 1 1.2 .4h-.2a.42 .42 0 0 0-.5-.4 .42 .42 0 0 0-.4 .4 1.47 1.47 0 0 1 1.1 .8 .74 .74 0 0 1-.7 .5 .74 .74 0 0 1-.7-.6h.2a.48 .48 0 0 0 .5 .4 .48 .48 0 0 0 .5-.4l-.4-.2a.56 .56 0 0 1-.7-.2 .56 .56 0 0 1 .1-.7zM246.4 29.4a.95 .95 0 0 1 1.9 0 .95 .95 0 0 1-1.9 0zM246.9 28.8a.69 .69 0 0 0 0 1.1 .69 .69 0 0 0 1-.2 .68 .68 0 0 0-.1-.9 .68 .68 0 0 0-.9 0z" fill-rule="evenodd"/>
<path d="M174.7 152.4a.96 .96 0 0 1 1.3 .3 .96 .96 0 0 1-.1 1.2l.2 .2-.1 .2-.3-.2a.96 .96 0 0 1-1.3-.4 .96 .96 0 0 1 .3-1.3zM174.8 152.7a.74 .74 0 0 0-.1 .9 .74 .74 0 0 0 .8 .3l-.2-.1 .2-.2 .2 .2a.72 .72 0 0 0 .1-1 .72 .72 0 0 0-1-.1zM176.6 152.5l.6-.1 .3 .3v.1h-.2a.37 .37 0 0 0-.4-.2 .37 .37 0 0 0-.3 .4v.2a.59 .59 0 0 1 .9 .2 .59 .59 0 0 1-.4 .9 .59 .59 0 0 1-.7-.7v-.6zM176.6 153.6a.4 .4 0 0 0 .8 0 .4 .4 0 0 0-.8 0zM177.7 154.3h1.4v.2h-1.4zM179.9 152.6l-.3 .8h.6zM179.8 152.3h.3l.6 1.8h-.2l-.2-.5h-.7l-.2 .5h-.3zM181 152.3h.3v1.8h-.3zM181.7 152.3h.3l.9 1.5v-1.5h.2v1.8h-.3l-.9-1.4v1.4h-.2zM183.3 154.3h1.4v.2h-1.4zM185 152.7l.6-.3v1.7h-.2v-1.2h-.4z" fill-rule="evenodd"/>
<path d="M174.7 147.3a.96 .96 0 0 1 1.3 .2 .96 .96 0 0 1-.1 1.3l.2 .2-.1 .1-.3-.2a.96 .96 0 0 1-1.3-.3 .96 .96 0 0 1 .3-1.3zM174.8 147.5a.74 .74 0 0 0-.1 .9 .74 .74 0 0 0 .8 .4l-.2-.2 .2-.2 .2 .2a.72 .72 0 0 0 .1-1 .72 .72 0 0 0-1-.1zM176.6 147.4l.6-.2 .3 .3v.2h-.2a.37 .37 0 0 0-.4-.3 .37 .37 0 0 0-.3 .5v.2a.59 .59 0 0 1 .9 .2 .59 .59 0 0 1-.4 .8 .59 .59 0 0 1-.7-.6v-.7zM176.6 148.4a.4 .4 0 0 0 .8 0 .4 .4 0 0 0-.8 0zM177.7 149.2h1.4v.1h-1.4zM179.9 147.4l-.3 .8h.6zM179.8 147.2h.3l.6 1.8h-.2l-.2-.6h-.7l-.2 .6h-.3zM181 147.2h.3v1.8h-.3zM181.7 147.2h.3l.9 1.4v-1.4h.2v1.8h-.3l-.9-1.5v1.5h-.2zM183.3 149.2h1.4v.1h-1.4zM185 147.4a.64 .64 0 0 1 .8-.1 .64 .64 0 0 1 .2 .8 .66 .66 0 0 1-.6 .9 .66 .66 0 0 1-.6-.9zM185.3 147.4a.93 .93 0 0 0 .1 1.4 .86 .86 0 0 0 0-1.4z" fill-rule="evenodd"/>
<path d="M102.5 69.8a.96 .96 0 0 1 1.2 .3 .96 .96 0 0 1-.1 1.3l.3 .2-.1 .1-.3-.2a.96 .96 0 0 1-1.3-.4 .96 .96 0 0 1 .3-1.3zM102.5 70.1a.74 .74 0 0 0-.1 .9 .74 .74 0 0 0 .9 .3l-.2-.1 .1-.2 .2 .2a.72 .72 0 0 0 .1-1 .72 .72 0 0 0-1-.1zM104.3 70l.6-.2 .3 .3 .1 .1h-.3a.37 .37 0 0 0-.4-.2 .37 .37 0 0 0-.3 .4v.2a.59 .59 0 0 1 .9 .2 .59 .59 0 0 1-.4 .9 .59 .59 0 0 1-.7-.7v-.6zM104.3 71a.4 .4 0 0 0 .8 0 .4 .4 0 0 0-.8 0zM105.4 71.7h1.4v.2h-1.4zM107.7 70l-.3 .8h.5zM107.5 69.7h.3l.7 1.9h-.3l-.2-.6h-.7l-.2 .6h-.2zM108.8 69.7h.2v1.9h-.2zM109.4 69.7h.3l.9 1.5v-1.5h.3v1.9h-.3l-1-1.5v1.5h-.2zM111.1 71.7h1.4v.2h-1.4zM112.7 70a.64 .64 0 0 1 .8-.1 .64 .64 0 0 1 .3 .8 .66 .66 0 0 1-.6 .9 .66 .66 0 0 1-.7-.9zM113 70a.93 .93 0 0 0 .1 1.4 .86 .86 0 0 0 .1-1.4z" fill-rule="evenodd"/>
<path d="M174.7 157.6a.96 .96 0 0 1 1.3 .2 .96 .96 0 0 1-.1 1.3l.2 .2-.1 .1-.3-.2a.96 .96 0 0 1-1.3-.3 .96 .96 0 0 1 .3-1.3zM174.8 157.8a.74 .74 0 0 0-.1 1 .74 .74 0 0 0 .8 .3l-.2-.2 .2-.1 .2 .2a.72 .72 0 0 0 .1-1 .72 .72 0 0 0-1-.2zM176.6 157.7l.6-.2 .3 .3v.2h-.2a.37 .37 0 0 0-.4-.3 .37 .37 0 0 0-.3 .5v.2a.59 .59 0 0 1 .9 .2 .59 .59 0 0 1-.4 .8 .59 .59 0 0 1-.7-.6v-.7zM176.6 158.7a.4 .4 0 0 0 .8 0 .4 .4 0 0 0-.8 0zM177.7 159.5h1.4v.1h-1.4zM179.9 157.7l-.3 .9h.6zM179.8 157.5h.3l.6 1.8h-.2l-.2-.5h-.7l-.2 .5h-.3zM180.9 158.4a.94 .94 0 0 1 1.8 0 .94 .94 0 0 1-1.8 0zM181.3 157.8a.69 .69 0 0 0 0 1.1 .69 .69 0 0 0 1-.2 .68 .68 0 0 0-.1-.9 .68 .68 0 0 0-.9 0zM183 157.5h.2v1.1a.47 .47 0 0 0 .5 .5 .47 .47 0 0 0 .4-.5v-1.1h.3v1a.73 .73 0 0 1-.7 .8 .73 .73 0 0 1-.7-.8zM184.6 157.5h1.5v.2h-.6v1.6h-.3v-1.6h-.6zM186.1 159.5h1.4v.1h-1.4zM187.8 157.7a.64 .64 0 0 1 .8 0 .64 .64 0 0 1 .3 .7 .66 .66 0 0 1-.6 .9 .66 .66 0 0 1-.7-.9zM188.1 157.8a.93 .93 0 0 0 .1 1.3 .86 .86 0 0 0 0-1.4z" fill-rule="evenodd"/>
<path d="M102.5 72.4a.96 .96 0 0 1 1.2 .3 .96 .96 0 0 1-.1 1.2l.3 .2-.1 .2-.3-.2a.96 .96 0 0 1-1.3-.4 .96 .96 0 0 1 .3-1.3zM102.5 72.7a.74 .74 0 0 0-.1 .9 .74 .74 0 0 0 .9 .3l-.2-.1 .1-.2 .2 .2a.72 .72 0 0 0 .1-1 .72 .72 0 0 0-1-.1zM104.3 72.6l.6-.2 .3 .3 .1 .1h-.3a.37 .37 0 0 0-.4-.2 .37 .37 0 0 0-.3 .4v.2a.59 .59 0 0 1 .9 .2 .59 .59 0 0 1-.4 .9 .59 .59 0 0 1-.7-.7v-.6zM104.3 73.6a.4 .4 0 0 0 .8 0 .4 .4 0 0 0-.8 0zM105.4 74.3h1.4v.2h-1.4zM107.7 72.6l-.3 .8h.5zM107.5 72.3h.3l.7 1.8h-.3l-.2-.5h-.7l-.2 .5h-.2zM108.6 73.2a.95 .95 0 0 1 1.9 0 .95 .95 0 0 1-1.9 0zM109 72.7a.69 .69 0 0 0 0 1.1 .69 .69 0 0 0 1.1-.2 .68 .68 0 0 0-.1-.9 .68 .68 0 0 0-1 0zM110.7 72.3h.2v1.1a.47 .47 0 0 0 .5 .6 .47 .47 0 0 0 .5-.6v-1.1h.2v1a.73 .73 0 0 1-.7 .9 .73 .73 0 0 1-.7-.9zM112.4 72.3h1.4v.2h-.6v1.6h-.2v-1.6h-.6zM113.9 74.3h1.4v.2h-1.4zM115.6 72.5a.64 .64 0 0 1 .8 0 .64 .64 0 0 1 .2 .7 .66 .66 0 0 1-.6 1 .66 .66 0 0 1-.6-.9zM115.8 72.6a.93 .93 0 0 0 .2 1.4 .86 .86 0 0 0 0-1.4z" fill-rule="evenodd"/>
<path d="M174.7 162.7a.96 .96 0 0 1 1.3 .3 .96 .96 0 0 1-.1 1.3l.2 .2-.1 .1-.3-.2a.96 .96 0 0 1-1.3-.4 .96 .96 0 0 1 .3-1.3zM174.8 163a.74 .74 0 0 0-.1 .9 .74 .74 0 0 0 .8 .3l-.2-.1 .2-.2 .2 .2a.72 .72 0 0 0 .1-1 .72 .72 0 0 0-1-.1zM176.6 162.9l.6-.2 .3 .3v.1h-.2a.37 .37 0 0 0-.4-.2 .37 .37 0 0 0-.3 .4v.2a.59 .59 0 0 1 .9 .2 .59 .59 0 0 1-.4 .9 .59 .59 0 0 1-.7-.7v-.6zM176.6 163.9a.4 .4 0 0 0 .8 0 .4 .4 0 0 0-.8 0zM177.7 164.7h1.4v.1h-1.4zM179.9 162.9l-.3 .8h.6zM179.8 162.6h.3l.6 1.9h-.2l-.2-.6h-.7l-.2 .6h-.3zM180.9 163.6a.94 .94 0 0 1 1.8 0 .94 .94 0 0 1-1.8 0zM181.3 163a.69 .69 0 0 0 0 1.1 .69 .69 0 0 0 1-.2 .68 .68 0 0 0-.1-.9 .68 .68 0 0 0-.9 0zM183 162.6h.2v1.2a.47 .47 0 0 0 .5 .5 .47 .47 0 0 0 .4-.5v-1.2h.3v1.1a.73 .73 0 0 1-.7 .8 .73 .73 0 0 1-.7-.8zM184.6 162.6h1.5v.3h-.6v1.6h-.3v-1.6h-.6zM186.1 164.7h1.4v.1h-1.4zM187.8 163l.6-.3v1.8h-.2v-1.3h-.4z" fill-rule="evenodd"/>
<path d="M159 49.1h.3l.9 1.5v-1.5h.2v1.8h-.2l-1-1.5v1.5h-.2zM161.4 50.1v.7a.33 .33 0 0 0 .3-.3 .33 .33 0 0 0-.3-.4zM161 49.4v.3l.3 .2v-.6zM160.9 49.3l.4-.2v-.2l.1 .2a.49 .49 0 0 1 .5 .5h-.2l-.3-.3v.6a.53 .53 0 0 1 .5 .5 .53 .53 0 0 1-.5 .6v.2h-.1v-.2l-.4-.2-.2-.2v-.2h.2l.1 .2 .3 .2v-.7a.49 .49 0 0 1-.5-.3 .49 .49 0 0 1 .1-.5zM162.3 49.3a.69 .69 0 0 1 .9 0 .69 .69 0 0 1 .1 .9 .6 .6 0 0 1-.4 .7 .6 .6 0 0 1-.7-.4h.2a.35 .35 0 0 0 .4 .3 .35 .35 0 0 0 .3-.5v-.2a.57 .57 0 0 1-.8 .1 .57 .57 0 0 1 0-.9zM162.4 49.7a.38 .38 0 0 0 .7 0 .38 .38 0 0 0-.7 0zM163.7 49.5l.7-.4v1.8h-.3v-1.2h-.4z" fill-rule="evenodd"/>
<path d="M159 51.7h.8a.53 .53 0 0 1 .6 .5 .53 .53 0 0 1-.6 .5h-.5v.8h-.3zM159.3 51.9v.6h.4a.32 .32 0 0 0 .4-.3 .32 .32 0 0 0-.4-.3zM160.6 52.6a.95 .95 0 0 1 1.9 0 .95 .95 0 0 1-1.9 0zM161 52a.69 .69 0 0 0 0 1.1 .69 .69 0 0 0 1-.2 .68 .68 0 0 0-.1-.9 .68 .68 0 0 0-.9 0zM162.5 51.7h.3l.3 1.5 .4-1.5h.3l.4 1.5 .4-1.5h.2l-.5 1.8h-.2l-.4-1.5-.5 1.5h-.2zM164.9 53.7h1.4v.1h-1.4zM166.7 51.9v.6h.6a.31 .31 0 0 0 .4-.3 .31 .31 0 0 0-.4-.3zM166.5 51.7a1.57 1.57 0 0 1 1.3 .1l.1 .5-.2 .3 .2 .2 .1 .7h-.3l-.1-.7-.3-.1h-.6v.8h-.2zM169 51.9l-.3 .8h.5zM168.8 51.7h.3l.7 1.8h-.3l-.2-.6h-.7l-.2 .6h-.3zM170.3 51.9v1.4h.4a.71 .71 0 0 0 .6-.7 .71 .71 0 0 0-.6-.7zM170 51.7h.7a.92 .92 0 0 1 .8 .9 .92 .92 0 0 1-.8 .9h-.7zM171.9 51.7h.2v1.8h-.2zM172.4 52.6a.95 .95 0 0 1 1.9 0 .95 .95 0 0 1-1.9 0zM172.9 52a.69 .69 0 0 0-.1 1.1 .69 .69 0 0 0 1.1-.2 .68 .68 0 0 0-.1-.9 .68 .68 0 0 0-.9 0zM174.3 53.7h1.4v.1h-1.4zM176 51.8a.51 .51 0 0 1 .8 0 .51 .51 0 0 1-.1 .8 .59 .59 0 0 1-.1 1 .59 .59 0 0 1-.8-.7h.2a.36 .36 0 0 0 .5 .4 .36 .36 0 0 0 0-.6h-.2v-.2a.29 .29 0 0 0 .4-.2 .29 .29 0 0 0-.3-.4l-.3 .2v.2h-.3zM177.4 53.2h.2v.3h-.2zM178.1 51.8a.51 .51 0 0 1 .8 0 .51 .51 0 0 1 0 .8 .59 .59 0 0 1-.2 1 .59 .59 0 0 1-.8-.7h.2a.36 .36 0 0 0 .6 .4 .36 .36 0 0 0 0-.6h-.3v-.2a.29 .29 0 0 0 .4-.2 .29 .29 0 0 0-.3-.4l-.3 .2v.2h-.2zM179.3 51.7h.3l.5 1.5 .5-1.5h.3l-.7 1.8h-.2z" fill-rule="evenodd"/>
<path d="M233.9 116.2h.8a.53 .53 0 0 1 .5 .5 .53 .53 0 0 1-.5 .5h-.6v.8h-.2zM234.1 116.4v.6h.5a.32 .32 0 0 0 .4-.3 .32 .32 0 0 0-.4-.3zM235.4 117.1a.95 .95 0 0 1 1.9 0 .95 .95 0 0 1-1.9 0zM235.9 116.5a.69 .69 0 0 0-.1 1.1 .69 .69 0 0 0 1.1-.2 .68 .68 0 0 0-.1-.9 .68 .68 0 0 0-.9 0zM237.4 116.2h.2l.4 1.5 .4-1.5h.2l.5 1.5 .3-1.5h.3l-.5 1.8h-.3l-.4-1.5-.4 1.5h-.3zM239.7 118.2h1.4v.1h-1.4zM241.6 116.4v.6h.6a.31 .31 0 0 0 .3-.3 .31 .31 0 0 0-.3-.3zM241.3 116.2a1.57 1.57 0 0 1 1.4 .1l.1 .5-.3 .3 .2 .2 .2 .7h-.4v-.6l-.4-.2h-.5v.8h-.3zM243.8 116.5l-.3 .8h.6zM243.7 116.2h.3l.6 1.8h-.3l-.1-.5h-.8l-.2 .5h-.2zM245.1 116.4v1.4h.4a.71 .71 0 0 0 .6-.7 .71 .71 0 0 0-.6-.7zM244.8 116.2h.8a.92 .92 0 0 1 .8 .9 .92 .92 0 0 1-.8 .9h-.8zM246.7 116.2h.3v1.8h-.3zM247.3 117.1a.95 .95 0 0 1 1.9 0 .95 .95 0 0 1-1.9 0zM247.7 116.5a.69 .69 0 0 0 0 1.1 .69 .69 0 0 0 1-.2 .68 .68 0 0 0-.1-.9 .68 .68 0 0 0-.9 0zM249.2 118.2h1.4v.1h-1.4zM250.9 116.3a.51 .51 0 0 1 .7 0 .51 .51 0 0 1 0 .8 .59 .59 0 0 1-.2 1 .59 .59 0 0 1-.8-.6h.3a.36 .36 0 0 0 .5 .3 .36 .36 0 0 0 0-.6h-.3v-.2a.29 .29 0 0 0 .4-.2 .29 .29 0 0 0-.2-.4l-.4 .2v.2h-.2zM252.2 117.7h.3v.3h-.3zM253 116.3a.51 .51 0 0 1 .7 0 .51 .51 0 0 1 0 .8 .59 .59 0 0 1-.1 1 .59 .59 0 0 1-.9-.6h.3a.36 .36 0 0 0 .5 .3 .36 .36 0 0 0 0-.6h-.3l.1-.2a.29 .29 0 0 0 .4-.2 .29 .29 0 0 0-.3-.4l-.3 .2-.1 .2h-.2zM254.2 116.2h.2l.6 1.5 .5-1.5h.3l-.7 1.8h-.3z" fill-rule="evenodd"/>
<path d="M226.1 51.7h.8a.53 .53 0 0 1 .6 .5 .53 .53 0 0 1-.6 .5h-.5v.8h-.3zM226.4 51.9v.6h.4a.32 .32 0 0 0 .4-.3 .32 .32 0 0 0-.4-.3zM227.7 52.6a.95 .95 0 0 1 1.9 0 .95 .95 0 0 1-1.9 0zM228.1 52a.69 .69 0 0 0 0 1.1 .69 .69 0 0 0 1-.2 .68 .68 0 0 0-.1-.9 .68 .68 0 0 0-.9 0zM229.6 51.7h.3l.3 1.5 .4-1.5h.3l.4 1.5 .4-1.5h.2l-.5 1.8h-.2l-.4-1.5-.5 1.5h-.2zM232 53.7h1.4v.1h-1.4zM233.8 51.9v.6h.6a.31 .31 0 0 0 .4-.3 .31 .31 0 0 0-.4-.3zM233.6 51.7a1.57 1.57 0 0 1 1.3 .1l.1 .5-.2 .3 .2 .2 .1 .7h-.3l-.1-.7-.3-.1h-.6v.8h-.2zM236.1 51.9l-.3 .8h.5zM235.9 51.7h.3l.7 1.8h-.3l-.2-.6h-.7l-.2 .6h-.3zM237.4 51.9v1.4h.4a.71 .71 0 0 0 .6-.7 .71 .71 0 0 0-.6-.7zM237.1 51.7h.7a.92 .92 0 0 1 .8 .9 .92 .92 0 0 1-.8 .9h-.7zM239 51.7h.2v1.8h-.2zM239.5 52.6a.95 .95 0 0 1 1.9 0 .95 .95 0 0 1-1.9 0zM240 52a.69 .69 0 0 0-.1 1.1 .69 .69 0 0 0 1.1-.2 .68 .68 0 0 0-.1-.9 .68 .68 0 0 0-.9 0zM241.4 53.7h1.4v.1h-1.4zM243.1 51.8a.51 .51 0 0 1 .8 0 .51 .51 0 0 1-.1 .8 .59 .59 0 0 1-.1 1 .59 .59 0 0 1-.8-.7h.2a.36 .36 0 0 0 .5 .4 .36 .36 0 0 0 0-.6h-.2v-.2a.29 .29 0 0 0 .4-.2 .29 .29 0 0 0-.3-.4l-.3 .2v.2h-.3zM244.5 53.2h.2v.3h-.2zM245.2 51.8a.51 .51 0 0 1 .8 0 .51 .51 0 0 1 0 .8 .59 .59 0 0 1-.2 1 .59 .59 0 0 1-.8-.7h.2a.36 .36 0 0 0 .6 .4 .36 .36 0 0 0 0-.6h-.3v-.2a.29 .29 0 0 0 .4-.2 .29 .29 0 0 0-.3-.4l-.3 .2v.2h-.2zM246.4 51.7h.3l.5 1.5 .5-1.5h.3l-.7 1.8h-.2z" fill-rule="evenodd"/>
<path d="M233.9 121.3h.8a.53 .53 0 0 1 .5 .6 .53 .53 0 0 1-.5 .5h-.6v.8h-.2zM234.1 121.6v.6h.5a.32 .32 0 0 0 .4-.3 .32 .32 0 0 0-.4-.3zM235.4 122.3a.95 .95 0 0 1 1.9 0 .95 .95 0 0 1-1.9 0zM235.9 121.7a.69 .69 0 0 0-.1 1.1 .69 .69 0 0 0 1.1-.2 .68 .68 0 0 0-.1-.9 .68 .68 0 0 0-.9 0zM237.4 121.3h.2l.4 1.5 .4-1.5h.2l.5 1.5 .3-1.5h.3l-.5 1.9h-.3l-.4-1.5-.4 1.5h-.3zM239.7 123.4h1.4v.1h-1.4zM241.4 121.5a.51 .51 0 0 1 .8 0 .51 .51 0 0 1-.1 .7 .59 .59 0 0 1-.1 1 .59 .59 0 0 1-.8-.6h.2a.36 .36 0 0 0 .5 .4 .36 .36 0 0 0 0-.6l-.2-.1v-.1a.29 .29 0 0 0 .4-.3 .29 .29 0 0 0-.3-.3l-.3 .1-.1 .3h-.2zM242.6 121.3h.3l.5 1.6 .5-1.6h.3l-.7 1.9h-.2zM244.5 121.5a.51 .51 0 0 1 .8 0 .51 .51 0 0 1-.1 .7 .59 .59 0 0 1-.1 1 .59 .59 0 0 1-.8-.6h.2a.36 .36 0 0 0 .5 .4 .36 .36 0 0 0 0-.6l-.2-.1v-.1a.29 .29 0 0 0 .4-.3 .29 .29 0 0 0-.3-.3l-.3 .1-.1 .3h-.2z" fill-rule="evenodd"/>
<path d="M226.1 67.2h.3l.9 1.4v-1.4h.2v1.8h-.2l-1-1.5v1.5h-.2zM228.5 68.2v.6a.33 .33 0 0 0 .3-.3 .33 .33 0 0 0-.3-.3zM228.1 67.5v.3l.3 .1v-.5zM228 67.3l.4-.1v-.2l.1 .2a.49 .49 0 0 1 .5 .5h-.2l-.3-.3v.6a.53 .53 0 0 1 .5 .5 .53 .53 0 0 1-.5 .5v.3h-.1v-.3l-.4-.1-.2-.3v-.2h.2l.1 .3 .3 .1v-.6a.49 .49 0 0 1-.5-.3 .49 .49 0 0 1 .1-.6zM229.5 67.7a.3 .3 0 0 0 .6 0 .3 .3 0 0 0-.6 0zM229.5 68.5a.36 .36 0 0 0 .7 0 .36 .36 0 0 0-.7 0zM229.4 67.3a.5 .5 0 0 1 .8 0 .5 .5 0 0 1 0 .7 .55 .55 0 0 1 .1 .8 .55 .55 0 0 1-.9 0 .55 .55 0 0 1 .1-.8l-.2-.3zM230.8 67.5l.7-.3v1.8h-.3v-1.3h-.4z" fill-rule="evenodd"/>
<path d="M226.1 69.7h.3l.9 1.5v-1.5h.2v1.9h-.2l-1-1.5v1.5h-.2zM228.5 70.8v.6a.33 .33 0 0 0 .3-.3 .33 .33 0 0 0-.3-.3zM228.1 70v.3l.3 .2v-.6zM228 69.9l.4-.1v-.2l.1 .2a.49 .49 0 0 1 .5 .4h-.2l-.3-.3v.6a.53 .53 0 0 1 .5 .6 .53 .53 0 0 1-.5 .5v.3h-.1v-.3l-.4-.1-.2-.3v-.2h.2l.1 .3 .3 .1v-.7a.49 .49 0 0 1-.5-.2 .49 .49 0 0 1 .1-.6zM229.5 70.3a.3 .3 0 0 0 .6 0 .3 .3 0 0 0-.6 0zM229.5 71.1a.36 .36 0 0 0 .7 0 .36 .36 0 0 0-.7 0zM229.4 69.9a.5 .5 0 0 1 .8 0 .5 .5 0 0 1 0 .7 .55 .55 0 0 1 .1 .8 .55 .55 0 0 1-.9 0 .55 .55 0 0 1 .1-.8l-.2-.3zM230.9 69.9a.61 .61 0 0 1 .9 .3 .61 .61 0 0 1-.6 .8l-.3 .3h1v.3h-1.3a1.5 1.5 0 0 1 1-1.2 .36 .36 0 0 0-.3-.4 .36 .36 0 0 0-.4 .4h-.2z" fill-rule="evenodd"/>
<path d="M159 67.2h.3l.9 1.4v-1.4h.2v1.8h-.2l-1-1.5v1.5h-.2zM161.4 68.2v.6a.33 .33 0 0 0 .3-.3 .33 .33 0 0 0-.3-.3zM161 67.5v.3l.3 .1v-.5zM160.9 67.3l.4-.1v-.2l.1 .2a.49 .49 0 0 1 .5 .5h-.2l-.3-.3v.6a.53 .53 0 0 1 .5 .5 .53 .53 0 0 1-.5 .5v.3h-.1v-.3l-.4-.1-.2-.3v-.2h.2l.1 .3 .3 .1v-.6a.49 .49 0 0 1-.5-.3 .49 .49 0 0 1 .1-.6zM162.1 67.2h1.3l-.8 1.8h-.2l.1-.5 .6-1h-1zM163.8 67.7a.3 .3 0 0 0 .6 0 .3 .3 0 0 0-.6 0zM163.8 68.5a.36 .36 0 0 0 .7 0 .36 .36 0 0 0-.7 0zM163.7 67.3a.5 .5 0 0 1 .8 0 .5 .5 0 0 1 0 .7 .55 .55 0 0 1 .1 .8 .55 .55 0 0 1-.9 0 .55 .55 0 0 1 .1-.8l-.2-.3z" fill-rule="evenodd"/>
<path d="M159 69.7h.3l.9 1.5v-1.5h.2v1.9h-.2l-1-1.5v1.5h-.2zM161.4 70.8v.6a.33 .33 0 0 0 .3-.3 .33 .33 0 0 0-.3-.3zM161 70v.3l.3 .2v-.6zM160.9 69.9l.4-.1v-.2l.1 .2a.49 .49 0 0 1 .5 .4h-.2l-.3-.3v.6a.53 .53 0 0 1 .5 .6 .53 .53 0 0 1-.5 .5v.3h-.1v-.3l-.4-.1-.2-.3v-.2h.2l.1 .3 .3 .1v-.7a.49 .49 0 0 1-.5-.2 .49 .49 0 0 1 .1-.6zM162.1 69.8h1.3l-.8 1.8h-.2l.1-.5 .6-1.1h-1zM163.7 70a.69 .69 0 0 1 .9 0 .69 .69 0 0 1 .1 .8 .6 .6 0 0 1-.4 .8 .6 .6 0 0 1-.7-.5h.2a.35 .35 0 0 0 .4 .3 .35 .35 0 0 0 .3-.4v-.3a.57 .57 0 0 1-.8 .1 .57 .57 0 0 1 0-.8zM163.8 70.4a.38 .38 0 0 0 .7 0 .38 .38 0 0 0-.7 0z" fill-rule="evenodd"/>
<path d="M159 72.3h.3l.9 1.5v-1.5h.2v1.8h-.2l-1-1.4v1.4h-.2zM161.4 73.4v.6a.33 .33 0 0 0 .3-.3 .33 .33 0 0 0-.3-.3zM161 72.6v.3l.3 .2v-.6zM160.9 72.5l.4-.2v-.1l.1 .1a.49 .49 0 0 1 .5 .5h-.2l-.3-.3v.6a.53 .53 0 0 1 .5 .6 .53 .53 0 0 1-.5 .5v.2h-.1v-.2l-.4-.1-.2-.3v-.2h.2l.1 .2 .3 .2v-.7a.49 .49 0 0 1-.5-.3 .49 .49 0 0 1 .1-.5zM162.4 72.8a.3 .3 0 0 0 .6 0 .3 .3 0 0 0-.6 0zM162.4 73.7a.36 .36 0 0 0 .7 0 .36 .36 0 0 0-.7 0zM162.3 72.5a.5 .5 0 0 1 .8-.1 .5 .5 0 0 1 0 .8 .55 .55 0 0 1 .1 .8 .55 .55 0 0 1-.9 0 .55 .55 0 0 1 .1-.8l-.2-.4zM163.7 72.5a.64 .64 0 0 1 .8 0 .64 .64 0 0 1 .3 .7 .66 .66 0 0 1-.6 1 .66 .66 0 0 1-.7-.9zM164 72.6a.93 .93 0 0 0 .1 1.4 .86 .86 0 0 0 .1-1.4z" fill-rule="evenodd"/>
<path d="M159 59.4h.3l.6 1.6 .5-1.6h.3v1.8h-.2v-1.5l-.5 1.5h-.3l-.5-1.5v1.5h-.2zM161.1 59.4h1.4v.2h-1.1v.6h1v.2h-1v.6h1.1v.2h-1.4zM162.9 59.6a.79 .79 0 0 1 .8-.2 .79 .79 0 0 1 .6 .6h-.2a.62 .62 0 0 0-.9-.3 .62 .62 0 0 0-.2 .8 .56 .56 0 0 0 .5 .6 .56 .56 0 0 0 .6-.5h.2a.85 .85 0 0 1-1.1 .6 .85 .85 0 0 1-.5-1.1zM164.6 59.4h.3v.8h.9v-.8h.3v1.8h-.3v-.8h-.9v.8h-.3zM166.3 61.4h1.4v.2h-1.4zM168.1 59.6v1.4h.5a.71 .71 0 0 0 .5-.7 .71 .71 0 0 0-.5-.7zM167.9 59.4h.7a.92 .92 0 0 1 .8 .9 .92 .92 0 0 1-.8 .9h-.7zM169.7 59.4h1.4v.2h-1.1v.6h1v.2h-1v.6h1.1v.2h-1.4zM171.4 59.4h.8a.53 .53 0 0 1 .6 .5 .53 .53 0 0 1-.6 .6h-.5v.7h-.3zM171.7 59.6v.7h.5a.32 .32 0 0 0 .3-.4 .32 .32 0 0 0-.3-.3zM173.1 59.4h.2v1.6h1v.2h-1.2zM174.4 60.3a.95 .95 0 0 1 1.9 0 .95 .95 0 0 1-1.9 0zM174.9 59.8a.69 .69 0 0 0-.1 1.1 .69 .69 0 0 0 1.1-.2 .68 .68 0 0 0-.1-.9 .68 .68 0 0 0-.9 0zM176.3 59.4h.3l.6 .9 .5-.9h.3l-.7 1.1v.7h-.3v-.7zM178 61.4h1.4v.2h-1.4zM179.8 59.5a.72 .72 0 0 1 1.1 .4h-.2a.42 .42 0 0 0-.5-.3 .42 .42 0 0 0-.4 .4 1.47 1.47 0 0 1 1.2 .7 .74 .74 0 0 1-.8 .6 .74 .74 0 0 1-.7-.7h.3a.48 .48 0 0 0 .4 .5 .48 .48 0 0 0 .5-.5l-.4-.2a.56 .56 0 0 1-.6-.2 .56 .56 0 0 1 .1-.7zM181.1 59.4h.3l.4 1.5 .4-1.5h.2l.4 1.5 .4-1.5h.3l-.5 1.8h-.3l-.4-1.5-.4 1.5h-.3zM183.7 59.4h.3v1.8h-.3zM184.2 59.4h1.5v.2h-.6v1.6h-.2v-1.6h-.7zM186.1 59.6a.79 .79 0 0 1 .8-.2 .79 .79 0 0 1 .6 .6h-.3a.62 .62 0 0 0-.8-.3 .62 .62 0 0 0-.3 .8 .56 .56 0 0 0 .6 .6 .56 .56 0 0 0 .5-.5h.3a.85 .85 0 0 1-1.1 .6 .85 .85 0 0 1-.5-1.1zM187.8 59.4h.2v.8h1v-.8h.2v1.8h-.2v-.8h-1v.8h-.2zM189.4 61.4h1.4v.2h-1.4zM190.9 60.4h.7v.2h-.7zM191.7 59.4h.3l.5 1.6 .6-1.6h.2l-.6 1.8h-.3z" fill-rule="evenodd"/>
<path d="M226.4 38.9a.96 .96 0 0 1 1.2 .2 .96 .96 0 0 1-.1 1.3l.3 .2-.2 .1-.3-.2a.96 .96 0 0 1-1.2-.3 .96 .96 0 0 1 .3-1.3zM226.4 39.1a.74 .74 0 0 0-.1 1 .74 .74 0 0 0 .9 .3l-.2-.2 .1-.1 .2 .1a.72 .72 0 0 0 .1-1 .72 .72 0 0 0-1-.1zM228.2 39l.6-.2 .3 .3v.2h-.2a.37 .37 0 0 0-.4-.3 .37 .37 0 0 0-.3 .5v.2a.59 .59 0 0 1 .9 .2 .59 .59 0 0 1-.4 .8 .59 .59 0 0 1-.7-.6v-.7zM228.2 40a.4 .4 0 0 0 .8 0 .4 .4 0 0 0-.8 0zM229.3 40.8h1.4v.1h-1.4zM230.9 38.8h.3v1.8h-.3zM231.7 38.9a.61 .61 0 0 1 1 .3 .61 .61 0 0 1-.6 .8l-.4 .4h1v.2h-1.2a1.5 1.5 0 0 1 .9-1.1 .36 .36 0 0 0-.3-.5 .36 .36 0 0 0-.4 .4h-.2zM233.1 39a.79 .79 0 0 1 .8-.3 .79 .79 0 0 1 .6 .6h-.2a.62 .62 0 0 0-.9-.3 .62 .62 0 0 0-.2 .9 .56 .56 0 0 0 .5 .5 .56 .56 0 0 0 .6-.5h.2a.85 .85 0 0 1-1.1 .7 .85 .85 0 0 1-.5-1.2zM234.6 40.8h1.5v.1h-1.5zM236.4 38.9a.72 .72 0 0 1 1.2 .4h-.3a.42 .42 0 0 0-.4-.4 .42 .42 0 0 0-.4 .5 1.47 1.47 0 0 1 1.1 .7 .74 .74 0 0 1-.7 .5 .74 .74 0 0 1-.7-.6h.2a.48 .48 0 0 0 .5 .4 .48 .48 0 0 0 .5-.4l-.4-.2a.56 .56 0 0 1-.7-.2 .56 .56 0 0 1 .1-.7zM238.2 39v1.4h.4a.71 .71 0 0 0 .6-.7 .71 .71 0 0 0-.6-.7zM238 38.8h.7a.92 .92 0 0 1 .8 .9 .92 .92 0 0 1-.8 .9h-.7zM240.4 39l-.3 .8h.6zM240.3 38.8h.3l.6 1.8h-.2l-.2-.6h-.7l-.2 .6h-.3zM241.3 40.8h1.4v.1h-1.4zM242.9 39.2l.7-.4v1.8h-.2v-1.3h-.5z" fill-rule="evenodd"/>
<path d="M35.4 93.1a.96 .96 0 0 1 1.2 .2 .96 .96 0 0 1-.1 1.3l.3 .2-.1 .1-.3-.2a.96 .96 0 0 1-1.3-.3 .96 .96 0 0 1 .3-1.3zM35.4 93.3a.74 .74 0 0 0-.1 .9 .74 .74 0 0 0 .9 .4l-.2-.2 .1-.1 .2 .1a.72 .72 0 0 0 .1-1 .72 .72 0 0 0-1-.1zM37.2 93.2l.6-.2 .3 .3 .1 .2h-.3a.37 .37 0 0 0-.4-.3 .37 .37 0 0 0-.3 .5v.2a.59 .59 0 0 1 .9 .2 .59 .59 0 0 1-.4 .8 .59 .59 0 0 1-.7-.6v-.7zM37.2 94.2a.4 .4 0 0 0 .8 0 .4 .4 0 0 0-.8 0zM38.3 95h1.4v.1h-1.4zM40 93h.2v1.8h-.2zM40.8 93.1a.61 .61 0 0 1 .9 .3 .61 .61 0 0 1-.6 .8l-.3 .4h.9v.2h-1.2a1.5 1.5 0 0 1 1-1.1 .36 .36 0 0 0-.4-.5 .36 .36 0 0 0-.3 .4h-.3zM42.2 93.2a.79 .79 0 0 1 .8-.3 .79 .79 0 0 1 .5 .6h-.2a.62 .62 0 0 0-.9-.3 .62 .62 0 0 0-.2 .9 .56 .56 0 0 0 .6 .5 .56 .56 0 0 0 .5-.5h.3a.85 .85 0 0 1-1.1 .7 .85 .85 0 0 1-.5-1.2zM43.7 95h1.4v.1h-1.4zM45.4 93.1a.72 .72 0 0 1 1.2 .4h-.2a.42 .42 0 0 0-.5-.4 .42 .42 0 0 0-.4 .4 1.47 1.47 0 0 1 1.2 .8 .74 .74 0 0 1-.8 .5 .74 .74 0 0 1-.7-.6h.2a.48 .48 0 0 0 .5 .4 .48 .48 0 0 0 .5-.4l-.4-.2a.56 .56 0 0 1-.6-.2 .56 .56 0 0 1 0-.7zM47.2 93.2v1.4h.5a.71 .71 0 0 0 .5-.7 .71 .71 0 0 0-.5-.7zM47 93h.7a.92 .92 0 0 1 .8 .9 .92 .92 0 0 1-.8 .9h-.7zM49.5 93.2l-.3 .8h.5zM49.3 93h.3l.7 1.8h-.3l-.2-.6h-.7l-.2 .6h-.3zM50.3 95h1.4v.1h-1.4zM52 93.4l.6-.4v1.8h-.2v-1.3h-.4z" fill-rule="evenodd"/>
<path d="M102.5 18.2a.96 .96 0 0 1 1.2 .3 .96 .96 0 0 1-.1 1.2l.3 .2-.1 .2-.3-.2a.96 .96 0 0 1-1.3-.4 .96 .96 0 0 1 .3-1.3zM102.5 18.5a.74 .74 0 0 0-.1 .9 .74 .74 0 0 0 .9 .3l-.2-.1 .1-.2 .2 .2a.72 .72 0 0 0 .1-1 .72 .72 0 0 0-1-.1zM104.3 18.4l.6-.2 .3 .3 .1 .1h-.3a.37 .37 0 0 0-.4-.2 .37 .37 0 0 0-.3 .4v.2a.59 .59 0 0 1 .9 .2 .59 .59 0 0 1-.4 .9 .59 .59 0 0 1-.7-.7v-.6zM104.3 19.4a.4 .4 0 0 0 .8 0 .4 .4 0 0 0-.8 0zM105.4 20.1h1.4v.2h-1.4zM107.1 18.1h.2v1.8h-.2zM107.9 18.3a.61 .61 0 0 1 .9 .3 .61 .61 0 0 1-.6 .8l-.3 .3h.9v.2h-1.2a1.5 1.5 0 0 1 1-1.1 .36 .36 0 0 0-.4-.4 .36 .36 0 0 0-.3 .4h-.3zM109.3 18.4a.79 .79 0 0 1 .8-.3 .79 .79 0 0 1 .5 .6h-.2a.62 .62 0 0 0-.9-.3 .62 .62 0 0 0-.2 .9 .56 .56 0 0 0 .6 .5 .56 .56 0 0 0 .5-.5h.3a.85 .85 0 0 1-1.1 .7 .85 .85 0 0 1-.5-1.2zM110.8 20.1h1.4v.2h-1.4zM112.5 18.2a.72 .72 0 0 1 1.2 .5h-.2a.42 .42 0 0 0-.5-.4 .42 .42 0 0 0-.4 .4 1.47 1.47 0 0 1 1.2 .7 .74 .74 0 0 1-.8 .6 .74 .74 0 0 1-.7-.6h.2a.48 .48 0 0 0 .5 .4 .48 .48 0 0 0 .5-.5l-.4-.1a.56 .56 0 0 1-.6-.3 .56 .56 0 0 1 0-.7zM114.3 18.3v1.4h.5a.71 .71 0 0 0 .5-.7 .71 .71 0 0 0-.5-.7zM114.1 18.1h.7a.92 .92 0 0 1 .8 .9 .92 .92 0 0 1-.8 .9h-.7zM116.6 18.4l-.3 .8h.5zM116.4 18.1h.3l.7 1.8h-.3l-.2-.5h-.7l-.2 .5h-.3zM117.4 20.1h1.4v.2h-1.4zM119.1 18.5l.6-.3v1.7h-.2v-1.2h-.4z" fill-rule="evenodd"/>
<path d="M226.4 41.4a.96 .96 0 0 1 1.2 .3 .96 .96 0 0 1-.1 1.3l.3 .2-.2 .1-.3-.2a.96 .96 0 0 1-1.2-.3 .96 .96 0 0 1 .3-1.4zM226.4 41.7a.74 .74 0 0 0-.1 .9 .74 .74 0 0 0 .9 .4l-.2-.2 .1-.2 .2 .2a.72 .72 0 0 0 .1-1 .72 .72 0 0 0-1-.1zM228.2 41.6l.6-.2 .3 .3v.2h-.2a.37 .37 0 0 0-.4-.3 .37 .37 0 0 0-.3 .5v.2a.59 .59 0 0 1 .9 .2 .59 .59 0 0 1-.4 .8 .59 .59 0 0 1-.7-.6v-.7zM228.2 42.6a.4 .4 0 0 0 .8 0 .4 .4 0 0 0-.8 0zM229.3 43.4h1.4v.1h-1.4zM230.9 41.3h.3v1.9h-.3zM231.7 41.5a.61 .61 0 0 1 1 .3 .61 .61 0 0 1-.6 .8l-.4 .4h1v.2h-1.2a1.5 1.5 0 0 1 .9-1.1 .36 .36 0 0 0-.3-.5 .36 .36 0 0 0-.4 .4h-.2zM233.1 41.6a.79 .79 0 0 1 .8-.3 .79 .79 0 0 1 .6 .6h-.2a.62 .62 0 0 0-.9-.3 .62 .62 0 0 0-.2 .9 .56 .56 0 0 0 .5 .5 .56 .56 0 0 0 .6-.5h.2a.85 .85 0 0 1-1.1 .7 .85 .85 0 0 1-.5-1.2zM234.6 43.4h1.5v.1h-1.5zM236.4 41.5a.72 .72 0 0 1 1.2 .4h-.3a.42 .42 0 0 0-.4-.4 .42 .42 0 0 0-.4 .4 1.47 1.47 0 0 1 1.1 .8 .74 .74 0 0 1-.7 .5 .74 .74 0 0 1-.7-.6h.2a.48 .48 0 0 0 .5 .4 .48 .48 0 0 0 .5-.4l-.4-.2a.56 .56 0 0 1-.7-.2 .56 .56 0 0 1 .1-.7zM238.1 41.6a.79 .79 0 0 1 .8-.3 .79 .79 0 0 1 .6 .6h-.3a.62 .62 0 0 0-.8-.3 .62 .62 0 0 0-.3 .9 .56 .56 0 0 0 .6 .5 .56 .56 0 0 0 .5-.5h.3a.85 .85 0 0 1-1.1 .7 .85 .85 0 0 1-.5-1.2zM239.8 41.3h.2v1.7h.9v.2h-1.1zM241 43.4h1.4v.1h-1.4zM242.7 41.7l.6-.3v1.8h-.2v-1.3h-.4z" fill-rule="evenodd"/>
<path d="M35.4 87.9a.96 .96 0 0 1 1.2 .2 .96 .96 0 0 1-.1 1.3l.3 .2-.1 .2-.3-.2a.96 .96 0 0 1-1.3-.4 .96 .96 0 0 1 .3-1.3zM35.4 88.2a.74 .74 0 0 0-.1 .9 .74 .74 0 0 0 .9 .3l-.2-.2 .1-.1 .2 .2a.72 .72 0 0 0 .1-1 .72 .72 0 0 0-1-.1zM37.2 88l.6-.1 .3 .2 .1 .2h-.3a.37 .37 0 0 0-.4-.3 .37 .37 0 0 0-.3 .5v.2a.59 .59 0 0 1 .9 .2 .59 .59 0 0 1-.4 .8 .59 .59 0 0 1-.7-.6v-.7zM37.2 89.1a.4 .4 0 0 0 .8 0 .4 .4 0 0 0-.8 0zM38.3 89.8h1.4v.1h-1.4zM40 87.8h.2v1.8h-.2zM40.8 88a.61 .61 0 0 1 .9 .2 .61 .61 0 0 1-.6 .8l-.3 .4h.9v.2h-1.2a1.5 1.5 0 0 1 1-1.1 .36 .36 0 0 0-.4-.5 .36 .36 0 0 0-.3 .5h-.3zM42.2 88a.79 .79 0 0 1 .8-.2 .79 .79 0 0 1 .5 .5h-.2a.62 .62 0 0 0-.9-.2 .62 .62 0 0 0-.2 .8 .56 .56 0 0 0 .6 .6 .56 .56 0 0 0 .5-.5h.3a.85 .85 0 0 1-1.1 .6 .85 .85 0 0 1-.5-1.2zM43.7 89.8h1.4v.1h-1.4zM45.4 87.9a.72 .72 0 0 1 1.2 .4h-.2a.42 .42 0 0 0-.5-.3 .42 .42 0 0 0-.4 .4 1.47 1.47 0 0 1 1.2 .7 .74 .74 0 0 1-.8 .6 .74 .74 0 0 1-.7-.7h.2a.48 .48 0 0 0 .5 .5 .48 .48 0 0 0 .5-.5l-.4-.2a.56 .56 0 0 1-.6-.2 .56 .56 0 0 1 0-.7zM47.1 88a.79 .79 0 0 1 .8-.2 .79 .79 0 0 1 .6 .5h-.3a.62 .62 0 0 0-.8-.2 .62 .62 0 0 0-.2 .8 .56 .56 0 0 0 .5 .6 .56 .56 0 0 0 .6-.5h.2a.85 .85 0 0 1-1.1 .6 .85 .85 0 0 1-.5-1.2zM48.8 87.8h.3v1.6h.9v.2h-1.2zM50 89.8h1.4v.1h-1.4zM51.7 88.2l.6-.3v1.7h-.2v-1.2h-.4z" fill-rule="evenodd"/>
<path d="M102.5 20.8a.96 .96 0 0 1 1.2 .2 .96 .96 0 0 1-.1 1.3l.3 .2-.1 .2-.3-.2a.96 .96 0 0 1-1.3-.4 .96 .96 0 0 1 .3-1.3zM102.5 21.1a.74 .74 0 0 0-.1 .9 .74 .74 0 0 0 .9 .3l-.2-.1 .1-.2 .2 .2a.72 .72 0 0 0 .1-1 .72 .72 0 0 0-1-.1zM104.3 20.9l.6-.1 .3 .3 .1 .1h-.3a.37 .37 0 0 0-.4-.3 .37 .37 0 0 0-.3 .5v.2a.59 .59 0 0 1 .9 .2 .59 .59 0 0 1-.4 .8 .59 .59 0 0 1-.7-.6v-.7zM104.3 22a.4 .4 0 0 0 .8 0 .4 .4 0 0 0-.8 0zM105.4 22.7h1.4v.1h-1.4zM107.1 20.7h.2v1.8h-.2zM107.9 20.9a.61 .61 0 0 1 .9 .3 .61 .61 0 0 1-.6 .7l-.3 .4h.9v.2h-1.2a1.5 1.5 0 0 1 1-1.1 .36 .36 0 0 0-.4-.5 .36 .36 0 0 0-.3 .5h-.3zM109.3 20.9a.79 .79 0 0 1 .8-.2 .79 .79 0 0 1 .5 .6h-.2a.62 .62 0 0 0-.9-.3 .62 .62 0 0 0-.2 .8 .56 .56 0 0 0 .6 .6 .56 .56 0 0 0 .5-.5h.3a.85 .85 0 0 1-1.1 .6 .85 .85 0 0 1-.5-1.2zM110.8 22.7h1.4v.1h-1.4zM112.5 20.8a.72 .72 0 0 1 1.2 .4h-.2a.42 .42 0 0 0-.5-.3 .42 .42 0 0 0-.4 .4 1.47 1.47 0 0 1 1.2 .7 .74 .74 0 0 1-.8 .6 .74 .74 0 0 1-.7-.7h.2a.48 .48 0 0 0 .5 .5 .48 .48 0 0 0 .5-.5l-.4-.2a.56 .56 0 0 1-.6-.2 .56 .56 0 0 1 0-.7zM114.2 20.9a.79 .79 0 0 1 .8-.2 .79 .79 0 0 1 .6 .6h-.3a.62 .62 0 0 0-.8-.3 .62 .62 0 0 0-.2 .8 .56 .56 0 0 0 .5 .6 .56 .56 0 0 0 .6-.5h.2a.85 .85 0 0 1-1.1 .6 .85 .85 0 0 1-.5-1.2zM115.9 20.7h.3v1.6h.9v.2h-1.2zM117.1 22.7h1.4v.1h-1.4zM118.8 21.1l.6-.3v1.7h-.2v-1.2h-.4z" fill-rule="evenodd"/>
<path d="M234.1 136.9a.96 .96 0 0 1 1.3 .3 .96 .96 0 0 1-.2 1.3l.3 .1-.1 .2-.3-.2a.96 .96 0 0 1-1.3-.4 .96 .96 0 0 1 .3-1.3zM234.2 137.2a.74 .74 0 0 0-.2 .9 .74 .74 0 0 0 .9 .3l-.2-.1 .1-.2 .3 .2a.72 .72 0 0 0 .1-1 .72 .72 0 0 0-1-.1zM235.9 137.1l.6-.2 .4 .3v.1h-.2a.37 .37 0 0 0-.5-.2 .37 .37 0 0 0-.2 .4l-.1 .2a.59 .59 0 0 1 1 .2 .59 .59 0 0 1-.5 .9 .59 .59 0 0 1-.7-.7v-.6zM236 138.1a.38 .38 0 0 0 .7 0 .38 .38 0 0 0-.7 0zM237 138.8h1.4v.2h-1.4zM238.8 137a.81 .81 0 0 1 1.4 .4h-.3a.63 .63 0 0 0-.8-.3 .63 .63 0 0 0-.3 .9 .58 .58 0 0 0 .6 .5 .58 .58 0 0 0 .6-.6h-.6v-.2h.8v1h-.1l-.1-.3a.89 .89 0 0 1-1.2 .1 .89 .89 0 0 1-.1-1.3zM240.6 136.8h.8a.53 .53 0 0 1 .6 .6 .53 .53 0 0 1-.6 .5h-.5v.8h-.3zM240.9 137v.7h.5a.32 .32 0 0 0 .3-.3 .32 .32 0 0 0-.3-.4zM242.4 136.8h.2v1.9h-.2zM242.9 137.8a.95 .95 0 0 1 1.9 0 .95 .95 0 0 1-1.9 0zM243.3 137.2a.69 .69 0 0 0 0 1.1 .69 .69 0 0 0 1.1-.2 .68 .68 0 0 0-.1-.9 .68 .68 0 0 0-1 0zM244.8 138.8h1.4v.2h-1.4zM246.4 137.2l.7-.3v1.8h-.2v-1.3h-.5zM247.9 137.1a.64 .64 0 0 1 .8-.1 .64 .64 0 0 1 .2 .8 .66 .66 0 0 1-.6 .9 .66 .66 0 0 1-.6-.9zM248.1 137.1a.93 .93 0 0 0 .2 1.4 .86 .86 0 0 0 0-1.4z" fill-rule="evenodd"/>
<path d="M234.1 160.2a.96 .96 0 0 1 1.3 .2 .96 .96 0 0 1-.2 1.3l.3 .2-.1 .1-.3-.2a.96 .96 0 0 1-1.3-.3 .96 .96 0 0 1 .3-1.3zM234.2 160.4a.74 .74 0 0 0-.2 .9 .74 .74 0 0 0 .9 .4l-.2-.2 .1-.2 .3 .2a.72 .72 0 0 0 .1-1 .72 .72 0 0 0-1-.1zM235.9 160.3l.6-.2 .4 .3v.2h-.2a.37 .37 0 0 0-.5-.3 .37 .37 0 0 0-.2 .5l-.1 .2a.59 .59 0 0 1 1 .2 .59 .59 0 0 1-.5 .8 .59 .59 0 0 1-.7-.6v-.7zM236 161.3a.38 .38 0 0 0 .7 0 .38 .38 0 0 0-.7 0zM237 162.1h1.4v.1h-1.4zM238.8 160.3a.81 .81 0 0 1 1.4 .3h-.3a.63 .63 0 0 0-.8-.3 .63 .63 0 0 0-.3 .9 .58 .58 0 0 0 .6 .5 .58 .58 0 0 0 .6-.6h-.6v-.2h.8v1h-.1l-.1-.3a.89 .89 0 0 1-1.2 .1 .89 .89 0 0 1-.1-1.2zM240.6 160.1h.8a.53 .53 0 0 1 .6 .5 .53 .53 0 0 1-.6 .5h-.5v.8h-.3zM240.9 160.3v.6h.5a.32 .32 0 0 0 .3-.3 .32 .32 0 0 0-.3-.3zM242.4 160.1h.2v1.8h-.2zM242.9 161a.95 .95 0 0 1 1.9 0 .95 .95 0 0 1-1.9 0zM243.3 160.4a.69 .69 0 0 0 0 1.1 .69 .69 0 0 0 1.1-.2 .68 .68 0 0 0-.1-.9 .68 .68 0 0 0-1 0zM244.8 162.1h1.4v.1h-1.4zM246.4 160.4l.7-.3v1.8h-.2v-1.3h-.5zM247.9 160.3a.64 .64 0 0 1 .8-.1 .64 .64 0 0 1 .2 .8 .66 .66 0 0 1-.6 .9 .66 .66 0 0 1-.6-.9zM248.1 160.3a.93 .93 0 0 0 .2 1.4 .86 .86 0 0 0 0-1.4z" fill-rule="evenodd"/>
<path d="M226.4 46.6a.96 .96 0 0 1 1.2 .3 .96 .96 0 0 1-.1 1.2l.3 .2-.2 .2-.3-.2a.96 .96 0 0 1-1.2-.4 .96 .96 0 0 1 .3-1.3zM226.4 46.9a.74 .74 0 0 0-.1 .9 .74 .74 0 0 0 .9 .3l-.2-.1 .1-.2 .2 .2a.72 .72 0 0 0 .1-1 .72 .72 0 0 0-1-.1zM228.2 46.7l.6-.1 .3 .3v.1h-.2a.37 .37 0 0 0-.4-.2 .37 .37 0 0 0-.3 .4v.2a.59 .59 0 0 1 .9 .2 .59 .59 0 0 1-.4 .9 .59 .59 0 0 1-.7-.7v-.6zM228.2 47.8a.4 .4 0 0 0 .8 0 .4 .4 0 0 0-.8 0zM229.3 48.5h1.4v.1h-1.4zM231.1 46.7a.81 .81 0 0 1 1.4 .4h-.3a.63 .63 0 0 0-.9-.3 .63 .63 0 0 0-.2 .8 .58 .58 0 0 0 .6 .6 .58 .58 0 0 0 .6-.6h-.6v-.2h.8v.9h-.2v-.2a.89 .89 0 0 1-1.3 .1 .89 .89 0 0 1-.1-1.3zM232.9 46.5h.8a.53 .53 0 0 1 .5 .5 .53 .53 0 0 1-.5 .6h-.6v.7h-.2zM233.1 46.7v.7h.5a.32 .32 0 0 0 .4-.4 .32 .32 0 0 0-.4-.3zM234.6 46.5h.3v1.8h-.3zM235.2 47.4a.94 .94 0 0 1 1.8 0 .94 .94 0 0 1-1.8 0zM235.6 46.9a.69 .69 0 0 0 0 1 .69 .69 0 0 0 1-.1 .68 .68 0 0 0-.1-.9 .68 .68 0 0 0-.9 0zM237 48.5h1.5v.1h-1.5zM238.8 46.7a.61 .61 0 0 1 1 .3 .61 .61 0 0 1-.7 .8l-.3 .3h1v.2h-1.3a1.5 1.5 0 0 1 1-1.1 .36 .36 0 0 0-.3-.5 .36 .36 0 0 0-.4 .5h-.2z" fill-rule="evenodd"/>
<path d="M233.8 154.9h.3l.9 1.5v-1.5h.3v1.8h-.3l-.9-1.5v1.5h-.3zM236.2 155.9v.7a.33 .33 0 0 0 .4-.3 .33 .33 0 0 0-.4-.4zM235.9 155.2l-.1 .3 .3 .2v-.6zM235.7 155.1l.4-.2v-.2l.1 .2a.49 .49 0 0 1 .5 .5h-.2l-.3-.3v.6a.53 .53 0 0 1 .6 .5 .53 .53 0 0 1-.6 .6v.2h-.1v-.2l-.4-.2-.1-.2-.1-.2h.3v.2l.3 .2v-.7a.49 .49 0 0 1-.5-.3 .49 .49 0 0 1 .1-.5zM237.3 155.4a.3 .3 0 0 0 .6 0 .3 .3 0 0 0-.6 0zM237.2 156.2a.36 .36 0 0 0 .7 0 .36 .36 0 0 0-.7 0zM237.2 155.1a.5 .5 0 0 1 .7-.1 .5 .5 0 0 1 0 .8 .55 .55 0 0 1 .1 .8 .55 .55 0 0 1-.8 0 .55 .55 0 0 1 .1-.8l-.3-.4zM238.6 155a.51 .51 0 0 1 .7 0 .51 .51 0 0 1 0 .8 .59 .59 0 0 1-.1 1 .59 .59 0 0 1-.8-.6h.2a.36 .36 0 0 0 .5 .4 .36 .36 0 0 0 0-.7h-.3l.1-.2a.29 .29 0 0 0 .4-.2 .29 .29 0 0 0-.3-.4l-.3 .2-.1 .2h-.2z" fill-rule="evenodd"/>
<path d="M234.1 118.9a.96 .96 0 0 1 1.3 .2 .96 .96 0 0 1-.2 1.3l.3 .2-.1 .1-.3-.2a.96 .96 0 0 1-1.3-.3 .96 .96 0 0 1 .3-1.3zM234.2 119.1a.74 .74 0 0 0-.2 1 .74 .74 0 0 0 .9 .3l-.2-.2 .1-.1 .3 .1a.72 .72 0 0 0 .1-1 .72 .72 0 0 0-1-.1zM235.9 119l.6-.2 .4 .3v.2h-.2a.37 .37 0 0 0-.5-.3 .37 .37 0 0 0-.2 .5l-.1 .2a.59 .59 0 0 1 1 .2 .59 .59 0 0 1-.5 .8 .59 .59 0 0 1-.7-.6v-.7zM236 120a.38 .38 0 0 0 .7 0 .38 .38 0 0 0-.7 0zM237 120.8h1.4v.1h-1.4zM238.9 119v.6h.6a.31 .31 0 0 0 .4-.3 .31 .31 0 0 0-.4-.3zM238.7 118.8a1.57 1.57 0 0 1 1.3 .1l.1 .5-.3 .3 .2 .2 .2 .7h-.3l-.1-.7-.3-.1h-.6v.8h-.2zM241.1 119l-.3 .8h.6zM241 118.8h.3l.6 1.8h-.2l-.2-.6h-.7l-.2 .6h-.3zM242.4 119v1.4h.5a.71 .71 0 0 0 .5-.7 .71 .71 0 0 0-.5-.7zM242.2 118.8h.7a.92 .92 0 0 1 .8 .9 .92 .92 0 0 1-.8 .9h-.7zM244 118.8h.3v1.8h-.3zM244.6 119.7a.95 .95 0 0 1 1.9 0 .95 .95 0 0 1-1.9 0zM245 119.1a.69 .69 0 0 0 0 1.1 .69 .69 0 0 0 1.1-.2 .68 .68 0 0 0-.2-.9 .68 .68 0 0 0-.9 0zM246.5 120.8h1.4v.1h-1.4zM248.1 118.8h.3v1.1a.47 .47 0 0 0 .4 .5 .47 .47 0 0 0 .5-.5v-1.1h.2v1a.73 .73 0 0 1-.7 .8 .73 .73 0 0 1-.7-.8zM250.6 119l-.3 .8h.6zM250.4 118.8h.3l.7 1.8h-.3l-.2-.6h-.7l-.2 .6h-.2zM251.9 119v.6h.6a.31 .31 0 0 0 .3-.3 .31 .31 0 0 0-.3-.3zM251.6 118.8a1.57 1.57 0 0 1 1.4 .1l.1 .5-.3 .3 .2 .2 .2 .7h-.3l-.1-.7-.3-.1h-.6v.8h-.3zM253.2 118.8h1.5v.2h-.6v1.6h-.2v-1.6h-.7zM254.8 120.8h1.4v.1h-1.4zM256.6 119v.6h.6a.31 .31 0 0 0 .4-.3 .31 .31 0 0 0-.4-.3zM256.4 118.8a1.57 1.57 0 0 1 1.3 .1l.1 .5-.2 .3 .2 .2 .1 .7h-.3l-.1-.7-.3-.1h-.6v.8h-.2zM258.1 118.8h.3l.5 .7 .4-.7h.3l-.6 .9 .7 .9h-.3l-.5-.8-.5 .8h-.3l.6-.9z" fill-rule="evenodd"/>
<path d="M76.4 111.4a1.16 1.16 0 0 1 1.4 .1l.2-.3 .2 .2-.3 .2a.94 .94 0 0 1-.3 1.3 .94 .94 0 0 1-1.2-.2 .94 .94 0 0 1 0-1.3zM76.6 111.6a.7 .7 0 0 0 .4 1.1 .7 .7 0 0 0 .8-.9l-.2 .2-.1-.1 .2-.2-.5-.2zM76.4 110l.3-.2v.3a.37 .37 0 0 0-.3 .4 .37 .37 0 0 0 .5 .3h.2a.59 .59 0 0 1 .2-.9 .59 .59 0 0 1 .8 .4 .59 .59 0 0 1-.6 .7 .86 .86 0 0 1-1.2-.9zM77.1 110.4a.38 .38 0 0 0 .7 0 .38 .38 0 0 0-.7 0zM78.2 108.3h.1v1.4h-.1zM76.5 106.9l-.1 .9h.6v-.8zM76.3 106.7l.5-.1 .3 .3 .2-.2 .7-.1v.3h-.6l-.2 .4v.5h.8v.3h-1.8a1.57 1.57 0 0 1 .1-1.4zM76.5 105.6l.8 .3v-.6zM76.2 105.5l1.8-.7v.3l-.5 .2v.7l.5 .2v.2l-1.8-.7zM76.6 103.4l-.2 .3v.6h1.4v-.4a.74 .74 0 0 0-1.2-.5zM76.5 103.2a.99 .99 0 0 1 1.5 .6v.8h-1.8v-1zM76.2 102.4h1.8v.3h-1.8zM76.2 101.2a.95 .95 0 0 1 1.9 0 .95 .95 0 0 1-1.9 0zM76.6 100.8a.68 .68 0 0 0 0 .9 .68 .68 0 0 0 1 0 .68 .68 0 0 0 0-.9l-.5-.2zM78.2 98.8h.1v1.5h-.1zM76.2 97.2h1a.73 .73 0 0 1 .9 .7 .73 .73 0 0 1-.9 .7h-1v-.2h1.1a.47 .47 0 0 0 .5-.5 .47 .47 0 0 0-.5-.5h-1.1zM76.5 96.2l.8 .2v-.5zM76.2 96l1.8-.7v.3l-.5 .2v.7l.5 .2v.3l-1.8-.7zM76.5 93.9l-.1 .9h.6v-.8zM76.3 93.8l.5-.1 .3 .2 .2-.2 .7-.1v.3l-.6 .1-.2 .3v.5h.8v.3h-1.8a1.57 1.57 0 0 1 .1-1.3zM76.2 92h.2v.6h1.6v.3h-1.6v.6h-.2zM78.2 90.6h.1v1.4h-.1zM76.5 89.2l-.1 .9h.6v-.9zM76.3 89l.5-.1 .3 .2 .2-.2 .7-.1v.3l-.6 .1-.2 .3v.6h.8v.2h-1.8a1.57 1.57 0 0 1 .1-1.3zM76.2 87.1l.9 .6 .9-.6v.3l-.7 .5 .7 .5v.3l-.9-.7-.9 .6v-.3l.7-.4-.7-.5z" fill-rule="evenodd"/>
<path d="M174.7 118.9a.96 .96 0 0 1 1.3 .2 .96 .96 0 0 1-.1 1.3l.2 .2-.1 .1-.3-.2a.96 .96 0 0 1-1.3-.3 .96 .96 0 0 1 .3-1.3zM174.8 119.1a.74 .74 0 0 0-.1 1 .74 .74 0 0 0 .8 .3l-.2-.2 .2-.1 .2 .1a.72 .72 0 0 0 .1-1 .72 .72 0 0 0-1-.1zM176.6 119l.6-.2 .3 .3v.2h-.2a.37 .37 0 0 0-.4-.3 .37 .37 0 0 0-.3 .5v.2a.59 .59 0 0 1 .9 .2 .59 .59 0 0 1-.4 .8 .59 .59 0 0 1-.7-.6v-.7zM176.6 120a.4 .4 0 0 0 .8 0 .4 .4 0 0 0-.8 0zM177.7 120.8h1.4v.1h-1.4zM179.5 119v.6h.6a.31 .31 0 0 0 .4-.3 .31 .31 0 0 0-.3-.3zM179.3 118.8a1.57 1.57 0 0 1 1.3 .1l.1 .5-.2 .3 .2 .2 .1 .7h-.3l-.1-.7-.3-.1h-.6v.8h-.2zM181.8 119l-.3 .8h.5zM181.6 118.8h.3l.7 1.8h-.3l-.2-.6h-.7l-.2 .6h-.2zM183.1 119v1.4h.4a.71 .71 0 0 0 .6-.7 .71 .71 0 0 0-.6-.7zM182.8 118.8h.7a.92 .92 0 0 1 .8 .9 .92 .92 0 0 1-.8 .9h-.7zM184.7 118.8h.2v1.8h-.2zM185.2 119.7a.95 .95 0 0 1 1.9 0 .95 .95 0 0 1-1.9 0zM185.7 119.1a.69 .69 0 0 0-.1 1.1 .69 .69 0 0 0 1.1-.2 .68 .68 0 0 0-.1-.9 .68 .68 0 0 0-.9 0zM187.1 120.8h1.4v.1h-1.4zM188.7 118.8h.3v1.1a.47 .47 0 0 0 .5 .5 .47 .47 0 0 0 .4-.5v-1.1h.3v1a.73 .73 0 0 1-.7 .8 .73 .73 0 0 1-.8-.8zM191.2 119l-.3 .8h.6zM191.1 118.8h.3l.6 1.8h-.2l-.2-.6h-.7l-.2 .6h-.3zM192.5 119v.6h.6a.31 .31 0 0 0 .4-.3 .31 .31 0 0 0-.4-.3zM192.3 118.8a1.57 1.57 0 0 1 1.3 .1l.1 .5-.2 .3 .2 .2 .1 .7h-.3l-.1-.7-.3-.1h-.6v.8h-.2zM193.9 118.8h1.5v.2h-.6v1.6h-.3v-1.6h-.6zM195.4 120.8h1.4v.1h-1.4zM196.9 118.8h1.4v.2h-.6v1.6h-.2v-1.6h-.6zM198.5 118.8h.3l.4 .7 .5-.7h.3l-.6 .9 .6 .9h-.3l-.5-.8-.5 .8h-.3l.7-.9z" fill-rule="evenodd"/>
<path d="M86.8 111.1a1.16 1.16 0 0 1 1.3 .1l.2-.2 .2 .1-.2 .3a.94 .94 0 0 1-.4 1.2 .94 .94 0 0 1-1.2-.2 .94 .94 0 0 1 .1-1.3zM86.9 111.4a.7 .7 0 0 0 .4 1.1 .7 .7 0 0 0 .8-.9l-.1 .2-.2-.2 .2-.2-.5-.2zM86.7 109.7l.3-.1v.2a.37 .37 0 0 0-.2 .4 .37 .37 0 0 0 .4 .3h.2a.59 .59 0 0 1 .2-.9 .59 .59 0 0 1 .9 .4 .59 .59 0 0 1-.7 .7 .86 .86 0 0 1-1.2-.9zM87.4 110.1a.4 .4 0 0 0 .8 0 .4 .4 0 0 0-.8 0zM88.5 108h.1v1.4h-.1zM86.9 106.6l-.2 1h.6v-.9zM86.7 106.5l.5-.1 .2 .2 .2-.2 .7-.1v.3l-.6 .1-.1 .3v.6h.7v.2h-1.8a1.57 1.57 0 0 1 .2-1.3zM86.8 105.3l.8 .3v-.5zM86.5 105.2l1.8-.7v.3l-.5 .2v.7l.5 .2v.2l-1.8-.6zM86.9 103.2l-.2 .2v.6h1.4v-.4a.74 .74 0 0 0-1.2-.4zM86.8 103a.99 .99 0 0 1 1.5 .6v.7h-1.8v-1zM86.5 102.2h1.8v.2h-1.8zM86.5 100.9a.95 .95 0 0 1 1.9 0 .95 .95 0 0 1-1.9 0zM86.9 100.5a.68 .68 0 0 0 .1 .9 .68 .68 0 0 0 .9 0 .68 .68 0 0 0 0-.9l-.5-.2zM88.5 98.6h.1v1.4h-.1zM86.5 96.9h1a.73 .73 0 0 1 .9 .7 .73 .73 0 0 1-.9 .8h-1v-.3h1.1a.47 .47 0 0 0 .6-.5 .47 .47 0 0 0-.6-.4h-1.1zM86.8 95.9l.8 .3v-.6zM86.5 95.7l1.8-.6v.2l-.5 .2v.7l.5 .2v.3l-1.8-.7zM86.9 93.7l-.2 .9h.6v-.9zM86.7 93.5l.5-.1 .2 .2 .2-.2 .7-.1v.3l-.6 .1-.1 .3v.6h.7v.2h-1.8a1.57 1.57 0 0 1 .2-1.3zM86.5 91.7h.2v.6h1.6v.3h-1.6v.6h-.2zM88.5 90.3h.1v1.4h-.1zM86.5 88.8h.2v.6h1.6v.2h-1.6v.6h-.2zM86.5 87.1l.9 .6 .9-.6v.3l-.7 .5 .7 .5v.3l-.9-.7-.9 .6v-.3l.7-.4-.7-.5z" fill-rule="evenodd"/>
<path d="M164.8 98.4l-.3 .8h.6zM164.7 98.1h.3l.6 1.8h-.3l-.1-.5h-.8l-.2 .5h-.2zM165.8 98.1h.3l1 1.5v-1.5h.2v1.8h-.3l-.9-1.4v1.4h-.3zM167.5 98.1h1.5v.2h-.6v1.6h-.3v-1.6h-.6zM169.3 98.1h1.3v.2h-1.1v.6h1v.2h-1v.6h1.1v.2h-1.3zM170.9 98.1h.3l.9 1.5v-1.5h.3v1.8h-.3l-.9-1.4v1.4h-.3zM172.8 98.1h.2l1 1.5v-1.5h.2v1.8h-.3l-.9-1.4v1.4h-.2zM175.2 98.4l-.2 .8h.5zM175.1 98.1h.3l.7 1.8h-.3l-.2-.5h-.7l-.2 .5h-.3zM176.1 100.1h1.4v.2h-1.4zM178 98.3v1.4h.4a.71 .71 0 0 0 .6-.7 .71 .71 0 0 0-.6-.7zM177.7 98.1h.7a.92 .92 0 0 1 .8 .9 .92 .92 0 0 1-.8 .9h-.7zM179.6 98.1h1.3v.2h-1.1v.6h1v.2h-1v.6h1.1v.2h-1.3zM181.2 98.1h.9a.53 .53 0 0 1 .5 .5 .53 .53 0 0 1-.5 .6h-.6v.7h-.3zM181.5 98.3v.7h.5a.32 .32 0 0 0 .4-.4 .32 .32 0 0 0-.4-.3zM182.9 98.1h.3v1.6h.9v.2h-1.2zM184.2 99a.95 .95 0 0 1 1.9 0 .95 .95 0 0 1-1.9 0zM184.7 98.5a.69 .69 0 0 0-.1 1.1 .69 .69 0 0 0 1.1-.2 .68 .68 0 0 0-.1-.9 .68 .68 0 0 0-.9 0zM186.2 98.1h.3l.5 .9 .5-.9h.3l-.7 1.1v.7h-.2v-.7zM188 98.1h.3l.6 1.6 .5-1.6h.3v1.8h-.2v-1.5l-.5 1.5h-.3l-.5-1.5v1.5h-.2zM190.1 98.1h1.4v.2h-1.1v.6h1v.2h-1v.6h1.1v.2h-1.4zM191.8 98.1h.3l.9 1.5v-1.5h.3v1.8h-.3l-1-1.4v1.4h-.2zM193.5 98.1h1.5v.2h-.6v1.6h-.3v-1.6h-.6zM195 100.1h1.4v.2h-1.4zM197.1 98.6h.2v.6h.5v.2h-.5v.5h-.2v-.5h-.6v-.2h.6zM198 98.1h.2l.6 1.6 .5-1.6h.3l-.7 1.8h-.3z" fill-rule="evenodd"/>
<path d="M102.9 57.1l-.3 .8h.5zM102.7 56.8h.3l.7 1.9h-.3l-.2-.6h-.7l-.2 .6h-.2zM103.9 56.8h.3l.9 1.5v-1.5h.3v1.9h-.3l-1-1.5v1.5h-.2zM105.6 56.8h1.5v.2h-.6v1.7h-.3v-1.7h-.6zM107.3 56.8h1.3v.3h-1v.5h1v.2h-1v.6h1.1v.3h-1.4zM109 56.8h.3l.9 1.5v-1.5h.2v1.9h-.2l-1-1.5v1.5h-.2zM110.8 56.8h.3l.9 1.5v-1.5h.3v1.9h-.3l-.9-1.5v1.5h-.3zM113.3 57.1l-.3 .8h.6zM113.2 56.8h.3l.6 1.9h-.2l-.2-.6h-.8l-.1 .6h-.3zM114.2 58.8h1.4v.2h-1.4zM116 57v1.4h.5a.71 .71 0 0 0 .5-.7 .71 .71 0 0 0-.5-.7zM115.8 56.8h.7a.92 .92 0 0 1 .8 .9 .92 .92 0 0 1-.8 1h-.7zM117.6 56.8h1.3v.3h-1v.5h1v.2h-1v.6h1.1v.3h-1.4zM119.3 56.8h.8a.53 .53 0 0 1 .6 .6 .53 .53 0 0 1-.6 .5h-.5v.8h-.3zM119.6 57v.7h.4a.32 .32 0 0 0 .4-.3 .32 .32 0 0 0-.4-.4zM121 56.8h.2v1.6h1v.3h-1.2zM122.3 57.8a.95 .95 0 0 1 1.9 0 .95 .95 0 0 1-1.9 0zM122.7 57.2a.69 .69 0 0 0 0 1.1 .69 .69 0 0 0 1.1-.2 .68 .68 0 0 0-.2-.9 .68 .68 0 0 0-.9 0zM124.2 56.8h.3l.5 .9 .6-.9h.3l-.7 1.1v.8h-.3v-.8zM126.1 56.8h.3l.5 1.6 .6-1.6h.3v1.9h-.2v-1.6l-.5 1.6h-.3l-.5-1.6v1.6h-.2zM128.2 56.8h1.3v.3h-1.1v.5h1v.2h-1v.6h1.2v.3h-1.4zM129.9 56.8h.3l.9 1.5v-1.5h.2v1.9h-.3l-.9-1.5v1.5h-.2zM131.6 56.8h1.4v.2h-.6v1.7h-.2v-1.7h-.6zM133.1 58.8h1.4v.2h-1.4zM135.1 57.4h.2v.5h.6v.2h-.6v.6h-.2v-.6h-.5v-.2h.5zM136 56.8h.3l.5 1.6 .5-1.6h.3l-.6 1.9h-.3z" fill-rule="evenodd"/>
<path d="M164.8 101l-.3 .8h.6zM164.7 100.7h.3l.6 1.8h-.3l-.1-.5h-.8l-.2 .5h-.2zM165.8 100.7h.3l1 1.5v-1.5h.2v1.8h-.3l-.9-1.5v1.5h-.3zM167.5 100.7h1.5v.2h-.6v1.6h-.3v-1.6h-.6zM169.3 100.7h1.3v.2h-1.1v.6h1v.2h-1v.6h1.1v.2h-1.3zM170.9 100.7h.3l.9 1.5v-1.5h.3v1.8h-.3l-.9-1.5v1.5h-.3zM172.8 100.7h.2l1 1.5v-1.5h.2v1.8h-.3l-.9-1.5v1.5h-.2zM175.2 101l-.2 .8h.5zM175.1 100.7h.3l.7 1.8h-.3l-.2-.5h-.7l-.2 .5h-.3zM176.1 102.7h1.4v.1h-1.4zM178 100.9v1.4h.4a.71 .71 0 0 0 .6-.7 .71 .71 0 0 0-.6-.7zM177.7 100.7h.7a.92 .92 0 0 1 .8 .9 .92 .92 0 0 1-.8 .9h-.7zM179.6 100.7h1.3v.2h-1.1v.6h1v.2h-1v.6h1.1v.2h-1.3zM181.2 100.7h.9a.53 .53 0 0 1 .5 .5 .53 .53 0 0 1-.5 .6h-.6v.7h-.3zM181.5 100.9v.6h.5a.32 .32 0 0 0 .4-.3 .32 .32 0 0 0-.4-.3zM182.9 100.7h.3v1.6h.9v.2h-1.2zM184.2 101.6a.95 .95 0 0 1 1.9 0 .95 .95 0 0 1-1.9 0zM184.7 101.1a.69 .69 0 0 0-.1 1 .69 .69 0 0 0 1.1-.1 .68 .68 0 0 0-.1-.9 .68 .68 0 0 0-.9 0zM186.2 100.7h.3l.5 .9 .5-.9h.3l-.7 1.1v.7h-.2v-.7zM188 100.7h.3l.6 1.5 .5-1.5h.3v1.8h-.2v-1.5l-.5 1.5h-.3l-.5-1.5v1.5h-.2zM190.1 100.7h1.4v.2h-1.1v.6h1v.2h-1v.6h1.1v.2h-1.4zM191.8 100.7h.3l.9 1.5v-1.5h.3v1.8h-.3l-1-1.5v1.5h-.2zM193.5 100.7h1.5v.2h-.6v1.6h-.3v-1.6h-.6zM195 102.7h1.4v.1h-1.4zM196.8 100.9a.81 .81 0 0 1 1.4 .4h-.3a.63 .63 0 0 0-.8-.3 .63 .63 0 0 0-.3 .8 .58 .58 0 0 0 .6 .6 .58 .58 0 0 0 .6-.6h-.6v-.3h.8v1h-.2v-.2a.89 .89 0 0 1-1.2 0 .89 .89 0 0 1-.2-1.2zM198.6 100.7h.3l.9 1.5v-1.5h.2v1.8h-.2l-1-1.5v1.5h-.2zM200.7 100.9v1.4h.4a.71 .71 0 0 0 .6-.7 .71 .71 0 0 0-.6-.7zM200.4 100.7h.8a.92 .92 0 0 1 .7 .9 .92 .92 0 0 1-.7 .9h-.8z" fill-rule="evenodd"/>
<path d="M102.9 59.7l-.3 .8h.5zM102.7 59.4h.3l.7 1.8h-.3l-.2-.5h-.7l-.2 .5h-.2zM103.9 59.4h.3l.9 1.5v-1.5h.3v1.8h-.3l-1-1.4v1.4h-.2zM105.6 59.4h1.5v.2h-.6v1.6h-.3v-1.6h-.6zM107.3 59.4h1.3v.2h-1v.6h1v.2h-1v.6h1.1v.2h-1.4zM109 59.4h.3l.9 1.5v-1.5h.2v1.8h-.2l-1-1.4v1.4h-.2zM110.8 59.4h.3l.9 1.5v-1.5h.3v1.8h-.3l-.9-1.4v1.4h-.3zM113.3 59.7l-.3 .8h.6zM113.2 59.4h.3l.6 1.8h-.2l-.2-.5h-.8l-.1 .5h-.3zM114.2 61.4h1.4v.2h-1.4zM116 59.6v1.4h.5a.71 .71 0 0 0 .5-.7 .71 .71 0 0 0-.5-.7zM115.8 59.4h.7a.92 .92 0 0 1 .8 .9 .92 .92 0 0 1-.8 .9h-.7zM117.6 59.4h1.3v.2h-1v.6h1v.2h-1v.6h1.1v.2h-1.4zM119.3 59.4h.8a.53 .53 0 0 1 .6 .5 .53 .53 0 0 1-.6 .6h-.5v.7h-.3zM119.6 59.6v.7h.4a.32 .32 0 0 0 .4-.4 .32 .32 0 0 0-.4-.3zM121 59.4h.2v1.6h1v.2h-1.2zM122.3 60.3a.95 .95 0 0 1 1.9 0 .95 .95 0 0 1-1.9 0zM122.7 59.8a.69 .69 0 0 0 0 1.1 .69 .69 0 0 0 1.1-.2 .68 .68 0 0 0-.2-.9 .68 .68 0 0 0-.9 0zM124.2 59.4h.3l.5 .9 .6-.9h.3l-.7 1.1v.7h-.3v-.7zM126.1 59.4h.3l.5 1.6 .6-1.6h.3v1.8h-.2v-1.5l-.5 1.5h-.3l-.5-1.5v1.5h-.2zM128.2 59.4h1.3v.2h-1.1v.6h1v.2h-1v.6h1.2v.2h-1.4zM129.9 59.4h.3l.9 1.5v-1.5h.2v1.8h-.3l-.9-1.4v1.4h-.2zM131.6 59.4h1.4v.2h-.6v1.6h-.2v-1.6h-.6zM133.1 61.4h1.4v.2h-1.4zM134.8 59.6a.81 .81 0 0 1 1.4 .4h-.2a.63 .63 0 0 0-.9-.3 .63 .63 0 0 0-.2 .8 .58 .58 0 0 0 .6 .6 .58 .58 0 0 0 .5-.6h-.5v-.2h.8v.9h-.2l-.1-.2a.89 .89 0 0 1-1.2 .1 .89 .89 0 0 1-.1-1.3zM136.6 59.4h.3l1 1.5v-1.5h.2v1.8h-.3l-.9-1.4v1.4h-.3zM138.7 59.6v1.4h.5a.71 .71 0 0 0 .5-.7 .71 .71 0 0 0-.5-.7zM138.5 59.4h.7a.92 .92 0 0 1 .8 .9 .92 .92 0 0 1-.8 .9h-.7z" fill-rule="evenodd"/>
<path d="M174.6 134.4a.72 .72 0 0 1 1.2 .4h-.2a.42 .42 0 0 0-.5-.4 .42 .42 0 0 0-.4 .4 1.47 1.47 0 0 1 1.2 .8 .74 .74 0 0 1-.8 .5 .74 .74 0 0 1-.7-.6h.2a.48 .48 0 0 0 .5 .4 .48 .48 0 0 0 .5-.4l-.4-.2a.56 .56 0 0 1-.6-.2 .56 .56 0 0 1 0-.7zM176.1 135.2a.94 .94 0 0 1 1.8 0 .94 .94 0 0 1-1.8 0zM176.5 134.6a.69 .69 0 0 0 0 1.1 .69 .69 0 0 0 1-.2 .68 .68 0 0 0-.1-.9 .68 .68 0 0 0-.9 0zM178.1 134.2h.3v1.7h.9v.2h-1.2zM180.2 134.5l-.3 .8h.6zM180.1 134.2h.3l.6 1.9h-.2l-.2-.6h-.8l-.1 .6h-.3zM181.5 134.5v.6h.6a.31 .31 0 0 0 .4-.3 .31 .31 0 0 0-.4-.3zM181.3 134.2a1.57 1.57 0 0 1 1.3 .2l.1 .5-.2 .3 .2 .2 .1 .7h-.3l-.1-.7-.3-.1h-.6v.8h-.2zM182.9 136.3h1.4v.1h-1.4zM184.5 134.2h.8a.53 .53 0 0 1 .6 .6 .53 .53 0 0 1-.6 .5h-.5v.8h-.3zM184.8 134.5v.6h.5a.32 .32 0 0 0 .3-.3 .32 .32 0 0 0-.3-.3zM186.7 134.5l-.3 .8h.5zM186.5 134.2h.3l.7 1.9h-.3l-.2-.6h-.7l-.2 .6h-.3zM187.7 134.2h.3l.9 1.5v-1.5h.2v1.9h-.2l-1-1.5v1.5h-.2zM189.6 134.2h1.3v.3h-1.1v.5h1v.2h-1v.7h1.1v.2h-1.3zM191.2 134.2h.3v1.7h.9v.2h-1.2zM192.4 136.3h1.5v.1h-1.5zM194.1 134.6l.7-.3v1.8h-.3v-1.3h-.4zM195.3 136.3h1.4v.1h-1.4zM197 134.4a.51 .51 0 0 1 .7 0 .51 .51 0 0 1 0 .7 .59 .59 0 0 1-.1 1 .59 .59 0 0 1-.9-.6h.3a.36 .36 0 0 0 .5 .4 .36 .36 0 0 0 0-.6h-.3l.1-.2a.29 .29 0 0 0 .4-.3 .29 .29 0 0 0-.3-.3l-.3 .1-.1 .3h-.2z" fill-rule="evenodd"/>
<path d="M32.7 56.9a.72 .72 0 0 1 1.2 .5h-.3a.42 .42 0 0 0-.4-.4 .42 .42 0 0 0-.4 .4 1.47 1.47 0 0 1 1.1 .7 .74 .74 0 0 1-.7 .6 .74 .74 0 0 1-.7-.6h.2a.48 .48 0 0 0 .5 .4 .48 .48 0 0 0 .4-.4l-.3-.2a.56 .56 0 0 1-.7-.3 .56 .56 0 0 1 .1-.7zM34.1 57.8a.95 .95 0 0 1 1.9 0 .95 .95 0 0 1-1.9 0zM34.6 57.2a.69 .69 0 0 0-.1 1.1 .69 .69 0 0 0 1.1-.2 .68 .68 0 0 0-.1-.9 .68 .68 0 0 0-.9 0zM36.2 56.8h.2v1.6h1v.3h-1.2zM38.3 57.1l-.3 .8h.5zM38.1 56.8h.3l.7 1.9h-.3l-.2-.6h-.7l-.2 .6h-.2zM39.6 57v.7h.6a.31 .31 0 0 0 .3-.3 .31 .31 0 0 0-.3-.4zM39.3 56.8a1.57 1.57 0 0 1 1.4 .2l.1 .5-.3 .3 .2 .2 .2 .7h-.4v-.7l-.4-.1h-.5v.8h-.3zM40.9 58.8h1.5v.2h-1.5zM42.6 56.8h.8a.53 .53 0 0 1 .5 .6 .53 .53 0 0 1-.5 .5h-.6v.8h-.2zM42.8 57v.7h.5a.32 .32 0 0 0 .4-.3 .32 .32 0 0 0-.4-.4zM44.7 57.1l-.3 .8h.6zM44.6 56.8h.3l.6 1.9h-.2l-.2-.6h-.7l-.2 .6h-.3zM45.8 56.8h.2l1 1.5v-1.5h.2v1.9h-.3l-.9-1.5v1.5h-.2zM47.6 56.8h1.3v.3h-1v.5h1v.2h-1v.6h1.1v.3h-1.4zM49.3 56.8h.2v1.6h1v.3h-1.2zM50.5 58.8h1.4v.2h-1.4zM52.2 57.2l.6-.3v1.8h-.2v-1.3h-.4zM53.3 58.8h1.4v.2h-1.4zM55 57a.51 .51 0 0 1 .8 0 .51 .51 0 0 1-.1 .7 .59 .59 0 0 1-.1 1 .59 .59 0 0 1-.8-.6h.2a.36 .36 0 0 0 .5 .4 .36 .36 0 0 0 .1-.6l-.3-.1v-.2a.29 .29 0 0 0 .4-.2 .29 .29 0 0 0-.3-.3l-.3 .1v.3h-.3z" fill-rule="evenodd"/>
<path d="M32.7 62.1a.72 .72 0 0 1 1.2 .4h-.3a.42 .42 0 0 0-.4-.3 .42 .42 0 0 0-.4 .4 1.47 1.47 0 0 1 1.1 .7 .74 .74 0 0 1-.7 .6 .74 .74 0 0 1-.7-.7h.2a.48 .48 0 0 0 .5 .5 .48 .48 0 0 0 .4-.5l-.3-.2a.56 .56 0 0 1-.7-.2 .56 .56 0 0 1 .1-.7zM34.1 62.9a.95 .95 0 0 1 1.9 0 .95 .95 0 0 1-1.9 0zM34.6 62.4a.69 .69 0 0 0-.1 1 .69 .69 0 0 0 1.1-.1 .68 .68 0 0 0-.1-1 .68 .68 0 0 0-.9 .1zM36.2 62h.2v1.6h1v.2h-1.2zM38.3 62.3l-.3 .8h.5zM38.1 62h.3l.7 1.8h-.3l-.2-.5h-.7l-.2 .5h-.2zM39.6 62.2v.6h.6a.31 .31 0 0 0 .3-.3 .31 .31 0 0 0-.3-.3zM39.3 62a1.57 1.57 0 0 1 1.4 .2l.1 .4-.3 .3 .2 .2 .2 .7h-.4v-.6l-.4-.2h-.5v.8h-.3zM40.9 64h1.5v.1h-1.5zM42.6 62h.8a.53 .53 0 0 1 .5 .5 .53 .53 0 0 1-.5 .5h-.6v.8h-.2zM42.8 62.2v.6h.5a.32 .32 0 0 0 .4-.3 .32 .32 0 0 0-.4-.3zM44.7 62.3l-.3 .8h.6zM44.6 62h.3l.6 1.8h-.2l-.2-.5h-.7l-.2 .5h-.3zM45.8 62h.2l1 1.5v-1.5h.2v1.8h-.3l-.9-1.5v1.5h-.2zM47.6 62h1.3v.2h-1v.6h1v.2h-1v.6h1.1v.2h-1.4zM49.3 62h.2v1.6h1v.2h-1.2zM50.5 64h1.4v.1h-1.4zM52.2 62.1a.61 .61 0 0 1 1 .3 .61 .61 0 0 1-.6 .8l-.4 .4h1v.2h-1.2a1.5 1.5 0 0 1 .9-1.1 .36 .36 0 0 0-.3-.5 .36 .36 0 0 0-.3 .5h-.3zM53.3 64h1.4v.1h-1.4zM55.6 62.4l-.6 .8h.6zM55.6 62h.2v1.2h.3v.2h-.3v.4h-.2v-.4h-.8v-.2z" fill-rule="evenodd"/>
<path d="M174.7 111.1a.96 .96 0 0 1 1.3 .3 .96 .96 0 0 1-.1 1.2l.2 .2-.1 .2-.3-.2a.96 .96 0 0 1-1.3-.4 .96 .96 0 0 1 .3-1.3zM174.8 111.4a.74 .74 0 0 0-.1 .9 .74 .74 0 0 0 .8 .3l-.2-.1 .2-.2 .2 .2a.72 .72 0 0 0 .1-1 .72 .72 0 0 0-1-.1zM176.6 111.3l.6-.2 .3 .3v.1h-.2a.37 .37 0 0 0-.4-.2 .37 .37 0 0 0-.3 .4v.2a.59 .59 0 0 1 .9 .2 .59 .59 0 0 1-.4 .9 .59 .59 0 0 1-.7-.7v-.6zM176.6 112.3a.4 .4 0 0 0 .8 0 .4 .4 0 0 0-.8 0zM177.7 113h1.4v.2h-1.4zM179.4 111.2a.81 .81 0 0 1 1.4 .4h-.2a.63 .63 0 0 0-.9-.3 .63 .63 0 0 0-.2 .9 .58 .58 0 0 0 .6 .5 .58 .58 0 0 0 .5-.6h-.5v-.2h.8v.9h-.2l-.1-.2a.89 .89 0 0 1-1.2 .1 .89 .89 0 0 1-.1-1.3zM181.3 111h.8a.53 .53 0 0 1 .5 .6 .53 .53 0 0 1-.5 .5h-.6v.7h-.2zM181.5 111.2v.7h.5a.32 .32 0 0 0 .4-.3 .32 .32 0 0 0-.4-.4zM183 111h.2v1.8h-.2zM183.5 112a.95 .95 0 0 1 1.9 0 .95 .95 0 0 1-1.9 0zM184 111.4a.69 .69 0 0 0 0 1.1 .69 .69 0 0 0 1-.2 .68 .68 0 0 0-.1-.9 .68 .68 0 0 0-.9 0zM185.4 113h1.4v.2h-1.4zM187.2 111.6a.3 .3 0 0 0 .6 0 .3 .3 0 0 0-.6 0zM187.2 112.4a.36 .36 0 0 0 .7 0 .36 .36 0 0 0-.7 0zM187.1 111.2a.5 .5 0 0 1 .8-.1 .5 .5 0 0 1 0 .8 .55 .55 0 0 1 .1 .8 .55 .55 0 0 1-.9 0 .55 .55 0 0 1 .1-.8l-.2-.4z" fill-rule="evenodd"/>
<path d="M234.1 142.1a.96 .96 0 0 1 1.3 .2 .96 .96 0 0 1-.2 1.3l.3 .2-.1 .2-.3-.3a.96 .96 0 0 1-1.3-.3 .96 .96 0 0 1 .3-1.3zM234.2 142.3a.74 .74 0 0 0-.2 1 .74 .74 0 0 0 .9 .3l-.2-.2 .1-.1 .3 .2a.72 .72 0 0 0 .1-1 .72 .72 0 0 0-1-.2zM235.9 142.2l.6-.2 .4 .3v.2h-.2a.37 .37 0 0 0-.5-.3 .37 .37 0 0 0-.2 .5l-.1 .2a.59 .59 0 0 1 1 .2 .59 .59 0 0 1-.5 .8 .59 .59 0 0 1-.7-.6v-.7zM236 143.3a.38 .38 0 0 0 .7 0 .38 .38 0 0 0-.7 0zM237 144h1.4v.1h-1.4zM238.8 142.2a.81 .81 0 0 1 1.4 .3h-.3a.63 .63 0 0 0-.8-.3 .63 .63 0 0 0-.3 .9 .58 .58 0 0 0 .6 .5 .58 .58 0 0 0 .6-.6h-.6v-.2h.8v1h-.1l-.1-.2a.89 .89 0 0 1-1.2 0 .89 .89 0 0 1-.1-1.2zM240.6 142h.8a.53 .53 0 0 1 .6 .5 .53 .53 0 0 1-.6 .5h-.5v.8h-.3zM240.9 142.2v.6h.5a.32 .32 0 0 0 .3-.3 .32 .32 0 0 0-.3-.3zM242.4 142h.2v1.8h-.2zM242.9 142.9a.95 .95 0 0 1 1.9 0 .95 .95 0 0 1-1.9 0zM243.3 142.4a.69 .69 0 0 0 0 1 .69 .69 0 0 0 1.1-.2 .68 .68 0 0 0-.1-.9 .68 .68 0 0 0-1 .1zM244.8 144h1.4v.1h-1.4zM246.4 142.4l.7-.4v1.8h-.2v-1.2h-.5zM247.9 142.1a.51 .51 0 0 1 .8 0 .51 .51 0 0 1-.1 .8 .59 .59 0 0 1-.1 1 .59 .59 0 0 1-.8-.6h.2a.36 .36 0 0 0 .5 .3 .36 .36 0 0 0 0-.6h-.2v-.2a.29 .29 0 0 0 .4-.2 .29 .29 0 0 0-.3-.4l-.3 .2-.1 .2h-.2z" fill-rule="evenodd"/>
<path d="M234.1 144.7a.96 .96 0 0 1 1.3 .2 .96 .96 0 0 1-.2 1.3l.3 .2-.1 .1-.3-.2a.96 .96 0 0 1-1.3-.3 .96 .96 0 0 1 .3-1.3zM234.2 144.9a.74 .74 0 0 0-.2 1 .74 .74 0 0 0 .9 .3l-.2-.2 .1-.1 .3 .2a.72 .72 0 0 0 .1-1 .72 .72 0 0 0-1-.2zM235.9 144.8l.6-.2 .4 .3v.2h-.2a.37 .37 0 0 0-.5-.3 .37 .37 0 0 0-.2 .5l-.1 .2a.59 .59 0 0 1 1 .2 .59 .59 0 0 1-.5 .8 .59 .59 0 0 1-.7-.6v-.7zM236 145.8a.38 .38 0 0 0 .7 0 .38 .38 0 0 0-.7 0zM237 146.6h1.4v.1h-1.4zM238.8 144.8a.81 .81 0 0 1 1.4 .3h-.3a.63 .63 0 0 0-.8-.3 .63 .63 0 0 0-.3 .9 .58 .58 0 0 0 .6 .5 .58 .58 0 0 0 .6-.6h-.6v-.2h.8v1h-.1l-.1-.2a.89 .89 0 0 1-1.2 0 .89 .89 0 0 1-.1-1.2zM240.6 144.6h.8a.53 .53 0 0 1 .6 .5 .53 .53 0 0 1-.6 .5h-.5v.8h-.3zM240.9 144.8v.6h.5a.32 .32 0 0 0 .3-.3 .32 .32 0 0 0-.3-.3zM242.4 144.6h.2v1.8h-.2zM242.9 145.5a.95 .95 0 0 1 1.9 0 .95 .95 0 0 1-1.9 0zM243.3 144.9a.69 .69 0 0 0 0 1.1 .69 .69 0 0 0 1.1-.2 .68 .68 0 0 0-.1-.9 .68 .68 0 0 0-1 0zM244.8 146.6h1.4v.1h-1.4zM246.4 145l.7-.4v1.8h-.2v-1.3h-.5zM248.5 145l-.6 .8h.6zM248.5 144.6h.2v1.2h.2v.2h-.2v.4h-.2v-.4h-.8v-.3z" fill-rule="evenodd"/>
<path d="M234.1 147.3a.96 .96 0 0 1 1.3 .2 .96 .96 0 0 1-.2 1.3l.3 .2-.1 .1-.3-.2a.96 .96 0 0 1-1.3-.3 .96 .96 0 0 1 .3-1.3zM234.2 147.5a.74 .74 0 0 0-.2 .9 .74 .74 0 0 0 .9 .4l-.2-.2 .1-.2 .3 .2a.72 .72 0 0 0 .1-1 .72 .72 0 0 0-1-.1zM235.9 147.4l.6-.2 .4 .3v.2h-.2a.37 .37 0 0 0-.5-.3 .37 .37 0 0 0-.2 .5l-.1 .2a.59 .59 0 0 1 1 .2 .59 .59 0 0 1-.5 .8 .59 .59 0 0 1-.7-.6v-.7zM236 148.4a.38 .38 0 0 0 .7 0 .38 .38 0 0 0-.7 0zM237 149.2h1.4v.1h-1.4zM238.8 147.4a.81 .81 0 0 1 1.4 .3h-.3a.63 .63 0 0 0-.8-.3 .63 .63 0 0 0-.3 .9 .58 .58 0 0 0 .6 .5 .58 .58 0 0 0 .6-.6h-.6v-.2h.8v1h-.1l-.1-.3a.89 .89 0 0 1-1.2 .1 .89 .89 0 0 1-.1-1.2zM240.6 147.2h.8a.53 .53 0 0 1 .6 .5 .53 .53 0 0 1-.6 .5h-.5v.8h-.3zM240.9 147.4v.6h.5a.32 .32 0 0 0 .3-.3 .32 .32 0 0 0-.3-.3zM242.4 147.2h.2v1.8h-.2zM242.9 148.1a.95 .95 0 0 1 1.9 0 .95 .95 0 0 1-1.9 0zM243.3 147.5a.69 .69 0 0 0 0 1.1 .69 .69 0 0 0 1.1-.2 .68 .68 0 0 0-.1-.9 .68 .68 0 0 0-1 0zM244.8 149.2h1.4v.1h-1.4zM246.4 147.5l.7-.3v1.8h-.2v-1.3h-.5zM247.9 147.2h.9v.2h-.7l-.1 .5a.62 .62 0 0 1 .9 .3 .62 .62 0 0 1-.4 .9 .62 .62 0 0 1-.8-.6h.2a.39 .39 0 0 0 .6 .2 .39 .39 0 0 0 .1-.6 .39 .39 0 0 0-.6 .1h-.2z" fill-rule="evenodd"/>
<path d="M174.7 106a.96 .96 0 0 1 1.3 .2 .96 .96 0 0 1-.1 1.3l.2 .2-.1 .1-.3-.2a.96 .96 0 0 1-1.3-.3 .96 .96 0 0 1 .3-1.3zM174.8 106.2a.74 .74 0 0 0-.1 1 .74 .74 0 0 0 .8 .3l-.2-.2 .2-.1 .2 .1a.72 .72 0 0 0 .1-1 .72 .72 0 0 0-1-.1zM176.6 106.1l.6-.2 .3 .3v.2h-.2a.37 .37 0 0 0-.4-.3 .37 .37 0 0 0-.3 .5v.2a.59 .59 0 0 1 .9 .2 .59 .59 0 0 1-.4 .8 .59 .59 0 0 1-.7-.6v-.7zM176.6 107.1a.4 .4 0 0 0 .8 0 .4 .4 0 0 0-.8 0zM177.7 107.9h1.4v.1h-1.4zM179.4 106.1a.81 .81 0 0 1 1.4 .3h-.2a.63 .63 0 0 0-.9-.3 .63 .63 0 0 0-.2 .9 .58 .58 0 0 0 .6 .5 .58 .58 0 0 0 .5-.6h-.5v-.2h.8v1h-.2l-.1-.2a.89 .89 0 0 1-1.2 0 .89 .89 0 0 1-.1-1.2zM181.3 105.9h.8a.53 .53 0 0 1 .5 .5 .53 .53 0 0 1-.5 .5h-.6v.8h-.2zM181.5 106.1v.6h.5a.32 .32 0 0 0 .4-.3 .32 .32 0 0 0-.4-.3zM183 105.9h.2v1.8h-.2zM183.5 106.8a.95 .95 0 0 1 1.9 0 .95 .95 0 0 1-1.9 0zM184 106.2a.69 .69 0 0 0 0 1.1 .69 .69 0 0 0 1-.2 .68 .68 0 0 0-.1-.9 .68 .68 0 0 0-.9 0zM185.4 107.9h1.4v.1h-1.4zM187.1 106.1l.7-.2 .3 .3v.2h-.2a.37 .37 0 0 0-.5-.3 .37 .37 0 0 0-.2 .5v.2a.59 .59 0 0 1 .9 .2 .59 .59 0 0 1-.4 .8 .59 .59 0 0 1-.7-.6v-.7zM187.2 107.1a.4 .4 0 0 0 .8 0 .4 .4 0 0 0-.8 0z" fill-rule="evenodd"/>
<path d="M174.5 123.9h.8a.53 .53 0 0 1 .6 .6 .53 .53 0 0 1-.6 .5h-.6v.7h-.2zM174.7 124.1v.7h.5a.32 .32 0 0 0 .4-.3 .32 .32 0 0 0-.4-.4zM176.3 124.2a.79 .79 0 0 1 .8-.3 .79 .79 0 0 1 .6 .6h-.3a.62 .62 0 0 0-.8-.3 .62 .62 0 0 0-.2 .9 .56 .56 0 0 0 .5 .5 .56 .56 0 0 0 .6-.5h.2a.85 .85 0 0 1-1.1 .7 .85 .85 0 0 1-.5-1.2zM177.8 125.9h1.4v.2h-1.4zM179.7 124a.96 .96 0 0 1 1.2 .3 .96 .96 0 0 1-.1 1.2l.3 .2-.1 .2-.3-.2a.96 .96 0 0 1-1.3-.4 .96 .96 0 0 1 .3-1.3zM179.7 124.3a.74 .74 0 0 0-.1 .9 .74 .74 0 0 0 .9 .3l-.2-.1 .1-.2 .2 .2a.72 .72 0 0 0 .1-1 .72 .72 0 0 0-1-.1zM181.5 124.2l.6-.2 .3 .3 .1 .1h-.3a.37 .37 0 0 0-.4-.2 .37 .37 0 0 0-.3 .4v.2a.59 .59 0 0 1 .9 .2 .59 .59 0 0 1-.4 .9 .59 .59 0 0 1-.7-.7v-.6zM181.5 125.2a.4 .4 0 0 0 .8 0 .4 .4 0 0 0-.8 0zM182.6 125.9h1.4v.2h-1.4zM184.5 124.1v.7h.6a.31 .31 0 0 0 .3-.3 .31 .31 0 0 0-.3-.4zM184.2 123.9a1.57 1.57 0 0 1 1.4 .2l.1 .5-.3 .3 .2 .2 .2 .6h-.3l-.1-.6-.3-.1h-.6v.7h-.3zM186.2 124a.72 .72 0 0 1 1.2 .5h-.3a.42 .42 0 0 0-.4-.4 .42 .42 0 0 0-.4 .4 1.47 1.47 0 0 1 1.1 .7 .74 .74 0 0 1-.7 .6 .74 .74 0 0 1-.7-.6h.2a.48 .48 0 0 0 .5 .4 .48 .48 0 0 0 .5-.4l-.4-.2a.56 .56 0 0 1-.7-.3 .56 .56 0 0 1 .1-.7zM187.9 124.1a.61 .61 0 0 1 .9 .3 .61 .61 0 0 1-.6 .8l-.3 .3h.9v.2h-1.2a1.5 1.5 0 0 1 1-1.1 .36 .36 0 0 0-.3-.4 .36 .36 0 0 0-.4 .4h-.2zM189.3 124.1a.51 .51 0 0 1 .7 0 .51 .51 0 0 1 0 .7 .59 .59 0 0 1-.2 1 .59 .59 0 0 1-.8-.6h.3a.36 .36 0 0 0 .5 .4 .36 .36 0 0 0 0-.7h-.3v-.2a.29 .29 0 0 0 .4-.2 .29 .29 0 0 0-.3-.3l-.3 .1v.3h-.2zM190.7 124.1a.61 .61 0 0 1 1 .3 .61 .61 0 0 1-.7 .8l-.3 .3h1v.2h-1.2a1.5 1.5 0 0 1 .9-1.1 .36 .36 0 0 0-.3-.4 .36 .36 0 0 0-.4 .4h-.2z" fill-rule="evenodd"/>
<path d="M86.6 203.8l.4-.2 .4 .1 .1 .3 .1 .7h.7v.3h-1.8zM86.9 203.9l-.2 .8h.7l-.1-.7zM86.6 202l.5-.2v.2a.62 .62 0 0 0-.3 .9 .62 .62 0 0 0 .8 .2 .56 .56 0 0 0 .6-.5 .56 .56 0 0 0-.5-.6v-.2a.85 .85 0 0 1 .6 1.1 .85 .85 0 0 1-1.2 .5 .84 .84 0 0 1-.5-1.4zM88.5 200.2h.1v1.5h-.1zM86.8 198.6a1.16 1.16 0 0 1 1.3 0l.2-.2 .2 .1-.2 .3a.94 .94 0 0 1-.4 1.2 .94 .94 0 0 1-1.2-.2 .94 .94 0 0 1 .1-1.2zM86.9 198.8a.7 .7 0 0 0 .4 1.1 .7 .7 0 0 0 .8-.9l-.1 .2-.2-.1 .2-.3-.5-.2zM86.7 197.1l.3-.1v.2a.37 .37 0 0 0-.2 .5 .37 .37 0 0 0 .4 .2h.2a.59 .59 0 0 1 .2-.9 .59 .59 0 0 1 .9 .5 .59 .59 0 0 1-.7 .7 .86 .86 0 0 1-1.2-1zM87.4 197.5a.4 .4 0 0 0 .8 0 .4 .4 0 0 0-.8 0zM88.5 195.4h.1v1.5h-.1zM86.9 194.1l-.2 .9h.6v-.9zM86.7 193.9l.5-.1 .2 .2 .2-.2 .7-.1v.3l-.6 .1-.1 .3v.6h.7v.2h-1.8a1.57 1.57 0 0 1 .2-1.3zM86.7 192.2l.3-.1v.2a.42 .42 0 0 0-.3 .5 .42 .42 0 0 0 .4 .4 1.47 1.47 0 0 1 .7-1.2 .74 .74 0 0 1 .6 .8 .74 .74 0 0 1-.7 .7v-.2a.48 .48 0 0 0 .5-.5 .48 .48 0 0 0-.5-.5l-.2 .4a.59 .59 0 0 1-.7 .7 .59 .59 0 0 1-.3-1zM86.7 190.8a.81 .81 0 0 1 1.2 .6l.2 .2v-1h.2v1.2a1.5 1.5 0 0 1-1.1-.9 .36 .36 0 0 0-.5 .3 .36 .36 0 0 0 .5 .4v.2a.61 .61 0 0 1-.6-.4 .61 .61 0 0 1 .1-.6zM86.7 189.4l.3-.1 .4 .2a.59 .59 0 0 1 1 .1 .59 .59 0 0 1-.6 .8v-.2a.36 .36 0 0 0 .4-.5 .36 .36 0 0 0-.7 0v.3l-.2-.1a.29 .29 0 0 0-.2-.4 .29 .29 0 0 0-.3 .3l.1 .3 .2 .1v.2a.59 .59 0 0 1-.5-.3 .59 .59 0 0 1 .1-.7zM86.7 187.9a.81 .81 0 0 1 1.2 .7l.2 .2v-1h.2v1.2a1.5 1.5 0 0 1-1.1-.9 .36 .36 0 0 0-.5 .3 .36 .36 0 0 0 .5 .3v.3a.61 .61 0 0 1-.6-.4 .61 .61 0 0 1 .1-.7z" fill-rule="evenodd"/>
<path d="M174.7 129.2a.96 .96 0 0 1 1.3 .2 .96 .96 0 0 1-.1 1.3l.2 .2-.1 .2-.3-.3a.96 .96 0 0 1-1.3-.3 .96 .96 0 0 1 .3-1.3zM174.8 129.4a.74 .74 0 0 0-.1 1 .74 .74 0 0 0 .8 .3l-.2-.2 .2-.1 .2 .2a.72 .72 0 0 0 .1-1 .72 .72 0 0 0-1-.2zM176.6 129.3l.6-.2 .3 .3v.2h-.2a.37 .37 0 0 0-.4-.3 .37 .37 0 0 0-.3 .5v.2a.59 .59 0 0 1 .9 .2 .59 .59 0 0 1-.4 .8 .59 .59 0 0 1-.7-.6v-.7zM176.6 130.4a.4 .4 0 0 0 .8 0 .4 .4 0 0 0-.8 0zM177.7 131.1h1.4v.1h-1.4zM179.3 129.1h.8a.53 .53 0 0 1 .6 .5 .53 .53 0 0 1-.6 .5h-.6v.8h-.2zM179.5 129.3v.6h.5a.32 .32 0 0 0 .4-.3 .32 .32 0 0 0-.4-.3zM181.1 129.3a.79 .79 0 0 1 .8-.3 .79 .79 0 0 1 .6 .6h-.3a.62 .62 0 0 0-.8-.3 .62 .62 0 0 0-.2 .9 .56 .56 0 0 0 .5 .5 .56 .56 0 0 0 .6-.5h.2a.85 .85 0 0 1-1.1 .7 .85 .85 0 0 1-.5-1.2zM182.6 131.1h1.4v.1h-1.4zM184.5 129.3v.6h.6a.31 .31 0 0 0 .3-.3 .31 .31 0 0 0-.3-.3zM184.2 129.1a1.57 1.57 0 0 1 1.4 .1l.1 .5-.3 .3 .2 .2 .2 .7h-.3l-.1-.6-.3-.2h-.6v.8h-.3zM186.2 129.2a.72 .72 0 0 1 1.2 .4h-.3a.42 .42 0 0 0-.4-.3 .42 .42 0 0 0-.4 .4 1.47 1.47 0 0 1 1.1 .7 .74 .74 0 0 1-.7 .6 .74 .74 0 0 1-.7-.7h.2a.48 .48 0 0 0 .5 .5 .48 .48 0 0 0 .5-.5l-.4-.2a.56 .56 0 0 1-.7-.2 .56 .56 0 0 1 .1-.7zM187.9 129.2a.61 .61 0 0 1 .9 .3 .61 .61 0 0 1-.6 .8l-.3 .4h.9v.2h-1.2a1.5 1.5 0 0 1 1-1.1 .36 .36 0 0 0-.3-.5 .36 .36 0 0 0-.4 .5h-.2zM189.3 129.2a.51 .51 0 0 1 .7 0 .51 .51 0 0 1 0 .8 .59 .59 0 0 1-.2 1 .59 .59 0 0 1-.8-.6h.3a.36 .36 0 0 0 .5 .3 .36 .36 0 0 0 0-.6h-.3v-.2a.29 .29 0 0 0 .4-.2 .29 .29 0 0 0-.3-.4l-.3 .2v.2h-.2zM190.7 129.2a.61 .61 0 0 1 1 .3 .61 .61 0 0 1-.7 .8l-.3 .4h1v.2h-1.2a1.5 1.5 0 0 1 .9-1.1 .36 .36 0 0 0-.3-.5 .36 .36 0 0 0-.4 .5h-.2z" fill-rule="evenodd"/>
<path d="M76.4 203.5a1.16 1.16 0 0 1 1.4 .1l.2-.3 .2 .2-.3 .2a.94 .94 0 0 1-.3 1.2 .94 .94 0 0 1-1.2-.1 .94 .94 0 0 1 0-1.3zM76.6 203.7a.7 .7 0 0 0 .4 1.1 .7 .7 0 0 0 .8-.9l-.2 .2-.1-.1 .2-.2-.5-.2zM76.4 202.1l.3-.2v.3a.37 .37 0 0 0-.3 .4 .37 .37 0 0 0 .5 .3h.2a.59 .59 0 0 1 .2-.9 .59 .59 0 0 1 .8 .4 .59 .59 0 0 1-.6 .7 .86 .86 0 0 1-1.2-.9zM77.1 202.5a.38 .38 0 0 0 .7 0 .38 .38 0 0 0-.7 0zM78.2 200.4h.1v1.4h-.1zM76.3 199l.4-.2 .4 .1 .1 .3v.7h.8v.3h-1.8zM76.5 199.1l-.1 .8h.6v-.7zM76.3 197.2l.4-.2v.2a.62 .62 0 0 0-.3 .9 .62 .62 0 0 0 .9 .2 .56 .56 0 0 0 .5-.5 .56 .56 0 0 0-.5-.6v-.2a.85 .85 0 0 1 .7 1.1 .85 .85 0 0 1-1.2 .5 .84 .84 0 0 1-.5-1.4zM78.2 195.4h.1v1.5h-.1zM76.5 194.1l-.1 .9h.6v-.9zM76.3 193.9l.5-.1 .3 .2 .2-.2 .7-.1v.3l-.6 .1-.2 .3v.6h.8v.2h-1.8a1.57 1.57 0 0 1 .1-1.3zM76.4 192.2l.3-.1v.2a.42 .42 0 0 0-.3 .5 .42 .42 0 0 0 .4 .4 1.47 1.47 0 0 1 .7-1.2 .74 .74 0 0 1 .6 .8 .74 .74 0 0 1-.7 .7v-.2a.48 .48 0 0 0 .5-.5 .48 .48 0 0 0-.5-.5l-.2 .4a.59 .59 0 0 1-.7 .7 .59 .59 0 0 1-.3-1zM76.4 190.8a.81 .81 0 0 1 1.2 .6l.2 .2v-1h.2v1.2a1.5 1.5 0 0 1-1.1-.9 .36 .36 0 0 0-.5 .3 .36 .36 0 0 0 .5 .4v.2a.61 .61 0 0 1-.6-.4 .61 .61 0 0 1 .1-.6zM76.4 189.4l.3-.1 .4 .2a.59 .59 0 0 1 1 .1 .59 .59 0 0 1-.6 .8v-.2a.36 .36 0 0 0 .3-.5 .36 .36 0 0 0-.6 0v.3l-.2-.1a.29 .29 0 0 0-.2-.4 .29 .29 0 0 0-.4 .3l.2 .3 .2 .1v.2a.59 .59 0 0 1-.5-.3 .59 .59 0 0 1 .1-.7zM76.4 187.9a.81 .81 0 0 1 1.2 .7l.2 .2v-1h.2v1.2a1.5 1.5 0 0 1-1.1-.9 .36 .36 0 0 0-.5 .3 .36 .36 0 0 0 .5 .3v.3a.61 .61 0 0 1-.6-.4 .61 .61 0 0 1 .1-.7z" fill-rule="evenodd"/>
<path d="M234.1 100.9v.6h.4a.3 .3 0 0 0 .4-.3 .3 .3 0 0 0-.4-.3zM234.1 101.7v.6l.8-.1 .1-.2-.2-.3zM233.8 100.7h.8a.45 .45 0 0 1 .5 .3 .45 .45 0 0 1-.2 .5 .51 .51 0 0 1 .3 .7 .51 .51 0 0 1-.6 .3h-.8zM236.2 101l-.3 .8h.6zM236.1 100.7h.2l.7 1.8h-.3l-.2-.5h-.7l-.2 .5h-.2zM236.9 100.7h1.5v.2h-.7v1.6h-.2v-1.6h-.6zM238.4 100.7h1.5v.2h-.6v1.6h-.3v-1.6h-.6zM240.2 100.7h1.3v.2h-1.1v.6h1v.2h-1v.6h1.1v.2h-1.3zM242.1 100.9v.6h.6a.31 .31 0 0 0 .3-.3 .31 .31 0 0 0-.3-.3zM241.9 100.7a1.57 1.57 0 0 1 1.3 .2l.1 .4-.3 .3 .2 .2 .2 .7h-.3l-.1-.6-.3-.2h-.6v.8h-.2zM243.5 100.7h.3l.5 .9 .5-.9h.3l-.7 1.1v.7h-.2v-.7zM245.1 102.7h1.4v.1h-1.4zM246.7 100.7h.3v.8h.9v-.8h.3v1.8h-.3v-.8h-.9v.8h-.3zM248.6 100.7h1.3v.2h-1.1v.6h1v.2h-1v.6h1.1v.2h-1.3zM250.9 101l-.3 .8h.6zM250.8 100.7h.3l.6 1.8h-.3l-.1-.5h-.8l-.2 .5h-.2zM251.6 100.7h1.5v.2h-.6v1.6h-.3v-1.6h-.6zM253.3 100.7h1.4v.2h-1.1v.6h1v.2h-1v.6h1.1v.2h-1.4zM255.3 100.9v.6h.5a.31 .31 0 0 0 .4-.3 .31 .31 0 0 0-.3-.3zM255 100.7a1.57 1.57 0 0 1 1.4 .2l.1 .4-.3 .3 .2 .2 .1 .7h-.3v-.6l-.4-.2h-.5v.8h-.3zM256.6 102.7h1.5v.1h-1.5zM258.7 101.2h.2v.6h.6v.2h-.6v.5h-.2v-.5h-.5v-.2h.5zM259.6 100.7h.3l.5 1.6 .5-1.6h.3l-.7 1.8h-.2z" fill-rule="evenodd"/>
<path d="M234.1 103.5v.6h.4a.3 .3 0 0 0 .4-.3 .3 .3 0 0 0-.4-.3zM234.1 104.3v.6l.8-.1 .1-.2-.2-.3zM233.8 103.3h.8a.45 .45 0 0 1 .5 .3 .45 .45 0 0 1-.2 .5 .51 .51 0 0 1 .3 .7 .51 .51 0 0 1-.6 .3h-.8zM236.2 103.6l-.3 .8h.6zM236.1 103.3h.2l.7 1.8h-.3l-.2-.5h-.7l-.2 .5h-.2zM236.9 103.3h1.5v.2h-.7v1.6h-.2v-1.6h-.6zM238.4 103.3h1.5v.2h-.6v1.6h-.3v-1.6h-.6zM240.2 103.3h1.3v.2h-1.1v.6h1v.2h-1v.6h1.1v.2h-1.3zM242.1 103.5v.6h.6a.31 .31 0 0 0 .3-.3 .31 .31 0 0 0-.3-.3zM241.9 103.3a1.57 1.57 0 0 1 1.3 .1l.1 .5-.3 .3 .2 .2 .2 .7h-.3l-.1-.7-.3-.1h-.6v.8h-.2zM243.5 103.3h.3l.5 .9 .5-.9h.3l-.7 1.1v.7h-.2v-.7zM245.1 105.3h1.4v.1h-1.4zM246.7 103.3h.3v.7h.9v-.7h.3v1.8h-.3v-.8h-.9v.8h-.3zM248.6 103.3h1.3v.2h-1.1v.6h1v.2h-1v.6h1.1v.2h-1.3zM250.9 103.6l-.3 .8h.6zM250.8 103.3h.3l.6 1.8h-.3l-.1-.5h-.8l-.2 .5h-.2zM251.6 103.3h1.5v.2h-.6v1.6h-.3v-1.6h-.6zM253.3 103.3h1.4v.2h-1.1v.6h1v.2h-1v.6h1.1v.2h-1.4zM255.3 103.5v.6h.5a.31 .31 0 0 0 .4-.3 .31 .31 0 0 0-.3-.3zM255 103.3a1.57 1.57 0 0 1 1.4 .1l.1 .5-.3 .3 .2 .2 .1 .7h-.3v-.7l-.4-.1h-.5v.8h-.3zM256.6 105.3h1.5v.1h-1.5zM258.2 104.3h.6v.2h-.6zM259 103.3h.2l.6 1.5 .5-1.5h.3l-.7 1.8h-.3z" fill-rule="evenodd"/>
<path d="M234.1 106.1v.5h.4a.3 .3 0 0 0 .4-.3 .3 .3 0 0 0-.4-.2zM234.1 106.8v.7l.8-.2 .1-.2-.2-.2zM233.8 105.9h.8a.45 .45 0 0 1 .5 .3 .45 .45 0 0 1-.2 .5 .51 .51 0 0 1 .3 .6 .51 .51 0 0 1-.6 .4h-.8zM236.2 106.1l-.3 .8h.6zM236.1 105.9h.2l.7 1.8h-.3l-.2-.6h-.7l-.2 .6h-.2zM236.9 105.9h1.5v.2h-.7v1.6h-.2v-1.6h-.6zM238.4 105.9h1.5v.2h-.6v1.6h-.3v-1.6h-.6zM240.2 105.9h1.3v.2h-1.1v.5h1v.3h-1v.6h1.1v.2h-1.3zM242.1 106.1v.6h.6a.31 .31 0 0 0 .3-.3 .31 .31 0 0 0-.3-.3zM241.9 105.9a1.57 1.57 0 0 1 1.3 .1l.1 .5-.3 .3 .2 .2 .2 .7h-.3l-.1-.7-.3-.1h-.6v.8h-.2zM243.5 105.9h.3l.5 .8 .5-.8h.3l-.7 1.1v.7h-.2v-.7zM245.1 107.9h1.4v.1h-1.4zM246.6 105.9h1.4v.2h-.6v1.6h-.2v-1.6h-.6zM248.3 105.9h.2v.7h1v-.7h.2v1.8h-.2v-.9h-1v.9h-.2zM250.4 106.1v.6h.6a.31 .31 0 0 0 .3-.3 .31 .31 0 0 0-.3-.3zM250.1 105.9a1.57 1.57 0 0 1 1.4 .1l.1 .5-.3 .3 .2 .2 .2 .7h-.4v-.7l-.4-.1h-.5v.8h-.3zM251.9 105.9h.4l.5 1.5 .5-1.5h.4v1.8h-.3l.1-1.6-.6 1.6h-.2l-.5-1.6v1.6h-.3zM254.2 106a.72 .72 0 0 1 1.2 .4h-.2a.42 .42 0 0 0-.5-.4 .42 .42 0 0 0-.4 .5 1.47 1.47 0 0 1 1.1 .7 .74 .74 0 0 1-.7 .5 .74 .74 0 0 1-.7-.6h.2a.48 .48 0 0 0 .5 .4 .48 .48 0 0 0 .5-.4l-.4-.2a.56 .56 0 0 1-.7-.2 .56 .56 0 0 1 .1-.7zM255.6 105.9h1.5v.2h-.6v1.6h-.3v-1.6h-.6zM257.2 106.8a.94 .94 0 0 1 1.8 0 .94 .94 0 0 1-1.8 0zM257.6 106.2a.69 .69 0 0 0 0 1.1 .69 .69 0 0 0 1-.2 .68 .68 0 0 0-.1-.9 .68 .68 0 0 0-.9 0zM259.5 106.1v.6h.6a.31 .31 0 0 0 .4-.3 .31 .31 0 0 0-.4-.3zM259.3 105.9a1.57 1.57 0 0 1 1.3 .1l.1 .5-.2 .3 .2 .2 .1 .7h-.3l-.1-.7-.3-.1h-.6v.8h-.2zM260.9 107.9h1.4v.1h-1.4zM262.9 106.4h.3v.5h.5v.2h-.5v.6h-.3v-.6h-.5v-.2h.5zM263.8 105.9h.3l.5 1.5 .5-1.5h.3l-.6 1.8h-.3z" fill-rule="evenodd"/>
<path d="M234.1 108.6v.6h.4a.3 .3 0 0 0 .4-.3 .3 .3 0 0 0-.4-.3zM234.1 109.4v.7l.8-.2 .1-.2-.2-.2zM233.8 108.4h.8a.45 .45 0 0 1 .5 .3 .45 .45 0 0 1-.2 .6 .51 .51 0 0 1 .3 .6 .51 .51 0 0 1-.6 .4h-.8zM236.2 108.7l-.3 .8h.6zM236.1 108.4h.2l.7 1.9h-.3l-.2-.6h-.7l-.2 .6h-.2zM236.9 108.4h1.5v.3h-.7v1.6h-.2v-1.6h-.6zM238.4 108.4h1.5v.3h-.6v1.6h-.3v-1.6h-.6zM240.2 108.4h1.3v.3h-1.1v.5h1v.2h-1v.6h1.1v.3h-1.3zM242.1 108.7v.6h.6a.31 .31 0 0 0 .3-.3 .31 .31 0 0 0-.3-.3zM241.9 108.4a1.57 1.57 0 0 1 1.3 .2l.1 .5-.3 .3 .2 .2 .2 .7h-.3l-.1-.7-.3-.1h-.6v.8h-.2zM243.5 108.4h.3l.5 .9 .5-.9h.3l-.7 1.1v.8h-.2v-.8zM245.1 110.5h1.4v.1h-1.4zM246.6 108.4h1.4v.3h-.6v1.6h-.2v-1.6h-.6zM248.3 108.4h.2v.8h1v-.8h.2v1.9h-.2v-.9h-1v.9h-.2zM250.4 108.7v.6h.6a.31 .31 0 0 0 .3-.3 .31 .31 0 0 0-.3-.3zM250.1 108.4a1.57 1.57 0 0 1 1.4 .2l.1 .5-.3 .3 .2 .2 .2 .7h-.4v-.7l-.4-.1h-.5v.8h-.3zM251.9 108.4h.4l.5 1.6 .5-1.6h.4v1.9h-.3l.1-1.6-.6 1.6h-.2l-.5-1.6v1.6h-.3zM254.2 108.6a.72 .72 0 0 1 1.2 .4h-.2a.42 .42 0 0 0-.5-.4 .42 .42 0 0 0-.4 .4 1.47 1.47 0 0 1 1.1 .8 .74 .74 0 0 1-.7 .5 .74 .74 0 0 1-.7-.6h.2a.48 .48 0 0 0 .5 .4 .48 .48 0 0 0 .5-.4l-.4-.2a.56 .56 0 0 1-.7-.2 .56 .56 0 0 1 .1-.7zM255.6 108.4h1.5v.3h-.6v1.6h-.3v-1.6h-.6zM257.2 109.4a.94 .94 0 0 1 1.8 0 .94 .94 0 0 1-1.8 0zM257.6 108.8a.69 .69 0 0 0 0 1.1 .69 .69 0 0 0 1-.2 .68 .68 0 0 0-.1-.9 .68 .68 0 0 0-.9 0zM259.5 108.7v.6h.6a.31 .31 0 0 0 .4-.3 .31 .31 0 0 0-.4-.3zM259.3 108.4a1.57 1.57 0 0 1 1.3 .2l.1 .5-.2 .3 .2 .2 .1 .7h-.3l-.1-.7-.3-.1h-.6v.8h-.2zM260.9 110.5h1.4v.1h-1.4zM262.4 109.4h.6v.3h-.6zM263.2 108.4h.3l.5 1.6 .5-1.6h.3l-.7 1.9h-.2z" fill-rule="evenodd"/>
<path d="M233.8 149.7h.3l.9 1.5v-1.5h.3v1.9h-.3l-.9-1.5v1.5h-.3zM236.2 150.8v.6a.33 .33 0 0 0 .4-.3 .33 .33 0 0 0-.4-.3zM235.9 150l-.1 .3 .3 .2v-.6zM235.7 149.9l.4-.1v-.2l.1 .1a.49 .49 0 0 1 .5 .5h-.2l-.3-.3v.6a.53 .53 0 0 1 .6 .6 .53 .53 0 0 1-.6 .5v.2h-.1v-.2l-.4-.1-.1-.3-.1-.2h.3v.3l.3 .1v-.7a.49 .49 0 0 1-.5-.2 .49 .49 0 0 1 .1-.6zM237.2 149.9a.61 .61 0 0 1 1 .3 .61 .61 0 0 1-.6 .8l-.4 .3h1v.3h-1.2a1.5 1.5 0 0 1 .9-1.2 .36 .36 0 0 0-.3-.4 .36 .36 0 0 0-.4 .4h-.2z" fill-rule="evenodd"/>
<path d="M159 56.8h.3l.6 1.6 .5-1.6h.3v1.9h-.2v-1.6l-.5 1.6h-.3l-.5-1.6v1.6h-.2zM161.1 56.8h1.4v.3h-1.1v.5h1v.2h-1v.6h1.1v.3h-1.4zM162.9 57.1a.79 .79 0 0 1 .8-.3 .79 .79 0 0 1 .6 .6h-.2a.62 .62 0 0 0-.9-.3 .62 .62 0 0 0-.2 .9 .56 .56 0 0 0 .5 .5 .56 .56 0 0 0 .6-.5h.2a.85 .85 0 0 1-1.1 .7 .85 .85 0 0 1-.5-1.2zM164.6 56.8h.3v.8h.9v-.8h.3v1.9h-.3v-.9h-.9v.9h-.3zM166.3 58.8h1.4v.2h-1.4zM168.1 57v1.4h.5a.71 .71 0 0 0 .5-.7 .71 .71 0 0 0-.5-.7zM167.9 56.8h.7a.92 .92 0 0 1 .8 .9 .92 .92 0 0 1-.8 1h-.7zM169.7 56.8h1.4v.3h-1.1v.5h1v.2h-1v.6h1.1v.3h-1.4zM171.4 56.8h.8a.53 .53 0 0 1 .6 .6 .53 .53 0 0 1-.6 .5h-.5v.8h-.3zM171.7 57v.7h.5a.32 .32 0 0 0 .3-.3 .32 .32 0 0 0-.3-.4zM173.1 56.8h.2v1.6h1v.3h-1.2zM174.4 57.8a.95 .95 0 0 1 1.9 0 .95 .95 0 0 1-1.9 0zM174.9 57.2a.69 .69 0 0 0-.1 1.1 .69 .69 0 0 0 1.1-.2 .68 .68 0 0 0-.1-.9 .68 .68 0 0 0-.9 0zM176.3 56.8h.3l.6 .9 .5-.9h.3l-.7 1.1v.8h-.3v-.8zM178 58.8h1.4v.2h-1.4zM179.8 56.9a.72 .72 0 0 1 1.1 .5h-.2a.42 .42 0 0 0-.5-.4 .42 .42 0 0 0-.4 .4 1.47 1.47 0 0 1 1.2 .7 .74 .74 0 0 1-.8 .6 .74 .74 0 0 1-.7-.6h.3a.48 .48 0 0 0 .4 .4 .48 .48 0 0 0 .5-.4l-.4-.2a.56 .56 0 0 1-.6-.3 .56 .56 0 0 1 .1-.7zM181.1 56.8h.3l.4 1.5 .4-1.5h.2l.4 1.5 .4-1.5h.3l-.5 1.9h-.3l-.4-1.6-.4 1.6h-.3zM183.7 56.8h.3v1.9h-.3zM184.2 56.8h1.5v.2h-.6v1.7h-.2v-1.7h-.7zM186.1 57.1a.79 .79 0 0 1 .8-.3 .79 .79 0 0 1 .6 .6h-.3a.62 .62 0 0 0-.8-.3 .62 .62 0 0 0-.3 .9 .56 .56 0 0 0 .6 .5 .56 .56 0 0 0 .5-.5h.3a.85 .85 0 0 1-1.1 .7 .85 .85 0 0 1-.5-1.2zM187.8 56.8h.2v.8h1v-.8h.2v1.9h-.2v-.9h-1v.9h-.2zM189.4 58.8h1.4v.2h-1.4zM191.5 57.4h.2v.5h.5v.2h-.5v.6h-.2v-.6h-.6v-.2h.6zM192.4 56.8h.3l.5 1.6 .5-1.6h.3l-.7 1.9h-.3z" fill-rule="evenodd"/>
<path d="M227.4 18.1h.3l.9 1.5v-1.5h.2v1.8h-.3l-.9-1.4v1.4h-.2zM229.8 19.2v.6a.33 .33 0 0 0 .3-.3 .33 .33 0 0 0-.3-.3zM229.4 18.4v.3l.3 .2v-.6zM229.3 18.3l.4-.2v-.1l.1 .1a.49 .49 0 0 1 .5 .5h-.2l-.3-.3v.6a.53 .53 0 0 1 .5 .6 .53 .53 0 0 1-.5 .5v.2h-.1v-.2l-.4-.1-.2-.3v-.2h.2l.1 .3 .3 .1v-.7a.49 .49 0 0 1-.5-.3 .49 .49 0 0 1 .1-.5zM230.7 18.5l.6-.3v1.7h-.2v-1.2h-.4zM231.9 18.5l.7-.3v1.7h-.3v-1.2h-.4z" fill-rule="evenodd"/>
<path d="M159 80.1h.3l.9 1.4v-1.4h.2v1.8h-.2l-1-1.5v1.5h-.2zM161.4 81.1v.7a.33 .33 0 0 0 .3-.4 .33 .33 0 0 0-.3-.3zM161 80.4v.3l.3 .1v-.5zM160.9 80.2l.4-.1v-.2l.1 .2a.49 .49 0 0 1 .5 .5h-.2l-.3-.3v.6a.53 .53 0 0 1 .5 .5 .53 .53 0 0 1-.5 .5v.3h-.1v-.3l-.4-.1-.2-.3v-.2h.2l.1 .3 .3 .1v-.6a.49 .49 0 0 1-.5-.3 .49 .49 0 0 1 .1-.6zM162.3 80.5l.6-.4v1.8h-.2v-1.3h-.4zM163.8 80.2a.51 .51 0 0 1 .7 0 .51 .51 0 0 1 0 .7 .59 .59 0 0 1-.2 1 .59 .59 0 0 1-.8-.6h.2a.36 .36 0 0 0 .6 .4 .36 .36 0 0 0 0-.6h-.3v-.2a.29 .29 0 0 0 .4-.2 .29 .29 0 0 0-.3-.4l-.3 .2v.2h-.2z" fill-rule="evenodd"/>
<path d="M159 62h.3l.9 1.5v-1.5h.2v1.8h-.2l-1-1.5v1.5h-.2zM161.4 63v.7a.33 .33 0 0 0 .3-.3 .33 .33 0 0 0-.3-.4zM161 62.3v.3l.3 .2v-.6zM160.9 62.2l.4-.2v-.2l.1 .2a.49 .49 0 0 1 .5 .5h-.2l-.3-.3v.6a.53 .53 0 0 1 .5 .5 .53 .53 0 0 1-.5 .6v.2h-.1v-.2l-.4-.2-.2-.2v-.2h.2l.1 .2 .3 .2v-.7a.49 .49 0 0 1-.5-.3 .49 .49 0 0 1 .1-.5zM162.9 62.4l-.6 .8h.6zM162.9 62h.2v1.2h.3v.2h-.3v.4h-.2v-.4h-.8v-.2z" fill-rule="evenodd"/>
<path d="M226.1 82.6h1.3v.3h-1v.5h1v.2h-1v.6h1.1v.3h-1.4zM227.7 82.6h.3l.5 .7 .4-.7h.3l-.6 .9 .6 1h-.3l-.5-.8-.5 .8h-.3l.7-1zM229.3 82.6h1.5v.3h-.6v1.6h-.3v-1.6h-.6zM231 82.6h1.4v.3h-1.1v.5h1v.2h-1v.6h1.1v.3h-1.4zM233 82.9v.6h.6a.31 .31 0 0 0 .3-.3 .31 .31 0 0 0-.3-.3zM232.7 82.6a1.57 1.57 0 0 1 1.4 .2l.1 .5-.3 .3 .2 .2 .2 .7h-.3l-.1-.7-.3-.1h-.6v.8h-.3zM234.6 82.6h.2l1 1.5v-1.5h.2v1.9h-.3l-.9-1.5v1.5h-.2zM237 82.9l-.2 .8h.5zM236.9 82.6h.3l.7 1.9h-.3l-.2-.6h-.7l-.2 .6h-.3zM238.1 82.6h.2v1.6h1v.3h-1.2zM239.3 84.7h1.4v.1h-1.4zM240.9 82.6h.9a.53 .53 0 0 1 .5 .6 .53 .53 0 0 1-.5 .5h-.6v.8h-.3zM241.2 82.9v.6h.5a.32 .32 0 0 0 .3-.3 .32 .32 0 0 0-.3-.3zM242.5 83.6a.95 .95 0 0 1 1.9 0 .95 .95 0 0 1-1.9 0zM242.9 83a.69 .69 0 0 0 0 1.1 .69 .69 0 0 0 1.1-.2 .68 .68 0 0 0-.2-.9 .68 .68 0 0 0-.9 0zM244.4 82.6h.3l.3 1.5 .5-1.5h.2l.4 1.5 .4-1.5h.2l-.4 1.9h-.3l-.4-1.6-.4 1.6h-.3zM247 82.6h1.3v.3h-1.1v.5h1v.2h-1v.6h1.1v.3h-1.3zM248.9 82.9v.6h.6a.31 .31 0 0 0 .4-.3 .31 .31 0 0 0-.4-.3zM248.7 82.6a1.57 1.57 0 0 1 1.3 .2l.1 .5-.2 .3 .2 .2 .1 .7h-.3l-.1-.7-.3-.1h-.6v.8h-.2zM250.3 84.7h1.4v.1h-1.4zM252.1 82.8a.81 .81 0 0 1 1.4 .4h-.3a.63 .63 0 0 0-.8-.3 .63 .63 0 0 0-.3 .9 .58 .58 0 0 0 .6 .5 .58 .58 0 0 0 .6-.6h-.6v-.2h.8v1h-.2v-.3a.89 .89 0 0 1-1.2 .1 .89 .89 0 0 1-.1-1.2zM253.9 82.6h.3l.9 1.5v-1.5h.2v1.9h-.2l-1-1.5v1.5h-.2zM256 82.9v1.3h.4a.71 .71 0 0 0 .6-.7 .71 .71 0 0 0-.6-.6zM255.7 82.6h.8a.92 .92 0 0 1 .7 1 .92 .92 0 0 1-.7 .9h-.8z" fill-rule="evenodd"/>
<path d="M174.7 113.7a.96 .96 0 0 1 1.3 .2 .96 .96 0 0 1-.1 1.3l.2 .2-.1 .2-.3-.2a.96 .96 0 0 1-1.3-.4 .96 .96 0 0 1 .3-1.3zM174.8 114a.74 .74 0 0 0-.1 .9 .74 .74 0 0 0 .8 .3l-.2-.1 .2-.2 .2 .2a.72 .72 0 0 0 .1-1 .72 .72 0 0 0-1-.1zM176.6 113.8l.6-.1 .3 .3v.1h-.2a.37 .37 0 0 0-.4-.3 .37 .37 0 0 0-.3 .5v.2a.59 .59 0 0 1 .9 .2 .59 .59 0 0 1-.4 .8 .59 .59 0 0 1-.7-.6v-.6zM176.6 114.9a.4 .4 0 0 0 .8 0 .4 .4 0 0 0-.8 0zM177.7 115.6h1.4v.1h-1.4zM179.4 113.8a.81 .81 0 0 1 1.4 .4h-.2a.63 .63 0 0 0-.9-.3 .63 .63 0 0 0-.2 .8 .58 .58 0 0 0 .6 .6 .58 .58 0 0 0 .5-.6h-.5v-.2h.8v.9h-.2l-.1-.2a.89 .89 0 0 1-1.2 0 .89 .89 0 0 1-.1-1.2zM181.3 113.6h.8a.53 .53 0 0 1 .5 .5 .53 .53 0 0 1-.5 .6h-.6v.7h-.2zM181.5 113.8v.6h.5a.32 .32 0 0 0 .4-.3 .32 .32 0 0 0-.4-.3zM183 113.6h.2v1.8h-.2zM183.5 114.5a.95 .95 0 0 1 1.9 0 .95 .95 0 0 1-1.9 0zM184 114a.69 .69 0 0 0 0 1 .69 .69 0 0 0 1-.1 .68 .68 0 0 0-.1-.9 .68 .68 0 0 0-.9 0zM185.4 115.6h1.4v.1h-1.4zM187.1 113.8a.64 .64 0 0 1 .8 0 .64 .64 0 0 1 .2 .7 .66 .66 0 0 1-.5 1 .66 .66 0 0 1-.7-.9zM187.4 113.9a.93 .93 0 0 0 .1 1.4 .86 .86 0 0 0 0-1.4z" fill-rule="evenodd"/>
<path d="M159 82.6h1.3v.3h-1v.5h1v.2h-1v.6h1.1v.3h-1.4zM160.6 82.6h.3l.5 .7 .4-.7h.3l-.6 .9 .6 1h-.3l-.5-.8-.5 .8h-.3l.7-1zM162.2 82.6h1.5v.3h-.6v1.6h-.3v-1.6h-.6zM164 82.6h1.3v.3h-1.1v.5h1v.2h-1v.6h1.1v.3h-1.3zM165.9 82.9v.6h.6a.31 .31 0 0 0 .3-.3 .31 .31 0 0 0-.3-.3zM165.7 82.6a1.57 1.57 0 0 1 1.3 .2l.1 .5-.3 .3 .2 .2 .2 .7h-.3l-.1-.7-.3-.1h-.6v.8h-.2zM167.5 82.6h.2l1 1.5v-1.5h.2v1.9h-.3l-.9-1.5v1.5h-.2zM169.9 82.9l-.2 .8h.5zM169.8 82.6h.3l.7 1.9h-.3l-.2-.6h-.7l-.2 .6h-.3zM171 82.6h.2v1.6h1v.3h-1.2zM172.2 84.7h1.4v.1h-1.4zM173.8 82.6h.9a.53 .53 0 0 1 .5 .6 .53 .53 0 0 1-.5 .5h-.6v.8h-.3zM174.1 82.9v.6h.5a.32 .32 0 0 0 .3-.3 .32 .32 0 0 0-.3-.3zM175.4 83.6a.95 .95 0 0 1 1.9 0 .95 .95 0 0 1-1.9 0zM175.8 83a.69 .69 0 0 0 0 1.1 .69 .69 0 0 0 1.1-.2 .68 .68 0 0 0-.1-.9 .68 .68 0 0 0-1 0zM177.3 82.6h.3l.3 1.5 .5-1.5h.2l.4 1.5 .4-1.5h.2l-.4 1.9h-.3l-.4-1.6-.4 1.6h-.3zM179.9 82.6h1.3v.3h-1.1v.5h1v.2h-1v.6h1.1v.3h-1.3zM181.8 82.9v.6h.6a.31 .31 0 0 0 .4-.3 .31 .31 0 0 0-.4-.3zM181.6 82.6a1.57 1.57 0 0 1 1.3 .2l.1 .5-.2 .3 .2 .2 .1 .7h-.3l-.1-.7-.3-.1h-.6v.8h-.2zM183.2 84.7h1.4v.1h-1.4zM185.3 83.2h.2v.5h.5v.2h-.5v.6h-.2v-.6h-.6v-.2h.6zM186.2 82.6h.2l.6 1.6 .5-1.6h.3l-.7 1.9h-.3z" fill-rule="evenodd"/>
<path d="M251.9 77.5h.3l.9 1.5v-1.5h.2v1.8h-.2l-1-1.5v1.5h-.2zM254.3 78.5v.7a.33 .33 0 0 0 .3-.4 .33 .33 0 0 0-.3-.3zM253.9 77.8v.3l.3 .2v-.6zM253.8 77.6l.4-.1v-.2l.1 .2a.49 .49 0 0 1 .5 .5h-.2l-.3-.3v.6a.53 .53 0 0 1 .6 .5 .53 .53 0 0 1-.6 .6v.2h-.1v-.2l-.4-.2-.2-.3v-.1h.2l.1 .2 .3 .2v-.7a.49 .49 0 0 1-.5-.3 .49 .49 0 0 1 .1-.6zM255.2 77.6h1v.2h-.8l-.1 .5a.62 .62 0 0 1 .9 .2 .62 .62 0 0 1-.4 .9 .62 .62 0 0 1-.8-.6h.3a.39 .39 0 0 0 .5 .2 .39 .39 0 0 0 .1-.6 .39 .39 0 0 0-.6 .1h-.2z" fill-rule="evenodd"/>
<path d="M102.2 33.6h.3l.9 1.5v-1.5h.3v1.8h-.3l-1-1.4v1.4h-.2zM104.6 34.6v.7a.33 .33 0 0 0 .3-.3 .33 .33 0 0 0-.3-.4zM104.3 33.9l-.1 .3 .3 .2v-.6zM104.1 33.8l.4-.2v-.1l.1 .1a.49 .49 0 0 1 .5 .5h-.2l-.3-.3v.6a.53 .53 0 0 1 .6 .5 .53 .53 0 0 1-.6 .6v.2h-.1v-.2l-.4-.1-.2-.3v-.2h.3v.2l.3 .2v-.7a.49 .49 0 0 1-.5-.3 .49 .49 0 0 1 .1-.5zM105.5 34l.7-.3v1.7h-.3v-1.2h-.4zM107.1 34.1a.3 .3 0 0 0 .6 0 .3 .3 0 0 0-.6 0zM107 34.9a.36 .36 0 0 0 .7 0 .36 .36 0 0 0-.7 0zM107 33.8a.5 .5 0 0 1 .7-.1 .5 .5 0 0 1 0 .8 .55 .55 0 0 1 .1 .8 .55 .55 0 0 1-.8 0 .55 .55 0 0 1 .1-.8l-.3-.4z" fill-rule="evenodd"/>
<path d="M102.2 31h.3l.9 1.5v-1.5h.3v1.8h-.3l-1-1.4v1.4h-.2zM104.6 32.1v.6a.33 .33 0 0 0 .3-.3 .33 .33 0 0 0-.3-.3zM104.3 31.3l-.1 .3 .3 .2v-.6zM104.1 31.2l.4-.2v-.1l.1 .1a.49 .49 0 0 1 .5 .5h-.2l-.3-.3v.6a.53 .53 0 0 1 .6 .6 .53 .53 0 0 1-.6 .5v.2h-.1v-.2l-.4-.1-.2-.3v-.2h.3v.3l.3 .1v-.7a.49 .49 0 0 1-.5-.2 .49 .49 0 0 1 .1-.6zM105.6 31.2a.61 .61 0 0 1 1 .3 .61 .61 0 0 1-.7 .8l-.3 .3h1v.2h-1.3a1.5 1.5 0 0 1 1-1.1 .36 .36 0 0 0-.3-.4 .36 .36 0 0 0-.4 .4h-.2zM107 31.3a.64 .64 0 0 1 .7-.1 .64 .64 0 0 1 .3 .8 .66 .66 0 0 1-.6 .9 .66 .66 0 0 1-.6-.9zM107.2 31.3a.93 .93 0 0 0 .2 1.4 .86 .86 0 0 0 0-1.4z" fill-rule="evenodd"/>
<path d="M60.9 67.2h.3l.9 1.4v-1.4h.3v1.8h-.3l-.9-1.5v1.5h-.3zM63.3 68.2v.6a.33 .33 0 0 0 .4-.3 .33 .33 0 0 0-.4-.3zM63 67.5l-.1 .3 .3 .1v-.5zM62.8 67.3l.4-.1v-.2l.1 .2a.49 .49 0 0 1 .5 .5h-.2l-.3-.3v.6a.53 .53 0 0 1 .6 .5 .53 .53 0 0 1-.6 .5v.3h-.1v-.3l-.4-.1-.1-.3-.1-.2h.3v.3l.3 .1v-.6a.49 .49 0 0 1-.5-.3 .49 .49 0 0 1 .1-.6zM64.3 67.3a.51 .51 0 0 1 .7 0 .51 .51 0 0 1 0 .7 .59 .59 0 0 1-.2 1 .59 .59 0 0 1-.8-.6h.3a.36 .36 0 0 0 .5 .4 .36 .36 0 0 0 0-.6h-.3l.1-.2a.29 .29 0 0 0 .3-.3 .29 .29 0 0 0-.2-.3l-.3 .2-.1 .2h-.2zM65.7 67.3a.61 .61 0 0 1 1 .3 .61 .61 0 0 1-.6 .8l-.4 .4h1v.2h-1.2a1.5 1.5 0 0 1 .9-1.1 .36 .36 0 0 0-.3-.5 .36 .36 0 0 0-.4 .4h-.2z" fill-rule="evenodd"/>
<path d="M60.9 69.7h.3l.9 1.5v-1.5h.3v1.9h-.3l-.9-1.5v1.5h-.3zM63.3 70.8v.6a.33 .33 0 0 0 .4-.3 .33 .33 0 0 0-.4-.3zM63 70l-.1 .3 .3 .2v-.6zM62.8 69.9l.4-.1v-.2l.1 .2a.49 .49 0 0 1 .5 .4h-.2l-.3-.3v.6a.53 .53 0 0 1 .6 .6 .53 .53 0 0 1-.6 .5v.3h-.1v-.3l-.4-.1-.1-.3-.1-.2h.3v.3l.3 .1v-.7a.49 .49 0 0 1-.5-.2 .49 .49 0 0 1 .1-.6zM64.3 69.9a.51 .51 0 0 1 .7 0 .51 .51 0 0 1 0 .7 .59 .59 0 0 1-.2 1 .59 .59 0 0 1-.8-.6h.3a.36 .36 0 0 0 .5 .4 .36 .36 0 0 0 0-.6l-.3-.1 .1-.2a.29 .29 0 0 0 .3-.2 .29 .29 0 0 0-.2-.3l-.3 .1-.1 .3h-.2zM65.7 69.9a.51 .51 0 0 1 .7 0 .51 .51 0 0 1 0 .7 .59 .59 0 0 1-.1 1 .59 .59 0 0 1-.9-.6h.3a.36 .36 0 0 0 .5 .4 .36 .36 0 0 0 0-.6l-.3-.1 .1-.2a.29 .29 0 0 0 .4-.2 .29 .29 0 0 0-.3-.3l-.3 .1-.1 .3h-.2z" fill-rule="evenodd"/>
<path d="M60.9 74.9h.3l.9 1.5v-1.5h.3v1.8h-.3l-.9-1.5v1.5h-.3zM63.3 75.9v.7a.33 .33 0 0 0 .4-.3 .33 .33 0 0 0-.4-.4zM63 75.2l-.1 .3 .3 .2v-.6zM62.8 75.1l.4-.2v-.2l.1 .2a.49 .49 0 0 1 .5 .5h-.2l-.3-.3v.6a.53 .53 0 0 1 .6 .5 .53 .53 0 0 1-.6 .6v.2h-.1v-.2l-.4-.2-.1-.2-.1-.2h.3v.2l.3 .2v-.7a.49 .49 0 0 1-.5-.3 .49 .49 0 0 1 .1-.5zM64.3 75.1a.51 .51 0 0 1 .7-.1 .51 .51 0 0 1 0 .8 .59 .59 0 0 1-.2 1 .59 .59 0 0 1-.8-.6h.3a.36 .36 0 0 0 .5 .4 .36 .36 0 0 0 0-.7h-.3l.1-.2a.29 .29 0 0 0 .3-.2 .29 .29 0 0 0-.2-.4l-.3 .2-.1 .2h-.2zM66.2 75.3l-.5 .8h.5zM66.3 74.9h.2v1.2h.2v.2h-.2v.4h-.3v-.4h-.8v-.2z" fill-rule="evenodd"/>
<path d="M60.9 72.3h.3l.9 1.5v-1.5h.3v1.8h-.3l-.9-1.4v1.4h-.3zM63.3 73.4v.6a.33 .33 0 0 0 .4-.3 .33 .33 0 0 0-.4-.3zM63 72.6l-.1 .3 .3 .2v-.6zM62.8 72.5l.4-.2v-.1l.1 .1a.49 .49 0 0 1 .5 .5h-.2l-.3-.3v.6a.53 .53 0 0 1 .6 .6 .53 .53 0 0 1-.6 .5v.2h-.1v-.2l-.4-.1-.1-.3-.1-.2h.3v.2l.3 .2v-.7a.49 .49 0 0 1-.5-.3 .49 .49 0 0 1 .1-.5zM64.3 72.5a.51 .51 0 0 1 .7-.1 .51 .51 0 0 1 0 .8 .59 .59 0 0 1-.2 1 .59 .59 0 0 1-.8-.6h.3a.36 .36 0 0 0 .5 .4 .36 .36 0 0 0 0-.7h-.3l.1-.2a.29 .29 0 0 0 .3-.2 .29 .29 0 0 0-.2-.3l-.3 .1-.1 .2h-.2zM65.7 72.4h.9v.2h-.8v.5a.62 .62 0 0 1 .8 .3 .62 .62 0 0 1-.4 .8 .62 .62 0 0 1-.7-.5h.2a.39 .39 0 0 0 .6 .2 .39 .39 0 0 0 0-.6 .39 .39 0 0 0-.6 .1l-.2-.1z" fill-rule="evenodd"/>
<path d="M102.2 62h.3l.9 1.5v-1.5h.3v1.8h-.3l-1-1.5v1.5h-.2zM104.6 63v.7a.33 .33 0 0 0 .3-.3 .33 .33 0 0 0-.3-.4zM104.3 62.3l-.1 .3 .3 .2v-.6zM104.1 62.2l.4-.2v-.2l.1 .2a.49 .49 0 0 1 .5 .5h-.2l-.3-.3v.6a.53 .53 0 0 1 .6 .5 .53 .53 0 0 1-.6 .6v.2h-.1v-.2l-.4-.2-.2-.2v-.2h.3v.2l.3 .2v-.7a.49 .49 0 0 1-.5-.3 .49 .49 0 0 1 .1-.5zM105.6 62.1a.51 .51 0 0 1 .7 0 .51 .51 0 0 1 0 .8 .59 .59 0 0 1-.2 1 .59 .59 0 0 1-.8-.6h.3a.36 .36 0 0 0 .5 .4 .36 .36 0 0 0 0-.7h-.3v-.2a.29 .29 0 0 0 .4-.2 .29 .29 0 0 0-.2-.4l-.4 .2v.2h-.2zM106.8 62.1h1.2l-.7 1.7h-.3l.2-.5 .6-1h-1z" fill-rule="evenodd"/>
<path d="M102.2 64.6h.3l.9 1.5v-1.5h.3v1.8h-.3l-1-1.5v1.5h-.2zM104.6 65.6v.7a.33 .33 0 0 0 .3-.4 .33 .33 0 0 0-.3-.3zM104.3 64.9l-.1 .3 .3 .2v-.6zM104.1 64.7l.4-.1v-.2l.1 .2a.49 .49 0 0 1 .5 .5h-.2l-.3-.3v.6a.53 .53 0 0 1 .6 .5 .53 .53 0 0 1-.6 .5v.3h-.1v-.3l-.4-.1-.2-.3v-.1h.3v.2l.3 .2v-.7a.49 .49 0 0 1-.5-.3 .49 .49 0 0 1 .1-.6zM105.6 64.7a.51 .51 0 0 1 .7 0 .51 .51 0 0 1 0 .8 .59 .59 0 0 1-.2 1 .59 .59 0 0 1-.8-.6h.3a.36 .36 0 0 0 .5 .3 .36 .36 0 0 0 0-.6h-.3v-.2a.29 .29 0 0 0 .4-.2 .29 .29 0 0 0-.2-.4l-.4 .2v.2h-.2zM106.9 64.8a.69 .69 0 0 1 .9 0 .69 .69 0 0 1 .2 .9 .6 .6 0 0 1-.5 .7 .6 .6 0 0 1-.7-.4h.2a.35 .35 0 0 0 .4 .3 .35 .35 0 0 0 .3-.5v-.2a.57 .57 0 0 1-.8 0 .57 .57 0 0 1 0-.8zM107 65.2a.4 .4 0 0 0 .8 0 .4 .4 0 0 0-.8 0z" fill-rule="evenodd"/>
<path d="M174.3 103.3h1.5v.2h-.6v1.6h-.3v-1.6h-.6zM176 103.3h.3v.7h.9v-.7h.3v1.8h-.3v-.8h-.9v.8h-.3zM177.9 103.3h1.3v.2h-1.1v.6h1v.2h-1v.6h1.1v.2h-1.3zM179.8 103.5v.6h.6a.31 .31 0 0 0 .4-.3 .31 .31 0 0 0-.4-.3zM179.6 103.3a1.57 1.57 0 0 1 1.3 .1l.1 .5-.2 .3 .2 .2 .1 .7h-.3l-.1-.7-.3-.1h-.6v.8h-.2zM181.4 103.3h.3l.6 1.5 .5-1.5h.3v1.8h-.2v-1.5l-.5 1.5h-.3l-.5-1.5v1.5h-.2zM184.2 103.6l-.3 .8h.5zM184 103.3h.3l.7 1.8h-.3l-.2-.5h-.7l-.2 .5h-.3zM185.2 103.3h.2v1.6h1v.2h-1.2zM186.8 103.5a.81 .81 0 0 1 1.4 .3h-.3a.63 .63 0 0 0-.8-.3 .63 .63 0 0 0-.3 .9 .58 .58 0 0 0 .6 .5 .58 .58 0 0 0 .6-.6h-.6v-.2h.8v1h-.2v-.2a.89 .89 0 0 1-1.2 0 .89 .89 0 0 1-.2-1.2zM188.6 103.3h.3l.9 1.5v-1.5h.2v1.8h-.2l-1-1.5v1.5h-.2zM190.7 103.5v1.4h.4a.71 .71 0 0 0 .6-.7 .71 .71 0 0 0-.6-.7zM190.4 103.3h.8a.92 .92 0 0 1 .7 .9 .92 .92 0 0 1-.7 .9h-.8z" fill-rule="evenodd"/>
<path d="M102.1 36.2h1.4v.2h-.6v1.6h-.2v-1.6h-.6zM103.8 36.2h.2v.7h1v-.7h.2v1.8h-.2v-.8h-1v.8h-.2zM105.6 36.2h1.3v.2h-1v.6h1v.2h-1v.6h1.1v.2h-1.4zM107.6 36.4v.6h.5a.31 .31 0 0 0 .4-.3 .31 .31 0 0 0-.3-.3zM107.3 36.2a1.57 1.57 0 0 1 1.4 .1v.5l-.2 .3 .2 .2 .1 .7h-.3l-.1-.6-.3-.2h-.5v.8h-.3zM109.1 36.2h.4l.5 1.5 .5-1.5h.4v1.8h-.3v-1.5l-.5 1.5h-.2l-.6-1.5 .1 1.5h-.3zM111.9 36.5l-.3 .8h.6zM111.8 36.2h.2l.7 1.8h-.3l-.1-.5h-.8l-.2 .5h-.2zM112.9 36.2h.3v1.6h.9v.2h-1.2zM114.5 36.4a.81 .81 0 0 1 1.4 .3h-.2a.63 .63 0 0 0-.9-.3 .63 .63 0 0 0-.3 .9 .58 .58 0 0 0 .7 .5 .58 .58 0 0 0 .5-.6h-.6v-.2h.8v1h-.1l-.1-.2a.89 .89 0 0 1-1.2 0 .89 .89 0 0 1-.1-1.2zM116.3 36.2h.3l.9 1.5v-1.5h.3v1.8h-.3l-.9-1.5v1.5h-.3zM118.4 36.4v1.4h.5a.71 .71 0 0 0 .5-.7 .71 .71 0 0 0-.5-.7zM118.2 36.2h.7a.92 .92 0 0 1 .8 .9 .92 .92 0 0 1-.8 .9h-.7z" fill-rule="evenodd"/>
<path d="M228.5 192.3h1.5v.2h-.6v1.6h-.3v-1.6h-.6zM230.2 192.3h.3v.8h.9v-.8h.3v1.8h-.3v-.8h-.9v.8h-.3zM232.1 192.3h1.3v.2h-1.1v.6h1v.2h-1v.6h1.1v.2h-1.3zM234 192.5v.6h.6a.31 .31 0 0 0 .4-.2 .31 .31 0 0 0-.4-.4zM233.8 192.3a1.57 1.57 0 0 1 1.3 .2l.1 .5-.2 .2 .2 .2 .1 .7h-.3l-.1-.6-.3-.1h-.6v.7h-.2zM235.6 192.3h.3l.6 1.6 .5-1.6h.3v1.8h-.2v-1.5l-.5 1.5h-.3l-.5-1.5v1.5h-.2zM238.4 192.6l-.3 .8h.5zM238.2 192.3h.3l.7 1.8h-.3l-.2-.5h-.7l-.2 .5h-.3zM239.4 192.3h.2v1.6h1v.2h-1.2zM241 192.5a.81 .81 0 0 1 1.4 .4h-.3a.63 .63 0 0 0-.8-.3 .63 .63 0 0 0-.3 .8 .58 .58 0 0 0 .6 .6 .58 .58 0 0 0 .6-.6h-.6v-.2h.8v.9h-.2v-.2a.89 .89 0 0 1-1.3 .1 .89 .89 0 0 1-.1-1.3zM242.8 192.3h.3l.9 1.5v-1.5h.2v1.8h-.3l-.9-1.4v1.4h-.2zM244.9 192.5v1.4h.4a.71 .71 0 0 0 .6-.7 .71 .71 0 0 0-.6-.7zM244.6 192.3h.8a.92 .92 0 0 1 .7 .9 .92 .92 0 0 1-.7 .9h-.8z" fill-rule="evenodd"/>
<path d="M102.2 74.9h.9a.53 .53 0 0 1 .5 .5 .53 .53 0 0 1-.5 .5h-.6v.8h-.3zM102.5 75.1v.6h.5a.32 .32 0 0 0 .3-.3 .32 .32 0 0 0-.3-.3zM104.4 75.2l-.3 .8h.6zM104.2 74.9h.3l.7 1.8h-.3l-.2-.5h-.7l-.2 .5h-.2zM105.1 74.9h.3l.5 .9 .5-.9h.3l-.7 1.1v.7h-.2v-.7zM107.1 75.1a.81 .81 0 0 1 1.4 .3h-.3a.63 .63 0 0 0-.8-.3 .63 .63 0 0 0-.3 .9 .58 .58 0 0 0 .6 .6 .58 .58 0 0 0 .6-.7h-.6v-.2h.8v1h-.1l-.1-.2a.89 .89 0 0 1-1.2 0 .89 .89 0 0 1-.1-1.2zM108.9 74.9h.3l.9 1.5v-1.5h.2v1.8h-.2l-1-1.5v1.5h-.2zM111 75.1v1.4h.4a.71 .71 0 0 0 .6-.7 .71 .71 0 0 0-.6-.7zM110.7 74.9h.8a.92 .92 0 0 1 .7 .9 .92 .92 0 0 1-.7 .9h-.8z" fill-rule="evenodd"/>
<path d="M233.9 124.2a.69 .69 0 0 1 .8 0 .69 .69 0 0 1 .2 .8 .6 .6 0 0 1-.4 .8 .6 .6 0 0 1-.8-.5h.3a.35 .35 0 0 0 .4 .3 .35 .35 0 0 0 .3-.4v-.3a.57 .57 0 0 1-.8 .1 .57 .57 0 0 1 0-.8zM234 124.6a.38 .38 0 0 0 .7 0 .38 .38 0 0 0-.7 0zM235.1 123.9h.3l.5 1.6 .5-1.6h.3l-.7 1.8h-.2z" fill-rule="evenodd"/>
<path d="M233.9 126.7a.69 .69 0 0 1 .8 0 .69 .69 0 0 1 .2 .9 .6 .6 0 0 1-.4 .7 .6 .6 0 0 1-.8-.4h.3a.35 .35 0 0 0 .4 .3 .35 .35 0 0 0 .3-.4v-.3a.57 .57 0 0 1-.8 .1 .57 .57 0 0 1 0-.9zM234 127.1a.38 .38 0 0 0 .7 0 .38 .38 0 0 0-.7 0zM235.1 126.5h.3l.5 1.6 .5-1.6h.3l-.7 1.8h-.2z" fill-rule="evenodd"/>
<path d="M102.3 67.4a.69 .69 0 0 1 .8 0 .69 .69 0 0 1 .2 .8 .6 .6 0 0 1-.4 .8 .6 .6 0 0 1-.8-.5h.3a.35 .35 0 0 0 .4 .3 .35 .35 0 0 0 .2-.4l.1-.2a.57 .57 0 0 1-.9 0 .57 .57 0 0 1 .1-.8zM102.3 67.8a.4 .4 0 0 0 .8 0 .4 .4 0 0 0-.8 0zM103.5 67.2h.3l.5 1.5 .5-1.5h.3l-.7 1.8h-.2z" fill-rule="evenodd"/>
<path d="M233.8 113.6h.3l.9 1.5v-1.5h.3v1.8h-.3l-.9-1.4v1.4h-.3zM236.2 114.6v.7a.33 .33 0 0 0 .4-.3 .33 .33 0 0 0-.4-.4zM235.9 113.9l-.1 .3 .3 .2v-.6zM235.7 113.8l.4-.2v-.1l.1 .1a.49 .49 0 0 1 .5 .5h-.2l-.3-.3v.6a.53 .53 0 0 1 .6 .5 .53 .53 0 0 1-.6 .6v.2h-.1v-.2l-.4-.1-.1-.3-.1-.2h.3v.2l.3 .2v-.7a.49 .49 0 0 1-.5-.3 .49 .49 0 0 1 .1-.5zM237.2 113.8l.6-.1 .3 .3 .1 .1h-.3a.37 .37 0 0 0-.4-.3 .37 .37 0 0 0-.3 .5v.2a.59 .59 0 0 1 .9 .2 .59 .59 0 0 1-.4 .8 .59 .59 0 0 1-.7-.6v-.6zM237.2 114.9a.4 .4 0 0 0 .8 0 .4 .4 0 0 0-.8 0zM238.6 113.7h.9v.2h-.8v.5a.62 .62 0 0 1 .9 .3 .62 .62 0 0 1-.5 .8 .62 .62 0 0 1-.7-.5h.2a.39 .39 0 0 0 .6 .2 .39 .39 0 0 0 0-.6 .39 .39 0 0 0-.6 0h-.2zM240.5 114l-.5 .8h.5zM240.6 113.6h.2v1.2h.2v.2h-.2v.4h-.2v-.4h-.8v-.2zM241.4 113.8l.6-.1 .4 .3v.1h-.2a.37 .37 0 0 0-.5-.3 .37 .37 0 0 0-.2 .5l-.1 .2a.59 .59 0 0 1 1 .2 .59 .59 0 0 1-.5 .8 .59 .59 0 0 1-.7-.6l.1-.6zM241.5 114.9a.38 .38 0 0 0 .7 0 .38 .38 0 0 0-.7 0z" fill-rule="evenodd"/>
<path d="M234 134.4a.72 .72 0 0 1 1.2 .4h-.3a.42 .42 0 0 0-.4-.4 .42 .42 0 0 0-.4 .4 1.47 1.47 0 0 1 1.1 .8 .74 .74 0 0 1-.7 .5 .74 .74 0 0 1-.7-.6h.2a.48 .48 0 0 0 .5 .4 .48 .48 0 0 0 .4-.4l-.3-.2a.56 .56 0 0 1-.7-.2 .56 .56 0 0 1 .1-.7zM235.4 135.2a.95 .95 0 0 1 1.9 0 .95 .95 0 0 1-1.9 0zM235.9 134.6a.69 .69 0 0 0-.1 1.1 .69 .69 0 0 0 1.1-.2 .68 .68 0 0 0-.1-.9 .68 .68 0 0 0-.9 0zM237.5 134.2h.2v1.7h1v.2h-1.2zM239.6 134.5l-.3 .8h.5zM239.4 134.2h.3l.7 1.9h-.3l-.2-.6h-.7l-.2 .6h-.2zM240.9 134.5v.6h.6a.31 .31 0 0 0 .3-.3 .31 .31 0 0 0-.3-.3zM240.6 134.2a1.57 1.57 0 0 1 1.4 .2l.1 .5-.3 .3 .2 .2 .1 .7h-.3v-.7l-.4-.1h-.5v.8h-.3zM242.2 136.3h1.5v.1h-1.5zM243.9 134.2h.8a.53 .53 0 0 1 .5 .6 .53 .53 0 0 1-.5 .5h-.6v.8h-.2zM244.1 134.5v.6h.5a.32 .32 0 0 0 .4-.3 .32 .32 0 0 0-.4-.3zM246 134.5l-.3 .8h.6zM245.9 134.2h.3l.6 1.9h-.2l-.2-.6h-.7l-.2 .6h-.3zM247.1 134.2h.2l1 1.5v-1.5h.2v1.9h-.3l-.9-1.5v1.5h-.2zM248.9 134.2h1.3v.3h-1v.5h1v.2h-1v.7h1.1v.2h-1.4zM250.6 134.2h.2v1.7h.9v.2h-1.1zM251.8 136.3h1.4v.1h-1.4zM253.6 134.5a.81 .81 0 0 1 1.4 .3h-.3a.63 .63 0 0 0-.8-.3 .63 .63 0 0 0-.3 .9 .58 .58 0 0 0 .6 .5 .58 .58 0 0 0 .6-.6h-.6v-.2h.8v1h-.2v-.3a.89 .89 0 0 1-1.3 .1 .89 .89 0 0 1-.1-1.2zM255.4 134.2h.3l.9 1.5v-1.5h.2v1.9h-.2l-1-1.5v1.5h-.2zM257.5 134.5v1.4h.4a.71 .71 0 0 0 .6-.7 .71 .71 0 0 0-.6-.7zM257.2 134.2h.8a.92 .92 0 0 1 .7 1 .92 .92 0 0 1-.7 .9h-.8zM258.9 136.3h1.4v.1h-1.4zM260.5 134.6l.7-.3v1.8h-.3v-1.3h-.4z" fill-rule="evenodd"/>
<path d="M32.7 59.5a.72 .72 0 0 1 1.2 .4h-.3a.42 .42 0 0 0-.4-.3 .42 .42 0 0 0-.4 .4 1.47 1.47 0 0 1 1.1 .7 .74 .74 0 0 1-.7 .6 .74 .74 0 0 1-.7-.7h.2a.48 .48 0 0 0 .5 .5 .48 .48 0 0 0 .4-.5l-.3-.2a.56 .56 0 0 1-.7-.2 .56 .56 0 0 1 .1-.7zM34.1 60.3a.95 .95 0 0 1 1.9 0 .95 .95 0 0 1-1.9 0zM34.6 59.8a.69 .69 0 0 0-.1 1.1 .69 .69 0 0 0 1.1-.2 .68 .68 0 0 0-.1-.9 .68 .68 0 0 0-.9 0zM36.2 59.4h.2v1.6h1v.2h-1.2zM38.3 59.7l-.3 .8h.5zM38.1 59.4h.3l.7 1.8h-.3l-.2-.5h-.7l-.2 .5h-.2zM39.6 59.6v.6h.6a.31 .31 0 0 0 .3-.2 .31 .31 0 0 0-.3-.4zM39.3 59.4a1.57 1.57 0 0 1 1.4 .2l.1 .5-.3 .2 .2 .2 .2 .7h-.4v-.6l-.4-.1h-.5v.7h-.3zM40.9 61.4h1.5v.2h-1.5zM42.6 59.4h.8a.53 .53 0 0 1 .5 .5 .53 .53 0 0 1-.5 .6h-.6v.7h-.2zM42.8 59.6v.7h.5a.32 .32 0 0 0 .4-.4 .32 .32 0 0 0-.4-.3zM44.7 59.7l-.3 .8h.6zM44.6 59.4h.3l.6 1.8h-.2l-.2-.5h-.7l-.2 .5h-.3zM45.8 59.4h.2l1 1.5v-1.5h.2v1.8h-.3l-.9-1.4v1.4h-.2zM47.6 59.4h1.3v.2h-1v.6h1v.2h-1v.6h1.1v.2h-1.4zM49.3 59.4h.2v1.6h1v.2h-1.2zM50.5 61.4h1.4v.2h-1.4zM52.3 59.6a.81 .81 0 0 1 1.4 .4h-.3a.63 .63 0 0 0-.8-.3 .63 .63 0 0 0-.3 .8 .58 .58 0 0 0 .6 .6 .58 .58 0 0 0 .6-.6h-.6v-.2h.8v.9h-.2v-.2a.89 .89 0 0 1-1.2 .1 .89 .89 0 0 1-.2-1.3zM54.1 59.4h.3l.9 1.5v-1.5h.2v1.8h-.2l-1-1.4v1.4h-.2zM56.2 59.6v1.4h.4a.71 .71 0 0 0 .6-.7 .71 .71 0 0 0-.6-.7zM55.9 59.4h.8a.92 .92 0 0 1 .7 .9 .92 .92 0 0 1-.7 .9h-.8zM57.6 61.4h1.4v.2h-1.4zM59.2 59.8l.7-.3v1.7h-.3v-1.2h-.4z" fill-rule="evenodd"/>
<path d="M174.6 136.9a.72 .72 0 0 1 1.2 .5h-.2a.42 .42 0 0 0-.5-.4 .42 .42 0 0 0-.4 .4 1.47 1.47 0 0 1 1.2 .7 .74 .74 0 0 1-.8 .6 .74 .74 0 0 1-.7-.6h.2a.48 .48 0 0 0 .5 .4 .48 .48 0 0 0 .5-.4l-.4-.2a.56 .56 0 0 1-.6-.3 .56 .56 0 0 1 0-.7zM176.1 137.8a.94 .94 0 0 1 1.8 0 .94 .94 0 0 1-1.8 0zM176.5 137.2a.69 .69 0 0 0 0 1.1 .69 .69 0 0 0 1-.2 .68 .68 0 0 0-.1-.9 .68 .68 0 0 0-.9 0zM178.1 136.8h.3v1.6h.9v.3h-1.2zM180.2 137.1l-.3 .8h.6zM180.1 136.8h.3l.6 1.9h-.2l-.2-.6h-.8l-.1 .6h-.3zM181.5 137v.7h.6a.31 .31 0 0 0 .4-.3 .31 .31 0 0 0-.4-.4zM181.3 136.8a1.57 1.57 0 0 1 1.3 .2l.1 .5-.2 .3 .2 .2 .1 .7h-.3l-.1-.7-.3-.1h-.6v.8h-.2zM182.9 138.8h1.4v.2h-1.4zM184.5 136.8h.8a.53 .53 0 0 1 .6 .6 .53 .53 0 0 1-.6 .5h-.5v.8h-.3zM184.8 137v.7h.5a.32 .32 0 0 0 .3-.3 .32 .32 0 0 0-.3-.4zM186.7 137.1l-.3 .8h.5zM186.5 136.8h.3l.7 1.9h-.3l-.2-.6h-.7l-.2 .6h-.3zM187.7 136.8h.3l.9 1.5v-1.5h.2v1.9h-.2l-1-1.5v1.5h-.2zM189.6 136.8h1.3v.3h-1.1v.5h1v.2h-1v.6h1.1v.3h-1.3zM191.2 136.8h.3v1.6h.9v.3h-1.2zM192.4 138.8h1.5v.2h-1.5zM194.2 137a.81 .81 0 0 1 1.4 .4h-.2a.63 .63 0 0 0-.9-.3 .63 .63 0 0 0-.3 .9 .58 .58 0 0 0 .7 .5 .58 .58 0 0 0 .5-.6h-.6v-.2h.8v1h-.1l-.1-.3a.89 .89 0 0 1-1.2 .1 .89 .89 0 0 1-.1-1.3zM196 136.8h.3l.9 1.5v-1.5h.3v1.9h-.3l-.9-1.5v1.5h-.3zM198.1 137v1.4h.5a.71 .71 0 0 0 .5-.7 .71 .71 0 0 0-.5-.7zM197.9 136.8h.7a.92 .92 0 0 1 .8 .9 .92 .92 0 0 1-.8 1h-.7zM199.5 138.8h1.4v.2h-1.4zM201.2 137a.61 .61 0 0 1 1 .3 .61 .61 0 0 1-.6 .8l-.4 .3h1v.3h-1.2a1.5 1.5 0 0 1 .9-1.2 .36 .36 0 0 0-.3-.4 .36 .36 0 0 0-.3 .4h-.3z" fill-rule="evenodd"/>
<path d="M32.7 64.7a.72 .72 0 0 1 1.2 .4h-.3a.42 .42 0 0 0-.4-.4 .42 .42 0 0 0-.4 .5 1.47 1.47 0 0 1 1.1 .7 .74 .74 0 0 1-.7 .5 .74 .74 0 0 1-.7-.6h.2a.48 .48 0 0 0 .5 .4 .48 .48 0 0 0 .4-.4l-.3-.2a.56 .56 0 0 1-.7-.2 .56 .56 0 0 1 .1-.7zM34.1 65.5a.95 .95 0 0 1 1.9 0 .95 .95 0 0 1-1.9 0zM34.6 64.9a.69 .69 0 0 0-.1 1.1 .69 .69 0 0 0 1.1-.2 .68 .68 0 0 0-.1-.9 .68 .68 0 0 0-.9 0zM36.2 64.6h.2v1.6h1v.2h-1.2zM38.3 64.8l-.3 .8h.5zM38.1 64.6h.3l.7 1.8h-.3l-.2-.5h-.7l-.2 .5h-.2zM39.6 64.8v.6h.6a.31 .31 0 0 0 .3-.3 .31 .31 0 0 0-.3-.3zM39.3 64.6a1.57 1.57 0 0 1 1.4 .1l.1 .5-.3 .3 .2 .2 .2 .7h-.4v-.7l-.4-.1h-.5v.8h-.3zM40.9 66.6h1.5v.1h-1.5zM42.6 64.6h.8a.53 .53 0 0 1 .5 .5 .53 .53 0 0 1-.5 .5h-.6v.8h-.2zM42.8 64.8v.6h.5a.32 .32 0 0 0 .4-.3 .32 .32 0 0 0-.4-.3zM44.7 64.8l-.3 .8h.6zM44.6 64.6h.3l.6 1.8h-.2l-.2-.5h-.7l-.2 .5h-.3zM45.8 64.6h.2l1 1.5v-1.5h.2v1.8h-.3l-.9-1.5v1.5h-.2zM47.6 64.6h1.3v.2h-1v.6h1v.2h-1v.6h1.1v.2h-1.4zM49.3 64.6h.2v1.6h1v.2h-1.2zM50.5 66.6h1.4v.1h-1.4zM52.3 64.8a.81 .81 0 0 1 1.4 .3h-.3a.63 .63 0 0 0-.8-.3 .63 .63 0 0 0-.3 .9 .58 .58 0 0 0 .6 .5 .58 .58 0 0 0 .6-.6h-.6v-.2h.8v1h-.2v-.2a.89 .89 0 0 1-1.2 0 .89 .89 0 0 1-.2-1.2zM54.1 64.6h.3l.9 1.5v-1.5h.2v1.8h-.2l-1-1.5v1.5h-.2zM56.2 64.8v1.4h.4a.71 .71 0 0 0 .6-.7 .71 .71 0 0 0-.6-.7zM55.9 64.6h.8a.92 .92 0 0 1 .7 .9 .92 .92 0 0 1-.7 .9h-.8zM57.6 66.6h1.4v.1h-1.4zM59.3 64.7a.61 .61 0 0 1 1 .3 .61 .61 0 0 1-.7 .8l-.3 .4h1v.2h-1.2a1.5 1.5 0 0 1 .9-1.1 .36 .36 0 0 0-.3-.5 .36 .36 0 0 0-.4 .5h-.2z" fill-rule="evenodd"/>
<path d="M234.1 111.2v.6h.4a.3 .3 0 0 0 .4-.3 .3 .3 0 0 0-.4-.3zM234.1 112v.6l.8-.1 .1-.2-.2-.3zM233.8 111h.8a.45 .45 0 0 1 .5 .3 .45 .45 0 0 1-.2 .6 .51 .51 0 0 1 .3 .6 .51 .51 0 0 1-.6 .3h-.8zM236.2 111.3l-.3 .8h.6zM236.1 111h.2l.7 1.8h-.3l-.2-.5h-.7l-.2 .5h-.2zM236.9 111h1.5v.2h-.7v1.6h-.2v-1.6h-.6zM238.4 111h1.5v.2h-.6v1.6h-.3v-1.6h-.6zM240.2 111h1.3v.2h-1.1v.6h1v.2h-1v.6h1.1v.2h-1.3zM242.1 111.2v.7h.6a.31 .31 0 0 0 .3-.3 .31 .31 0 0 0-.3-.4zM241.9 111a1.57 1.57 0 0 1 1.3 .2l.1 .5-.3 .3 .2 .2 .2 .6h-.3l-.1-.6-.3-.1h-.6v.7h-.2zM243.5 111h.3l.5 .9 .5-.9h.3l-.7 1.1v.7h-.2v-.7zM245.1 113h1.4v.2h-1.4zM246.6 111h1.4v.2h-.6v1.6h-.2v-1.6h-.6zM248.3 111h.2v.8h1v-.8h.2v1.8h-.2v-.8h-1v.8h-.2zM250.1 111h1.4v.2h-1.1v.6h1v.2h-1v.6h1.1v.2h-1.4zM252.1 111.2v.7h.5a.31 .31 0 0 0 .4-.3 .31 .31 0 0 0-.3-.4zM251.8 111a1.57 1.57 0 0 1 1.4 .2l.1 .5-.3 .3 .2 .2 .1 .6h-.3v-.6l-.4-.1h-.5v.7h-.3zM253.6 111h.4l.5 1.6 .5-1.6h.4v1.8h-.3v-1.5l-.5 1.5h-.2l-.5-1.5v1.5h-.3zM255.9 111.1a.72 .72 0 0 1 1.2 .5h-.3a.42 .42 0 0 0-.4-.4 .42 .42 0 0 0-.4 .4 1.47 1.47 0 0 1 1.1 .7 .74 .74 0 0 1-.7 .6 .74 .74 0 0 1-.7-.6h.2a.48 .48 0 0 0 .5 .4 .48 .48 0 0 0 .5-.5l-.4-.1a.56 .56 0 0 1-.7-.3 .56 .56 0 0 1 .1-.7zM257.3 111h1.5v.2h-.6v1.6h-.3v-1.6h-.6zM258.8 112a.95 .95 0 0 1 1.9 0 .95 .95 0 0 1-1.9 0zM259.3 111.4a.69 .69 0 0 0 0 1.1 .69 .69 0 0 0 1-.2 .68 .68 0 0 0-.1-.9 .68 .68 0 0 0-.9 0zM261.2 111.2v.7h.6a.31 .31 0 0 0 .4-.3 .31 .31 0 0 0-.4-.4zM261 111a1.57 1.57 0 0 1 1.3 .2l.1 .5-.3 .3 .2 .2 .2 .6h-.3l-.1-.6-.3-.1h-.6v.7h-.2zM262.6 113h1.4v.2h-1.4zM264.3 111.2a.61 .61 0 0 1 1 .3 .61 .61 0 0 1-.6 .8l-.4 .3h1v.2h-1.2a1.5 1.5 0 0 1 .9-1.1 .36 .36 0 0 0-.3-.4 .36 .36 0 0 0-.4 .4h-.2zM266 111.6h.3v.5h.5v.2h-.5v.5h-.3v-.5h-.5v-.2h.5z" fill-rule="evenodd"/>
</g>
<g fill="none" stroke="#800000" stroke-width=".28">
<path d="M73.6 17.4h15.5v23.2h-15.5zM205.3 17.4h12.8v69.6h-12.8zM149.8 39.3v5.2l-1.3-1.3 1.3-1.3-1.3-1.3zM73.6 56.1h15.5v23.2h-15.5zM149.8 54.8v2.6l-1.3-1.3zM259.4 54.8l1.3 1.3-1.3 1.3 1.3 1.3-1.3 1.2zM266.5 62.5l2 1.3-2 1.3 2 1.3-2 1.3M205.3 97.4h12.8v69.6h-12.8zM50.4 123.2h61.9v41.3h-61.9zM122.7 138.6h5.1M122.7 136.8l1.5 .7 1 .1M125.2 125.8l1.3 1.2h-2.5z"/>
<path d="M127.7 136.8l-.9 .5-1.6 .3M36.2 142.5v2.6l-1.3-1.3zM51.7 172.2h2.6l-1.3 1.3zM209.8 190.8h1.1l4.2 4.1M210.4 191.8h5.2v2.1h-5.2z"/>
</g>
<g fill="none" stroke="#800000" stroke-width=".2">
<path d="M68.5 19.9h5.1M89.1 19.9h5.2M200.1 19.9h5.2M218.1 19.9h5.2M68.5 22.5h5.1M68.5 25.1h5.1M68.5 27.7h5.1M68.5 30.3h5.1M68.5 32.9h5.1M68.5 35.4h5.1M68.5 38h5.1M89.1 22.5h5.2"/>
<path d="M89.1 25.1h5.2M89.1 27.7h5.2M89.1 30.3h5.2M89.1 32.9h5.2M89.1 35.4h5.2M89.1 38h5.2M200.1 22.5h5.2M200.1 25.1h5.2M200.1 27.7h5.2M200.1 30.3h5.2M200.1 32.9h5.2M200.1 35.4h5.2"/>
<path d="M200.1 38h5.2M218.1 22.5h5.2M218.1 25.1h5.2M218.1 27.7h5.2M218.1 30.3h5.2M218.1 32.9h5.2M218.1 35.4h5.2M218.1 38h5.2M68.5 58.7h5.1M89.1 58.7h5.2M149.8 40.6h2.5M149.8 43.2h2.5"/>
<path d="M149.8 56.1h2.5M200.1 40.6h5.2M200.1 43.2h5.2M200.1 45.8h5.2M200.1 48.3h5.2M200.1 50.9h5.2M200.1 53.5h5.2M200.1 56.1h5.2M200.1 58.7h5.2M218.1 40.6h5.2M218.1 43.2h5.2M218.1 45.8h5.2"/>
<path d="M218.1 48.3h5.2M218.1 50.9h5.2M218.1 53.5h5.2M218.1 56.1h5.2M218.1 58.7h5.2M256.9 56.1h2.5M256.9 58.7h2.5M68.5 61.2h5.1M68.5 63.8h5.1M68.5 66.4h5.1M68.5 69h5.1M68.5 71.6h5.1"/>
<path d="M68.5 74.1h5.1M68.5 76.7h5.1M89.1 61.2h5.2M89.1 63.8h5.2M89.1 66.4h5.2M89.1 69h5.2M89.1 71.6h5.2M89.1 74.1h5.2M89.1 76.7h5.2M200.1 61.2h5.2M200.1 63.8h5.2M200.1 66.4h5.2"/>
<path d="M200.1 69h5.2M200.1 71.6h5.2M200.1 74.1h5.2M200.1 76.7h5.2M200.1 79.3h5.2M218.1 61.2h5.2M218.1 63.8h5.2M218.1 66.4h5.2M218.1 69h5.2M218.1 71.6h5.2M218.1 74.1h5.2M218.1 76.7h5.2"/>
<path d="M218.1 79.3h5.2M265.9 63.8h2.6M265.9 66.4h2.6M16.8 94.8h2.6M16.8 89.6h2.6M24.6 94.8h2.6M24.6 89.6h2.6M200.1 81.9h5.2M200.1 84.5h5.2M200.1 99.9h5.2M218.1 81.9h5.2M218.1 84.5h5.2"/>
<path d="M218.1 99.9h5.2M16.8 115.4h2.6M16.8 110.3h2.6M24.6 115.4h2.6M24.6 110.3h2.6M71.1 118v5.2M76.2 118v5.2M81.4 118v5.2M86.5 118v5.2M94.3 118v5.2M99.4 118v5.2M104.6 118v5.2"/>
<path d="M109.8 118v5.2M200.1 115.4h5.2M200.1 110.3h5.2M200.1 102.5h5.2M200.1 105.1h5.2M200.1 107.7h5.2M200.1 112.8h5.2M200.1 118h5.2M218.1 115.4h5.2M218.1 110.3h5.2M218.1 102.5h5.2M218.1 105.1h5.2"/>
<path d="M218.1 107.7h5.2M218.1 112.8h5.2M218.1 118h5.2M125.2 127v2.6M125.2 133.5v4.1M125.2 138.6v2.6M200.1 120.6h5.2M200.1 123.2h5.2M200.1 125.8h5.2M200.1 128.3h5.2M200.1 130.9h5.2M200.1 133.5h5.2"/>
<path d="M200.1 136.1h5.2M200.1 138.6h5.2M218.1 120.6h5.2M218.1 123.2h5.2M218.1 125.8h5.2M218.1 128.3h5.2M218.1 130.9h5.2M218.1 133.5h5.2M218.1 136.1h5.2M218.1 138.6h5.2M36.2 143.8h2.6M45.2 143.8h5.2"/>
<path d="M112.3 143.8h5.2M200.1 143.8h5.2M200.1 141.2h5.2M200.1 146.4h5.2M200.1 149h5.2M200.1 151.6h5.2M200.1 154.1h5.2M200.1 156.7h5.2M200.1 159.3h5.2M218.1 143.8h5.2M218.1 141.2h5.2M218.1 146.4h5.2"/>
<path d="M218.1 149h5.2M218.1 151.6h5.2M218.1 154.1h5.2M218.1 156.7h5.2M218.1 159.3h5.2M53 164.5v7.7M58.1 164.5v5.1M63.3 164.5v5.1M71.1 164.5v5.1M76.2 164.5v5.1M81.4 164.5v5.1M86.5 164.5v5.1"/>
<path d="M102 164.5v5.1M107.2 164.5v5.1M200.1 161.9h5.2M200.1 164.5h5.2M218.1 161.9h5.2M218.1 164.5h5.2M207.8 192.8h2.6M215.6 192.8h2.5"/>
</g>
<path d="M19.4 94.8l.3-1.1 .6 2.1 .7-2.1 .6 2.1 .7-2.1 .6 2.1 .7-2.1 .6 2.1 .4-1M19.4 89.6l.3-1 .6 2.1 .7-2.1 .6 2.1 .7-2.1 .6 2.1 .7-2.1 .6 2.1 .4-1.1M19.4 115.4l.3-1 .6 2.1 .7-2.1 .6 2.1 .7-2.1 .6 2.1 .7-2.1 .6 2.1 .4-1.1M19.4 110.3l.3-1.1 .6 2.1 .7-2.1 .6 2.1 .7-2.1 .6 2.1 .7-2.1 .6 2.1 .4-1" fill="none" stroke="#800000" stroke-width=".21"/>
<g fill="none" stroke="#008000" stroke-width=".2">
<path d="M58.1 19.9h10.4M94.3 19.9h10.3M156.2 19.9h43.9M223.3 19.9h31M58.1 38h10.4M58.1 22.5h10.4M58.1 25.1h10.4M58.1 30.3h10.4M58.1 32.9h10.4M58.1 27.7h10.4M58.1 35.4h10.4M94.3 38h10.3"/>
<path d="M94.3 22.5h10.3M94.3 25.1h10.3M94.3 30.3h10.3M94.3 32.9h10.3M94.3 27.7h12.9M94.3 35.4h10.3M156.2 38h43.9M156.2 22.5h43.9M156.2 25.1h43.9M156.2 30.3h43.9M156.2 32.9h43.9M156.2 27.7h43.9"/>
<path d="M156.2 35.4h43.9M223.3 38h33.6M223.3 22.5h31M223.3 25.1h31M223.3 30.3h33.6M223.3 32.9h32.3M223.3 27.7h33.6M223.3 35.4h33.6M60.7 58.7h7.8M94.3 58.7h7.7M152.3 40.6h47.8M152.3 43.2h47.8"/>
<path d="M152.3 56.1h47.8M156.2 48.3h43.9M156.2 45.8h43.9M156.2 58.7h43.9M156.2 53.5h43.9M157.5 50.9h42.6M223.3 48.3h33.6M223.3 40.6h33.6M223.3 43.2h33.6M223.3 45.8h33.6M223.3 50.9h33.6M223.3 56.1h33.6"/>
<path d="M223.3 58.7h33.6M223.3 53.5h33.6M60.7 66.4h7.8M60.7 61.2h7.8M60.7 74.1h7.8M60.7 63.8h7.8M60.7 76.7h7.8M60.7 71.6h7.8M60.7 69h7.8M94.3 66.4h10.3M94.3 61.2h10.3M94.3 74.1h10.3"/>
<path d="M94.3 63.8h7.7M94.3 76.7h10.3M94.3 71.6h10.3M94.3 69h10.3M156.2 79.3h43.9M156.2 66.4h43.9M156.2 61.2h43.9M156.2 74.1h43.9M156.2 63.8h43.9M156.2 71.6h43.9M156.2 69h43.9M157.5 76.7h42.6"/>
<path d="M223.3 79.3h36.1M223.3 66.4h42.6M223.3 61.2h31M223.3 74.1h36.1M223.3 63.8h42.6M223.3 76.7h34.8M223.3 71.6h34.8M223.3 69h34.8M9.1 92.2h7.7M16.8 89.6v5.2M27.2 94.8h5.1M27.2 89.6h5.1"/>
<path d="M76.2 94.8v23.2M86.5 94.8v23.2M156.2 81.9h43.9M156.2 84.5h43.9M164 99.9h36.1M223.3 81.9h36.1M223.3 99.9h33.6M223.3 84.5h36.1M9.1 112.8h7.7M16.8 110.3v5.1M27.2 115.4h5.1M27.2 110.3h5.1"/>
<path d="M164 102.5h36.1M171.7 118h28.4M171.7 115.4h28.4M171.7 110.3h28.4M171.7 112.8h28.4M171.7 107.7h28.4M171.7 105.1h28.4M223.3 118h46.5M223.3 115.4h46.5M223.3 110.3h31M223.3 112.8h46.5M223.3 102.5h31"/>
<path d="M223.3 107.7h31M223.3 105.1h31M125.2 129.6v3.9M171.7 133.5h28.4M171.7 128.3h28.4M171.7 123.2h28.4M171.7 130.9h28.4M171.7 138.6h28.4M171.7 120.6h28.4M171.7 136.1h28.4M171.7 125.8h28.4M223.3 133.5h38.7"/>
<path d="M223.3 128.3h46.5M223.3 123.2h45.2M223.3 130.9h45.2M223.3 138.6h38.7M223.3 120.6h46.5M223.3 136.1h38.7M223.3 125.8h46.5M38.8 143.8h6.4M117.5 143.8h25.8M125.2 141.2v2.6M171.7 143.8h28.4M171.7 151.6h28.4"/>
<path d="M171.7 156.7h28.4M171.7 159.3h28.4M171.7 154.1h28.4M171.7 141.2h28.4M171.7 146.4h28.4M171.7 149h28.4M223.3 143.8h41.3M223.3 151.6h41.3M223.3 156.7h40M223.3 159.3h40M223.3 154.1h41.3M223.3 141.2h38.7"/>
<path d="M223.3 146.4h41.3M223.3 149h41.3M76.2 169.6v23.2M86.5 169.6v23.2M171.7 161.9h28.4M171.7 164.5h28.4M223.3 161.9h40M223.3 164.5h40M200.1 192.8h7.7M218.1 192.8h10.4"/>
</g>
<g fill="#008000" stroke="#008000" stroke-width=".2">
<circle cx="125.2" cy="143.8" r=".51"/>
<circle cx="16.8" cy="112.8" r=".51"/>
<circle cx="16.8" cy="92.2" r=".51"/>
</g>
</svg>
